VERSION 5.8 ;
BUSBITCHARS "[]" ;
DIVIDERCHAR "/" ;
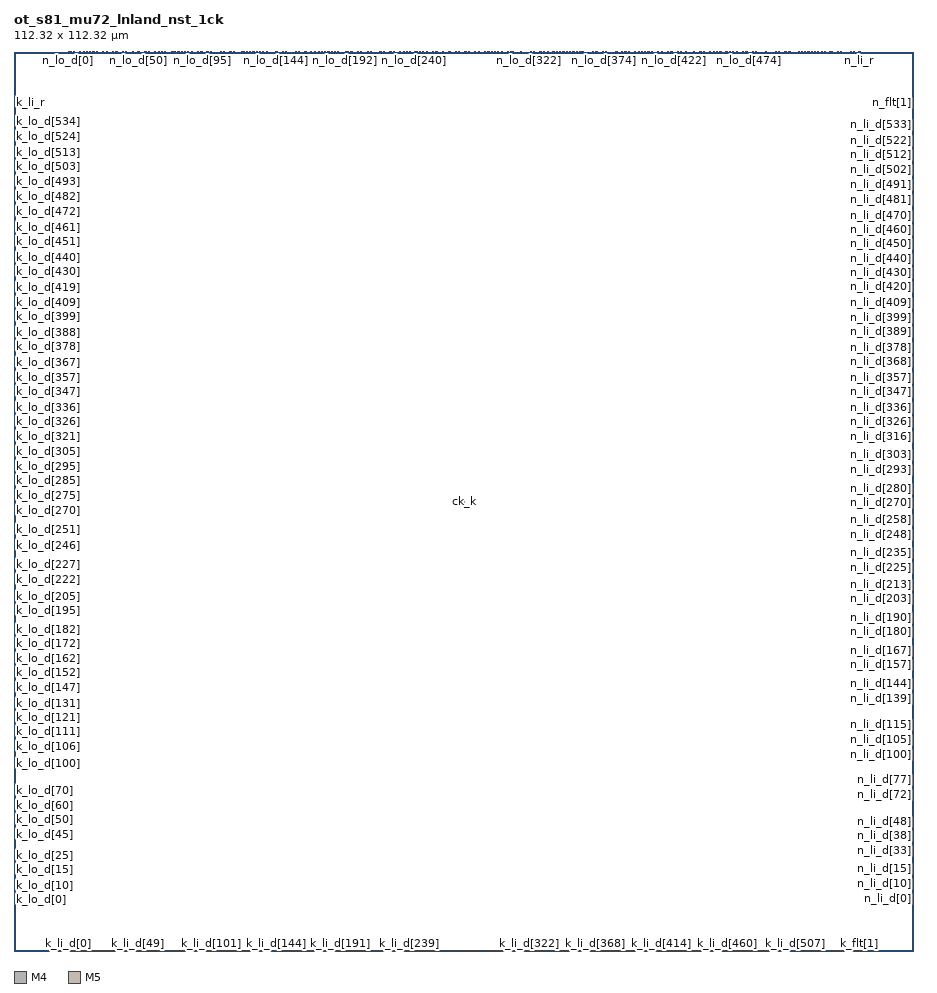
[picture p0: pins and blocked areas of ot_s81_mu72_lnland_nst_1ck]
MACRO ot_s81_mu72_lnland_nst_1ck
 CLASS BLOCK ;
 ORIGIN 0 0 ;
 SIZE 112.32 BY 112.32 ;
 SYMMETRY X Y ;
 PIN k_lo_v
  DIRECTION INPUT ;
  USE SIGNAL ;
  PORT
   LAYER M4 ;
   RECT 0.000000 6.236000 0.084000 6.268000 ;
  END
 END k_lo_v
 PIN k_lo_d[0]
  DIRECTION INPUT ;
  USE SIGNAL ;
  PORT
   LAYER M4 ;
   RECT 0.000000 6.380000 0.084000 6.412000 ;
  END
 END k_lo_d[0]
 PIN k_lo_d[1]
  DIRECTION INPUT ;
  USE SIGNAL ;
  PORT
   LAYER M4 ;
   RECT 0.000000 6.572000 0.084000 6.604000 ;
  END
 END k_lo_d[1]
 PIN k_lo_d[2]
  DIRECTION INPUT ;
  USE SIGNAL ;
  PORT
   LAYER M4 ;
   RECT 0.000000 6.764000 0.084000 6.796000 ;
  END
 END k_lo_d[2]
 PIN k_lo_d[3]
  DIRECTION INPUT ;
  USE SIGNAL ;
  PORT
   LAYER M4 ;
   RECT 0.000000 6.956000 0.084000 6.988000 ;
  END
 END k_lo_d[3]
 PIN k_lo_d[4]
  DIRECTION INPUT ;
  USE SIGNAL ;
  PORT
   LAYER M4 ;
   RECT 0.000000 7.100000 0.084000 7.132000 ;
  END
 END k_lo_d[4]
 PIN k_lo_d[5]
  DIRECTION INPUT ;
  USE SIGNAL ;
  PORT
   LAYER M4 ;
   RECT 0.000000 7.292000 0.084000 7.324000 ;
  END
 END k_lo_d[5]
 PIN k_lo_d[6]
  DIRECTION INPUT ;
  USE SIGNAL ;
  PORT
   LAYER M4 ;
   RECT 0.000000 7.484000 0.084000 7.516000 ;
  END
 END k_lo_d[6]
 PIN k_lo_d[7]
  DIRECTION INPUT ;
  USE SIGNAL ;
  PORT
   LAYER M4 ;
   RECT 0.000000 7.676000 0.084000 7.708000 ;
  END
 END k_lo_d[7]
 PIN k_lo_d[8]
  DIRECTION INPUT ;
  USE SIGNAL ;
  PORT
   LAYER M4 ;
   RECT 0.000000 7.820000 0.084000 7.852000 ;
  END
 END k_lo_d[8]
 PIN k_lo_d[9]
  DIRECTION INPUT ;
  USE SIGNAL ;
  PORT
   LAYER M4 ;
   RECT 0.000000 8.012000 0.084000 8.044000 ;
  END
 END k_lo_d[9]
 PIN k_lo_d[10]
  DIRECTION INPUT ;
  USE SIGNAL ;
  PORT
   LAYER M4 ;
   RECT 0.000000 8.204000 0.084000 8.236000 ;
  END
 END k_lo_d[10]
 PIN k_lo_d[11]
  DIRECTION INPUT ;
  USE SIGNAL ;
  PORT
   LAYER M4 ;
   RECT 0.000000 8.396000 0.084000 8.428000 ;
  END
 END k_lo_d[11]
 PIN k_lo_d[12]
  DIRECTION INPUT ;
  USE SIGNAL ;
  PORT
   LAYER M4 ;
   RECT 0.000000 8.540000 0.084000 8.572000 ;
  END
 END k_lo_d[12]
 PIN k_lo_d[13]
  DIRECTION INPUT ;
  USE SIGNAL ;
  PORT
   LAYER M4 ;
   RECT 0.000000 8.732000 0.084000 8.764000 ;
  END
 END k_lo_d[13]
 PIN k_lo_d[14]
  DIRECTION INPUT ;
  USE SIGNAL ;
  PORT
   LAYER M4 ;
   RECT 0.000000 8.924000 0.084000 8.956000 ;
  END
 END k_lo_d[14]
 PIN k_lo_d[15]
  DIRECTION INPUT ;
  USE SIGNAL ;
  PORT
   LAYER M4 ;
   RECT 0.000000 9.116000 0.084000 9.148000 ;
  END
 END k_lo_d[15]
 PIN k_lo_d[16]
  DIRECTION INPUT ;
  USE SIGNAL ;
  PORT
   LAYER M4 ;
   RECT 0.000000 9.260000 0.084000 9.292000 ;
  END
 END k_lo_d[16]
 PIN k_lo_d[17]
  DIRECTION INPUT ;
  USE SIGNAL ;
  PORT
   LAYER M4 ;
   RECT 0.000000 9.452000 0.084000 9.484000 ;
  END
 END k_lo_d[17]
 PIN k_lo_d[18]
  DIRECTION INPUT ;
  USE SIGNAL ;
  PORT
   LAYER M4 ;
   RECT 0.000000 9.644000 0.084000 9.676000 ;
  END
 END k_lo_d[18]
 PIN k_lo_d[19]
  DIRECTION INPUT ;
  USE SIGNAL ;
  PORT
   LAYER M4 ;
   RECT 0.000000 9.836000 0.084000 9.868000 ;
  END
 END k_lo_d[19]
 PIN k_lo_d[20]
  DIRECTION INPUT ;
  USE SIGNAL ;
  PORT
   LAYER M4 ;
   RECT 0.000000 9.980000 0.084000 10.012000 ;
  END
 END k_lo_d[20]
 PIN k_lo_d[21]
  DIRECTION INPUT ;
  USE SIGNAL ;
  PORT
   LAYER M4 ;
   RECT 0.000000 10.172000 0.084000 10.204000 ;
  END
 END k_lo_d[21]
 PIN k_lo_d[22]
  DIRECTION INPUT ;
  USE SIGNAL ;
  PORT
   LAYER M4 ;
   RECT 0.000000 10.364000 0.084000 10.396000 ;
  END
 END k_lo_d[22]
 PIN k_lo_d[23]
  DIRECTION INPUT ;
  USE SIGNAL ;
  PORT
   LAYER M4 ;
   RECT 0.000000 10.556000 0.084000 10.588000 ;
  END
 END k_lo_d[23]
 PIN k_lo_d[24]
  DIRECTION INPUT ;
  USE SIGNAL ;
  PORT
   LAYER M4 ;
   RECT 0.000000 10.700000 0.084000 10.732000 ;
  END
 END k_lo_d[24]
 PIN k_lo_d[25]
  DIRECTION INPUT ;
  USE SIGNAL ;
  PORT
   LAYER M4 ;
   RECT 0.000000 10.892000 0.084000 10.924000 ;
  END
 END k_lo_d[25]
 PIN k_lo_d[26]
  DIRECTION INPUT ;
  USE SIGNAL ;
  PORT
   LAYER M4 ;
   RECT 0.000000 11.084000 0.084000 11.116000 ;
  END
 END k_lo_d[26]
 PIN k_lo_d[27]
  DIRECTION INPUT ;
  USE SIGNAL ;
  PORT
   LAYER M4 ;
   RECT 0.000000 11.276000 0.084000 11.308000 ;
  END
 END k_lo_d[27]
 PIN k_lo_d[28]
  DIRECTION INPUT ;
  USE SIGNAL ;
  PORT
   LAYER M4 ;
   RECT 0.000000 11.420000 0.084000 11.452000 ;
  END
 END k_lo_d[28]
 PIN k_lo_d[29]
  DIRECTION INPUT ;
  USE SIGNAL ;
  PORT
   LAYER M4 ;
   RECT 0.000000 11.612000 0.084000 11.644000 ;
  END
 END k_lo_d[29]
 PIN k_lo_d[30]
  DIRECTION INPUT ;
  USE SIGNAL ;
  PORT
   LAYER M4 ;
   RECT 0.000000 11.804000 0.084000 11.836000 ;
  END
 END k_lo_d[30]
 PIN k_lo_d[31]
  DIRECTION INPUT ;
  USE SIGNAL ;
  PORT
   LAYER M4 ;
   RECT 0.000000 11.996000 0.084000 12.028000 ;
  END
 END k_lo_d[31]
 PIN k_lo_d[32]
  DIRECTION INPUT ;
  USE SIGNAL ;
  PORT
   LAYER M4 ;
   RECT 0.000000 12.140000 0.084000 12.172000 ;
  END
 END k_lo_d[32]
 PIN k_lo_d[33]
  DIRECTION INPUT ;
  USE SIGNAL ;
  PORT
   LAYER M4 ;
   RECT 0.000000 12.332000 0.084000 12.364000 ;
  END
 END k_lo_d[33]
 PIN k_lo_d[34]
  DIRECTION INPUT ;
  USE SIGNAL ;
  PORT
   LAYER M4 ;
   RECT 0.000000 12.524000 0.084000 12.556000 ;
  END
 END k_lo_d[34]
 PIN k_lo_d[35]
  DIRECTION INPUT ;
  USE SIGNAL ;
  PORT
   LAYER M4 ;
   RECT 0.000000 12.716000 0.084000 12.748000 ;
  END
 END k_lo_d[35]
 PIN k_lo_d[36]
  DIRECTION INPUT ;
  USE SIGNAL ;
  PORT
   LAYER M4 ;
   RECT 0.000000 12.860000 0.084000 12.892000 ;
  END
 END k_lo_d[36]
 PIN k_lo_d[37]
  DIRECTION INPUT ;
  USE SIGNAL ;
  PORT
   LAYER M4 ;
   RECT 0.000000 13.052000 0.084000 13.084000 ;
  END
 END k_lo_d[37]
 PIN k_lo_d[38]
  DIRECTION INPUT ;
  USE SIGNAL ;
  PORT
   LAYER M4 ;
   RECT 0.000000 13.244000 0.084000 13.276000 ;
  END
 END k_lo_d[38]
 PIN k_lo_d[39]
  DIRECTION INPUT ;
  USE SIGNAL ;
  PORT
   LAYER M4 ;
   RECT 0.000000 13.436000 0.084000 13.468000 ;
  END
 END k_lo_d[39]
 PIN k_lo_d[40]
  DIRECTION INPUT ;
  USE SIGNAL ;
  PORT
   LAYER M4 ;
   RECT 0.000000 13.580000 0.084000 13.612000 ;
  END
 END k_lo_d[40]
 PIN k_lo_d[41]
  DIRECTION INPUT ;
  USE SIGNAL ;
  PORT
   LAYER M4 ;
   RECT 0.000000 13.772000 0.084000 13.804000 ;
  END
 END k_lo_d[41]
 PIN k_lo_d[42]
  DIRECTION INPUT ;
  USE SIGNAL ;
  PORT
   LAYER M4 ;
   RECT 0.000000 13.964000 0.084000 13.996000 ;
  END
 END k_lo_d[42]
 PIN k_lo_d[43]
  DIRECTION INPUT ;
  USE SIGNAL ;
  PORT
   LAYER M4 ;
   RECT 0.000000 14.156000 0.084000 14.188000 ;
  END
 END k_lo_d[43]
 PIN k_lo_d[44]
  DIRECTION INPUT ;
  USE SIGNAL ;
  PORT
   LAYER M4 ;
   RECT 0.000000 14.300000 0.084000 14.332000 ;
  END
 END k_lo_d[44]
 PIN k_lo_d[45]
  DIRECTION INPUT ;
  USE SIGNAL ;
  PORT
   LAYER M4 ;
   RECT 0.000000 14.492000 0.084000 14.524000 ;
  END
 END k_lo_d[45]
 PIN k_lo_d[46]
  DIRECTION INPUT ;
  USE SIGNAL ;
  PORT
   LAYER M4 ;
   RECT 0.000000 14.684000 0.084000 14.716000 ;
  END
 END k_lo_d[46]
 PIN k_lo_d[47]
  DIRECTION INPUT ;
  USE SIGNAL ;
  PORT
   LAYER M4 ;
   RECT 0.000000 14.876000 0.084000 14.908000 ;
  END
 END k_lo_d[47]
 PIN k_lo_d[48]
  DIRECTION INPUT ;
  USE SIGNAL ;
  PORT
   LAYER M4 ;
   RECT 0.000000 15.020000 0.084000 15.052000 ;
  END
 END k_lo_d[48]
 PIN k_lo_d[49]
  DIRECTION INPUT ;
  USE SIGNAL ;
  PORT
   LAYER M4 ;
   RECT 0.000000 15.212000 0.084000 15.244000 ;
  END
 END k_lo_d[49]
 PIN k_lo_d[50]
  DIRECTION INPUT ;
  USE SIGNAL ;
  PORT
   LAYER M4 ;
   RECT 0.000000 15.404000 0.084000 15.436000 ;
  END
 END k_lo_d[50]
 PIN k_lo_d[51]
  DIRECTION INPUT ;
  USE SIGNAL ;
  PORT
   LAYER M4 ;
   RECT 0.000000 15.596000 0.084000 15.628000 ;
  END
 END k_lo_d[51]
 PIN k_lo_d[52]
  DIRECTION INPUT ;
  USE SIGNAL ;
  PORT
   LAYER M4 ;
   RECT 0.000000 15.740000 0.084000 15.772000 ;
  END
 END k_lo_d[52]
 PIN k_lo_d[53]
  DIRECTION INPUT ;
  USE SIGNAL ;
  PORT
   LAYER M4 ;
   RECT 0.000000 15.932000 0.084000 15.964000 ;
  END
 END k_lo_d[53]
 PIN k_lo_d[54]
  DIRECTION INPUT ;
  USE SIGNAL ;
  PORT
   LAYER M4 ;
   RECT 0.000000 16.124000 0.084000 16.156000 ;
  END
 END k_lo_d[54]
 PIN k_lo_d[55]
  DIRECTION INPUT ;
  USE SIGNAL ;
  PORT
   LAYER M4 ;
   RECT 0.000000 16.316000 0.084000 16.348000 ;
  END
 END k_lo_d[55]
 PIN k_lo_d[56]
  DIRECTION INPUT ;
  USE SIGNAL ;
  PORT
   LAYER M4 ;
   RECT 0.000000 16.460000 0.084000 16.492000 ;
  END
 END k_lo_d[56]
 PIN k_lo_d[57]
  DIRECTION INPUT ;
  USE SIGNAL ;
  PORT
   LAYER M4 ;
   RECT 0.000000 16.652000 0.084000 16.684000 ;
  END
 END k_lo_d[57]
 PIN k_lo_d[58]
  DIRECTION INPUT ;
  USE SIGNAL ;
  PORT
   LAYER M4 ;
   RECT 0.000000 16.844000 0.084000 16.876000 ;
  END
 END k_lo_d[58]
 PIN k_lo_d[59]
  DIRECTION INPUT ;
  USE SIGNAL ;
  PORT
   LAYER M4 ;
   RECT 0.000000 17.036000 0.084000 17.068000 ;
  END
 END k_lo_d[59]
 PIN k_lo_d[60]
  DIRECTION INPUT ;
  USE SIGNAL ;
  PORT
   LAYER M4 ;
   RECT 0.000000 17.180000 0.084000 17.212000 ;
  END
 END k_lo_d[60]
 PIN k_lo_d[61]
  DIRECTION INPUT ;
  USE SIGNAL ;
  PORT
   LAYER M4 ;
   RECT 0.000000 17.372000 0.084000 17.404000 ;
  END
 END k_lo_d[61]
 PIN k_lo_d[62]
  DIRECTION INPUT ;
  USE SIGNAL ;
  PORT
   LAYER M4 ;
   RECT 0.000000 17.564000 0.084000 17.596000 ;
  END
 END k_lo_d[62]
 PIN k_lo_d[63]
  DIRECTION INPUT ;
  USE SIGNAL ;
  PORT
   LAYER M4 ;
   RECT 0.000000 17.756000 0.084000 17.788000 ;
  END
 END k_lo_d[63]
 PIN k_lo_d[64]
  DIRECTION INPUT ;
  USE SIGNAL ;
  PORT
   LAYER M4 ;
   RECT 0.000000 17.900000 0.084000 17.932000 ;
  END
 END k_lo_d[64]
 PIN k_lo_d[65]
  DIRECTION INPUT ;
  USE SIGNAL ;
  PORT
   LAYER M4 ;
   RECT 0.000000 18.092000 0.084000 18.124000 ;
  END
 END k_lo_d[65]
 PIN k_lo_d[66]
  DIRECTION INPUT ;
  USE SIGNAL ;
  PORT
   LAYER M4 ;
   RECT 0.000000 18.284000 0.084000 18.316000 ;
  END
 END k_lo_d[66]
 PIN k_lo_d[67]
  DIRECTION INPUT ;
  USE SIGNAL ;
  PORT
   LAYER M4 ;
   RECT 0.000000 18.476000 0.084000 18.508000 ;
  END
 END k_lo_d[67]
 PIN k_lo_d[68]
  DIRECTION INPUT ;
  USE SIGNAL ;
  PORT
   LAYER M4 ;
   RECT 0.000000 18.620000 0.084000 18.652000 ;
  END
 END k_lo_d[68]
 PIN k_lo_d[69]
  DIRECTION INPUT ;
  USE SIGNAL ;
  PORT
   LAYER M4 ;
   RECT 0.000000 18.812000 0.084000 18.844000 ;
  END
 END k_lo_d[69]
 PIN k_lo_d[70]
  DIRECTION INPUT ;
  USE SIGNAL ;
  PORT
   LAYER M4 ;
   RECT 0.000000 19.004000 0.084000 19.036000 ;
  END
 END k_lo_d[70]
 PIN k_lo_d[71]
  DIRECTION INPUT ;
  USE SIGNAL ;
  PORT
   LAYER M4 ;
   RECT 0.000000 19.148000 0.084000 19.180000 ;
  END
 END k_lo_d[71]
 PIN k_lo_d[72]
  DIRECTION INPUT ;
  USE SIGNAL ;
  PORT
   LAYER M4 ;
   RECT 0.000000 19.340000 0.084000 19.372000 ;
  END
 END k_lo_d[72]
 PIN k_lo_d[73]
  DIRECTION INPUT ;
  USE SIGNAL ;
  PORT
   LAYER M4 ;
   RECT 0.000000 19.532000 0.084000 19.564000 ;
  END
 END k_lo_d[73]
 PIN k_lo_d[74]
  DIRECTION INPUT ;
  USE SIGNAL ;
  PORT
   LAYER M4 ;
   RECT 0.000000 19.724000 0.084000 19.756000 ;
  END
 END k_lo_d[74]
 PIN k_lo_d[75]
  DIRECTION INPUT ;
  USE SIGNAL ;
  PORT
   LAYER M4 ;
   RECT 0.000000 19.868000 0.084000 19.900000 ;
  END
 END k_lo_d[75]
 PIN k_lo_d[76]
  DIRECTION INPUT ;
  USE SIGNAL ;
  PORT
   LAYER M4 ;
   RECT 0.000000 20.060000 0.084000 20.092000 ;
  END
 END k_lo_d[76]
 PIN k_lo_d[77]
  DIRECTION INPUT ;
  USE SIGNAL ;
  PORT
   LAYER M4 ;
   RECT 0.000000 20.252000 0.084000 20.284000 ;
  END
 END k_lo_d[77]
 PIN k_lo_d[78]
  DIRECTION INPUT ;
  USE SIGNAL ;
  PORT
   LAYER M4 ;
   RECT 0.000000 20.444000 0.084000 20.476000 ;
  END
 END k_lo_d[78]
 PIN k_lo_d[79]
  DIRECTION INPUT ;
  USE SIGNAL ;
  PORT
   LAYER M4 ;
   RECT 0.000000 20.588000 0.084000 20.620000 ;
  END
 END k_lo_d[79]
 PIN k_lo_d[80]
  DIRECTION INPUT ;
  USE SIGNAL ;
  PORT
   LAYER M4 ;
   RECT 0.000000 20.780000 0.084000 20.812000 ;
  END
 END k_lo_d[80]
 PIN k_lo_d[81]
  DIRECTION INPUT ;
  USE SIGNAL ;
  PORT
   LAYER M4 ;
   RECT 0.000000 20.972000 0.084000 21.004000 ;
  END
 END k_lo_d[81]
 PIN k_lo_d[82]
  DIRECTION INPUT ;
  USE SIGNAL ;
  PORT
   LAYER M4 ;
   RECT 0.000000 21.164000 0.084000 21.196000 ;
  END
 END k_lo_d[82]
 PIN k_lo_d[83]
  DIRECTION INPUT ;
  USE SIGNAL ;
  PORT
   LAYER M4 ;
   RECT 0.000000 21.308000 0.084000 21.340000 ;
  END
 END k_lo_d[83]
 PIN k_lo_d[84]
  DIRECTION INPUT ;
  USE SIGNAL ;
  PORT
   LAYER M4 ;
   RECT 0.000000 21.500000 0.084000 21.532000 ;
  END
 END k_lo_d[84]
 PIN k_lo_d[85]
  DIRECTION INPUT ;
  USE SIGNAL ;
  PORT
   LAYER M4 ;
   RECT 0.000000 21.692000 0.084000 21.724000 ;
  END
 END k_lo_d[85]
 PIN k_lo_d[86]
  DIRECTION INPUT ;
  USE SIGNAL ;
  PORT
   LAYER M4 ;
   RECT 0.000000 21.884000 0.084000 21.916000 ;
  END
 END k_lo_d[86]
 PIN k_lo_d[87]
  DIRECTION INPUT ;
  USE SIGNAL ;
  PORT
   LAYER M4 ;
   RECT 0.000000 22.028000 0.084000 22.060000 ;
  END
 END k_lo_d[87]
 PIN k_lo_d[88]
  DIRECTION INPUT ;
  USE SIGNAL ;
  PORT
   LAYER M4 ;
   RECT 0.000000 22.220000 0.084000 22.252000 ;
  END
 END k_lo_d[88]
 PIN k_lo_d[89]
  DIRECTION INPUT ;
  USE SIGNAL ;
  PORT
   LAYER M4 ;
   RECT 0.000000 22.412000 0.084000 22.444000 ;
  END
 END k_lo_d[89]
 PIN k_lo_d[90]
  DIRECTION INPUT ;
  USE SIGNAL ;
  PORT
   LAYER M4 ;
   RECT 0.000000 22.604000 0.084000 22.636000 ;
  END
 END k_lo_d[90]
 PIN k_lo_d[91]
  DIRECTION INPUT ;
  USE SIGNAL ;
  PORT
   LAYER M4 ;
   RECT 0.000000 22.748000 0.084000 22.780000 ;
  END
 END k_lo_d[91]
 PIN k_lo_d[92]
  DIRECTION INPUT ;
  USE SIGNAL ;
  PORT
   LAYER M4 ;
   RECT 0.000000 22.940000 0.084000 22.972000 ;
  END
 END k_lo_d[92]
 PIN k_lo_d[93]
  DIRECTION INPUT ;
  USE SIGNAL ;
  PORT
   LAYER M4 ;
   RECT 0.000000 23.132000 0.084000 23.164000 ;
  END
 END k_lo_d[93]
 PIN k_lo_d[94]
  DIRECTION INPUT ;
  USE SIGNAL ;
  PORT
   LAYER M4 ;
   RECT 0.000000 23.324000 0.084000 23.356000 ;
  END
 END k_lo_d[94]
 PIN k_lo_d[95]
  DIRECTION INPUT ;
  USE SIGNAL ;
  PORT
   LAYER M4 ;
   RECT 0.000000 23.468000 0.084000 23.500000 ;
  END
 END k_lo_d[95]
 PIN k_lo_d[96]
  DIRECTION INPUT ;
  USE SIGNAL ;
  PORT
   LAYER M4 ;
   RECT 0.000000 23.660000 0.084000 23.692000 ;
  END
 END k_lo_d[96]
 PIN k_lo_d[97]
  DIRECTION INPUT ;
  USE SIGNAL ;
  PORT
   LAYER M4 ;
   RECT 0.000000 23.852000 0.084000 23.884000 ;
  END
 END k_lo_d[97]
 PIN k_lo_d[98]
  DIRECTION INPUT ;
  USE SIGNAL ;
  PORT
   LAYER M4 ;
   RECT 0.000000 24.044000 0.084000 24.076000 ;
  END
 END k_lo_d[98]
 PIN k_lo_d[99]
  DIRECTION INPUT ;
  USE SIGNAL ;
  PORT
   LAYER M4 ;
   RECT 0.000000 24.188000 0.084000 24.220000 ;
  END
 END k_lo_d[99]
 PIN k_lo_d[100]
  DIRECTION INPUT ;
  USE SIGNAL ;
  PORT
   LAYER M4 ;
   RECT 0.000000 24.380000 0.084000 24.412000 ;
  END
 END k_lo_d[100]
 PIN k_lo_d[101]
  DIRECTION INPUT ;
  USE SIGNAL ;
  PORT
   LAYER M4 ;
   RECT 0.000000 24.572000 0.084000 24.604000 ;
  END
 END k_lo_d[101]
 PIN k_lo_d[102]
  DIRECTION INPUT ;
  USE SIGNAL ;
  PORT
   LAYER M4 ;
   RECT 0.000000 24.764000 0.084000 24.796000 ;
  END
 END k_lo_d[102]
 PIN k_lo_d[103]
  DIRECTION INPUT ;
  USE SIGNAL ;
  PORT
   LAYER M4 ;
   RECT 0.000000 24.908000 0.084000 24.940000 ;
  END
 END k_lo_d[103]
 PIN k_lo_d[104]
  DIRECTION INPUT ;
  USE SIGNAL ;
  PORT
   LAYER M4 ;
   RECT 0.000000 25.100000 0.084000 25.132000 ;
  END
 END k_lo_d[104]
 PIN k_lo_d[105]
  DIRECTION INPUT ;
  USE SIGNAL ;
  PORT
   LAYER M4 ;
   RECT 0.000000 25.292000 0.084000 25.324000 ;
  END
 END k_lo_d[105]
 PIN k_lo_d[106]
  DIRECTION INPUT ;
  USE SIGNAL ;
  PORT
   LAYER M4 ;
   RECT 0.000000 25.484000 0.084000 25.516000 ;
  END
 END k_lo_d[106]
 PIN k_lo_d[107]
  DIRECTION INPUT ;
  USE SIGNAL ;
  PORT
   LAYER M4 ;
   RECT 0.000000 25.628000 0.084000 25.660000 ;
  END
 END k_lo_d[107]
 PIN k_lo_d[108]
  DIRECTION INPUT ;
  USE SIGNAL ;
  PORT
   LAYER M4 ;
   RECT 0.000000 25.820000 0.084000 25.852000 ;
  END
 END k_lo_d[108]
 PIN k_lo_d[109]
  DIRECTION INPUT ;
  USE SIGNAL ;
  PORT
   LAYER M4 ;
   RECT 0.000000 26.012000 0.084000 26.044000 ;
  END
 END k_lo_d[109]
 PIN k_lo_d[110]
  DIRECTION INPUT ;
  USE SIGNAL ;
  PORT
   LAYER M4 ;
   RECT 0.000000 26.204000 0.084000 26.236000 ;
  END
 END k_lo_d[110]
 PIN k_lo_d[111]
  DIRECTION INPUT ;
  USE SIGNAL ;
  PORT
   LAYER M4 ;
   RECT 0.000000 26.348000 0.084000 26.380000 ;
  END
 END k_lo_d[111]
 PIN k_lo_d[112]
  DIRECTION INPUT ;
  USE SIGNAL ;
  PORT
   LAYER M4 ;
   RECT 0.000000 26.540000 0.084000 26.572000 ;
  END
 END k_lo_d[112]
 PIN k_lo_d[113]
  DIRECTION INPUT ;
  USE SIGNAL ;
  PORT
   LAYER M4 ;
   RECT 0.000000 26.732000 0.084000 26.764000 ;
  END
 END k_lo_d[113]
 PIN k_lo_d[114]
  DIRECTION INPUT ;
  USE SIGNAL ;
  PORT
   LAYER M4 ;
   RECT 0.000000 26.924000 0.084000 26.956000 ;
  END
 END k_lo_d[114]
 PIN k_lo_d[115]
  DIRECTION INPUT ;
  USE SIGNAL ;
  PORT
   LAYER M4 ;
   RECT 0.000000 27.068000 0.084000 27.100000 ;
  END
 END k_lo_d[115]
 PIN k_lo_d[116]
  DIRECTION INPUT ;
  USE SIGNAL ;
  PORT
   LAYER M4 ;
   RECT 0.000000 27.260000 0.084000 27.292000 ;
  END
 END k_lo_d[116]
 PIN k_lo_d[117]
  DIRECTION INPUT ;
  USE SIGNAL ;
  PORT
   LAYER M4 ;
   RECT 0.000000 27.452000 0.084000 27.484000 ;
  END
 END k_lo_d[117]
 PIN k_lo_d[118]
  DIRECTION INPUT ;
  USE SIGNAL ;
  PORT
   LAYER M4 ;
   RECT 0.000000 27.644000 0.084000 27.676000 ;
  END
 END k_lo_d[118]
 PIN k_lo_d[119]
  DIRECTION INPUT ;
  USE SIGNAL ;
  PORT
   LAYER M4 ;
   RECT 0.000000 27.788000 0.084000 27.820000 ;
  END
 END k_lo_d[119]
 PIN k_lo_d[120]
  DIRECTION INPUT ;
  USE SIGNAL ;
  PORT
   LAYER M4 ;
   RECT 0.000000 27.980000 0.084000 28.012000 ;
  END
 END k_lo_d[120]
 PIN k_lo_d[121]
  DIRECTION INPUT ;
  USE SIGNAL ;
  PORT
   LAYER M4 ;
   RECT 0.000000 28.172000 0.084000 28.204000 ;
  END
 END k_lo_d[121]
 PIN k_lo_d[122]
  DIRECTION INPUT ;
  USE SIGNAL ;
  PORT
   LAYER M4 ;
   RECT 0.000000 28.364000 0.084000 28.396000 ;
  END
 END k_lo_d[122]
 PIN k_lo_d[123]
  DIRECTION INPUT ;
  USE SIGNAL ;
  PORT
   LAYER M4 ;
   RECT 0.000000 28.508000 0.084000 28.540000 ;
  END
 END k_lo_d[123]
 PIN k_lo_d[124]
  DIRECTION INPUT ;
  USE SIGNAL ;
  PORT
   LAYER M4 ;
   RECT 0.000000 28.700000 0.084000 28.732000 ;
  END
 END k_lo_d[124]
 PIN k_lo_d[125]
  DIRECTION INPUT ;
  USE SIGNAL ;
  PORT
   LAYER M4 ;
   RECT 0.000000 28.892000 0.084000 28.924000 ;
  END
 END k_lo_d[125]
 PIN k_lo_d[126]
  DIRECTION INPUT ;
  USE SIGNAL ;
  PORT
   LAYER M4 ;
   RECT 0.000000 29.084000 0.084000 29.116000 ;
  END
 END k_lo_d[126]
 PIN k_lo_d[127]
  DIRECTION INPUT ;
  USE SIGNAL ;
  PORT
   LAYER M4 ;
   RECT 0.000000 29.228000 0.084000 29.260000 ;
  END
 END k_lo_d[127]
 PIN k_lo_d[128]
  DIRECTION INPUT ;
  USE SIGNAL ;
  PORT
   LAYER M4 ;
   RECT 0.000000 29.420000 0.084000 29.452000 ;
  END
 END k_lo_d[128]
 PIN k_lo_d[129]
  DIRECTION INPUT ;
  USE SIGNAL ;
  PORT
   LAYER M4 ;
   RECT 0.000000 29.612000 0.084000 29.644000 ;
  END
 END k_lo_d[129]
 PIN k_lo_d[130]
  DIRECTION INPUT ;
  USE SIGNAL ;
  PORT
   LAYER M4 ;
   RECT 0.000000 29.804000 0.084000 29.836000 ;
  END
 END k_lo_d[130]
 PIN k_lo_d[131]
  DIRECTION INPUT ;
  USE SIGNAL ;
  PORT
   LAYER M4 ;
   RECT 0.000000 29.948000 0.084000 29.980000 ;
  END
 END k_lo_d[131]
 PIN k_lo_d[132]
  DIRECTION INPUT ;
  USE SIGNAL ;
  PORT
   LAYER M4 ;
   RECT 0.000000 30.140000 0.084000 30.172000 ;
  END
 END k_lo_d[132]
 PIN k_lo_d[133]
  DIRECTION INPUT ;
  USE SIGNAL ;
  PORT
   LAYER M4 ;
   RECT 0.000000 30.332000 0.084000 30.364000 ;
  END
 END k_lo_d[133]
 PIN k_lo_d[134]
  DIRECTION INPUT ;
  USE SIGNAL ;
  PORT
   LAYER M4 ;
   RECT 0.000000 30.524000 0.084000 30.556000 ;
  END
 END k_lo_d[134]
 PIN k_lo_d[135]
  DIRECTION INPUT ;
  USE SIGNAL ;
  PORT
   LAYER M4 ;
   RECT 0.000000 30.668000 0.084000 30.700000 ;
  END
 END k_lo_d[135]
 PIN k_lo_d[136]
  DIRECTION INPUT ;
  USE SIGNAL ;
  PORT
   LAYER M4 ;
   RECT 0.000000 30.860000 0.084000 30.892000 ;
  END
 END k_lo_d[136]
 PIN k_lo_d[137]
  DIRECTION INPUT ;
  USE SIGNAL ;
  PORT
   LAYER M4 ;
   RECT 0.000000 31.052000 0.084000 31.084000 ;
  END
 END k_lo_d[137]
 PIN k_lo_d[138]
  DIRECTION INPUT ;
  USE SIGNAL ;
  PORT
   LAYER M4 ;
   RECT 0.000000 31.244000 0.084000 31.276000 ;
  END
 END k_lo_d[138]
 PIN k_lo_d[139]
  DIRECTION INPUT ;
  USE SIGNAL ;
  PORT
   LAYER M4 ;
   RECT 0.000000 31.388000 0.084000 31.420000 ;
  END
 END k_lo_d[139]
 PIN k_lo_d[140]
  DIRECTION INPUT ;
  USE SIGNAL ;
  PORT
   LAYER M4 ;
   RECT 0.000000 31.580000 0.084000 31.612000 ;
  END
 END k_lo_d[140]
 PIN k_lo_d[141]
  DIRECTION INPUT ;
  USE SIGNAL ;
  PORT
   LAYER M4 ;
   RECT 0.000000 31.772000 0.084000 31.804000 ;
  END
 END k_lo_d[141]
 PIN k_lo_d[142]
  DIRECTION INPUT ;
  USE SIGNAL ;
  PORT
   LAYER M4 ;
   RECT 0.000000 31.964000 0.084000 31.996000 ;
  END
 END k_lo_d[142]
 PIN k_lo_d[143]
  DIRECTION INPUT ;
  USE SIGNAL ;
  PORT
   LAYER M4 ;
   RECT 0.000000 32.108000 0.084000 32.140000 ;
  END
 END k_lo_d[143]
 PIN k_lo_d[144]
  DIRECTION INPUT ;
  USE SIGNAL ;
  PORT
   LAYER M4 ;
   RECT 0.000000 32.300000 0.084000 32.332000 ;
  END
 END k_lo_d[144]
 PIN k_lo_d[145]
  DIRECTION INPUT ;
  USE SIGNAL ;
  PORT
   LAYER M4 ;
   RECT 0.000000 32.492000 0.084000 32.524000 ;
  END
 END k_lo_d[145]
 PIN k_lo_d[146]
  DIRECTION INPUT ;
  USE SIGNAL ;
  PORT
   LAYER M4 ;
   RECT 0.000000 32.684000 0.084000 32.716000 ;
  END
 END k_lo_d[146]
 PIN k_lo_d[147]
  DIRECTION INPUT ;
  USE SIGNAL ;
  PORT
   LAYER M4 ;
   RECT 0.000000 32.828000 0.084000 32.860000 ;
  END
 END k_lo_d[147]
 PIN k_lo_d[148]
  DIRECTION INPUT ;
  USE SIGNAL ;
  PORT
   LAYER M4 ;
   RECT 0.000000 33.020000 0.084000 33.052000 ;
  END
 END k_lo_d[148]
 PIN k_lo_d[149]
  DIRECTION INPUT ;
  USE SIGNAL ;
  PORT
   LAYER M4 ;
   RECT 0.000000 33.212000 0.084000 33.244000 ;
  END
 END k_lo_d[149]
 PIN k_lo_d[150]
  DIRECTION INPUT ;
  USE SIGNAL ;
  PORT
   LAYER M4 ;
   RECT 0.000000 33.404000 0.084000 33.436000 ;
  END
 END k_lo_d[150]
 PIN k_lo_d[151]
  DIRECTION INPUT ;
  USE SIGNAL ;
  PORT
   LAYER M4 ;
   RECT 0.000000 33.548000 0.084000 33.580000 ;
  END
 END k_lo_d[151]
 PIN k_lo_d[152]
  DIRECTION INPUT ;
  USE SIGNAL ;
  PORT
   LAYER M4 ;
   RECT 0.000000 33.740000 0.084000 33.772000 ;
  END
 END k_lo_d[152]
 PIN k_lo_d[153]
  DIRECTION INPUT ;
  USE SIGNAL ;
  PORT
   LAYER M4 ;
   RECT 0.000000 33.932000 0.084000 33.964000 ;
  END
 END k_lo_d[153]
 PIN k_lo_d[154]
  DIRECTION INPUT ;
  USE SIGNAL ;
  PORT
   LAYER M4 ;
   RECT 0.000000 34.124000 0.084000 34.156000 ;
  END
 END k_lo_d[154]
 PIN k_lo_d[155]
  DIRECTION INPUT ;
  USE SIGNAL ;
  PORT
   LAYER M4 ;
   RECT 0.000000 34.268000 0.084000 34.300000 ;
  END
 END k_lo_d[155]
 PIN k_lo_d[156]
  DIRECTION INPUT ;
  USE SIGNAL ;
  PORT
   LAYER M4 ;
   RECT 0.000000 34.460000 0.084000 34.492000 ;
  END
 END k_lo_d[156]
 PIN k_lo_d[157]
  DIRECTION INPUT ;
  USE SIGNAL ;
  PORT
   LAYER M4 ;
   RECT 0.000000 34.652000 0.084000 34.684000 ;
  END
 END k_lo_d[157]
 PIN k_lo_d[158]
  DIRECTION INPUT ;
  USE SIGNAL ;
  PORT
   LAYER M4 ;
   RECT 0.000000 34.844000 0.084000 34.876000 ;
  END
 END k_lo_d[158]
 PIN k_lo_d[159]
  DIRECTION INPUT ;
  USE SIGNAL ;
  PORT
   LAYER M4 ;
   RECT 0.000000 34.988000 0.084000 35.020000 ;
  END
 END k_lo_d[159]
 PIN k_lo_d[160]
  DIRECTION INPUT ;
  USE SIGNAL ;
  PORT
   LAYER M4 ;
   RECT 0.000000 35.180000 0.084000 35.212000 ;
  END
 END k_lo_d[160]
 PIN k_lo_d[161]
  DIRECTION INPUT ;
  USE SIGNAL ;
  PORT
   LAYER M4 ;
   RECT 0.000000 35.372000 0.084000 35.404000 ;
  END
 END k_lo_d[161]
 PIN k_lo_d[162]
  DIRECTION INPUT ;
  USE SIGNAL ;
  PORT
   LAYER M4 ;
   RECT 0.000000 35.564000 0.084000 35.596000 ;
  END
 END k_lo_d[162]
 PIN k_lo_d[163]
  DIRECTION INPUT ;
  USE SIGNAL ;
  PORT
   LAYER M4 ;
   RECT 0.000000 35.708000 0.084000 35.740000 ;
  END
 END k_lo_d[163]
 PIN k_lo_d[164]
  DIRECTION INPUT ;
  USE SIGNAL ;
  PORT
   LAYER M4 ;
   RECT 0.000000 35.900000 0.084000 35.932000 ;
  END
 END k_lo_d[164]
 PIN k_lo_d[165]
  DIRECTION INPUT ;
  USE SIGNAL ;
  PORT
   LAYER M4 ;
   RECT 0.000000 36.092000 0.084000 36.124000 ;
  END
 END k_lo_d[165]
 PIN k_lo_d[166]
  DIRECTION INPUT ;
  USE SIGNAL ;
  PORT
   LAYER M4 ;
   RECT 0.000000 36.284000 0.084000 36.316000 ;
  END
 END k_lo_d[166]
 PIN k_lo_d[167]
  DIRECTION INPUT ;
  USE SIGNAL ;
  PORT
   LAYER M4 ;
   RECT 0.000000 36.428000 0.084000 36.460000 ;
  END
 END k_lo_d[167]
 PIN k_lo_d[168]
  DIRECTION INPUT ;
  USE SIGNAL ;
  PORT
   LAYER M4 ;
   RECT 0.000000 36.620000 0.084000 36.652000 ;
  END
 END k_lo_d[168]
 PIN k_lo_d[169]
  DIRECTION INPUT ;
  USE SIGNAL ;
  PORT
   LAYER M4 ;
   RECT 0.000000 36.812000 0.084000 36.844000 ;
  END
 END k_lo_d[169]
 PIN k_lo_d[170]
  DIRECTION INPUT ;
  USE SIGNAL ;
  PORT
   LAYER M4 ;
   RECT 0.000000 37.004000 0.084000 37.036000 ;
  END
 END k_lo_d[170]
 PIN k_lo_d[171]
  DIRECTION INPUT ;
  USE SIGNAL ;
  PORT
   LAYER M4 ;
   RECT 0.000000 37.148000 0.084000 37.180000 ;
  END
 END k_lo_d[171]
 PIN k_lo_d[172]
  DIRECTION INPUT ;
  USE SIGNAL ;
  PORT
   LAYER M4 ;
   RECT 0.000000 37.340000 0.084000 37.372000 ;
  END
 END k_lo_d[172]
 PIN k_lo_d[173]
  DIRECTION INPUT ;
  USE SIGNAL ;
  PORT
   LAYER M4 ;
   RECT 0.000000 37.532000 0.084000 37.564000 ;
  END
 END k_lo_d[173]
 PIN k_lo_d[174]
  DIRECTION INPUT ;
  USE SIGNAL ;
  PORT
   LAYER M4 ;
   RECT 0.000000 37.724000 0.084000 37.756000 ;
  END
 END k_lo_d[174]
 PIN k_lo_d[175]
  DIRECTION INPUT ;
  USE SIGNAL ;
  PORT
   LAYER M4 ;
   RECT 0.000000 37.868000 0.084000 37.900000 ;
  END
 END k_lo_d[175]
 PIN k_lo_d[176]
  DIRECTION INPUT ;
  USE SIGNAL ;
  PORT
   LAYER M4 ;
   RECT 0.000000 38.060000 0.084000 38.092000 ;
  END
 END k_lo_d[176]
 PIN k_lo_d[177]
  DIRECTION INPUT ;
  USE SIGNAL ;
  PORT
   LAYER M4 ;
   RECT 0.000000 38.252000 0.084000 38.284000 ;
  END
 END k_lo_d[177]
 PIN k_lo_d[178]
  DIRECTION INPUT ;
  USE SIGNAL ;
  PORT
   LAYER M4 ;
   RECT 0.000000 38.444000 0.084000 38.476000 ;
  END
 END k_lo_d[178]
 PIN k_lo_d[179]
  DIRECTION INPUT ;
  USE SIGNAL ;
  PORT
   LAYER M4 ;
   RECT 0.000000 38.588000 0.084000 38.620000 ;
  END
 END k_lo_d[179]
 PIN k_lo_d[180]
  DIRECTION INPUT ;
  USE SIGNAL ;
  PORT
   LAYER M4 ;
   RECT 0.000000 38.780000 0.084000 38.812000 ;
  END
 END k_lo_d[180]
 PIN k_lo_d[181]
  DIRECTION INPUT ;
  USE SIGNAL ;
  PORT
   LAYER M4 ;
   RECT 0.000000 38.972000 0.084000 39.004000 ;
  END
 END k_lo_d[181]
 PIN k_lo_d[182]
  DIRECTION INPUT ;
  USE SIGNAL ;
  PORT
   LAYER M4 ;
   RECT 0.000000 39.164000 0.084000 39.196000 ;
  END
 END k_lo_d[182]
 PIN k_lo_d[183]
  DIRECTION INPUT ;
  USE SIGNAL ;
  PORT
   LAYER M4 ;
   RECT 0.000000 39.308000 0.084000 39.340000 ;
  END
 END k_lo_d[183]
 PIN k_lo_d[184]
  DIRECTION INPUT ;
  USE SIGNAL ;
  PORT
   LAYER M4 ;
   RECT 0.000000 39.500000 0.084000 39.532000 ;
  END
 END k_lo_d[184]
 PIN k_lo_d[185]
  DIRECTION INPUT ;
  USE SIGNAL ;
  PORT
   LAYER M4 ;
   RECT 0.000000 39.692000 0.084000 39.724000 ;
  END
 END k_lo_d[185]
 PIN k_lo_d[186]
  DIRECTION INPUT ;
  USE SIGNAL ;
  PORT
   LAYER M4 ;
   RECT 0.000000 39.884000 0.084000 39.916000 ;
  END
 END k_lo_d[186]
 PIN k_lo_d[187]
  DIRECTION INPUT ;
  USE SIGNAL ;
  PORT
   LAYER M4 ;
   RECT 0.000000 40.028000 0.084000 40.060000 ;
  END
 END k_lo_d[187]
 PIN k_lo_d[188]
  DIRECTION INPUT ;
  USE SIGNAL ;
  PORT
   LAYER M4 ;
   RECT 0.000000 40.220000 0.084000 40.252000 ;
  END
 END k_lo_d[188]
 PIN k_lo_d[189]
  DIRECTION INPUT ;
  USE SIGNAL ;
  PORT
   LAYER M4 ;
   RECT 0.000000 40.412000 0.084000 40.444000 ;
  END
 END k_lo_d[189]
 PIN k_lo_d[190]
  DIRECTION INPUT ;
  USE SIGNAL ;
  PORT
   LAYER M4 ;
   RECT 0.000000 40.604000 0.084000 40.636000 ;
  END
 END k_lo_d[190]
 PIN k_lo_d[191]
  DIRECTION INPUT ;
  USE SIGNAL ;
  PORT
   LAYER M4 ;
   RECT 0.000000 40.748000 0.084000 40.780000 ;
  END
 END k_lo_d[191]
 PIN k_lo_d[192]
  DIRECTION INPUT ;
  USE SIGNAL ;
  PORT
   LAYER M4 ;
   RECT 0.000000 40.940000 0.084000 40.972000 ;
  END
 END k_lo_d[192]
 PIN k_lo_d[193]
  DIRECTION INPUT ;
  USE SIGNAL ;
  PORT
   LAYER M4 ;
   RECT 0.000000 41.132000 0.084000 41.164000 ;
  END
 END k_lo_d[193]
 PIN k_lo_d[194]
  DIRECTION INPUT ;
  USE SIGNAL ;
  PORT
   LAYER M4 ;
   RECT 0.000000 41.324000 0.084000 41.356000 ;
  END
 END k_lo_d[194]
 PIN k_lo_d[195]
  DIRECTION INPUT ;
  USE SIGNAL ;
  PORT
   LAYER M4 ;
   RECT 0.000000 41.468000 0.084000 41.500000 ;
  END
 END k_lo_d[195]
 PIN k_lo_d[196]
  DIRECTION INPUT ;
  USE SIGNAL ;
  PORT
   LAYER M4 ;
   RECT 0.000000 41.660000 0.084000 41.692000 ;
  END
 END k_lo_d[196]
 PIN k_lo_d[197]
  DIRECTION INPUT ;
  USE SIGNAL ;
  PORT
   LAYER M4 ;
   RECT 0.000000 41.852000 0.084000 41.884000 ;
  END
 END k_lo_d[197]
 PIN k_lo_d[198]
  DIRECTION INPUT ;
  USE SIGNAL ;
  PORT
   LAYER M4 ;
   RECT 0.000000 42.044000 0.084000 42.076000 ;
  END
 END k_lo_d[198]
 PIN k_lo_d[199]
  DIRECTION INPUT ;
  USE SIGNAL ;
  PORT
   LAYER M4 ;
   RECT 0.000000 42.188000 0.084000 42.220000 ;
  END
 END k_lo_d[199]
 PIN k_lo_d[200]
  DIRECTION INPUT ;
  USE SIGNAL ;
  PORT
   LAYER M4 ;
   RECT 0.000000 42.380000 0.084000 42.412000 ;
  END
 END k_lo_d[200]
 PIN k_lo_d[201]
  DIRECTION INPUT ;
  USE SIGNAL ;
  PORT
   LAYER M4 ;
   RECT 0.000000 42.572000 0.084000 42.604000 ;
  END
 END k_lo_d[201]
 PIN k_lo_d[202]
  DIRECTION INPUT ;
  USE SIGNAL ;
  PORT
   LAYER M4 ;
   RECT 0.000000 42.764000 0.084000 42.796000 ;
  END
 END k_lo_d[202]
 PIN k_lo_d[203]
  DIRECTION INPUT ;
  USE SIGNAL ;
  PORT
   LAYER M4 ;
   RECT 0.000000 42.908000 0.084000 42.940000 ;
  END
 END k_lo_d[203]
 PIN k_lo_d[204]
  DIRECTION INPUT ;
  USE SIGNAL ;
  PORT
   LAYER M4 ;
   RECT 0.000000 43.100000 0.084000 43.132000 ;
  END
 END k_lo_d[204]
 PIN k_lo_d[205]
  DIRECTION INPUT ;
  USE SIGNAL ;
  PORT
   LAYER M4 ;
   RECT 0.000000 43.292000 0.084000 43.324000 ;
  END
 END k_lo_d[205]
 PIN k_lo_d[206]
  DIRECTION INPUT ;
  USE SIGNAL ;
  PORT
   LAYER M4 ;
   RECT 0.000000 43.484000 0.084000 43.516000 ;
  END
 END k_lo_d[206]
 PIN k_lo_d[207]
  DIRECTION INPUT ;
  USE SIGNAL ;
  PORT
   LAYER M4 ;
   RECT 0.000000 43.628000 0.084000 43.660000 ;
  END
 END k_lo_d[207]
 PIN k_lo_d[208]
  DIRECTION INPUT ;
  USE SIGNAL ;
  PORT
   LAYER M4 ;
   RECT 0.000000 43.820000 0.084000 43.852000 ;
  END
 END k_lo_d[208]
 PIN k_lo_d[209]
  DIRECTION INPUT ;
  USE SIGNAL ;
  PORT
   LAYER M4 ;
   RECT 0.000000 44.012000 0.084000 44.044000 ;
  END
 END k_lo_d[209]
 PIN k_lo_d[210]
  DIRECTION INPUT ;
  USE SIGNAL ;
  PORT
   LAYER M4 ;
   RECT 0.000000 44.156000 0.084000 44.188000 ;
  END
 END k_lo_d[210]
 PIN k_lo_d[211]
  DIRECTION INPUT ;
  USE SIGNAL ;
  PORT
   LAYER M4 ;
   RECT 0.000000 44.348000 0.084000 44.380000 ;
  END
 END k_lo_d[211]
 PIN k_lo_d[212]
  DIRECTION INPUT ;
  USE SIGNAL ;
  PORT
   LAYER M4 ;
   RECT 0.000000 44.540000 0.084000 44.572000 ;
  END
 END k_lo_d[212]
 PIN k_lo_d[213]
  DIRECTION INPUT ;
  USE SIGNAL ;
  PORT
   LAYER M4 ;
   RECT 0.000000 44.732000 0.084000 44.764000 ;
  END
 END k_lo_d[213]
 PIN k_lo_d[214]
  DIRECTION INPUT ;
  USE SIGNAL ;
  PORT
   LAYER M4 ;
   RECT 0.000000 44.876000 0.084000 44.908000 ;
  END
 END k_lo_d[214]
 PIN k_lo_d[215]
  DIRECTION INPUT ;
  USE SIGNAL ;
  PORT
   LAYER M4 ;
   RECT 0.000000 45.068000 0.084000 45.100000 ;
  END
 END k_lo_d[215]
 PIN k_lo_d[216]
  DIRECTION INPUT ;
  USE SIGNAL ;
  PORT
   LAYER M4 ;
   RECT 0.000000 45.260000 0.084000 45.292000 ;
  END
 END k_lo_d[216]
 PIN k_lo_d[217]
  DIRECTION INPUT ;
  USE SIGNAL ;
  PORT
   LAYER M4 ;
   RECT 0.000000 45.452000 0.084000 45.484000 ;
  END
 END k_lo_d[217]
 PIN k_lo_d[218]
  DIRECTION INPUT ;
  USE SIGNAL ;
  PORT
   LAYER M4 ;
   RECT 0.000000 45.596000 0.084000 45.628000 ;
  END
 END k_lo_d[218]
 PIN k_lo_d[219]
  DIRECTION INPUT ;
  USE SIGNAL ;
  PORT
   LAYER M4 ;
   RECT 0.000000 45.788000 0.084000 45.820000 ;
  END
 END k_lo_d[219]
 PIN k_lo_d[220]
  DIRECTION INPUT ;
  USE SIGNAL ;
  PORT
   LAYER M4 ;
   RECT 0.000000 45.980000 0.084000 46.012000 ;
  END
 END k_lo_d[220]
 PIN k_lo_d[221]
  DIRECTION INPUT ;
  USE SIGNAL ;
  PORT
   LAYER M4 ;
   RECT 0.000000 46.172000 0.084000 46.204000 ;
  END
 END k_lo_d[221]
 PIN k_lo_d[222]
  DIRECTION INPUT ;
  USE SIGNAL ;
  PORT
   LAYER M4 ;
   RECT 0.000000 46.316000 0.084000 46.348000 ;
  END
 END k_lo_d[222]
 PIN k_lo_d[223]
  DIRECTION INPUT ;
  USE SIGNAL ;
  PORT
   LAYER M4 ;
   RECT 0.000000 46.508000 0.084000 46.540000 ;
  END
 END k_lo_d[223]
 PIN k_lo_d[224]
  DIRECTION INPUT ;
  USE SIGNAL ;
  PORT
   LAYER M4 ;
   RECT 0.000000 46.700000 0.084000 46.732000 ;
  END
 END k_lo_d[224]
 PIN k_lo_d[225]
  DIRECTION INPUT ;
  USE SIGNAL ;
  PORT
   LAYER M4 ;
   RECT 0.000000 46.892000 0.084000 46.924000 ;
  END
 END k_lo_d[225]
 PIN k_lo_d[226]
  DIRECTION INPUT ;
  USE SIGNAL ;
  PORT
   LAYER M4 ;
   RECT 0.000000 47.036000 0.084000 47.068000 ;
  END
 END k_lo_d[226]
 PIN k_lo_d[227]
  DIRECTION INPUT ;
  USE SIGNAL ;
  PORT
   LAYER M4 ;
   RECT 0.000000 47.228000 0.084000 47.260000 ;
  END
 END k_lo_d[227]
 PIN k_lo_d[228]
  DIRECTION INPUT ;
  USE SIGNAL ;
  PORT
   LAYER M4 ;
   RECT 0.000000 47.420000 0.084000 47.452000 ;
  END
 END k_lo_d[228]
 PIN k_lo_d[229]
  DIRECTION INPUT ;
  USE SIGNAL ;
  PORT
   LAYER M4 ;
   RECT 0.000000 47.612000 0.084000 47.644000 ;
  END
 END k_lo_d[229]
 PIN k_lo_d[230]
  DIRECTION INPUT ;
  USE SIGNAL ;
  PORT
   LAYER M4 ;
   RECT 0.000000 47.756000 0.084000 47.788000 ;
  END
 END k_lo_d[230]
 PIN k_lo_d[231]
  DIRECTION INPUT ;
  USE SIGNAL ;
  PORT
   LAYER M4 ;
   RECT 0.000000 47.948000 0.084000 47.980000 ;
  END
 END k_lo_d[231]
 PIN k_lo_d[232]
  DIRECTION INPUT ;
  USE SIGNAL ;
  PORT
   LAYER M4 ;
   RECT 0.000000 48.140000 0.084000 48.172000 ;
  END
 END k_lo_d[232]
 PIN k_lo_d[233]
  DIRECTION INPUT ;
  USE SIGNAL ;
  PORT
   LAYER M4 ;
   RECT 0.000000 48.332000 0.084000 48.364000 ;
  END
 END k_lo_d[233]
 PIN k_lo_d[234]
  DIRECTION INPUT ;
  USE SIGNAL ;
  PORT
   LAYER M4 ;
   RECT 0.000000 48.476000 0.084000 48.508000 ;
  END
 END k_lo_d[234]
 PIN k_lo_d[235]
  DIRECTION INPUT ;
  USE SIGNAL ;
  PORT
   LAYER M4 ;
   RECT 0.000000 48.668000 0.084000 48.700000 ;
  END
 END k_lo_d[235]
 PIN k_lo_d[236]
  DIRECTION INPUT ;
  USE SIGNAL ;
  PORT
   LAYER M4 ;
   RECT 0.000000 48.860000 0.084000 48.892000 ;
  END
 END k_lo_d[236]
 PIN k_lo_d[237]
  DIRECTION INPUT ;
  USE SIGNAL ;
  PORT
   LAYER M4 ;
   RECT 0.000000 49.052000 0.084000 49.084000 ;
  END
 END k_lo_d[237]
 PIN k_lo_d[238]
  DIRECTION INPUT ;
  USE SIGNAL ;
  PORT
   LAYER M4 ;
   RECT 0.000000 49.196000 0.084000 49.228000 ;
  END
 END k_lo_d[238]
 PIN k_lo_d[239]
  DIRECTION INPUT ;
  USE SIGNAL ;
  PORT
   LAYER M4 ;
   RECT 0.000000 49.388000 0.084000 49.420000 ;
  END
 END k_lo_d[239]
 PIN k_lo_d[240]
  DIRECTION INPUT ;
  USE SIGNAL ;
  PORT
   LAYER M4 ;
   RECT 0.000000 49.580000 0.084000 49.612000 ;
  END
 END k_lo_d[240]
 PIN k_lo_d[241]
  DIRECTION INPUT ;
  USE SIGNAL ;
  PORT
   LAYER M4 ;
   RECT 0.000000 49.772000 0.084000 49.804000 ;
  END
 END k_lo_d[241]
 PIN k_lo_d[242]
  DIRECTION INPUT ;
  USE SIGNAL ;
  PORT
   LAYER M4 ;
   RECT 0.000000 49.916000 0.084000 49.948000 ;
  END
 END k_lo_d[242]
 PIN k_lo_d[243]
  DIRECTION INPUT ;
  USE SIGNAL ;
  PORT
   LAYER M4 ;
   RECT 0.000000 50.108000 0.084000 50.140000 ;
  END
 END k_lo_d[243]
 PIN k_lo_d[244]
  DIRECTION INPUT ;
  USE SIGNAL ;
  PORT
   LAYER M4 ;
   RECT 0.000000 50.300000 0.084000 50.332000 ;
  END
 END k_lo_d[244]
 PIN k_lo_d[245]
  DIRECTION INPUT ;
  USE SIGNAL ;
  PORT
   LAYER M4 ;
   RECT 0.000000 50.492000 0.084000 50.524000 ;
  END
 END k_lo_d[245]
 PIN k_lo_d[246]
  DIRECTION INPUT ;
  USE SIGNAL ;
  PORT
   LAYER M4 ;
   RECT 0.000000 50.636000 0.084000 50.668000 ;
  END
 END k_lo_d[246]
 PIN k_lo_d[247]
  DIRECTION INPUT ;
  USE SIGNAL ;
  PORT
   LAYER M4 ;
   RECT 0.000000 50.828000 0.084000 50.860000 ;
  END
 END k_lo_d[247]
 PIN k_lo_d[248]
  DIRECTION INPUT ;
  USE SIGNAL ;
  PORT
   LAYER M4 ;
   RECT 0.000000 51.020000 0.084000 51.052000 ;
  END
 END k_lo_d[248]
 PIN k_lo_d[249]
  DIRECTION INPUT ;
  USE SIGNAL ;
  PORT
   LAYER M4 ;
   RECT 0.000000 51.212000 0.084000 51.244000 ;
  END
 END k_lo_d[249]
 PIN k_lo_d[250]
  DIRECTION INPUT ;
  USE SIGNAL ;
  PORT
   LAYER M4 ;
   RECT 0.000000 51.356000 0.084000 51.388000 ;
  END
 END k_lo_d[250]
 PIN k_lo_d[251]
  DIRECTION INPUT ;
  USE SIGNAL ;
  PORT
   LAYER M4 ;
   RECT 0.000000 51.548000 0.084000 51.580000 ;
  END
 END k_lo_d[251]
 PIN k_lo_d[252]
  DIRECTION INPUT ;
  USE SIGNAL ;
  PORT
   LAYER M4 ;
   RECT 0.000000 51.740000 0.084000 51.772000 ;
  END
 END k_lo_d[252]
 PIN k_lo_d[253]
  DIRECTION INPUT ;
  USE SIGNAL ;
  PORT
   LAYER M4 ;
   RECT 0.000000 51.932000 0.084000 51.964000 ;
  END
 END k_lo_d[253]
 PIN k_lo_d[254]
  DIRECTION INPUT ;
  USE SIGNAL ;
  PORT
   LAYER M4 ;
   RECT 0.000000 52.076000 0.084000 52.108000 ;
  END
 END k_lo_d[254]
 PIN k_lo_d[255]
  DIRECTION INPUT ;
  USE SIGNAL ;
  PORT
   LAYER M4 ;
   RECT 0.000000 52.268000 0.084000 52.300000 ;
  END
 END k_lo_d[255]
 PIN k_lo_d[256]
  DIRECTION INPUT ;
  USE SIGNAL ;
  PORT
   LAYER M4 ;
   RECT 0.000000 52.460000 0.084000 52.492000 ;
  END
 END k_lo_d[256]
 PIN k_lo_d[257]
  DIRECTION INPUT ;
  USE SIGNAL ;
  PORT
   LAYER M4 ;
   RECT 0.000000 52.652000 0.084000 52.684000 ;
  END
 END k_lo_d[257]
 PIN k_lo_d[258]
  DIRECTION INPUT ;
  USE SIGNAL ;
  PORT
   LAYER M4 ;
   RECT 0.000000 52.796000 0.084000 52.828000 ;
  END
 END k_lo_d[258]
 PIN k_lo_d[259]
  DIRECTION INPUT ;
  USE SIGNAL ;
  PORT
   LAYER M4 ;
   RECT 0.000000 52.988000 0.084000 53.020000 ;
  END
 END k_lo_d[259]
 PIN k_lo_d[260]
  DIRECTION INPUT ;
  USE SIGNAL ;
  PORT
   LAYER M4 ;
   RECT 0.000000 53.180000 0.084000 53.212000 ;
  END
 END k_lo_d[260]
 PIN k_lo_d[261]
  DIRECTION INPUT ;
  USE SIGNAL ;
  PORT
   LAYER M4 ;
   RECT 0.000000 53.372000 0.084000 53.404000 ;
  END
 END k_lo_d[261]
 PIN k_lo_d[262]
  DIRECTION INPUT ;
  USE SIGNAL ;
  PORT
   LAYER M4 ;
   RECT 0.000000 53.516000 0.084000 53.548000 ;
  END
 END k_lo_d[262]
 PIN k_lo_d[263]
  DIRECTION INPUT ;
  USE SIGNAL ;
  PORT
   LAYER M4 ;
   RECT 0.000000 53.708000 0.084000 53.740000 ;
  END
 END k_lo_d[263]
 PIN k_lo_d[264]
  DIRECTION INPUT ;
  USE SIGNAL ;
  PORT
   LAYER M4 ;
   RECT 0.000000 53.900000 0.084000 53.932000 ;
  END
 END k_lo_d[264]
 PIN k_lo_d[265]
  DIRECTION INPUT ;
  USE SIGNAL ;
  PORT
   LAYER M4 ;
   RECT 0.000000 54.092000 0.084000 54.124000 ;
  END
 END k_lo_d[265]
 PIN k_lo_d[266]
  DIRECTION INPUT ;
  USE SIGNAL ;
  PORT
   LAYER M4 ;
   RECT 0.000000 54.236000 0.084000 54.268000 ;
  END
 END k_lo_d[266]
 PIN k_lo_d[267]
  DIRECTION INPUT ;
  USE SIGNAL ;
  PORT
   LAYER M4 ;
   RECT 0.000000 54.428000 0.084000 54.460000 ;
  END
 END k_lo_d[267]
 PIN k_lo_d[268]
  DIRECTION INPUT ;
  USE SIGNAL ;
  PORT
   LAYER M4 ;
   RECT 0.000000 54.620000 0.084000 54.652000 ;
  END
 END k_lo_d[268]
 PIN k_lo_d[269]
  DIRECTION INPUT ;
  USE SIGNAL ;
  PORT
   LAYER M4 ;
   RECT 0.000000 54.812000 0.084000 54.844000 ;
  END
 END k_lo_d[269]
 PIN k_lo_d[270]
  DIRECTION INPUT ;
  USE SIGNAL ;
  PORT
   LAYER M4 ;
   RECT 0.000000 54.956000 0.084000 54.988000 ;
  END
 END k_lo_d[270]
 PIN k_lo_d[271]
  DIRECTION INPUT ;
  USE SIGNAL ;
  PORT
   LAYER M4 ;
   RECT 0.000000 55.148000 0.084000 55.180000 ;
  END
 END k_lo_d[271]
 PIN k_lo_d[272]
  DIRECTION INPUT ;
  USE SIGNAL ;
  PORT
   LAYER M4 ;
   RECT 0.000000 55.340000 0.084000 55.372000 ;
  END
 END k_lo_d[272]
 PIN k_lo_d[273]
  DIRECTION INPUT ;
  USE SIGNAL ;
  PORT
   LAYER M4 ;
   RECT 0.000000 55.532000 0.084000 55.564000 ;
  END
 END k_lo_d[273]
 PIN k_lo_d[274]
  DIRECTION INPUT ;
  USE SIGNAL ;
  PORT
   LAYER M4 ;
   RECT 0.000000 55.676000 0.084000 55.708000 ;
  END
 END k_lo_d[274]
 PIN k_lo_d[275]
  DIRECTION INPUT ;
  USE SIGNAL ;
  PORT
   LAYER M4 ;
   RECT 0.000000 55.868000 0.084000 55.900000 ;
  END
 END k_lo_d[275]
 PIN k_lo_d[276]
  DIRECTION INPUT ;
  USE SIGNAL ;
  PORT
   LAYER M4 ;
   RECT 0.000000 56.060000 0.084000 56.092000 ;
  END
 END k_lo_d[276]
 PIN k_lo_d[277]
  DIRECTION INPUT ;
  USE SIGNAL ;
  PORT
   LAYER M4 ;
   RECT 0.000000 56.252000 0.084000 56.284000 ;
  END
 END k_lo_d[277]
 PIN k_lo_d[278]
  DIRECTION INPUT ;
  USE SIGNAL ;
  PORT
   LAYER M4 ;
   RECT 0.000000 56.396000 0.084000 56.428000 ;
  END
 END k_lo_d[278]
 PIN k_lo_d[279]
  DIRECTION INPUT ;
  USE SIGNAL ;
  PORT
   LAYER M4 ;
   RECT 0.000000 56.588000 0.084000 56.620000 ;
  END
 END k_lo_d[279]
 PIN k_lo_d[280]
  DIRECTION INPUT ;
  USE SIGNAL ;
  PORT
   LAYER M4 ;
   RECT 0.000000 56.780000 0.084000 56.812000 ;
  END
 END k_lo_d[280]
 PIN k_lo_d[281]
  DIRECTION INPUT ;
  USE SIGNAL ;
  PORT
   LAYER M4 ;
   RECT 0.000000 56.972000 0.084000 57.004000 ;
  END
 END k_lo_d[281]
 PIN k_lo_d[282]
  DIRECTION INPUT ;
  USE SIGNAL ;
  PORT
   LAYER M4 ;
   RECT 0.000000 57.116000 0.084000 57.148000 ;
  END
 END k_lo_d[282]
 PIN k_lo_d[283]
  DIRECTION INPUT ;
  USE SIGNAL ;
  PORT
   LAYER M4 ;
   RECT 0.000000 57.308000 0.084000 57.340000 ;
  END
 END k_lo_d[283]
 PIN k_lo_d[284]
  DIRECTION INPUT ;
  USE SIGNAL ;
  PORT
   LAYER M4 ;
   RECT 0.000000 57.500000 0.084000 57.532000 ;
  END
 END k_lo_d[284]
 PIN k_lo_d[285]
  DIRECTION INPUT ;
  USE SIGNAL ;
  PORT
   LAYER M4 ;
   RECT 0.000000 57.692000 0.084000 57.724000 ;
  END
 END k_lo_d[285]
 PIN k_lo_d[286]
  DIRECTION INPUT ;
  USE SIGNAL ;
  PORT
   LAYER M4 ;
   RECT 0.000000 57.836000 0.084000 57.868000 ;
  END
 END k_lo_d[286]
 PIN k_lo_d[287]
  DIRECTION INPUT ;
  USE SIGNAL ;
  PORT
   LAYER M4 ;
   RECT 0.000000 58.028000 0.084000 58.060000 ;
  END
 END k_lo_d[287]
 PIN k_lo_d[288]
  DIRECTION INPUT ;
  USE SIGNAL ;
  PORT
   LAYER M4 ;
   RECT 0.000000 58.220000 0.084000 58.252000 ;
  END
 END k_lo_d[288]
 PIN k_lo_d[289]
  DIRECTION INPUT ;
  USE SIGNAL ;
  PORT
   LAYER M4 ;
   RECT 0.000000 58.412000 0.084000 58.444000 ;
  END
 END k_lo_d[289]
 PIN k_lo_d[290]
  DIRECTION INPUT ;
  USE SIGNAL ;
  PORT
   LAYER M4 ;
   RECT 0.000000 58.556000 0.084000 58.588000 ;
  END
 END k_lo_d[290]
 PIN k_lo_d[291]
  DIRECTION INPUT ;
  USE SIGNAL ;
  PORT
   LAYER M4 ;
   RECT 0.000000 58.748000 0.084000 58.780000 ;
  END
 END k_lo_d[291]
 PIN k_lo_d[292]
  DIRECTION INPUT ;
  USE SIGNAL ;
  PORT
   LAYER M4 ;
   RECT 0.000000 58.940000 0.084000 58.972000 ;
  END
 END k_lo_d[292]
 PIN k_lo_d[293]
  DIRECTION INPUT ;
  USE SIGNAL ;
  PORT
   LAYER M4 ;
   RECT 0.000000 59.132000 0.084000 59.164000 ;
  END
 END k_lo_d[293]
 PIN k_lo_d[294]
  DIRECTION INPUT ;
  USE SIGNAL ;
  PORT
   LAYER M4 ;
   RECT 0.000000 59.276000 0.084000 59.308000 ;
  END
 END k_lo_d[294]
 PIN k_lo_d[295]
  DIRECTION INPUT ;
  USE SIGNAL ;
  PORT
   LAYER M4 ;
   RECT 0.000000 59.468000 0.084000 59.500000 ;
  END
 END k_lo_d[295]
 PIN k_lo_d[296]
  DIRECTION INPUT ;
  USE SIGNAL ;
  PORT
   LAYER M4 ;
   RECT 0.000000 59.660000 0.084000 59.692000 ;
  END
 END k_lo_d[296]
 PIN k_lo_d[297]
  DIRECTION INPUT ;
  USE SIGNAL ;
  PORT
   LAYER M4 ;
   RECT 0.000000 59.852000 0.084000 59.884000 ;
  END
 END k_lo_d[297]
 PIN k_lo_d[298]
  DIRECTION INPUT ;
  USE SIGNAL ;
  PORT
   LAYER M4 ;
   RECT 0.000000 59.996000 0.084000 60.028000 ;
  END
 END k_lo_d[298]
 PIN k_lo_d[299]
  DIRECTION INPUT ;
  USE SIGNAL ;
  PORT
   LAYER M4 ;
   RECT 0.000000 60.188000 0.084000 60.220000 ;
  END
 END k_lo_d[299]
 PIN k_lo_d[300]
  DIRECTION INPUT ;
  USE SIGNAL ;
  PORT
   LAYER M4 ;
   RECT 0.000000 60.380000 0.084000 60.412000 ;
  END
 END k_lo_d[300]
 PIN k_lo_d[301]
  DIRECTION INPUT ;
  USE SIGNAL ;
  PORT
   LAYER M4 ;
   RECT 0.000000 60.572000 0.084000 60.604000 ;
  END
 END k_lo_d[301]
 PIN k_lo_d[302]
  DIRECTION INPUT ;
  USE SIGNAL ;
  PORT
   LAYER M4 ;
   RECT 0.000000 60.716000 0.084000 60.748000 ;
  END
 END k_lo_d[302]
 PIN k_lo_d[303]
  DIRECTION INPUT ;
  USE SIGNAL ;
  PORT
   LAYER M4 ;
   RECT 0.000000 60.908000 0.084000 60.940000 ;
  END
 END k_lo_d[303]
 PIN k_lo_d[304]
  DIRECTION INPUT ;
  USE SIGNAL ;
  PORT
   LAYER M4 ;
   RECT 0.000000 61.100000 0.084000 61.132000 ;
  END
 END k_lo_d[304]
 PIN k_lo_d[305]
  DIRECTION INPUT ;
  USE SIGNAL ;
  PORT
   LAYER M4 ;
   RECT 0.000000 61.292000 0.084000 61.324000 ;
  END
 END k_lo_d[305]
 PIN k_lo_d[306]
  DIRECTION INPUT ;
  USE SIGNAL ;
  PORT
   LAYER M4 ;
   RECT 0.000000 61.436000 0.084000 61.468000 ;
  END
 END k_lo_d[306]
 PIN k_lo_d[307]
  DIRECTION INPUT ;
  USE SIGNAL ;
  PORT
   LAYER M4 ;
   RECT 0.000000 61.628000 0.084000 61.660000 ;
  END
 END k_lo_d[307]
 PIN k_lo_d[308]
  DIRECTION INPUT ;
  USE SIGNAL ;
  PORT
   LAYER M4 ;
   RECT 0.000000 61.820000 0.084000 61.852000 ;
  END
 END k_lo_d[308]
 PIN k_lo_d[309]
  DIRECTION INPUT ;
  USE SIGNAL ;
  PORT
   LAYER M4 ;
   RECT 0.000000 62.012000 0.084000 62.044000 ;
  END
 END k_lo_d[309]
 PIN k_lo_d[310]
  DIRECTION INPUT ;
  USE SIGNAL ;
  PORT
   LAYER M4 ;
   RECT 0.000000 62.156000 0.084000 62.188000 ;
  END
 END k_lo_d[310]
 PIN k_lo_d[311]
  DIRECTION INPUT ;
  USE SIGNAL ;
  PORT
   LAYER M4 ;
   RECT 0.000000 62.348000 0.084000 62.380000 ;
  END
 END k_lo_d[311]
 PIN k_lo_d[312]
  DIRECTION INPUT ;
  USE SIGNAL ;
  PORT
   LAYER M4 ;
   RECT 0.000000 62.540000 0.084000 62.572000 ;
  END
 END k_lo_d[312]
 PIN k_lo_d[313]
  DIRECTION INPUT ;
  USE SIGNAL ;
  PORT
   LAYER M4 ;
   RECT 0.000000 62.732000 0.084000 62.764000 ;
  END
 END k_lo_d[313]
 PIN k_lo_d[314]
  DIRECTION INPUT ;
  USE SIGNAL ;
  PORT
   LAYER M4 ;
   RECT 0.000000 62.876000 0.084000 62.908000 ;
  END
 END k_lo_d[314]
 PIN k_lo_d[315]
  DIRECTION INPUT ;
  USE SIGNAL ;
  PORT
   LAYER M4 ;
   RECT 0.000000 63.068000 0.084000 63.100000 ;
  END
 END k_lo_d[315]
 PIN k_lo_d[316]
  DIRECTION INPUT ;
  USE SIGNAL ;
  PORT
   LAYER M4 ;
   RECT 0.000000 63.260000 0.084000 63.292000 ;
  END
 END k_lo_d[316]
 PIN k_lo_d[317]
  DIRECTION INPUT ;
  USE SIGNAL ;
  PORT
   LAYER M4 ;
   RECT 0.000000 63.452000 0.084000 63.484000 ;
  END
 END k_lo_d[317]
 PIN k_lo_d[318]
  DIRECTION INPUT ;
  USE SIGNAL ;
  PORT
   LAYER M4 ;
   RECT 0.000000 63.596000 0.084000 63.628000 ;
  END
 END k_lo_d[318]
 PIN k_lo_d[319]
  DIRECTION INPUT ;
  USE SIGNAL ;
  PORT
   LAYER M4 ;
   RECT 0.000000 63.788000 0.084000 63.820000 ;
  END
 END k_lo_d[319]
 PIN k_lo_d[320]
  DIRECTION INPUT ;
  USE SIGNAL ;
  PORT
   LAYER M4 ;
   RECT 0.000000 63.980000 0.084000 64.012000 ;
  END
 END k_lo_d[320]
 PIN k_lo_d[321]
  DIRECTION INPUT ;
  USE SIGNAL ;
  PORT
   LAYER M4 ;
   RECT 0.000000 64.172000 0.084000 64.204000 ;
  END
 END k_lo_d[321]
 PIN k_lo_d[322]
  DIRECTION INPUT ;
  USE SIGNAL ;
  PORT
   LAYER M4 ;
   RECT 0.000000 64.316000 0.084000 64.348000 ;
  END
 END k_lo_d[322]
 PIN k_lo_d[323]
  DIRECTION INPUT ;
  USE SIGNAL ;
  PORT
   LAYER M4 ;
   RECT 0.000000 64.508000 0.084000 64.540000 ;
  END
 END k_lo_d[323]
 PIN k_lo_d[324]
  DIRECTION INPUT ;
  USE SIGNAL ;
  PORT
   LAYER M4 ;
   RECT 0.000000 64.700000 0.084000 64.732000 ;
  END
 END k_lo_d[324]
 PIN k_lo_d[325]
  DIRECTION INPUT ;
  USE SIGNAL ;
  PORT
   LAYER M4 ;
   RECT 0.000000 64.892000 0.084000 64.924000 ;
  END
 END k_lo_d[325]
 PIN k_lo_d[326]
  DIRECTION INPUT ;
  USE SIGNAL ;
  PORT
   LAYER M4 ;
   RECT 0.000000 65.036000 0.084000 65.068000 ;
  END
 END k_lo_d[326]
 PIN k_lo_d[327]
  DIRECTION INPUT ;
  USE SIGNAL ;
  PORT
   LAYER M4 ;
   RECT 0.000000 65.228000 0.084000 65.260000 ;
  END
 END k_lo_d[327]
 PIN k_lo_d[328]
  DIRECTION INPUT ;
  USE SIGNAL ;
  PORT
   LAYER M4 ;
   RECT 0.000000 65.420000 0.084000 65.452000 ;
  END
 END k_lo_d[328]
 PIN k_lo_d[329]
  DIRECTION INPUT ;
  USE SIGNAL ;
  PORT
   LAYER M4 ;
   RECT 0.000000 65.612000 0.084000 65.644000 ;
  END
 END k_lo_d[329]
 PIN k_lo_d[330]
  DIRECTION INPUT ;
  USE SIGNAL ;
  PORT
   LAYER M4 ;
   RECT 0.000000 65.756000 0.084000 65.788000 ;
  END
 END k_lo_d[330]
 PIN k_lo_d[331]
  DIRECTION INPUT ;
  USE SIGNAL ;
  PORT
   LAYER M4 ;
   RECT 0.000000 65.948000 0.084000 65.980000 ;
  END
 END k_lo_d[331]
 PIN k_lo_d[332]
  DIRECTION INPUT ;
  USE SIGNAL ;
  PORT
   LAYER M4 ;
   RECT 0.000000 66.140000 0.084000 66.172000 ;
  END
 END k_lo_d[332]
 PIN k_lo_d[333]
  DIRECTION INPUT ;
  USE SIGNAL ;
  PORT
   LAYER M4 ;
   RECT 0.000000 66.332000 0.084000 66.364000 ;
  END
 END k_lo_d[333]
 PIN k_lo_d[334]
  DIRECTION INPUT ;
  USE SIGNAL ;
  PORT
   LAYER M4 ;
   RECT 0.000000 66.476000 0.084000 66.508000 ;
  END
 END k_lo_d[334]
 PIN k_lo_d[335]
  DIRECTION INPUT ;
  USE SIGNAL ;
  PORT
   LAYER M4 ;
   RECT 0.000000 66.668000 0.084000 66.700000 ;
  END
 END k_lo_d[335]
 PIN k_lo_d[336]
  DIRECTION INPUT ;
  USE SIGNAL ;
  PORT
   LAYER M4 ;
   RECT 0.000000 66.860000 0.084000 66.892000 ;
  END
 END k_lo_d[336]
 PIN k_lo_d[337]
  DIRECTION INPUT ;
  USE SIGNAL ;
  PORT
   LAYER M4 ;
   RECT 0.000000 67.052000 0.084000 67.084000 ;
  END
 END k_lo_d[337]
 PIN k_lo_d[338]
  DIRECTION INPUT ;
  USE SIGNAL ;
  PORT
   LAYER M4 ;
   RECT 0.000000 67.196000 0.084000 67.228000 ;
  END
 END k_lo_d[338]
 PIN k_lo_d[339]
  DIRECTION INPUT ;
  USE SIGNAL ;
  PORT
   LAYER M4 ;
   RECT 0.000000 67.388000 0.084000 67.420000 ;
  END
 END k_lo_d[339]
 PIN k_lo_d[340]
  DIRECTION INPUT ;
  USE SIGNAL ;
  PORT
   LAYER M4 ;
   RECT 0.000000 67.580000 0.084000 67.612000 ;
  END
 END k_lo_d[340]
 PIN k_lo_d[341]
  DIRECTION INPUT ;
  USE SIGNAL ;
  PORT
   LAYER M4 ;
   RECT 0.000000 67.772000 0.084000 67.804000 ;
  END
 END k_lo_d[341]
 PIN k_lo_d[342]
  DIRECTION INPUT ;
  USE SIGNAL ;
  PORT
   LAYER M4 ;
   RECT 0.000000 67.916000 0.084000 67.948000 ;
  END
 END k_lo_d[342]
 PIN k_lo_d[343]
  DIRECTION INPUT ;
  USE SIGNAL ;
  PORT
   LAYER M4 ;
   RECT 0.000000 68.108000 0.084000 68.140000 ;
  END
 END k_lo_d[343]
 PIN k_lo_d[344]
  DIRECTION INPUT ;
  USE SIGNAL ;
  PORT
   LAYER M4 ;
   RECT 0.000000 68.300000 0.084000 68.332000 ;
  END
 END k_lo_d[344]
 PIN k_lo_d[345]
  DIRECTION INPUT ;
  USE SIGNAL ;
  PORT
   LAYER M4 ;
   RECT 0.000000 68.492000 0.084000 68.524000 ;
  END
 END k_lo_d[345]
 PIN k_lo_d[346]
  DIRECTION INPUT ;
  USE SIGNAL ;
  PORT
   LAYER M4 ;
   RECT 0.000000 68.636000 0.084000 68.668000 ;
  END
 END k_lo_d[346]
 PIN k_lo_d[347]
  DIRECTION INPUT ;
  USE SIGNAL ;
  PORT
   LAYER M4 ;
   RECT 0.000000 68.828000 0.084000 68.860000 ;
  END
 END k_lo_d[347]
 PIN k_lo_d[348]
  DIRECTION INPUT ;
  USE SIGNAL ;
  PORT
   LAYER M4 ;
   RECT 0.000000 69.020000 0.084000 69.052000 ;
  END
 END k_lo_d[348]
 PIN k_lo_d[349]
  DIRECTION INPUT ;
  USE SIGNAL ;
  PORT
   LAYER M4 ;
   RECT 0.000000 69.164000 0.084000 69.196000 ;
  END
 END k_lo_d[349]
 PIN k_lo_d[350]
  DIRECTION INPUT ;
  USE SIGNAL ;
  PORT
   LAYER M4 ;
   RECT 0.000000 69.356000 0.084000 69.388000 ;
  END
 END k_lo_d[350]
 PIN k_lo_d[351]
  DIRECTION INPUT ;
  USE SIGNAL ;
  PORT
   LAYER M4 ;
   RECT 0.000000 69.548000 0.084000 69.580000 ;
  END
 END k_lo_d[351]
 PIN k_lo_d[352]
  DIRECTION INPUT ;
  USE SIGNAL ;
  PORT
   LAYER M4 ;
   RECT 0.000000 69.740000 0.084000 69.772000 ;
  END
 END k_lo_d[352]
 PIN k_lo_d[353]
  DIRECTION INPUT ;
  USE SIGNAL ;
  PORT
   LAYER M4 ;
   RECT 0.000000 69.884000 0.084000 69.916000 ;
  END
 END k_lo_d[353]
 PIN k_lo_d[354]
  DIRECTION INPUT ;
  USE SIGNAL ;
  PORT
   LAYER M4 ;
   RECT 0.000000 70.076000 0.084000 70.108000 ;
  END
 END k_lo_d[354]
 PIN k_lo_d[355]
  DIRECTION INPUT ;
  USE SIGNAL ;
  PORT
   LAYER M4 ;
   RECT 0.000000 70.268000 0.084000 70.300000 ;
  END
 END k_lo_d[355]
 PIN k_lo_d[356]
  DIRECTION INPUT ;
  USE SIGNAL ;
  PORT
   LAYER M4 ;
   RECT 0.000000 70.460000 0.084000 70.492000 ;
  END
 END k_lo_d[356]
 PIN k_lo_d[357]
  DIRECTION INPUT ;
  USE SIGNAL ;
  PORT
   LAYER M4 ;
   RECT 0.000000 70.604000 0.084000 70.636000 ;
  END
 END k_lo_d[357]
 PIN k_lo_d[358]
  DIRECTION INPUT ;
  USE SIGNAL ;
  PORT
   LAYER M4 ;
   RECT 0.000000 70.796000 0.084000 70.828000 ;
  END
 END k_lo_d[358]
 PIN k_lo_d[359]
  DIRECTION INPUT ;
  USE SIGNAL ;
  PORT
   LAYER M4 ;
   RECT 0.000000 70.988000 0.084000 71.020000 ;
  END
 END k_lo_d[359]
 PIN k_lo_d[360]
  DIRECTION INPUT ;
  USE SIGNAL ;
  PORT
   LAYER M4 ;
   RECT 0.000000 71.180000 0.084000 71.212000 ;
  END
 END k_lo_d[360]
 PIN k_lo_d[361]
  DIRECTION INPUT ;
  USE SIGNAL ;
  PORT
   LAYER M4 ;
   RECT 0.000000 71.324000 0.084000 71.356000 ;
  END
 END k_lo_d[361]
 PIN k_lo_d[362]
  DIRECTION INPUT ;
  USE SIGNAL ;
  PORT
   LAYER M4 ;
   RECT 0.000000 71.516000 0.084000 71.548000 ;
  END
 END k_lo_d[362]
 PIN k_lo_d[363]
  DIRECTION INPUT ;
  USE SIGNAL ;
  PORT
   LAYER M4 ;
   RECT 0.000000 71.708000 0.084000 71.740000 ;
  END
 END k_lo_d[363]
 PIN k_lo_d[364]
  DIRECTION INPUT ;
  USE SIGNAL ;
  PORT
   LAYER M4 ;
   RECT 0.000000 71.900000 0.084000 71.932000 ;
  END
 END k_lo_d[364]
 PIN k_lo_d[365]
  DIRECTION INPUT ;
  USE SIGNAL ;
  PORT
   LAYER M4 ;
   RECT 0.000000 72.044000 0.084000 72.076000 ;
  END
 END k_lo_d[365]
 PIN k_lo_d[366]
  DIRECTION INPUT ;
  USE SIGNAL ;
  PORT
   LAYER M4 ;
   RECT 0.000000 72.236000 0.084000 72.268000 ;
  END
 END k_lo_d[366]
 PIN k_lo_d[367]
  DIRECTION INPUT ;
  USE SIGNAL ;
  PORT
   LAYER M4 ;
   RECT 0.000000 72.428000 0.084000 72.460000 ;
  END
 END k_lo_d[367]
 PIN k_lo_d[368]
  DIRECTION INPUT ;
  USE SIGNAL ;
  PORT
   LAYER M4 ;
   RECT 0.000000 72.620000 0.084000 72.652000 ;
  END
 END k_lo_d[368]
 PIN k_lo_d[369]
  DIRECTION INPUT ;
  USE SIGNAL ;
  PORT
   LAYER M4 ;
   RECT 0.000000 72.764000 0.084000 72.796000 ;
  END
 END k_lo_d[369]
 PIN k_lo_d[370]
  DIRECTION INPUT ;
  USE SIGNAL ;
  PORT
   LAYER M4 ;
   RECT 0.000000 72.956000 0.084000 72.988000 ;
  END
 END k_lo_d[370]
 PIN k_lo_d[371]
  DIRECTION INPUT ;
  USE SIGNAL ;
  PORT
   LAYER M4 ;
   RECT 0.000000 73.148000 0.084000 73.180000 ;
  END
 END k_lo_d[371]
 PIN k_lo_d[372]
  DIRECTION INPUT ;
  USE SIGNAL ;
  PORT
   LAYER M4 ;
   RECT 0.000000 73.340000 0.084000 73.372000 ;
  END
 END k_lo_d[372]
 PIN k_lo_d[373]
  DIRECTION INPUT ;
  USE SIGNAL ;
  PORT
   LAYER M4 ;
   RECT 0.000000 73.484000 0.084000 73.516000 ;
  END
 END k_lo_d[373]
 PIN k_lo_d[374]
  DIRECTION INPUT ;
  USE SIGNAL ;
  PORT
   LAYER M4 ;
   RECT 0.000000 73.676000 0.084000 73.708000 ;
  END
 END k_lo_d[374]
 PIN k_lo_d[375]
  DIRECTION INPUT ;
  USE SIGNAL ;
  PORT
   LAYER M4 ;
   RECT 0.000000 73.868000 0.084000 73.900000 ;
  END
 END k_lo_d[375]
 PIN k_lo_d[376]
  DIRECTION INPUT ;
  USE SIGNAL ;
  PORT
   LAYER M4 ;
   RECT 0.000000 74.060000 0.084000 74.092000 ;
  END
 END k_lo_d[376]
 PIN k_lo_d[377]
  DIRECTION INPUT ;
  USE SIGNAL ;
  PORT
   LAYER M4 ;
   RECT 0.000000 74.204000 0.084000 74.236000 ;
  END
 END k_lo_d[377]
 PIN k_lo_d[378]
  DIRECTION INPUT ;
  USE SIGNAL ;
  PORT
   LAYER M4 ;
   RECT 0.000000 74.396000 0.084000 74.428000 ;
  END
 END k_lo_d[378]
 PIN k_lo_d[379]
  DIRECTION INPUT ;
  USE SIGNAL ;
  PORT
   LAYER M4 ;
   RECT 0.000000 74.588000 0.084000 74.620000 ;
  END
 END k_lo_d[379]
 PIN k_lo_d[380]
  DIRECTION INPUT ;
  USE SIGNAL ;
  PORT
   LAYER M4 ;
   RECT 0.000000 74.780000 0.084000 74.812000 ;
  END
 END k_lo_d[380]
 PIN k_lo_d[381]
  DIRECTION INPUT ;
  USE SIGNAL ;
  PORT
   LAYER M4 ;
   RECT 0.000000 74.924000 0.084000 74.956000 ;
  END
 END k_lo_d[381]
 PIN k_lo_d[382]
  DIRECTION INPUT ;
  USE SIGNAL ;
  PORT
   LAYER M4 ;
   RECT 0.000000 75.116000 0.084000 75.148000 ;
  END
 END k_lo_d[382]
 PIN k_lo_d[383]
  DIRECTION INPUT ;
  USE SIGNAL ;
  PORT
   LAYER M4 ;
   RECT 0.000000 75.308000 0.084000 75.340000 ;
  END
 END k_lo_d[383]
 PIN k_lo_d[384]
  DIRECTION INPUT ;
  USE SIGNAL ;
  PORT
   LAYER M4 ;
   RECT 0.000000 75.500000 0.084000 75.532000 ;
  END
 END k_lo_d[384]
 PIN k_lo_d[385]
  DIRECTION INPUT ;
  USE SIGNAL ;
  PORT
   LAYER M4 ;
   RECT 0.000000 75.644000 0.084000 75.676000 ;
  END
 END k_lo_d[385]
 PIN k_lo_d[386]
  DIRECTION INPUT ;
  USE SIGNAL ;
  PORT
   LAYER M4 ;
   RECT 0.000000 75.836000 0.084000 75.868000 ;
  END
 END k_lo_d[386]
 PIN k_lo_d[387]
  DIRECTION INPUT ;
  USE SIGNAL ;
  PORT
   LAYER M4 ;
   RECT 0.000000 76.028000 0.084000 76.060000 ;
  END
 END k_lo_d[387]
 PIN k_lo_d[388]
  DIRECTION INPUT ;
  USE SIGNAL ;
  PORT
   LAYER M4 ;
   RECT 0.000000 76.220000 0.084000 76.252000 ;
  END
 END k_lo_d[388]
 PIN k_lo_d[389]
  DIRECTION INPUT ;
  USE SIGNAL ;
  PORT
   LAYER M4 ;
   RECT 0.000000 76.364000 0.084000 76.396000 ;
  END
 END k_lo_d[389]
 PIN k_lo_d[390]
  DIRECTION INPUT ;
  USE SIGNAL ;
  PORT
   LAYER M4 ;
   RECT 0.000000 76.556000 0.084000 76.588000 ;
  END
 END k_lo_d[390]
 PIN k_lo_d[391]
  DIRECTION INPUT ;
  USE SIGNAL ;
  PORT
   LAYER M4 ;
   RECT 0.000000 76.748000 0.084000 76.780000 ;
  END
 END k_lo_d[391]
 PIN k_lo_d[392]
  DIRECTION INPUT ;
  USE SIGNAL ;
  PORT
   LAYER M4 ;
   RECT 0.000000 76.940000 0.084000 76.972000 ;
  END
 END k_lo_d[392]
 PIN k_lo_d[393]
  DIRECTION INPUT ;
  USE SIGNAL ;
  PORT
   LAYER M4 ;
   RECT 0.000000 77.084000 0.084000 77.116000 ;
  END
 END k_lo_d[393]
 PIN k_lo_d[394]
  DIRECTION INPUT ;
  USE SIGNAL ;
  PORT
   LAYER M4 ;
   RECT 0.000000 77.276000 0.084000 77.308000 ;
  END
 END k_lo_d[394]
 PIN k_lo_d[395]
  DIRECTION INPUT ;
  USE SIGNAL ;
  PORT
   LAYER M4 ;
   RECT 0.000000 77.468000 0.084000 77.500000 ;
  END
 END k_lo_d[395]
 PIN k_lo_d[396]
  DIRECTION INPUT ;
  USE SIGNAL ;
  PORT
   LAYER M4 ;
   RECT 0.000000 77.660000 0.084000 77.692000 ;
  END
 END k_lo_d[396]
 PIN k_lo_d[397]
  DIRECTION INPUT ;
  USE SIGNAL ;
  PORT
   LAYER M4 ;
   RECT 0.000000 77.804000 0.084000 77.836000 ;
  END
 END k_lo_d[397]
 PIN k_lo_d[398]
  DIRECTION INPUT ;
  USE SIGNAL ;
  PORT
   LAYER M4 ;
   RECT 0.000000 77.996000 0.084000 78.028000 ;
  END
 END k_lo_d[398]
 PIN k_lo_d[399]
  DIRECTION INPUT ;
  USE SIGNAL ;
  PORT
   LAYER M4 ;
   RECT 0.000000 78.188000 0.084000 78.220000 ;
  END
 END k_lo_d[399]
 PIN k_lo_d[400]
  DIRECTION INPUT ;
  USE SIGNAL ;
  PORT
   LAYER M4 ;
   RECT 0.000000 78.380000 0.084000 78.412000 ;
  END
 END k_lo_d[400]
 PIN k_lo_d[401]
  DIRECTION INPUT ;
  USE SIGNAL ;
  PORT
   LAYER M4 ;
   RECT 0.000000 78.524000 0.084000 78.556000 ;
  END
 END k_lo_d[401]
 PIN k_lo_d[402]
  DIRECTION INPUT ;
  USE SIGNAL ;
  PORT
   LAYER M4 ;
   RECT 0.000000 78.716000 0.084000 78.748000 ;
  END
 END k_lo_d[402]
 PIN k_lo_d[403]
  DIRECTION INPUT ;
  USE SIGNAL ;
  PORT
   LAYER M4 ;
   RECT 0.000000 78.908000 0.084000 78.940000 ;
  END
 END k_lo_d[403]
 PIN k_lo_d[404]
  DIRECTION INPUT ;
  USE SIGNAL ;
  PORT
   LAYER M4 ;
   RECT 0.000000 79.100000 0.084000 79.132000 ;
  END
 END k_lo_d[404]
 PIN k_lo_d[405]
  DIRECTION INPUT ;
  USE SIGNAL ;
  PORT
   LAYER M4 ;
   RECT 0.000000 79.244000 0.084000 79.276000 ;
  END
 END k_lo_d[405]
 PIN k_lo_d[406]
  DIRECTION INPUT ;
  USE SIGNAL ;
  PORT
   LAYER M4 ;
   RECT 0.000000 79.436000 0.084000 79.468000 ;
  END
 END k_lo_d[406]
 PIN k_lo_d[407]
  DIRECTION INPUT ;
  USE SIGNAL ;
  PORT
   LAYER M4 ;
   RECT 0.000000 79.628000 0.084000 79.660000 ;
  END
 END k_lo_d[407]
 PIN k_lo_d[408]
  DIRECTION INPUT ;
  USE SIGNAL ;
  PORT
   LAYER M4 ;
   RECT 0.000000 79.820000 0.084000 79.852000 ;
  END
 END k_lo_d[408]
 PIN k_lo_d[409]
  DIRECTION INPUT ;
  USE SIGNAL ;
  PORT
   LAYER M4 ;
   RECT 0.000000 79.964000 0.084000 79.996000 ;
  END
 END k_lo_d[409]
 PIN k_lo_d[410]
  DIRECTION INPUT ;
  USE SIGNAL ;
  PORT
   LAYER M4 ;
   RECT 0.000000 80.156000 0.084000 80.188000 ;
  END
 END k_lo_d[410]
 PIN k_lo_d[411]
  DIRECTION INPUT ;
  USE SIGNAL ;
  PORT
   LAYER M4 ;
   RECT 0.000000 80.348000 0.084000 80.380000 ;
  END
 END k_lo_d[411]
 PIN k_lo_d[412]
  DIRECTION INPUT ;
  USE SIGNAL ;
  PORT
   LAYER M4 ;
   RECT 0.000000 80.540000 0.084000 80.572000 ;
  END
 END k_lo_d[412]
 PIN k_lo_d[413]
  DIRECTION INPUT ;
  USE SIGNAL ;
  PORT
   LAYER M4 ;
   RECT 0.000000 80.684000 0.084000 80.716000 ;
  END
 END k_lo_d[413]
 PIN k_lo_d[414]
  DIRECTION INPUT ;
  USE SIGNAL ;
  PORT
   LAYER M4 ;
   RECT 0.000000 80.876000 0.084000 80.908000 ;
  END
 END k_lo_d[414]
 PIN k_lo_d[415]
  DIRECTION INPUT ;
  USE SIGNAL ;
  PORT
   LAYER M4 ;
   RECT 0.000000 81.068000 0.084000 81.100000 ;
  END
 END k_lo_d[415]
 PIN k_lo_d[416]
  DIRECTION INPUT ;
  USE SIGNAL ;
  PORT
   LAYER M4 ;
   RECT 0.000000 81.260000 0.084000 81.292000 ;
  END
 END k_lo_d[416]
 PIN k_lo_d[417]
  DIRECTION INPUT ;
  USE SIGNAL ;
  PORT
   LAYER M4 ;
   RECT 0.000000 81.404000 0.084000 81.436000 ;
  END
 END k_lo_d[417]
 PIN k_lo_d[418]
  DIRECTION INPUT ;
  USE SIGNAL ;
  PORT
   LAYER M4 ;
   RECT 0.000000 81.596000 0.084000 81.628000 ;
  END
 END k_lo_d[418]
 PIN k_lo_d[419]
  DIRECTION INPUT ;
  USE SIGNAL ;
  PORT
   LAYER M4 ;
   RECT 0.000000 81.788000 0.084000 81.820000 ;
  END
 END k_lo_d[419]
 PIN k_lo_d[420]
  DIRECTION INPUT ;
  USE SIGNAL ;
  PORT
   LAYER M4 ;
   RECT 0.000000 81.980000 0.084000 82.012000 ;
  END
 END k_lo_d[420]
 PIN k_lo_d[421]
  DIRECTION INPUT ;
  USE SIGNAL ;
  PORT
   LAYER M4 ;
   RECT 0.000000 82.124000 0.084000 82.156000 ;
  END
 END k_lo_d[421]
 PIN k_lo_d[422]
  DIRECTION INPUT ;
  USE SIGNAL ;
  PORT
   LAYER M4 ;
   RECT 0.000000 82.316000 0.084000 82.348000 ;
  END
 END k_lo_d[422]
 PIN k_lo_d[423]
  DIRECTION INPUT ;
  USE SIGNAL ;
  PORT
   LAYER M4 ;
   RECT 0.000000 82.508000 0.084000 82.540000 ;
  END
 END k_lo_d[423]
 PIN k_lo_d[424]
  DIRECTION INPUT ;
  USE SIGNAL ;
  PORT
   LAYER M4 ;
   RECT 0.000000 82.700000 0.084000 82.732000 ;
  END
 END k_lo_d[424]
 PIN k_lo_d[425]
  DIRECTION INPUT ;
  USE SIGNAL ;
  PORT
   LAYER M4 ;
   RECT 0.000000 82.844000 0.084000 82.876000 ;
  END
 END k_lo_d[425]
 PIN k_lo_d[426]
  DIRECTION INPUT ;
  USE SIGNAL ;
  PORT
   LAYER M4 ;
   RECT 0.000000 83.036000 0.084000 83.068000 ;
  END
 END k_lo_d[426]
 PIN k_lo_d[427]
  DIRECTION INPUT ;
  USE SIGNAL ;
  PORT
   LAYER M4 ;
   RECT 0.000000 83.228000 0.084000 83.260000 ;
  END
 END k_lo_d[427]
 PIN k_lo_d[428]
  DIRECTION INPUT ;
  USE SIGNAL ;
  PORT
   LAYER M4 ;
   RECT 0.000000 83.420000 0.084000 83.452000 ;
  END
 END k_lo_d[428]
 PIN k_lo_d[429]
  DIRECTION INPUT ;
  USE SIGNAL ;
  PORT
   LAYER M4 ;
   RECT 0.000000 83.564000 0.084000 83.596000 ;
  END
 END k_lo_d[429]
 PIN k_lo_d[430]
  DIRECTION INPUT ;
  USE SIGNAL ;
  PORT
   LAYER M4 ;
   RECT 0.000000 83.756000 0.084000 83.788000 ;
  END
 END k_lo_d[430]
 PIN k_lo_d[431]
  DIRECTION INPUT ;
  USE SIGNAL ;
  PORT
   LAYER M4 ;
   RECT 0.000000 83.948000 0.084000 83.980000 ;
  END
 END k_lo_d[431]
 PIN k_lo_d[432]
  DIRECTION INPUT ;
  USE SIGNAL ;
  PORT
   LAYER M4 ;
   RECT 0.000000 84.140000 0.084000 84.172000 ;
  END
 END k_lo_d[432]
 PIN k_lo_d[433]
  DIRECTION INPUT ;
  USE SIGNAL ;
  PORT
   LAYER M4 ;
   RECT 0.000000 84.284000 0.084000 84.316000 ;
  END
 END k_lo_d[433]
 PIN k_lo_d[434]
  DIRECTION INPUT ;
  USE SIGNAL ;
  PORT
   LAYER M4 ;
   RECT 0.000000 84.476000 0.084000 84.508000 ;
  END
 END k_lo_d[434]
 PIN k_lo_d[435]
  DIRECTION INPUT ;
  USE SIGNAL ;
  PORT
   LAYER M4 ;
   RECT 0.000000 84.668000 0.084000 84.700000 ;
  END
 END k_lo_d[435]
 PIN k_lo_d[436]
  DIRECTION INPUT ;
  USE SIGNAL ;
  PORT
   LAYER M4 ;
   RECT 0.000000 84.860000 0.084000 84.892000 ;
  END
 END k_lo_d[436]
 PIN k_lo_d[437]
  DIRECTION INPUT ;
  USE SIGNAL ;
  PORT
   LAYER M4 ;
   RECT 0.000000 85.004000 0.084000 85.036000 ;
  END
 END k_lo_d[437]
 PIN k_lo_d[438]
  DIRECTION INPUT ;
  USE SIGNAL ;
  PORT
   LAYER M4 ;
   RECT 0.000000 85.196000 0.084000 85.228000 ;
  END
 END k_lo_d[438]
 PIN k_lo_d[439]
  DIRECTION INPUT ;
  USE SIGNAL ;
  PORT
   LAYER M4 ;
   RECT 0.000000 85.388000 0.084000 85.420000 ;
  END
 END k_lo_d[439]
 PIN k_lo_d[440]
  DIRECTION INPUT ;
  USE SIGNAL ;
  PORT
   LAYER M4 ;
   RECT 0.000000 85.580000 0.084000 85.612000 ;
  END
 END k_lo_d[440]
 PIN k_lo_d[441]
  DIRECTION INPUT ;
  USE SIGNAL ;
  PORT
   LAYER M4 ;
   RECT 0.000000 85.724000 0.084000 85.756000 ;
  END
 END k_lo_d[441]
 PIN k_lo_d[442]
  DIRECTION INPUT ;
  USE SIGNAL ;
  PORT
   LAYER M4 ;
   RECT 0.000000 85.916000 0.084000 85.948000 ;
  END
 END k_lo_d[442]
 PIN k_lo_d[443]
  DIRECTION INPUT ;
  USE SIGNAL ;
  PORT
   LAYER M4 ;
   RECT 0.000000 86.108000 0.084000 86.140000 ;
  END
 END k_lo_d[443]
 PIN k_lo_d[444]
  DIRECTION INPUT ;
  USE SIGNAL ;
  PORT
   LAYER M4 ;
   RECT 0.000000 86.300000 0.084000 86.332000 ;
  END
 END k_lo_d[444]
 PIN k_lo_d[445]
  DIRECTION INPUT ;
  USE SIGNAL ;
  PORT
   LAYER M4 ;
   RECT 0.000000 86.444000 0.084000 86.476000 ;
  END
 END k_lo_d[445]
 PIN k_lo_d[446]
  DIRECTION INPUT ;
  USE SIGNAL ;
  PORT
   LAYER M4 ;
   RECT 0.000000 86.636000 0.084000 86.668000 ;
  END
 END k_lo_d[446]
 PIN k_lo_d[447]
  DIRECTION INPUT ;
  USE SIGNAL ;
  PORT
   LAYER M4 ;
   RECT 0.000000 86.828000 0.084000 86.860000 ;
  END
 END k_lo_d[447]
 PIN k_lo_d[448]
  DIRECTION INPUT ;
  USE SIGNAL ;
  PORT
   LAYER M4 ;
   RECT 0.000000 87.020000 0.084000 87.052000 ;
  END
 END k_lo_d[448]
 PIN k_lo_d[449]
  DIRECTION INPUT ;
  USE SIGNAL ;
  PORT
   LAYER M4 ;
   RECT 0.000000 87.164000 0.084000 87.196000 ;
  END
 END k_lo_d[449]
 PIN k_lo_d[450]
  DIRECTION INPUT ;
  USE SIGNAL ;
  PORT
   LAYER M4 ;
   RECT 0.000000 87.356000 0.084000 87.388000 ;
  END
 END k_lo_d[450]
 PIN k_lo_d[451]
  DIRECTION INPUT ;
  USE SIGNAL ;
  PORT
   LAYER M4 ;
   RECT 0.000000 87.548000 0.084000 87.580000 ;
  END
 END k_lo_d[451]
 PIN k_lo_d[452]
  DIRECTION INPUT ;
  USE SIGNAL ;
  PORT
   LAYER M4 ;
   RECT 0.000000 87.740000 0.084000 87.772000 ;
  END
 END k_lo_d[452]
 PIN k_lo_d[453]
  DIRECTION INPUT ;
  USE SIGNAL ;
  PORT
   LAYER M4 ;
   RECT 0.000000 87.884000 0.084000 87.916000 ;
  END
 END k_lo_d[453]
 PIN k_lo_d[454]
  DIRECTION INPUT ;
  USE SIGNAL ;
  PORT
   LAYER M4 ;
   RECT 0.000000 88.076000 0.084000 88.108000 ;
  END
 END k_lo_d[454]
 PIN k_lo_d[455]
  DIRECTION INPUT ;
  USE SIGNAL ;
  PORT
   LAYER M4 ;
   RECT 0.000000 88.268000 0.084000 88.300000 ;
  END
 END k_lo_d[455]
 PIN k_lo_d[456]
  DIRECTION INPUT ;
  USE SIGNAL ;
  PORT
   LAYER M4 ;
   RECT 0.000000 88.460000 0.084000 88.492000 ;
  END
 END k_lo_d[456]
 PIN k_lo_d[457]
  DIRECTION INPUT ;
  USE SIGNAL ;
  PORT
   LAYER M4 ;
   RECT 0.000000 88.604000 0.084000 88.636000 ;
  END
 END k_lo_d[457]
 PIN k_lo_d[458]
  DIRECTION INPUT ;
  USE SIGNAL ;
  PORT
   LAYER M4 ;
   RECT 0.000000 88.796000 0.084000 88.828000 ;
  END
 END k_lo_d[458]
 PIN k_lo_d[459]
  DIRECTION INPUT ;
  USE SIGNAL ;
  PORT
   LAYER M4 ;
   RECT 0.000000 88.988000 0.084000 89.020000 ;
  END
 END k_lo_d[459]
 PIN k_lo_d[460]
  DIRECTION INPUT ;
  USE SIGNAL ;
  PORT
   LAYER M4 ;
   RECT 0.000000 89.180000 0.084000 89.212000 ;
  END
 END k_lo_d[460]
 PIN k_lo_d[461]
  DIRECTION INPUT ;
  USE SIGNAL ;
  PORT
   LAYER M4 ;
   RECT 0.000000 89.324000 0.084000 89.356000 ;
  END
 END k_lo_d[461]
 PIN k_lo_d[462]
  DIRECTION INPUT ;
  USE SIGNAL ;
  PORT
   LAYER M4 ;
   RECT 0.000000 89.516000 0.084000 89.548000 ;
  END
 END k_lo_d[462]
 PIN k_lo_d[463]
  DIRECTION INPUT ;
  USE SIGNAL ;
  PORT
   LAYER M4 ;
   RECT 0.000000 89.708000 0.084000 89.740000 ;
  END
 END k_lo_d[463]
 PIN k_lo_d[464]
  DIRECTION INPUT ;
  USE SIGNAL ;
  PORT
   LAYER M4 ;
   RECT 0.000000 89.900000 0.084000 89.932000 ;
  END
 END k_lo_d[464]
 PIN k_lo_d[465]
  DIRECTION INPUT ;
  USE SIGNAL ;
  PORT
   LAYER M4 ;
   RECT 0.000000 90.044000 0.084000 90.076000 ;
  END
 END k_lo_d[465]
 PIN k_lo_d[466]
  DIRECTION INPUT ;
  USE SIGNAL ;
  PORT
   LAYER M4 ;
   RECT 0.000000 90.236000 0.084000 90.268000 ;
  END
 END k_lo_d[466]
 PIN k_lo_d[467]
  DIRECTION INPUT ;
  USE SIGNAL ;
  PORT
   LAYER M4 ;
   RECT 0.000000 90.428000 0.084000 90.460000 ;
  END
 END k_lo_d[467]
 PIN k_lo_d[468]
  DIRECTION INPUT ;
  USE SIGNAL ;
  PORT
   LAYER M4 ;
   RECT 0.000000 90.620000 0.084000 90.652000 ;
  END
 END k_lo_d[468]
 PIN k_lo_d[469]
  DIRECTION INPUT ;
  USE SIGNAL ;
  PORT
   LAYER M4 ;
   RECT 0.000000 90.764000 0.084000 90.796000 ;
  END
 END k_lo_d[469]
 PIN k_lo_d[470]
  DIRECTION INPUT ;
  USE SIGNAL ;
  PORT
   LAYER M4 ;
   RECT 0.000000 90.956000 0.084000 90.988000 ;
  END
 END k_lo_d[470]
 PIN k_lo_d[471]
  DIRECTION INPUT ;
  USE SIGNAL ;
  PORT
   LAYER M4 ;
   RECT 0.000000 91.148000 0.084000 91.180000 ;
  END
 END k_lo_d[471]
 PIN k_lo_d[472]
  DIRECTION INPUT ;
  USE SIGNAL ;
  PORT
   LAYER M4 ;
   RECT 0.000000 91.340000 0.084000 91.372000 ;
  END
 END k_lo_d[472]
 PIN k_lo_d[473]
  DIRECTION INPUT ;
  USE SIGNAL ;
  PORT
   LAYER M4 ;
   RECT 0.000000 91.484000 0.084000 91.516000 ;
  END
 END k_lo_d[473]
 PIN k_lo_d[474]
  DIRECTION INPUT ;
  USE SIGNAL ;
  PORT
   LAYER M4 ;
   RECT 0.000000 91.676000 0.084000 91.708000 ;
  END
 END k_lo_d[474]
 PIN k_lo_d[475]
  DIRECTION INPUT ;
  USE SIGNAL ;
  PORT
   LAYER M4 ;
   RECT 0.000000 91.868000 0.084000 91.900000 ;
  END
 END k_lo_d[475]
 PIN k_lo_d[476]
  DIRECTION INPUT ;
  USE SIGNAL ;
  PORT
   LAYER M4 ;
   RECT 0.000000 92.060000 0.084000 92.092000 ;
  END
 END k_lo_d[476]
 PIN k_lo_d[477]
  DIRECTION INPUT ;
  USE SIGNAL ;
  PORT
   LAYER M4 ;
   RECT 0.000000 92.204000 0.084000 92.236000 ;
  END
 END k_lo_d[477]
 PIN k_lo_d[478]
  DIRECTION INPUT ;
  USE SIGNAL ;
  PORT
   LAYER M4 ;
   RECT 0.000000 92.396000 0.084000 92.428000 ;
  END
 END k_lo_d[478]
 PIN k_lo_d[479]
  DIRECTION INPUT ;
  USE SIGNAL ;
  PORT
   LAYER M4 ;
   RECT 0.000000 92.588000 0.084000 92.620000 ;
  END
 END k_lo_d[479]
 PIN k_lo_d[480]
  DIRECTION INPUT ;
  USE SIGNAL ;
  PORT
   LAYER M4 ;
   RECT 0.000000 92.780000 0.084000 92.812000 ;
  END
 END k_lo_d[480]
 PIN k_lo_d[481]
  DIRECTION INPUT ;
  USE SIGNAL ;
  PORT
   LAYER M4 ;
   RECT 0.000000 92.924000 0.084000 92.956000 ;
  END
 END k_lo_d[481]
 PIN k_lo_d[482]
  DIRECTION INPUT ;
  USE SIGNAL ;
  PORT
   LAYER M4 ;
   RECT 0.000000 93.116000 0.084000 93.148000 ;
  END
 END k_lo_d[482]
 PIN k_lo_d[483]
  DIRECTION INPUT ;
  USE SIGNAL ;
  PORT
   LAYER M4 ;
   RECT 0.000000 93.308000 0.084000 93.340000 ;
  END
 END k_lo_d[483]
 PIN k_lo_d[484]
  DIRECTION INPUT ;
  USE SIGNAL ;
  PORT
   LAYER M4 ;
   RECT 0.000000 93.500000 0.084000 93.532000 ;
  END
 END k_lo_d[484]
 PIN k_lo_d[485]
  DIRECTION INPUT ;
  USE SIGNAL ;
  PORT
   LAYER M4 ;
   RECT 0.000000 93.644000 0.084000 93.676000 ;
  END
 END k_lo_d[485]
 PIN k_lo_d[486]
  DIRECTION INPUT ;
  USE SIGNAL ;
  PORT
   LAYER M4 ;
   RECT 0.000000 93.836000 0.084000 93.868000 ;
  END
 END k_lo_d[486]
 PIN k_lo_d[487]
  DIRECTION INPUT ;
  USE SIGNAL ;
  PORT
   LAYER M4 ;
   RECT 0.000000 94.028000 0.084000 94.060000 ;
  END
 END k_lo_d[487]
 PIN k_lo_d[488]
  DIRECTION INPUT ;
  USE SIGNAL ;
  PORT
   LAYER M4 ;
   RECT 0.000000 94.172000 0.084000 94.204000 ;
  END
 END k_lo_d[488]
 PIN k_lo_d[489]
  DIRECTION INPUT ;
  USE SIGNAL ;
  PORT
   LAYER M4 ;
   RECT 0.000000 94.364000 0.084000 94.396000 ;
  END
 END k_lo_d[489]
 PIN k_lo_d[490]
  DIRECTION INPUT ;
  USE SIGNAL ;
  PORT
   LAYER M4 ;
   RECT 0.000000 94.556000 0.084000 94.588000 ;
  END
 END k_lo_d[490]
 PIN k_lo_d[491]
  DIRECTION INPUT ;
  USE SIGNAL ;
  PORT
   LAYER M4 ;
   RECT 0.000000 94.748000 0.084000 94.780000 ;
  END
 END k_lo_d[491]
 PIN k_lo_d[492]
  DIRECTION INPUT ;
  USE SIGNAL ;
  PORT
   LAYER M4 ;
   RECT 0.000000 94.892000 0.084000 94.924000 ;
  END
 END k_lo_d[492]
 PIN k_lo_d[493]
  DIRECTION INPUT ;
  USE SIGNAL ;
  PORT
   LAYER M4 ;
   RECT 0.000000 95.084000 0.084000 95.116000 ;
  END
 END k_lo_d[493]
 PIN k_lo_d[494]
  DIRECTION INPUT ;
  USE SIGNAL ;
  PORT
   LAYER M4 ;
   RECT 0.000000 95.276000 0.084000 95.308000 ;
  END
 END k_lo_d[494]
 PIN k_lo_d[495]
  DIRECTION INPUT ;
  USE SIGNAL ;
  PORT
   LAYER M4 ;
   RECT 0.000000 95.468000 0.084000 95.500000 ;
  END
 END k_lo_d[495]
 PIN k_lo_d[496]
  DIRECTION INPUT ;
  USE SIGNAL ;
  PORT
   LAYER M4 ;
   RECT 0.000000 95.612000 0.084000 95.644000 ;
  END
 END k_lo_d[496]
 PIN k_lo_d[497]
  DIRECTION INPUT ;
  USE SIGNAL ;
  PORT
   LAYER M4 ;
   RECT 0.000000 95.804000 0.084000 95.836000 ;
  END
 END k_lo_d[497]
 PIN k_lo_d[498]
  DIRECTION INPUT ;
  USE SIGNAL ;
  PORT
   LAYER M4 ;
   RECT 0.000000 95.996000 0.084000 96.028000 ;
  END
 END k_lo_d[498]
 PIN k_lo_d[499]
  DIRECTION INPUT ;
  USE SIGNAL ;
  PORT
   LAYER M4 ;
   RECT 0.000000 96.188000 0.084000 96.220000 ;
  END
 END k_lo_d[499]
 PIN k_lo_d[500]
  DIRECTION INPUT ;
  USE SIGNAL ;
  PORT
   LAYER M4 ;
   RECT 0.000000 96.332000 0.084000 96.364000 ;
  END
 END k_lo_d[500]
 PIN k_lo_d[501]
  DIRECTION INPUT ;
  USE SIGNAL ;
  PORT
   LAYER M4 ;
   RECT 0.000000 96.524000 0.084000 96.556000 ;
  END
 END k_lo_d[501]
 PIN k_lo_d[502]
  DIRECTION INPUT ;
  USE SIGNAL ;
  PORT
   LAYER M4 ;
   RECT 0.000000 96.716000 0.084000 96.748000 ;
  END
 END k_lo_d[502]
 PIN k_lo_d[503]
  DIRECTION INPUT ;
  USE SIGNAL ;
  PORT
   LAYER M4 ;
   RECT 0.000000 96.908000 0.084000 96.940000 ;
  END
 END k_lo_d[503]
 PIN k_lo_d[504]
  DIRECTION INPUT ;
  USE SIGNAL ;
  PORT
   LAYER M4 ;
   RECT 0.000000 97.052000 0.084000 97.084000 ;
  END
 END k_lo_d[504]
 PIN k_lo_d[505]
  DIRECTION INPUT ;
  USE SIGNAL ;
  PORT
   LAYER M4 ;
   RECT 0.000000 97.244000 0.084000 97.276000 ;
  END
 END k_lo_d[505]
 PIN k_lo_d[506]
  DIRECTION INPUT ;
  USE SIGNAL ;
  PORT
   LAYER M4 ;
   RECT 0.000000 97.436000 0.084000 97.468000 ;
  END
 END k_lo_d[506]
 PIN k_lo_d[507]
  DIRECTION INPUT ;
  USE SIGNAL ;
  PORT
   LAYER M4 ;
   RECT 0.000000 97.628000 0.084000 97.660000 ;
  END
 END k_lo_d[507]
 PIN k_lo_d[508]
  DIRECTION INPUT ;
  USE SIGNAL ;
  PORT
   LAYER M4 ;
   RECT 0.000000 97.772000 0.084000 97.804000 ;
  END
 END k_lo_d[508]
 PIN k_lo_d[509]
  DIRECTION INPUT ;
  USE SIGNAL ;
  PORT
   LAYER M4 ;
   RECT 0.000000 97.964000 0.084000 97.996000 ;
  END
 END k_lo_d[509]
 PIN k_lo_d[510]
  DIRECTION INPUT ;
  USE SIGNAL ;
  PORT
   LAYER M4 ;
   RECT 0.000000 98.156000 0.084000 98.188000 ;
  END
 END k_lo_d[510]
 PIN k_lo_d[511]
  DIRECTION INPUT ;
  USE SIGNAL ;
  PORT
   LAYER M4 ;
   RECT 0.000000 98.348000 0.084000 98.380000 ;
  END
 END k_lo_d[511]
 PIN k_lo_d[512]
  DIRECTION INPUT ;
  USE SIGNAL ;
  PORT
   LAYER M4 ;
   RECT 0.000000 98.492000 0.084000 98.524000 ;
  END
 END k_lo_d[512]
 PIN k_lo_d[513]
  DIRECTION INPUT ;
  USE SIGNAL ;
  PORT
   LAYER M4 ;
   RECT 0.000000 98.684000 0.084000 98.716000 ;
  END
 END k_lo_d[513]
 PIN k_lo_d[514]
  DIRECTION INPUT ;
  USE SIGNAL ;
  PORT
   LAYER M4 ;
   RECT 0.000000 98.876000 0.084000 98.908000 ;
  END
 END k_lo_d[514]
 PIN k_lo_d[515]
  DIRECTION INPUT ;
  USE SIGNAL ;
  PORT
   LAYER M4 ;
   RECT 0.000000 99.068000 0.084000 99.100000 ;
  END
 END k_lo_d[515]
 PIN k_lo_d[516]
  DIRECTION INPUT ;
  USE SIGNAL ;
  PORT
   LAYER M4 ;
   RECT 0.000000 99.212000 0.084000 99.244000 ;
  END
 END k_lo_d[516]
 PIN k_lo_d[517]
  DIRECTION INPUT ;
  USE SIGNAL ;
  PORT
   LAYER M4 ;
   RECT 0.000000 99.404000 0.084000 99.436000 ;
  END
 END k_lo_d[517]
 PIN k_lo_d[518]
  DIRECTION INPUT ;
  USE SIGNAL ;
  PORT
   LAYER M4 ;
   RECT 0.000000 99.596000 0.084000 99.628000 ;
  END
 END k_lo_d[518]
 PIN k_lo_d[519]
  DIRECTION INPUT ;
  USE SIGNAL ;
  PORT
   LAYER M4 ;
   RECT 0.000000 99.788000 0.084000 99.820000 ;
  END
 END k_lo_d[519]
 PIN k_lo_d[520]
  DIRECTION INPUT ;
  USE SIGNAL ;
  PORT
   LAYER M4 ;
   RECT 0.000000 99.932000 0.084000 99.964000 ;
  END
 END k_lo_d[520]
 PIN k_lo_d[521]
  DIRECTION INPUT ;
  USE SIGNAL ;
  PORT
   LAYER M4 ;
   RECT 0.000000 100.124000 0.084000 100.156000 ;
  END
 END k_lo_d[521]
 PIN k_lo_d[522]
  DIRECTION INPUT ;
  USE SIGNAL ;
  PORT
   LAYER M4 ;
   RECT 0.000000 100.316000 0.084000 100.348000 ;
  END
 END k_lo_d[522]
 PIN k_lo_d[523]
  DIRECTION INPUT ;
  USE SIGNAL ;
  PORT
   LAYER M4 ;
   RECT 0.000000 100.508000 0.084000 100.540000 ;
  END
 END k_lo_d[523]
 PIN k_lo_d[524]
  DIRECTION INPUT ;
  USE SIGNAL ;
  PORT
   LAYER M4 ;
   RECT 0.000000 100.652000 0.084000 100.684000 ;
  END
 END k_lo_d[524]
 PIN k_lo_d[525]
  DIRECTION INPUT ;
  USE SIGNAL ;
  PORT
   LAYER M4 ;
   RECT 0.000000 100.844000 0.084000 100.876000 ;
  END
 END k_lo_d[525]
 PIN k_lo_d[526]
  DIRECTION INPUT ;
  USE SIGNAL ;
  PORT
   LAYER M4 ;
   RECT 0.000000 101.036000 0.084000 101.068000 ;
  END
 END k_lo_d[526]
 PIN k_lo_d[527]
  DIRECTION INPUT ;
  USE SIGNAL ;
  PORT
   LAYER M4 ;
   RECT 0.000000 101.228000 0.084000 101.260000 ;
  END
 END k_lo_d[527]
 PIN k_lo_d[528]
  DIRECTION INPUT ;
  USE SIGNAL ;
  PORT
   LAYER M4 ;
   RECT 0.000000 101.372000 0.084000 101.404000 ;
  END
 END k_lo_d[528]
 PIN k_lo_d[529]
  DIRECTION INPUT ;
  USE SIGNAL ;
  PORT
   LAYER M4 ;
   RECT 0.000000 101.564000 0.084000 101.596000 ;
  END
 END k_lo_d[529]
 PIN k_lo_d[530]
  DIRECTION INPUT ;
  USE SIGNAL ;
  PORT
   LAYER M4 ;
   RECT 0.000000 101.756000 0.084000 101.788000 ;
  END
 END k_lo_d[530]
 PIN k_lo_d[531]
  DIRECTION INPUT ;
  USE SIGNAL ;
  PORT
   LAYER M4 ;
   RECT 0.000000 101.948000 0.084000 101.980000 ;
  END
 END k_lo_d[531]
 PIN k_lo_d[532]
  DIRECTION INPUT ;
  USE SIGNAL ;
  PORT
   LAYER M4 ;
   RECT 0.000000 102.092000 0.084000 102.124000 ;
  END
 END k_lo_d[532]
 PIN k_lo_d[533]
  DIRECTION INPUT ;
  USE SIGNAL ;
  PORT
   LAYER M4 ;
   RECT 0.000000 102.284000 0.084000 102.316000 ;
  END
 END k_lo_d[533]
 PIN k_lo_d[534]
  DIRECTION INPUT ;
  USE SIGNAL ;
  PORT
   LAYER M4 ;
   RECT 0.000000 102.476000 0.084000 102.508000 ;
  END
 END k_lo_d[534]
 PIN k_lo_d[535]
  DIRECTION INPUT ;
  USE SIGNAL ;
  PORT
   LAYER M4 ;
   RECT 0.000000 102.668000 0.084000 102.700000 ;
  END
 END k_lo_d[535]
 PIN k_lo_d[536]
  DIRECTION INPUT ;
  USE SIGNAL ;
  PORT
   LAYER M4 ;
   RECT 0.000000 102.812000 0.084000 102.844000 ;
  END
 END k_lo_d[536]
 PIN k_lo_d[537]
  DIRECTION INPUT ;
  USE SIGNAL ;
  PORT
   LAYER M4 ;
   RECT 0.000000 103.004000 0.084000 103.036000 ;
  END
 END k_lo_d[537]
 PIN k_lo_d[538]
  DIRECTION INPUT ;
  USE SIGNAL ;
  PORT
   LAYER M4 ;
   RECT 0.000000 103.196000 0.084000 103.228000 ;
  END
 END k_lo_d[538]
 PIN k_lo_d[539]
  DIRECTION INPUT ;
  USE SIGNAL ;
  PORT
   LAYER M4 ;
   RECT 0.000000 103.388000 0.084000 103.420000 ;
  END
 END k_lo_d[539]
 PIN k_lo_d[540]
  DIRECTION INPUT ;
  USE SIGNAL ;
  PORT
   LAYER M4 ;
   RECT 0.000000 103.532000 0.084000 103.564000 ;
  END
 END k_lo_d[540]
 PIN k_lo_d[541]
  DIRECTION INPUT ;
  USE SIGNAL ;
  PORT
   LAYER M4 ;
   RECT 0.000000 103.724000 0.084000 103.756000 ;
  END
 END k_lo_d[541]
 PIN k_lo_d[542]
  DIRECTION INPUT ;
  USE SIGNAL ;
  PORT
   LAYER M4 ;
   RECT 0.000000 103.916000 0.084000 103.948000 ;
  END
 END k_lo_d[542]
 PIN k_lo_d[543]
  DIRECTION INPUT ;
  USE SIGNAL ;
  PORT
   LAYER M4 ;
   RECT 0.000000 104.108000 0.084000 104.140000 ;
  END
 END k_lo_d[543]
 PIN k_lo_d[544]
  DIRECTION INPUT ;
  USE SIGNAL ;
  PORT
   LAYER M4 ;
   RECT 0.000000 104.252000 0.084000 104.284000 ;
  END
 END k_lo_d[544]
 PIN k_lo_d[545]
  DIRECTION INPUT ;
  USE SIGNAL ;
  PORT
   LAYER M4 ;
   RECT 0.000000 104.444000 0.084000 104.476000 ;
  END
 END k_lo_d[545]
 PIN k_lo_d[546]
  DIRECTION INPUT ;
  USE SIGNAL ;
  PORT
   LAYER M4 ;
   RECT 0.000000 104.636000 0.084000 104.668000 ;
  END
 END k_lo_d[546]
 PIN k_lo_d[547]
  DIRECTION INPUT ;
  USE SIGNAL ;
  PORT
   LAYER M4 ;
   RECT 0.000000 104.828000 0.084000 104.860000 ;
  END
 END k_lo_d[547]
 PIN k_lo_d[548]
  DIRECTION INPUT ;
  USE SIGNAL ;
  PORT
   LAYER M4 ;
   RECT 0.000000 104.972000 0.084000 105.004000 ;
  END
 END k_lo_d[548]
 PIN k_lo_d[549]
  DIRECTION INPUT ;
  USE SIGNAL ;
  PORT
   LAYER M4 ;
   RECT 0.000000 105.164000 0.084000 105.196000 ;
  END
 END k_lo_d[549]
 PIN k_lo_d[550]
  DIRECTION INPUT ;
  USE SIGNAL ;
  PORT
   LAYER M4 ;
   RECT 0.000000 105.356000 0.084000 105.388000 ;
  END
 END k_lo_d[550]
 PIN k_lo_d[551]
  DIRECTION INPUT ;
  USE SIGNAL ;
  PORT
   LAYER M4 ;
   RECT 0.000000 105.548000 0.084000 105.580000 ;
  END
 END k_lo_d[551]
 PIN k_lo_d[552]
  DIRECTION INPUT ;
  USE SIGNAL ;
  PORT
   LAYER M4 ;
   RECT 0.000000 105.692000 0.084000 105.724000 ;
  END
 END k_lo_d[552]
 PIN k_li_r
  DIRECTION INPUT ;
  USE SIGNAL ;
  PORT
   LAYER M4 ;
   RECT 0.000000 105.884000 0.084000 105.916000 ;
  END
 END k_li_r
 PIN k_rxv
  DIRECTION INPUT ;
  USE SIGNAL ;
  PORT
   LAYER M4 ;
   RECT 0.000000 106.076000 0.084000 106.108000 ;
  END
 END k_rxv
 PIN k_lo_r
  DIRECTION OUTPUT ;
  USE SIGNAL ;
  PORT
   LAYER M5 ;
   RECT 6.180000 0.000000 6.228000 0.084000 ;
  END
 END k_lo_r
 PIN k_li_v
  DIRECTION OUTPUT ;
  USE SIGNAL ;
  PORT
   LAYER M5 ;
   RECT 6.756000 0.000000 6.804000 0.084000 ;
  END
 END k_li_v
 PIN k_li_d[0]
  DIRECTION OUTPUT ;
  USE SIGNAL ;
  PORT
   LAYER M5 ;
   RECT 6.804000 0.000000 6.852000 0.084000 ;
  END
 END k_li_d[0]
 PIN k_li_d[1]
  DIRECTION OUTPUT ;
  USE SIGNAL ;
  PORT
   LAYER M5 ;
   RECT 6.852000 0.000000 6.900000 0.084000 ;
  END
 END k_li_d[1]
 PIN k_li_d[2]
  DIRECTION OUTPUT ;
  USE SIGNAL ;
  PORT
   LAYER M5 ;
   RECT 6.948000 0.000000 6.996000 0.084000 ;
  END
 END k_li_d[2]
 PIN k_li_d[3]
  DIRECTION OUTPUT ;
  USE SIGNAL ;
  PORT
   LAYER M5 ;
   RECT 7.092000 0.000000 7.140000 0.084000 ;
  END
 END k_li_d[3]
 PIN k_li_d[4]
  DIRECTION OUTPUT ;
  USE SIGNAL ;
  PORT
   LAYER M5 ;
   RECT 7.284000 0.000000 7.332000 0.084000 ;
  END
 END k_li_d[4]
 PIN k_li_d[5]
  DIRECTION OUTPUT ;
  USE SIGNAL ;
  PORT
   LAYER M5 ;
   RECT 7.476000 0.000000 7.524000 0.084000 ;
  END
 END k_li_d[5]
 PIN k_li_d[6]
  DIRECTION OUTPUT ;
  USE SIGNAL ;
  PORT
   LAYER M5 ;
   RECT 7.620000 0.000000 7.668000 0.084000 ;
  END
 END k_li_d[6]
 PIN k_li_d[7]
  DIRECTION OUTPUT ;
  USE SIGNAL ;
  PORT
   LAYER M5 ;
   RECT 7.812000 0.000000 7.860000 0.084000 ;
  END
 END k_li_d[7]
 PIN k_li_d[8]
  DIRECTION OUTPUT ;
  USE SIGNAL ;
  PORT
   LAYER M5 ;
   RECT 8.004000 0.000000 8.052000 0.084000 ;
  END
 END k_li_d[8]
 PIN k_li_d[9]
  DIRECTION OUTPUT ;
  USE SIGNAL ;
  PORT
   LAYER M5 ;
   RECT 8.196000 0.000000 8.244000 0.084000 ;
  END
 END k_li_d[9]
 PIN k_li_d[10]
  DIRECTION OUTPUT ;
  USE SIGNAL ;
  PORT
   LAYER M5 ;
   RECT 8.340000 0.000000 8.388000 0.084000 ;
  END
 END k_li_d[10]
 PIN k_li_d[11]
  DIRECTION OUTPUT ;
  USE SIGNAL ;
  PORT
   LAYER M5 ;
   RECT 8.532000 0.000000 8.580000 0.084000 ;
  END
 END k_li_d[11]
 PIN k_li_d[12]
  DIRECTION OUTPUT ;
  USE SIGNAL ;
  PORT
   LAYER M5 ;
   RECT 8.724000 0.000000 8.772000 0.084000 ;
  END
 END k_li_d[12]
 PIN k_li_d[13]
  DIRECTION OUTPUT ;
  USE SIGNAL ;
  PORT
   LAYER M5 ;
   RECT 8.916000 0.000000 8.964000 0.084000 ;
  END
 END k_li_d[13]
 PIN k_li_d[14]
  DIRECTION OUTPUT ;
  USE SIGNAL ;
  PORT
   LAYER M5 ;
   RECT 9.060000 0.000000 9.108000 0.084000 ;
  END
 END k_li_d[14]
 PIN k_li_d[15]
  DIRECTION OUTPUT ;
  USE SIGNAL ;
  PORT
   LAYER M5 ;
   RECT 9.252000 0.000000 9.300000 0.084000 ;
  END
 END k_li_d[15]
 PIN k_li_d[16]
  DIRECTION OUTPUT ;
  USE SIGNAL ;
  PORT
   LAYER M5 ;
   RECT 9.444000 0.000000 9.492000 0.084000 ;
  END
 END k_li_d[16]
 PIN k_li_d[17]
  DIRECTION OUTPUT ;
  USE SIGNAL ;
  PORT
   LAYER M5 ;
   RECT 9.636000 0.000000 9.684000 0.084000 ;
  END
 END k_li_d[17]
 PIN k_li_d[18]
  DIRECTION OUTPUT ;
  USE SIGNAL ;
  PORT
   LAYER M5 ;
   RECT 9.780000 0.000000 9.828000 0.084000 ;
  END
 END k_li_d[18]
 PIN k_li_d[19]
  DIRECTION OUTPUT ;
  USE SIGNAL ;
  PORT
   LAYER M5 ;
   RECT 9.972000 0.000000 10.020000 0.084000 ;
  END
 END k_li_d[19]
 PIN k_li_d[20]
  DIRECTION OUTPUT ;
  USE SIGNAL ;
  PORT
   LAYER M5 ;
   RECT 10.164000 0.000000 10.212000 0.084000 ;
  END
 END k_li_d[20]
 PIN k_li_d[21]
  DIRECTION OUTPUT ;
  USE SIGNAL ;
  PORT
   LAYER M5 ;
   RECT 10.356000 0.000000 10.404000 0.084000 ;
  END
 END k_li_d[21]
 PIN k_li_d[22]
  DIRECTION OUTPUT ;
  USE SIGNAL ;
  PORT
   LAYER M5 ;
   RECT 10.500000 0.000000 10.548000 0.084000 ;
  END
 END k_li_d[22]
 PIN k_li_d[23]
  DIRECTION OUTPUT ;
  USE SIGNAL ;
  PORT
   LAYER M5 ;
   RECT 11.076000 0.000000 11.124000 0.084000 ;
  END
 END k_li_d[23]
 PIN k_li_d[24]
  DIRECTION OUTPUT ;
  USE SIGNAL ;
  PORT
   LAYER M5 ;
   RECT 11.124000 0.000000 11.172000 0.084000 ;
  END
 END k_li_d[24]
 PIN k_li_d[25]
  DIRECTION OUTPUT ;
  USE SIGNAL ;
  PORT
   LAYER M5 ;
   RECT 11.172000 0.000000 11.220000 0.084000 ;
  END
 END k_li_d[25]
 PIN k_li_d[26]
  DIRECTION OUTPUT ;
  USE SIGNAL ;
  PORT
   LAYER M5 ;
   RECT 11.220000 0.000000 11.268000 0.084000 ;
  END
 END k_li_d[26]
 PIN k_li_d[27]
  DIRECTION OUTPUT ;
  USE SIGNAL ;
  PORT
   LAYER M5 ;
   RECT 11.412000 0.000000 11.460000 0.084000 ;
  END
 END k_li_d[27]
 PIN k_li_d[28]
  DIRECTION OUTPUT ;
  USE SIGNAL ;
  PORT
   LAYER M5 ;
   RECT 11.604000 0.000000 11.652000 0.084000 ;
  END
 END k_li_d[28]
 PIN k_li_d[29]
  DIRECTION OUTPUT ;
  USE SIGNAL ;
  PORT
   LAYER M5 ;
   RECT 11.748000 0.000000 11.796000 0.084000 ;
  END
 END k_li_d[29]
 PIN k_li_d[30]
  DIRECTION OUTPUT ;
  USE SIGNAL ;
  PORT
   LAYER M5 ;
   RECT 11.940000 0.000000 11.988000 0.084000 ;
  END
 END k_li_d[30]
 PIN k_li_d[31]
  DIRECTION OUTPUT ;
  USE SIGNAL ;
  PORT
   LAYER M5 ;
   RECT 12.132000 0.000000 12.180000 0.084000 ;
  END
 END k_li_d[31]
 PIN k_li_d[32]
  DIRECTION OUTPUT ;
  USE SIGNAL ;
  PORT
   LAYER M5 ;
   RECT 12.324000 0.000000 12.372000 0.084000 ;
  END
 END k_li_d[32]
 PIN k_li_d[33]
  DIRECTION OUTPUT ;
  USE SIGNAL ;
  PORT
   LAYER M5 ;
   RECT 12.468000 0.000000 12.516000 0.084000 ;
  END
 END k_li_d[33]
 PIN k_li_d[34]
  DIRECTION OUTPUT ;
  USE SIGNAL ;
  PORT
   LAYER M5 ;
   RECT 12.660000 0.000000 12.708000 0.084000 ;
  END
 END k_li_d[34]
 PIN k_li_d[35]
  DIRECTION OUTPUT ;
  USE SIGNAL ;
  PORT
   LAYER M5 ;
   RECT 12.852000 0.000000 12.900000 0.084000 ;
  END
 END k_li_d[35]
 PIN k_li_d[36]
  DIRECTION OUTPUT ;
  USE SIGNAL ;
  PORT
   LAYER M5 ;
   RECT 13.044000 0.000000 13.092000 0.084000 ;
  END
 END k_li_d[36]
 PIN k_li_d[37]
  DIRECTION OUTPUT ;
  USE SIGNAL ;
  PORT
   LAYER M5 ;
   RECT 13.188000 0.000000 13.236000 0.084000 ;
  END
 END k_li_d[37]
 PIN k_li_d[38]
  DIRECTION OUTPUT ;
  USE SIGNAL ;
  PORT
   LAYER M5 ;
   RECT 13.380000 0.000000 13.428000 0.084000 ;
  END
 END k_li_d[38]
 PIN k_li_d[39]
  DIRECTION OUTPUT ;
  USE SIGNAL ;
  PORT
   LAYER M5 ;
   RECT 13.572000 0.000000 13.620000 0.084000 ;
  END
 END k_li_d[39]
 PIN k_li_d[40]
  DIRECTION OUTPUT ;
  USE SIGNAL ;
  PORT
   LAYER M5 ;
   RECT 13.716000 0.000000 13.764000 0.084000 ;
  END
 END k_li_d[40]
 PIN k_li_d[41]
  DIRECTION OUTPUT ;
  USE SIGNAL ;
  PORT
   LAYER M5 ;
   RECT 13.908000 0.000000 13.956000 0.084000 ;
  END
 END k_li_d[41]
 PIN k_li_d[42]
  DIRECTION OUTPUT ;
  USE SIGNAL ;
  PORT
   LAYER M5 ;
   RECT 14.100000 0.000000 14.148000 0.084000 ;
  END
 END k_li_d[42]
 PIN k_li_d[43]
  DIRECTION OUTPUT ;
  USE SIGNAL ;
  PORT
   LAYER M5 ;
   RECT 14.292000 0.000000 14.340000 0.084000 ;
  END
 END k_li_d[43]
 PIN k_li_d[44]
  DIRECTION OUTPUT ;
  USE SIGNAL ;
  PORT
   LAYER M5 ;
   RECT 14.436000 0.000000 14.484000 0.084000 ;
  END
 END k_li_d[44]
 PIN k_li_d[45]
  DIRECTION OUTPUT ;
  USE SIGNAL ;
  PORT
   LAYER M5 ;
   RECT 14.628000 0.000000 14.676000 0.084000 ;
  END
 END k_li_d[45]
 PIN k_li_d[46]
  DIRECTION OUTPUT ;
  USE SIGNAL ;
  PORT
   LAYER M5 ;
   RECT 14.820000 0.000000 14.868000 0.084000 ;
  END
 END k_li_d[46]
 PIN k_li_d[47]
  DIRECTION OUTPUT ;
  USE SIGNAL ;
  PORT
   LAYER M5 ;
   RECT 15.396000 0.000000 15.444000 0.084000 ;
  END
 END k_li_d[47]
 PIN k_li_d[48]
  DIRECTION OUTPUT ;
  USE SIGNAL ;
  PORT
   LAYER M5 ;
   RECT 15.444000 0.000000 15.492000 0.084000 ;
  END
 END k_li_d[48]
 PIN k_li_d[49]
  DIRECTION OUTPUT ;
  USE SIGNAL ;
  PORT
   LAYER M5 ;
   RECT 15.492000 0.000000 15.540000 0.084000 ;
  END
 END k_li_d[49]
 PIN k_li_d[50]
  DIRECTION OUTPUT ;
  USE SIGNAL ;
  PORT
   LAYER M5 ;
   RECT 15.540000 0.000000 15.588000 0.084000 ;
  END
 END k_li_d[50]
 PIN k_li_d[51]
  DIRECTION OUTPUT ;
  USE SIGNAL ;
  PORT
   LAYER M5 ;
   RECT 15.732000 0.000000 15.780000 0.084000 ;
  END
 END k_li_d[51]
 PIN k_li_d[52]
  DIRECTION OUTPUT ;
  USE SIGNAL ;
  PORT
   LAYER M5 ;
   RECT 15.876000 0.000000 15.924000 0.084000 ;
  END
 END k_li_d[52]
 PIN k_li_d[53]
  DIRECTION OUTPUT ;
  USE SIGNAL ;
  PORT
   LAYER M5 ;
   RECT 16.068000 0.000000 16.116000 0.084000 ;
  END
 END k_li_d[53]
 PIN k_li_d[54]
  DIRECTION OUTPUT ;
  USE SIGNAL ;
  PORT
   LAYER M5 ;
   RECT 16.260000 0.000000 16.308000 0.084000 ;
  END
 END k_li_d[54]
 PIN k_li_d[55]
  DIRECTION OUTPUT ;
  USE SIGNAL ;
  PORT
   LAYER M5 ;
   RECT 16.404000 0.000000 16.452000 0.084000 ;
  END
 END k_li_d[55]
 PIN k_li_d[56]
  DIRECTION OUTPUT ;
  USE SIGNAL ;
  PORT
   LAYER M5 ;
   RECT 16.596000 0.000000 16.644000 0.084000 ;
  END
 END k_li_d[56]
 PIN k_li_d[57]
  DIRECTION OUTPUT ;
  USE SIGNAL ;
  PORT
   LAYER M5 ;
   RECT 16.788000 0.000000 16.836000 0.084000 ;
  END
 END k_li_d[57]
 PIN k_li_d[58]
  DIRECTION OUTPUT ;
  USE SIGNAL ;
  PORT
   LAYER M5 ;
   RECT 16.980000 0.000000 17.028000 0.084000 ;
  END
 END k_li_d[58]
 PIN k_li_d[59]
  DIRECTION OUTPUT ;
  USE SIGNAL ;
  PORT
   LAYER M5 ;
   RECT 17.124000 0.000000 17.172000 0.084000 ;
  END
 END k_li_d[59]
 PIN k_li_d[60]
  DIRECTION OUTPUT ;
  USE SIGNAL ;
  PORT
   LAYER M5 ;
   RECT 17.316000 0.000000 17.364000 0.084000 ;
  END
 END k_li_d[60]
 PIN k_li_d[61]
  DIRECTION OUTPUT ;
  USE SIGNAL ;
  PORT
   LAYER M5 ;
   RECT 17.508000 0.000000 17.556000 0.084000 ;
  END
 END k_li_d[61]
 PIN k_li_d[62]
  DIRECTION OUTPUT ;
  USE SIGNAL ;
  PORT
   LAYER M5 ;
   RECT 17.700000 0.000000 17.748000 0.084000 ;
  END
 END k_li_d[62]
 PIN k_li_d[63]
  DIRECTION OUTPUT ;
  USE SIGNAL ;
  PORT
   LAYER M5 ;
   RECT 17.844000 0.000000 17.892000 0.084000 ;
  END
 END k_li_d[63]
 PIN k_li_d[64]
  DIRECTION OUTPUT ;
  USE SIGNAL ;
  PORT
   LAYER M5 ;
   RECT 18.036000 0.000000 18.084000 0.084000 ;
  END
 END k_li_d[64]
 PIN k_li_d[65]
  DIRECTION OUTPUT ;
  USE SIGNAL ;
  PORT
   LAYER M5 ;
   RECT 18.228000 0.000000 18.276000 0.084000 ;
  END
 END k_li_d[65]
 PIN k_li_d[66]
  DIRECTION OUTPUT ;
  USE SIGNAL ;
  PORT
   LAYER M5 ;
   RECT 18.420000 0.000000 18.468000 0.084000 ;
  END
 END k_li_d[66]
 PIN k_li_d[67]
  DIRECTION OUTPUT ;
  USE SIGNAL ;
  PORT
   LAYER M5 ;
   RECT 18.564000 0.000000 18.612000 0.084000 ;
  END
 END k_li_d[67]
 PIN k_li_d[68]
  DIRECTION OUTPUT ;
  USE SIGNAL ;
  PORT
   LAYER M5 ;
   RECT 18.756000 0.000000 18.804000 0.084000 ;
  END
 END k_li_d[68]
 PIN k_li_d[69]
  DIRECTION OUTPUT ;
  USE SIGNAL ;
  PORT
   LAYER M5 ;
   RECT 18.948000 0.000000 18.996000 0.084000 ;
  END
 END k_li_d[69]
 PIN k_li_d[70]
  DIRECTION OUTPUT ;
  USE SIGNAL ;
  PORT
   LAYER M5 ;
   RECT 19.140000 0.000000 19.188000 0.084000 ;
  END
 END k_li_d[70]
 PIN k_li_d[71]
  DIRECTION OUTPUT ;
  USE SIGNAL ;
  PORT
   LAYER M5 ;
   RECT 19.716000 0.000000 19.764000 0.084000 ;
  END
 END k_li_d[71]
 PIN k_li_d[72]
  DIRECTION OUTPUT ;
  USE SIGNAL ;
  PORT
   LAYER M5 ;
   RECT 19.764000 0.000000 19.812000 0.084000 ;
  END
 END k_li_d[72]
 PIN k_li_d[73]
  DIRECTION OUTPUT ;
  USE SIGNAL ;
  PORT
   LAYER M5 ;
   RECT 19.812000 0.000000 19.860000 0.084000 ;
  END
 END k_li_d[73]
 PIN k_li_d[74]
  DIRECTION OUTPUT ;
  USE SIGNAL ;
  PORT
   LAYER M5 ;
   RECT 19.860000 0.000000 19.908000 0.084000 ;
  END
 END k_li_d[74]
 PIN k_li_d[75]
  DIRECTION OUTPUT ;
  USE SIGNAL ;
  PORT
   LAYER M5 ;
   RECT 20.004000 0.000000 20.052000 0.084000 ;
  END
 END k_li_d[75]
 PIN k_li_d[76]
  DIRECTION OUTPUT ;
  USE SIGNAL ;
  PORT
   LAYER M5 ;
   RECT 20.196000 0.000000 20.244000 0.084000 ;
  END
 END k_li_d[76]
 PIN k_li_d[77]
  DIRECTION OUTPUT ;
  USE SIGNAL ;
  PORT
   LAYER M5 ;
   RECT 20.388000 0.000000 20.436000 0.084000 ;
  END
 END k_li_d[77]
 PIN k_li_d[78]
  DIRECTION OUTPUT ;
  USE SIGNAL ;
  PORT
   LAYER M5 ;
   RECT 20.532000 0.000000 20.580000 0.084000 ;
  END
 END k_li_d[78]
 PIN k_li_d[79]
  DIRECTION OUTPUT ;
  USE SIGNAL ;
  PORT
   LAYER M5 ;
   RECT 20.724000 0.000000 20.772000 0.084000 ;
  END
 END k_li_d[79]
 PIN k_li_d[80]
  DIRECTION OUTPUT ;
  USE SIGNAL ;
  PORT
   LAYER M5 ;
   RECT 20.916000 0.000000 20.964000 0.084000 ;
  END
 END k_li_d[80]
 PIN k_li_d[81]
  DIRECTION OUTPUT ;
  USE SIGNAL ;
  PORT
   LAYER M5 ;
   RECT 21.108000 0.000000 21.156000 0.084000 ;
  END
 END k_li_d[81]
 PIN k_li_d[82]
  DIRECTION OUTPUT ;
  USE SIGNAL ;
  PORT
   LAYER M5 ;
   RECT 21.252000 0.000000 21.300000 0.084000 ;
  END
 END k_li_d[82]
 PIN k_li_d[83]
  DIRECTION OUTPUT ;
  USE SIGNAL ;
  PORT
   LAYER M5 ;
   RECT 21.444000 0.000000 21.492000 0.084000 ;
  END
 END k_li_d[83]
 PIN k_li_d[84]
  DIRECTION OUTPUT ;
  USE SIGNAL ;
  PORT
   LAYER M5 ;
   RECT 21.636000 0.000000 21.684000 0.084000 ;
  END
 END k_li_d[84]
 PIN k_li_d[85]
  DIRECTION OUTPUT ;
  USE SIGNAL ;
  PORT
   LAYER M5 ;
   RECT 21.828000 0.000000 21.876000 0.084000 ;
  END
 END k_li_d[85]
 PIN k_li_d[86]
  DIRECTION OUTPUT ;
  USE SIGNAL ;
  PORT
   LAYER M5 ;
   RECT 21.972000 0.000000 22.020000 0.084000 ;
  END
 END k_li_d[86]
 PIN k_li_d[87]
  DIRECTION OUTPUT ;
  USE SIGNAL ;
  PORT
   LAYER M5 ;
   RECT 22.164000 0.000000 22.212000 0.084000 ;
  END
 END k_li_d[87]
 PIN k_li_d[88]
  DIRECTION OUTPUT ;
  USE SIGNAL ;
  PORT
   LAYER M5 ;
   RECT 22.356000 0.000000 22.404000 0.084000 ;
  END
 END k_li_d[88]
 PIN k_li_d[89]
  DIRECTION OUTPUT ;
  USE SIGNAL ;
  PORT
   LAYER M5 ;
   RECT 22.500000 0.000000 22.548000 0.084000 ;
  END
 END k_li_d[89]
 PIN k_li_d[90]
  DIRECTION OUTPUT ;
  USE SIGNAL ;
  PORT
   LAYER M5 ;
   RECT 22.692000 0.000000 22.740000 0.084000 ;
  END
 END k_li_d[90]
 PIN k_li_d[91]
  DIRECTION OUTPUT ;
  USE SIGNAL ;
  PORT
   LAYER M5 ;
   RECT 22.884000 0.000000 22.932000 0.084000 ;
  END
 END k_li_d[91]
 PIN k_li_d[92]
  DIRECTION OUTPUT ;
  USE SIGNAL ;
  PORT
   LAYER M5 ;
   RECT 23.076000 0.000000 23.124000 0.084000 ;
  END
 END k_li_d[92]
 PIN k_li_d[93]
  DIRECTION OUTPUT ;
  USE SIGNAL ;
  PORT
   LAYER M5 ;
   RECT 23.220000 0.000000 23.268000 0.084000 ;
  END
 END k_li_d[93]
 PIN k_li_d[94]
  DIRECTION OUTPUT ;
  USE SIGNAL ;
  PORT
   LAYER M5 ;
   RECT 23.412000 0.000000 23.460000 0.084000 ;
  END
 END k_li_d[94]
 PIN k_li_d[95]
  DIRECTION OUTPUT ;
  USE SIGNAL ;
  PORT
   LAYER M5 ;
   RECT 23.460000 0.000000 23.508000 0.084000 ;
  END
 END k_li_d[95]
 PIN k_li_d[96]
  DIRECTION OUTPUT ;
  USE SIGNAL ;
  PORT
   LAYER M5 ;
   RECT 24.036000 0.000000 24.084000 0.084000 ;
  END
 END k_li_d[96]
 PIN k_li_d[97]
  DIRECTION OUTPUT ;
  USE SIGNAL ;
  PORT
   LAYER M5 ;
   RECT 24.084000 0.000000 24.132000 0.084000 ;
  END
 END k_li_d[97]
 PIN k_li_d[98]
  DIRECTION OUTPUT ;
  USE SIGNAL ;
  PORT
   LAYER M5 ;
   RECT 24.132000 0.000000 24.180000 0.084000 ;
  END
 END k_li_d[98]
 PIN k_li_d[99]
  DIRECTION OUTPUT ;
  USE SIGNAL ;
  PORT
   LAYER M5 ;
   RECT 24.324000 0.000000 24.372000 0.084000 ;
  END
 END k_li_d[99]
 PIN k_li_d[100]
  DIRECTION OUTPUT ;
  USE SIGNAL ;
  PORT
   LAYER M5 ;
   RECT 24.516000 0.000000 24.564000 0.084000 ;
  END
 END k_li_d[100]
 PIN k_li_d[101]
  DIRECTION OUTPUT ;
  USE SIGNAL ;
  PORT
   LAYER M5 ;
   RECT 24.660000 0.000000 24.708000 0.084000 ;
  END
 END k_li_d[101]
 PIN k_li_d[102]
  DIRECTION OUTPUT ;
  USE SIGNAL ;
  PORT
   LAYER M5 ;
   RECT 24.852000 0.000000 24.900000 0.084000 ;
  END
 END k_li_d[102]
 PIN k_li_d[103]
  DIRECTION OUTPUT ;
  USE SIGNAL ;
  PORT
   LAYER M5 ;
   RECT 25.044000 0.000000 25.092000 0.084000 ;
  END
 END k_li_d[103]
 PIN k_li_d[104]
  DIRECTION OUTPUT ;
  USE SIGNAL ;
  PORT
   LAYER M5 ;
   RECT 25.236000 0.000000 25.284000 0.084000 ;
  END
 END k_li_d[104]
 PIN k_li_d[105]
  DIRECTION OUTPUT ;
  USE SIGNAL ;
  PORT
   LAYER M5 ;
   RECT 25.380000 0.000000 25.428000 0.084000 ;
  END
 END k_li_d[105]
 PIN k_li_d[106]
  DIRECTION OUTPUT ;
  USE SIGNAL ;
  PORT
   LAYER M5 ;
   RECT 25.572000 0.000000 25.620000 0.084000 ;
  END
 END k_li_d[106]
 PIN k_li_d[107]
  DIRECTION OUTPUT ;
  USE SIGNAL ;
  PORT
   LAYER M5 ;
   RECT 25.764000 0.000000 25.812000 0.084000 ;
  END
 END k_li_d[107]
 PIN k_li_d[108]
  DIRECTION OUTPUT ;
  USE SIGNAL ;
  PORT
   LAYER M5 ;
   RECT 25.908000 0.000000 25.956000 0.084000 ;
  END
 END k_li_d[108]
 PIN k_li_d[109]
  DIRECTION OUTPUT ;
  USE SIGNAL ;
  PORT
   LAYER M5 ;
   RECT 26.100000 0.000000 26.148000 0.084000 ;
  END
 END k_li_d[109]
 PIN k_li_d[110]
  DIRECTION OUTPUT ;
  USE SIGNAL ;
  PORT
   LAYER M5 ;
   RECT 26.292000 0.000000 26.340000 0.084000 ;
  END
 END k_li_d[110]
 PIN k_li_d[111]
  DIRECTION OUTPUT ;
  USE SIGNAL ;
  PORT
   LAYER M5 ;
   RECT 26.484000 0.000000 26.532000 0.084000 ;
  END
 END k_li_d[111]
 PIN k_li_d[112]
  DIRECTION OUTPUT ;
  USE SIGNAL ;
  PORT
   LAYER M5 ;
   RECT 26.628000 0.000000 26.676000 0.084000 ;
  END
 END k_li_d[112]
 PIN k_li_d[113]
  DIRECTION OUTPUT ;
  USE SIGNAL ;
  PORT
   LAYER M5 ;
   RECT 26.820000 0.000000 26.868000 0.084000 ;
  END
 END k_li_d[113]
 PIN k_li_d[114]
  DIRECTION OUTPUT ;
  USE SIGNAL ;
  PORT
   LAYER M5 ;
   RECT 27.012000 0.000000 27.060000 0.084000 ;
  END
 END k_li_d[114]
 PIN k_li_d[115]
  DIRECTION OUTPUT ;
  USE SIGNAL ;
  PORT
   LAYER M5 ;
   RECT 27.204000 0.000000 27.252000 0.084000 ;
  END
 END k_li_d[115]
 PIN k_li_d[116]
  DIRECTION OUTPUT ;
  USE SIGNAL ;
  PORT
   LAYER M5 ;
   RECT 27.348000 0.000000 27.396000 0.084000 ;
  END
 END k_li_d[116]
 PIN k_li_d[117]
  DIRECTION OUTPUT ;
  USE SIGNAL ;
  PORT
   LAYER M5 ;
   RECT 27.540000 0.000000 27.588000 0.084000 ;
  END
 END k_li_d[117]
 PIN k_li_d[118]
  DIRECTION OUTPUT ;
  USE SIGNAL ;
  PORT
   LAYER M5 ;
   RECT 27.732000 0.000000 27.780000 0.084000 ;
  END
 END k_li_d[118]
 PIN k_li_d[119]
  DIRECTION OUTPUT ;
  USE SIGNAL ;
  PORT
   LAYER M5 ;
   RECT 27.780000 0.000000 27.828000 0.084000 ;
  END
 END k_li_d[119]
 PIN k_li_d[120]
  DIRECTION OUTPUT ;
  USE SIGNAL ;
  PORT
   LAYER M5 ;
   RECT 28.356000 0.000000 28.404000 0.084000 ;
  END
 END k_li_d[120]
 PIN k_li_d[121]
  DIRECTION OUTPUT ;
  USE SIGNAL ;
  PORT
   LAYER M5 ;
   RECT 28.404000 0.000000 28.452000 0.084000 ;
  END
 END k_li_d[121]
 PIN k_li_d[122]
  DIRECTION OUTPUT ;
  USE SIGNAL ;
  PORT
   LAYER M5 ;
   RECT 28.452000 0.000000 28.500000 0.084000 ;
  END
 END k_li_d[122]
 PIN k_li_d[123]
  DIRECTION OUTPUT ;
  USE SIGNAL ;
  PORT
   LAYER M5 ;
   RECT 28.596000 0.000000 28.644000 0.084000 ;
  END
 END k_li_d[123]
 PIN k_li_d[124]
  DIRECTION OUTPUT ;
  USE SIGNAL ;
  PORT
   LAYER M5 ;
   RECT 28.788000 0.000000 28.836000 0.084000 ;
  END
 END k_li_d[124]
 PIN k_li_d[125]
  DIRECTION OUTPUT ;
  USE SIGNAL ;
  PORT
   LAYER M5 ;
   RECT 28.980000 0.000000 29.028000 0.084000 ;
  END
 END k_li_d[125]
 PIN k_li_d[126]
  DIRECTION OUTPUT ;
  USE SIGNAL ;
  PORT
   LAYER M5 ;
   RECT 29.172000 0.000000 29.220000 0.084000 ;
  END
 END k_li_d[126]
 PIN k_li_d[127]
  DIRECTION OUTPUT ;
  USE SIGNAL ;
  PORT
   LAYER M5 ;
   RECT 29.316000 0.000000 29.364000 0.084000 ;
  END
 END k_li_d[127]
 PIN k_li_d[128]
  DIRECTION OUTPUT ;
  USE SIGNAL ;
  PORT
   LAYER M5 ;
   RECT 29.508000 0.000000 29.556000 0.084000 ;
  END
 END k_li_d[128]
 PIN k_li_d[129]
  DIRECTION OUTPUT ;
  USE SIGNAL ;
  PORT
   LAYER M5 ;
   RECT 29.700000 0.000000 29.748000 0.084000 ;
  END
 END k_li_d[129]
 PIN k_li_d[130]
  DIRECTION OUTPUT ;
  USE SIGNAL ;
  PORT
   LAYER M5 ;
   RECT 29.892000 0.000000 29.940000 0.084000 ;
  END
 END k_li_d[130]
 PIN k_li_d[131]
  DIRECTION OUTPUT ;
  USE SIGNAL ;
  PORT
   LAYER M5 ;
   RECT 30.036000 0.000000 30.084000 0.084000 ;
  END
 END k_li_d[131]
 PIN k_li_d[132]
  DIRECTION OUTPUT ;
  USE SIGNAL ;
  PORT
   LAYER M5 ;
   RECT 30.228000 0.000000 30.276000 0.084000 ;
  END
 END k_li_d[132]
 PIN k_li_d[133]
  DIRECTION OUTPUT ;
  USE SIGNAL ;
  PORT
   LAYER M5 ;
   RECT 30.420000 0.000000 30.468000 0.084000 ;
  END
 END k_li_d[133]
 PIN k_li_d[134]
  DIRECTION OUTPUT ;
  USE SIGNAL ;
  PORT
   LAYER M5 ;
   RECT 30.612000 0.000000 30.660000 0.084000 ;
  END
 END k_li_d[134]
 PIN k_li_d[135]
  DIRECTION OUTPUT ;
  USE SIGNAL ;
  PORT
   LAYER M5 ;
   RECT 30.756000 0.000000 30.804000 0.084000 ;
  END
 END k_li_d[135]
 PIN k_li_d[136]
  DIRECTION OUTPUT ;
  USE SIGNAL ;
  PORT
   LAYER M5 ;
   RECT 30.948000 0.000000 30.996000 0.084000 ;
  END
 END k_li_d[136]
 PIN k_li_d[137]
  DIRECTION OUTPUT ;
  USE SIGNAL ;
  PORT
   LAYER M5 ;
   RECT 31.140000 0.000000 31.188000 0.084000 ;
  END
 END k_li_d[137]
 PIN k_li_d[138]
  DIRECTION OUTPUT ;
  USE SIGNAL ;
  PORT
   LAYER M5 ;
   RECT 31.284000 0.000000 31.332000 0.084000 ;
  END
 END k_li_d[138]
 PIN k_li_d[139]
  DIRECTION OUTPUT ;
  USE SIGNAL ;
  PORT
   LAYER M5 ;
   RECT 31.476000 0.000000 31.524000 0.084000 ;
  END
 END k_li_d[139]
 PIN k_li_d[140]
  DIRECTION OUTPUT ;
  USE SIGNAL ;
  PORT
   LAYER M5 ;
   RECT 31.668000 0.000000 31.716000 0.084000 ;
  END
 END k_li_d[140]
 PIN k_li_d[141]
  DIRECTION OUTPUT ;
  USE SIGNAL ;
  PORT
   LAYER M5 ;
   RECT 31.860000 0.000000 31.908000 0.084000 ;
  END
 END k_li_d[141]
 PIN k_li_d[142]
  DIRECTION OUTPUT ;
  USE SIGNAL ;
  PORT
   LAYER M5 ;
   RECT 32.004000 0.000000 32.052000 0.084000 ;
  END
 END k_li_d[142]
 PIN k_li_d[143]
  DIRECTION OUTPUT ;
  USE SIGNAL ;
  PORT
   LAYER M5 ;
   RECT 32.100000 0.000000 32.148000 0.084000 ;
  END
 END k_li_d[143]
 PIN k_li_d[144]
  DIRECTION OUTPUT ;
  USE SIGNAL ;
  PORT
   LAYER M5 ;
   RECT 32.676000 0.000000 32.724000 0.084000 ;
  END
 END k_li_d[144]
 PIN k_li_d[145]
  DIRECTION OUTPUT ;
  USE SIGNAL ;
  PORT
   LAYER M5 ;
   RECT 32.724000 0.000000 32.772000 0.084000 ;
  END
 END k_li_d[145]
 PIN k_li_d[146]
  DIRECTION OUTPUT ;
  USE SIGNAL ;
  PORT
   LAYER M5 ;
   RECT 32.772000 0.000000 32.820000 0.084000 ;
  END
 END k_li_d[146]
 PIN k_li_d[147]
  DIRECTION OUTPUT ;
  USE SIGNAL ;
  PORT
   LAYER M5 ;
   RECT 32.916000 0.000000 32.964000 0.084000 ;
  END
 END k_li_d[147]
 PIN k_li_d[148]
  DIRECTION OUTPUT ;
  USE SIGNAL ;
  PORT
   LAYER M5 ;
   RECT 33.108000 0.000000 33.156000 0.084000 ;
  END
 END k_li_d[148]
 PIN k_li_d[149]
  DIRECTION OUTPUT ;
  USE SIGNAL ;
  PORT
   LAYER M5 ;
   RECT 33.300000 0.000000 33.348000 0.084000 ;
  END
 END k_li_d[149]
 PIN k_li_d[150]
  DIRECTION OUTPUT ;
  USE SIGNAL ;
  PORT
   LAYER M5 ;
   RECT 33.444000 0.000000 33.492000 0.084000 ;
  END
 END k_li_d[150]
 PIN k_li_d[151]
  DIRECTION OUTPUT ;
  USE SIGNAL ;
  PORT
   LAYER M5 ;
   RECT 33.636000 0.000000 33.684000 0.084000 ;
  END
 END k_li_d[151]
 PIN k_li_d[152]
  DIRECTION OUTPUT ;
  USE SIGNAL ;
  PORT
   LAYER M5 ;
   RECT 33.828000 0.000000 33.876000 0.084000 ;
  END
 END k_li_d[152]
 PIN k_li_d[153]
  DIRECTION OUTPUT ;
  USE SIGNAL ;
  PORT
   LAYER M5 ;
   RECT 34.020000 0.000000 34.068000 0.084000 ;
  END
 END k_li_d[153]
 PIN k_li_d[154]
  DIRECTION OUTPUT ;
  USE SIGNAL ;
  PORT
   LAYER M5 ;
   RECT 34.164000 0.000000 34.212000 0.084000 ;
  END
 END k_li_d[154]
 PIN k_li_d[155]
  DIRECTION OUTPUT ;
  USE SIGNAL ;
  PORT
   LAYER M5 ;
   RECT 34.356000 0.000000 34.404000 0.084000 ;
  END
 END k_li_d[155]
 PIN k_li_d[156]
  DIRECTION OUTPUT ;
  USE SIGNAL ;
  PORT
   LAYER M5 ;
   RECT 34.548000 0.000000 34.596000 0.084000 ;
  END
 END k_li_d[156]
 PIN k_li_d[157]
  DIRECTION OUTPUT ;
  USE SIGNAL ;
  PORT
   LAYER M5 ;
   RECT 34.692000 0.000000 34.740000 0.084000 ;
  END
 END k_li_d[157]
 PIN k_li_d[158]
  DIRECTION OUTPUT ;
  USE SIGNAL ;
  PORT
   LAYER M5 ;
   RECT 34.884000 0.000000 34.932000 0.084000 ;
  END
 END k_li_d[158]
 PIN k_li_d[159]
  DIRECTION OUTPUT ;
  USE SIGNAL ;
  PORT
   LAYER M5 ;
   RECT 35.076000 0.000000 35.124000 0.084000 ;
  END
 END k_li_d[159]
 PIN k_li_d[160]
  DIRECTION OUTPUT ;
  USE SIGNAL ;
  PORT
   LAYER M5 ;
   RECT 35.268000 0.000000 35.316000 0.084000 ;
  END
 END k_li_d[160]
 PIN k_li_d[161]
  DIRECTION OUTPUT ;
  USE SIGNAL ;
  PORT
   LAYER M5 ;
   RECT 35.412000 0.000000 35.460000 0.084000 ;
  END
 END k_li_d[161]
 PIN k_li_d[162]
  DIRECTION OUTPUT ;
  USE SIGNAL ;
  PORT
   LAYER M5 ;
   RECT 35.604000 0.000000 35.652000 0.084000 ;
  END
 END k_li_d[162]
 PIN k_li_d[163]
  DIRECTION OUTPUT ;
  USE SIGNAL ;
  PORT
   LAYER M5 ;
   RECT 35.796000 0.000000 35.844000 0.084000 ;
  END
 END k_li_d[163]
 PIN k_li_d[164]
  DIRECTION OUTPUT ;
  USE SIGNAL ;
  PORT
   LAYER M5 ;
   RECT 35.988000 0.000000 36.036000 0.084000 ;
  END
 END k_li_d[164]
 PIN k_li_d[165]
  DIRECTION OUTPUT ;
  USE SIGNAL ;
  PORT
   LAYER M5 ;
   RECT 36.132000 0.000000 36.180000 0.084000 ;
  END
 END k_li_d[165]
 PIN k_li_d[166]
  DIRECTION OUTPUT ;
  USE SIGNAL ;
  PORT
   LAYER M5 ;
   RECT 36.324000 0.000000 36.372000 0.084000 ;
  END
 END k_li_d[166]
 PIN k_li_d[167]
  DIRECTION OUTPUT ;
  USE SIGNAL ;
  PORT
   LAYER M5 ;
   RECT 36.420000 0.000000 36.468000 0.084000 ;
  END
 END k_li_d[167]
 PIN k_li_d[168]
  DIRECTION OUTPUT ;
  USE SIGNAL ;
  PORT
   LAYER M5 ;
   RECT 36.996000 0.000000 37.044000 0.084000 ;
  END
 END k_li_d[168]
 PIN k_li_d[169]
  DIRECTION OUTPUT ;
  USE SIGNAL ;
  PORT
   LAYER M5 ;
   RECT 37.044000 0.000000 37.092000 0.084000 ;
  END
 END k_li_d[169]
 PIN k_li_d[170]
  DIRECTION OUTPUT ;
  USE SIGNAL ;
  PORT
   LAYER M5 ;
   RECT 37.092000 0.000000 37.140000 0.084000 ;
  END
 END k_li_d[170]
 PIN k_li_d[171]
  DIRECTION OUTPUT ;
  USE SIGNAL ;
  PORT
   LAYER M5 ;
   RECT 37.236000 0.000000 37.284000 0.084000 ;
  END
 END k_li_d[171]
 PIN k_li_d[172]
  DIRECTION OUTPUT ;
  USE SIGNAL ;
  PORT
   LAYER M5 ;
   RECT 37.380000 0.000000 37.428000 0.084000 ;
  END
 END k_li_d[172]
 PIN k_li_d[173]
  DIRECTION OUTPUT ;
  USE SIGNAL ;
  PORT
   LAYER M5 ;
   RECT 37.572000 0.000000 37.620000 0.084000 ;
  END
 END k_li_d[173]
 PIN k_li_d[174]
  DIRECTION OUTPUT ;
  USE SIGNAL ;
  PORT
   LAYER M5 ;
   RECT 37.764000 0.000000 37.812000 0.084000 ;
  END
 END k_li_d[174]
 PIN k_li_d[175]
  DIRECTION OUTPUT ;
  USE SIGNAL ;
  PORT
   LAYER M5 ;
   RECT 37.956000 0.000000 38.004000 0.084000 ;
  END
 END k_li_d[175]
 PIN k_li_d[176]
  DIRECTION OUTPUT ;
  USE SIGNAL ;
  PORT
   LAYER M5 ;
   RECT 38.100000 0.000000 38.148000 0.084000 ;
  END
 END k_li_d[176]
 PIN k_li_d[177]
  DIRECTION OUTPUT ;
  USE SIGNAL ;
  PORT
   LAYER M5 ;
   RECT 38.292000 0.000000 38.340000 0.084000 ;
  END
 END k_li_d[177]
 PIN k_li_d[178]
  DIRECTION OUTPUT ;
  USE SIGNAL ;
  PORT
   LAYER M5 ;
   RECT 38.484000 0.000000 38.532000 0.084000 ;
  END
 END k_li_d[178]
 PIN k_li_d[179]
  DIRECTION OUTPUT ;
  USE SIGNAL ;
  PORT
   LAYER M5 ;
   RECT 38.676000 0.000000 38.724000 0.084000 ;
  END
 END k_li_d[179]
 PIN k_li_d[180]
  DIRECTION OUTPUT ;
  USE SIGNAL ;
  PORT
   LAYER M5 ;
   RECT 38.820000 0.000000 38.868000 0.084000 ;
  END
 END k_li_d[180]
 PIN k_li_d[181]
  DIRECTION OUTPUT ;
  USE SIGNAL ;
  PORT
   LAYER M5 ;
   RECT 39.012000 0.000000 39.060000 0.084000 ;
  END
 END k_li_d[181]
 PIN k_li_d[182]
  DIRECTION OUTPUT ;
  USE SIGNAL ;
  PORT
   LAYER M5 ;
   RECT 39.204000 0.000000 39.252000 0.084000 ;
  END
 END k_li_d[182]
 PIN k_li_d[183]
  DIRECTION OUTPUT ;
  USE SIGNAL ;
  PORT
   LAYER M5 ;
   RECT 39.396000 0.000000 39.444000 0.084000 ;
  END
 END k_li_d[183]
 PIN k_li_d[184]
  DIRECTION OUTPUT ;
  USE SIGNAL ;
  PORT
   LAYER M5 ;
   RECT 39.540000 0.000000 39.588000 0.084000 ;
  END
 END k_li_d[184]
 PIN k_li_d[185]
  DIRECTION OUTPUT ;
  USE SIGNAL ;
  PORT
   LAYER M5 ;
   RECT 39.732000 0.000000 39.780000 0.084000 ;
  END
 END k_li_d[185]
 PIN k_li_d[186]
  DIRECTION OUTPUT ;
  USE SIGNAL ;
  PORT
   LAYER M5 ;
   RECT 39.924000 0.000000 39.972000 0.084000 ;
  END
 END k_li_d[186]
 PIN k_li_d[187]
  DIRECTION OUTPUT ;
  USE SIGNAL ;
  PORT
   LAYER M5 ;
   RECT 40.068000 0.000000 40.116000 0.084000 ;
  END
 END k_li_d[187]
 PIN k_li_d[188]
  DIRECTION OUTPUT ;
  USE SIGNAL ;
  PORT
   LAYER M5 ;
   RECT 40.260000 0.000000 40.308000 0.084000 ;
  END
 END k_li_d[188]
 PIN k_li_d[189]
  DIRECTION OUTPUT ;
  USE SIGNAL ;
  PORT
   LAYER M5 ;
   RECT 40.452000 0.000000 40.500000 0.084000 ;
  END
 END k_li_d[189]
 PIN k_li_d[190]
  DIRECTION OUTPUT ;
  USE SIGNAL ;
  PORT
   LAYER M5 ;
   RECT 40.644000 0.000000 40.692000 0.084000 ;
  END
 END k_li_d[190]
 PIN k_li_d[191]
  DIRECTION OUTPUT ;
  USE SIGNAL ;
  PORT
   LAYER M5 ;
   RECT 40.740000 0.000000 40.788000 0.084000 ;
  END
 END k_li_d[191]
 PIN k_li_d[192]
  DIRECTION OUTPUT ;
  USE SIGNAL ;
  PORT
   LAYER M5 ;
   RECT 41.316000 0.000000 41.364000 0.084000 ;
  END
 END k_li_d[192]
 PIN k_li_d[193]
  DIRECTION OUTPUT ;
  USE SIGNAL ;
  PORT
   LAYER M5 ;
   RECT 41.364000 0.000000 41.412000 0.084000 ;
  END
 END k_li_d[193]
 PIN k_li_d[194]
  DIRECTION OUTPUT ;
  USE SIGNAL ;
  PORT
   LAYER M5 ;
   RECT 41.412000 0.000000 41.460000 0.084000 ;
  END
 END k_li_d[194]
 PIN k_li_d[195]
  DIRECTION OUTPUT ;
  USE SIGNAL ;
  PORT
   LAYER M5 ;
   RECT 41.508000 0.000000 41.556000 0.084000 ;
  END
 END k_li_d[195]
 PIN k_li_d[196]
  DIRECTION OUTPUT ;
  USE SIGNAL ;
  PORT
   LAYER M5 ;
   RECT 41.700000 0.000000 41.748000 0.084000 ;
  END
 END k_li_d[196]
 PIN k_li_d[197]
  DIRECTION OUTPUT ;
  USE SIGNAL ;
  PORT
   LAYER M5 ;
   RECT 41.892000 0.000000 41.940000 0.084000 ;
  END
 END k_li_d[197]
 PIN k_li_d[198]
  DIRECTION OUTPUT ;
  USE SIGNAL ;
  PORT
   LAYER M5 ;
   RECT 42.084000 0.000000 42.132000 0.084000 ;
  END
 END k_li_d[198]
 PIN k_li_d[199]
  DIRECTION OUTPUT ;
  USE SIGNAL ;
  PORT
   LAYER M5 ;
   RECT 42.228000 0.000000 42.276000 0.084000 ;
  END
 END k_li_d[199]
 PIN k_li_d[200]
  DIRECTION OUTPUT ;
  USE SIGNAL ;
  PORT
   LAYER M5 ;
   RECT 42.420000 0.000000 42.468000 0.084000 ;
  END
 END k_li_d[200]
 PIN k_li_d[201]
  DIRECTION OUTPUT ;
  USE SIGNAL ;
  PORT
   LAYER M5 ;
   RECT 42.612000 0.000000 42.660000 0.084000 ;
  END
 END k_li_d[201]
 PIN k_li_d[202]
  DIRECTION OUTPUT ;
  USE SIGNAL ;
  PORT
   LAYER M5 ;
   RECT 42.804000 0.000000 42.852000 0.084000 ;
  END
 END k_li_d[202]
 PIN k_li_d[203]
  DIRECTION OUTPUT ;
  USE SIGNAL ;
  PORT
   LAYER M5 ;
   RECT 42.948000 0.000000 42.996000 0.084000 ;
  END
 END k_li_d[203]
 PIN k_li_d[204]
  DIRECTION OUTPUT ;
  USE SIGNAL ;
  PORT
   LAYER M5 ;
   RECT 43.140000 0.000000 43.188000 0.084000 ;
  END
 END k_li_d[204]
 PIN k_li_d[205]
  DIRECTION OUTPUT ;
  USE SIGNAL ;
  PORT
   LAYER M5 ;
   RECT 43.332000 0.000000 43.380000 0.084000 ;
  END
 END k_li_d[205]
 PIN k_li_d[206]
  DIRECTION OUTPUT ;
  USE SIGNAL ;
  PORT
   LAYER M5 ;
   RECT 43.476000 0.000000 43.524000 0.084000 ;
  END
 END k_li_d[206]
 PIN k_li_d[207]
  DIRECTION OUTPUT ;
  USE SIGNAL ;
  PORT
   LAYER M5 ;
   RECT 43.668000 0.000000 43.716000 0.084000 ;
  END
 END k_li_d[207]
 PIN k_li_d[208]
  DIRECTION OUTPUT ;
  USE SIGNAL ;
  PORT
   LAYER M5 ;
   RECT 43.860000 0.000000 43.908000 0.084000 ;
  END
 END k_li_d[208]
 PIN k_li_d[209]
  DIRECTION OUTPUT ;
  USE SIGNAL ;
  PORT
   LAYER M5 ;
   RECT 44.052000 0.000000 44.100000 0.084000 ;
  END
 END k_li_d[209]
 PIN k_li_d[210]
  DIRECTION OUTPUT ;
  USE SIGNAL ;
  PORT
   LAYER M5 ;
   RECT 44.196000 0.000000 44.244000 0.084000 ;
  END
 END k_li_d[210]
 PIN k_li_d[211]
  DIRECTION OUTPUT ;
  USE SIGNAL ;
  PORT
   LAYER M5 ;
   RECT 44.388000 0.000000 44.436000 0.084000 ;
  END
 END k_li_d[211]
 PIN k_li_d[212]
  DIRECTION OUTPUT ;
  USE SIGNAL ;
  PORT
   LAYER M5 ;
   RECT 44.580000 0.000000 44.628000 0.084000 ;
  END
 END k_li_d[212]
 PIN k_li_d[213]
  DIRECTION OUTPUT ;
  USE SIGNAL ;
  PORT
   LAYER M5 ;
   RECT 44.772000 0.000000 44.820000 0.084000 ;
  END
 END k_li_d[213]
 PIN k_li_d[214]
  DIRECTION OUTPUT ;
  USE SIGNAL ;
  PORT
   LAYER M5 ;
   RECT 44.916000 0.000000 44.964000 0.084000 ;
  END
 END k_li_d[214]
 PIN k_li_d[215]
  DIRECTION OUTPUT ;
  USE SIGNAL ;
  PORT
   LAYER M5 ;
   RECT 45.060000 0.000000 45.108000 0.084000 ;
  END
 END k_li_d[215]
 PIN k_li_d[216]
  DIRECTION OUTPUT ;
  USE SIGNAL ;
  PORT
   LAYER M5 ;
   RECT 45.636000 0.000000 45.684000 0.084000 ;
  END
 END k_li_d[216]
 PIN k_li_d[217]
  DIRECTION OUTPUT ;
  USE SIGNAL ;
  PORT
   LAYER M5 ;
   RECT 45.684000 0.000000 45.732000 0.084000 ;
  END
 END k_li_d[217]
 PIN k_li_d[218]
  DIRECTION OUTPUT ;
  USE SIGNAL ;
  PORT
   LAYER M5 ;
   RECT 45.732000 0.000000 45.780000 0.084000 ;
  END
 END k_li_d[218]
 PIN k_li_d[219]
  DIRECTION OUTPUT ;
  USE SIGNAL ;
  PORT
   LAYER M5 ;
   RECT 45.828000 0.000000 45.876000 0.084000 ;
  END
 END k_li_d[219]
 PIN k_li_d[220]
  DIRECTION OUTPUT ;
  USE SIGNAL ;
  PORT
   LAYER M5 ;
   RECT 46.020000 0.000000 46.068000 0.084000 ;
  END
 END k_li_d[220]
 PIN k_li_d[221]
  DIRECTION OUTPUT ;
  USE SIGNAL ;
  PORT
   LAYER M5 ;
   RECT 46.164000 0.000000 46.212000 0.084000 ;
  END
 END k_li_d[221]
 PIN k_li_d[222]
  DIRECTION OUTPUT ;
  USE SIGNAL ;
  PORT
   LAYER M5 ;
   RECT 46.356000 0.000000 46.404000 0.084000 ;
  END
 END k_li_d[222]
 PIN k_li_d[223]
  DIRECTION OUTPUT ;
  USE SIGNAL ;
  PORT
   LAYER M5 ;
   RECT 46.548000 0.000000 46.596000 0.084000 ;
  END
 END k_li_d[223]
 PIN k_li_d[224]
  DIRECTION OUTPUT ;
  USE SIGNAL ;
  PORT
   LAYER M5 ;
   RECT 46.740000 0.000000 46.788000 0.084000 ;
  END
 END k_li_d[224]
 PIN k_li_d[225]
  DIRECTION OUTPUT ;
  USE SIGNAL ;
  PORT
   LAYER M5 ;
   RECT 46.884000 0.000000 46.932000 0.084000 ;
  END
 END k_li_d[225]
 PIN k_li_d[226]
  DIRECTION OUTPUT ;
  USE SIGNAL ;
  PORT
   LAYER M5 ;
   RECT 47.076000 0.000000 47.124000 0.084000 ;
  END
 END k_li_d[226]
 PIN k_li_d[227]
  DIRECTION OUTPUT ;
  USE SIGNAL ;
  PORT
   LAYER M5 ;
   RECT 47.268000 0.000000 47.316000 0.084000 ;
  END
 END k_li_d[227]
 PIN k_li_d[228]
  DIRECTION OUTPUT ;
  USE SIGNAL ;
  PORT
   LAYER M5 ;
   RECT 47.460000 0.000000 47.508000 0.084000 ;
  END
 END k_li_d[228]
 PIN k_li_d[229]
  DIRECTION OUTPUT ;
  USE SIGNAL ;
  PORT
   LAYER M5 ;
   RECT 47.604000 0.000000 47.652000 0.084000 ;
  END
 END k_li_d[229]
 PIN k_li_d[230]
  DIRECTION OUTPUT ;
  USE SIGNAL ;
  PORT
   LAYER M5 ;
   RECT 47.796000 0.000000 47.844000 0.084000 ;
  END
 END k_li_d[230]
 PIN k_li_d[231]
  DIRECTION OUTPUT ;
  USE SIGNAL ;
  PORT
   LAYER M5 ;
   RECT 47.988000 0.000000 48.036000 0.084000 ;
  END
 END k_li_d[231]
 PIN k_li_d[232]
  DIRECTION OUTPUT ;
  USE SIGNAL ;
  PORT
   LAYER M5 ;
   RECT 48.180000 0.000000 48.228000 0.084000 ;
  END
 END k_li_d[232]
 PIN k_li_d[233]
  DIRECTION OUTPUT ;
  USE SIGNAL ;
  PORT
   LAYER M5 ;
   RECT 48.324000 0.000000 48.372000 0.084000 ;
  END
 END k_li_d[233]
 PIN k_li_d[234]
  DIRECTION OUTPUT ;
  USE SIGNAL ;
  PORT
   LAYER M5 ;
   RECT 48.516000 0.000000 48.564000 0.084000 ;
  END
 END k_li_d[234]
 PIN k_li_d[235]
  DIRECTION OUTPUT ;
  USE SIGNAL ;
  PORT
   LAYER M5 ;
   RECT 48.708000 0.000000 48.756000 0.084000 ;
  END
 END k_li_d[235]
 PIN k_li_d[236]
  DIRECTION OUTPUT ;
  USE SIGNAL ;
  PORT
   LAYER M5 ;
   RECT 48.852000 0.000000 48.900000 0.084000 ;
  END
 END k_li_d[236]
 PIN k_li_d[237]
  DIRECTION OUTPUT ;
  USE SIGNAL ;
  PORT
   LAYER M5 ;
   RECT 49.044000 0.000000 49.092000 0.084000 ;
  END
 END k_li_d[237]
 PIN k_li_d[238]
  DIRECTION OUTPUT ;
  USE SIGNAL ;
  PORT
   LAYER M5 ;
   RECT 49.236000 0.000000 49.284000 0.084000 ;
  END
 END k_li_d[238]
 PIN k_li_d[239]
  DIRECTION OUTPUT ;
  USE SIGNAL ;
  PORT
   LAYER M5 ;
   RECT 49.380000 0.000000 49.428000 0.084000 ;
  END
 END k_li_d[239]
 PIN k_li_d[240]
  DIRECTION OUTPUT ;
  USE SIGNAL ;
  PORT
   LAYER M5 ;
   RECT 49.956000 0.000000 50.004000 0.084000 ;
  END
 END k_li_d[240]
 PIN k_li_d[241]
  DIRECTION OUTPUT ;
  USE SIGNAL ;
  PORT
   LAYER M5 ;
   RECT 50.004000 0.000000 50.052000 0.084000 ;
  END
 END k_li_d[241]
 PIN k_li_d[242]
  DIRECTION OUTPUT ;
  USE SIGNAL ;
  PORT
   LAYER M5 ;
   RECT 50.052000 0.000000 50.100000 0.084000 ;
  END
 END k_li_d[242]
 PIN k_li_d[243]
  DIRECTION OUTPUT ;
  USE SIGNAL ;
  PORT
   LAYER M5 ;
   RECT 50.148000 0.000000 50.196000 0.084000 ;
  END
 END k_li_d[243]
 PIN k_li_d[244]
  DIRECTION OUTPUT ;
  USE SIGNAL ;
  PORT
   LAYER M5 ;
   RECT 50.292000 0.000000 50.340000 0.084000 ;
  END
 END k_li_d[244]
 PIN k_li_d[245]
  DIRECTION OUTPUT ;
  USE SIGNAL ;
  PORT
   LAYER M5 ;
   RECT 50.484000 0.000000 50.532000 0.084000 ;
  END
 END k_li_d[245]
 PIN k_li_d[246]
  DIRECTION OUTPUT ;
  USE SIGNAL ;
  PORT
   LAYER M5 ;
   RECT 50.676000 0.000000 50.724000 0.084000 ;
  END
 END k_li_d[246]
 PIN k_li_d[247]
  DIRECTION OUTPUT ;
  USE SIGNAL ;
  PORT
   LAYER M5 ;
   RECT 50.868000 0.000000 50.916000 0.084000 ;
  END
 END k_li_d[247]
 PIN k_li_d[248]
  DIRECTION OUTPUT ;
  USE SIGNAL ;
  PORT
   LAYER M5 ;
   RECT 51.012000 0.000000 51.060000 0.084000 ;
  END
 END k_li_d[248]
 PIN k_li_d[249]
  DIRECTION OUTPUT ;
  USE SIGNAL ;
  PORT
   LAYER M5 ;
   RECT 51.204000 0.000000 51.252000 0.084000 ;
  END
 END k_li_d[249]
 PIN k_li_d[250]
  DIRECTION OUTPUT ;
  USE SIGNAL ;
  PORT
   LAYER M5 ;
   RECT 51.396000 0.000000 51.444000 0.084000 ;
  END
 END k_li_d[250]
 PIN k_li_d[251]
  DIRECTION OUTPUT ;
  USE SIGNAL ;
  PORT
   LAYER M5 ;
   RECT 51.588000 0.000000 51.636000 0.084000 ;
  END
 END k_li_d[251]
 PIN k_li_d[252]
  DIRECTION OUTPUT ;
  USE SIGNAL ;
  PORT
   LAYER M5 ;
   RECT 51.732000 0.000000 51.780000 0.084000 ;
  END
 END k_li_d[252]
 PIN k_li_d[253]
  DIRECTION OUTPUT ;
  USE SIGNAL ;
  PORT
   LAYER M5 ;
   RECT 51.924000 0.000000 51.972000 0.084000 ;
  END
 END k_li_d[253]
 PIN k_li_d[254]
  DIRECTION OUTPUT ;
  USE SIGNAL ;
  PORT
   LAYER M5 ;
   RECT 52.116000 0.000000 52.164000 0.084000 ;
  END
 END k_li_d[254]
 PIN k_li_d[255]
  DIRECTION OUTPUT ;
  USE SIGNAL ;
  PORT
   LAYER M5 ;
   RECT 52.260000 0.000000 52.308000 0.084000 ;
  END
 END k_li_d[255]
 PIN k_li_d[256]
  DIRECTION OUTPUT ;
  USE SIGNAL ;
  PORT
   LAYER M5 ;
   RECT 52.452000 0.000000 52.500000 0.084000 ;
  END
 END k_li_d[256]
 PIN k_li_d[257]
  DIRECTION OUTPUT ;
  USE SIGNAL ;
  PORT
   LAYER M5 ;
   RECT 52.644000 0.000000 52.692000 0.084000 ;
  END
 END k_li_d[257]
 PIN k_li_d[258]
  DIRECTION OUTPUT ;
  USE SIGNAL ;
  PORT
   LAYER M5 ;
   RECT 52.836000 0.000000 52.884000 0.084000 ;
  END
 END k_li_d[258]
 PIN k_li_d[259]
  DIRECTION OUTPUT ;
  USE SIGNAL ;
  PORT
   LAYER M5 ;
   RECT 52.980000 0.000000 53.028000 0.084000 ;
  END
 END k_li_d[259]
 PIN k_li_d[260]
  DIRECTION OUTPUT ;
  USE SIGNAL ;
  PORT
   LAYER M5 ;
   RECT 53.172000 0.000000 53.220000 0.084000 ;
  END
 END k_li_d[260]
 PIN k_li_d[261]
  DIRECTION OUTPUT ;
  USE SIGNAL ;
  PORT
   LAYER M5 ;
   RECT 53.364000 0.000000 53.412000 0.084000 ;
  END
 END k_li_d[261]
 PIN k_li_d[262]
  DIRECTION OUTPUT ;
  USE SIGNAL ;
  PORT
   LAYER M5 ;
   RECT 53.556000 0.000000 53.604000 0.084000 ;
  END
 END k_li_d[262]
 PIN k_li_d[263]
  DIRECTION OUTPUT ;
  USE SIGNAL ;
  PORT
   LAYER M5 ;
   RECT 53.700000 0.000000 53.748000 0.084000 ;
  END
 END k_li_d[263]
 PIN k_li_d[264]
  DIRECTION OUTPUT ;
  USE SIGNAL ;
  PORT
   LAYER M5 ;
   RECT 54.276000 0.000000 54.324000 0.084000 ;
  END
 END k_li_d[264]
 PIN k_li_d[265]
  DIRECTION OUTPUT ;
  USE SIGNAL ;
  PORT
   LAYER M5 ;
   RECT 54.324000 0.000000 54.372000 0.084000 ;
  END
 END k_li_d[265]
 PIN k_li_d[266]
  DIRECTION OUTPUT ;
  USE SIGNAL ;
  PORT
   LAYER M5 ;
   RECT 54.372000 0.000000 54.420000 0.084000 ;
  END
 END k_li_d[266]
 PIN k_li_d[267]
  DIRECTION OUTPUT ;
  USE SIGNAL ;
  PORT
   LAYER M5 ;
   RECT 54.420000 0.000000 54.468000 0.084000 ;
  END
 END k_li_d[267]
 PIN k_li_d[268]
  DIRECTION OUTPUT ;
  USE SIGNAL ;
  PORT
   LAYER M5 ;
   RECT 54.612000 0.000000 54.660000 0.084000 ;
  END
 END k_li_d[268]
 PIN k_li_d[269]
  DIRECTION OUTPUT ;
  USE SIGNAL ;
  PORT
   LAYER M5 ;
   RECT 54.804000 0.000000 54.852000 0.084000 ;
  END
 END k_li_d[269]
 PIN k_li_d[270]
  DIRECTION OUTPUT ;
  USE SIGNAL ;
  PORT
   LAYER M5 ;
   RECT 54.948000 0.000000 54.996000 0.084000 ;
  END
 END k_li_d[270]
 PIN k_li_d[271]
  DIRECTION OUTPUT ;
  USE SIGNAL ;
  PORT
   LAYER M5 ;
   RECT 55.140000 0.000000 55.188000 0.084000 ;
  END
 END k_li_d[271]
 PIN k_li_d[272]
  DIRECTION OUTPUT ;
  USE SIGNAL ;
  PORT
   LAYER M5 ;
   RECT 55.332000 0.000000 55.380000 0.084000 ;
  END
 END k_li_d[272]
 PIN k_li_d[273]
  DIRECTION OUTPUT ;
  USE SIGNAL ;
  PORT
   LAYER M5 ;
   RECT 55.524000 0.000000 55.572000 0.084000 ;
  END
 END k_li_d[273]
 PIN k_li_d[274]
  DIRECTION OUTPUT ;
  USE SIGNAL ;
  PORT
   LAYER M5 ;
   RECT 55.668000 0.000000 55.716000 0.084000 ;
  END
 END k_li_d[274]
 PIN k_li_d[275]
  DIRECTION OUTPUT ;
  USE SIGNAL ;
  PORT
   LAYER M5 ;
   RECT 55.860000 0.000000 55.908000 0.084000 ;
  END
 END k_li_d[275]
 PIN k_li_d[276]
  DIRECTION OUTPUT ;
  USE SIGNAL ;
  PORT
   LAYER M5 ;
   RECT 56.052000 0.000000 56.100000 0.084000 ;
  END
 END k_li_d[276]
 PIN k_li_d[277]
  DIRECTION OUTPUT ;
  USE SIGNAL ;
  PORT
   LAYER M5 ;
   RECT 56.244000 0.000000 56.292000 0.084000 ;
  END
 END k_li_d[277]
 PIN k_li_d[278]
  DIRECTION OUTPUT ;
  USE SIGNAL ;
  PORT
   LAYER M5 ;
   RECT 56.388000 0.000000 56.436000 0.084000 ;
  END
 END k_li_d[278]
 PIN k_li_d[279]
  DIRECTION OUTPUT ;
  USE SIGNAL ;
  PORT
   LAYER M5 ;
   RECT 56.580000 0.000000 56.628000 0.084000 ;
  END
 END k_li_d[279]
 PIN k_li_d[280]
  DIRECTION OUTPUT ;
  USE SIGNAL ;
  PORT
   LAYER M5 ;
   RECT 56.772000 0.000000 56.820000 0.084000 ;
  END
 END k_li_d[280]
 PIN k_li_d[281]
  DIRECTION OUTPUT ;
  USE SIGNAL ;
  PORT
   LAYER M5 ;
   RECT 56.964000 0.000000 57.012000 0.084000 ;
  END
 END k_li_d[281]
 PIN k_li_d[282]
  DIRECTION OUTPUT ;
  USE SIGNAL ;
  PORT
   LAYER M5 ;
   RECT 57.108000 0.000000 57.156000 0.084000 ;
  END
 END k_li_d[282]
 PIN k_li_d[283]
  DIRECTION OUTPUT ;
  USE SIGNAL ;
  PORT
   LAYER M5 ;
   RECT 57.300000 0.000000 57.348000 0.084000 ;
  END
 END k_li_d[283]
 PIN k_li_d[284]
  DIRECTION OUTPUT ;
  USE SIGNAL ;
  PORT
   LAYER M5 ;
   RECT 57.492000 0.000000 57.540000 0.084000 ;
  END
 END k_li_d[284]
 PIN k_li_d[285]
  DIRECTION OUTPUT ;
  USE SIGNAL ;
  PORT
   LAYER M5 ;
   RECT 57.636000 0.000000 57.684000 0.084000 ;
  END
 END k_li_d[285]
 PIN k_li_d[286]
  DIRECTION OUTPUT ;
  USE SIGNAL ;
  PORT
   LAYER M5 ;
   RECT 57.828000 0.000000 57.876000 0.084000 ;
  END
 END k_li_d[286]
 PIN k_li_d[287]
  DIRECTION OUTPUT ;
  USE SIGNAL ;
  PORT
   LAYER M5 ;
   RECT 57.924000 0.000000 57.972000 0.084000 ;
  END
 END k_li_d[287]
 PIN k_li_d[288]
  DIRECTION OUTPUT ;
  USE SIGNAL ;
  PORT
   LAYER M5 ;
   RECT 57.972000 0.000000 58.020000 0.084000 ;
  END
 END k_li_d[288]
 PIN k_li_d[289]
  DIRECTION OUTPUT ;
  USE SIGNAL ;
  PORT
   LAYER M5 ;
   RECT 58.020000 0.000000 58.068000 0.084000 ;
  END
 END k_li_d[289]
 PIN k_li_d[290]
  DIRECTION OUTPUT ;
  USE SIGNAL ;
  PORT
   LAYER M5 ;
   RECT 58.596000 0.000000 58.644000 0.084000 ;
  END
 END k_li_d[290]
 PIN k_li_d[291]
  DIRECTION OUTPUT ;
  USE SIGNAL ;
  PORT
   LAYER M5 ;
   RECT 58.740000 0.000000 58.788000 0.084000 ;
  END
 END k_li_d[291]
 PIN k_li_d[292]
  DIRECTION OUTPUT ;
  USE SIGNAL ;
  PORT
   LAYER M5 ;
   RECT 58.932000 0.000000 58.980000 0.084000 ;
  END
 END k_li_d[292]
 PIN k_li_d[293]
  DIRECTION OUTPUT ;
  USE SIGNAL ;
  PORT
   LAYER M5 ;
   RECT 59.076000 0.000000 59.124000 0.084000 ;
  END
 END k_li_d[293]
 PIN k_li_d[294]
  DIRECTION OUTPUT ;
  USE SIGNAL ;
  PORT
   LAYER M5 ;
   RECT 59.268000 0.000000 59.316000 0.084000 ;
  END
 END k_li_d[294]
 PIN k_li_d[295]
  DIRECTION OUTPUT ;
  USE SIGNAL ;
  PORT
   LAYER M5 ;
   RECT 59.460000 0.000000 59.508000 0.084000 ;
  END
 END k_li_d[295]
 PIN k_li_d[296]
  DIRECTION OUTPUT ;
  USE SIGNAL ;
  PORT
   LAYER M5 ;
   RECT 59.652000 0.000000 59.700000 0.084000 ;
  END
 END k_li_d[296]
 PIN k_li_d[297]
  DIRECTION OUTPUT ;
  USE SIGNAL ;
  PORT
   LAYER M5 ;
   RECT 59.796000 0.000000 59.844000 0.084000 ;
  END
 END k_li_d[297]
 PIN k_li_d[298]
  DIRECTION OUTPUT ;
  USE SIGNAL ;
  PORT
   LAYER M5 ;
   RECT 59.988000 0.000000 60.036000 0.084000 ;
  END
 END k_li_d[298]
 PIN k_li_d[299]
  DIRECTION OUTPUT ;
  USE SIGNAL ;
  PORT
   LAYER M5 ;
   RECT 60.180000 0.000000 60.228000 0.084000 ;
  END
 END k_li_d[299]
 PIN k_li_d[300]
  DIRECTION OUTPUT ;
  USE SIGNAL ;
  PORT
   LAYER M5 ;
   RECT 60.372000 0.000000 60.420000 0.084000 ;
  END
 END k_li_d[300]
 PIN k_li_d[301]
  DIRECTION OUTPUT ;
  USE SIGNAL ;
  PORT
   LAYER M5 ;
   RECT 60.516000 0.000000 60.564000 0.084000 ;
  END
 END k_li_d[301]
 PIN k_li_d[302]
  DIRECTION OUTPUT ;
  USE SIGNAL ;
  PORT
   LAYER M5 ;
   RECT 60.708000 0.000000 60.756000 0.084000 ;
  END
 END k_li_d[302]
 PIN k_li_d[303]
  DIRECTION OUTPUT ;
  USE SIGNAL ;
  PORT
   LAYER M5 ;
   RECT 60.900000 0.000000 60.948000 0.084000 ;
  END
 END k_li_d[303]
 PIN k_li_d[304]
  DIRECTION OUTPUT ;
  USE SIGNAL ;
  PORT
   LAYER M5 ;
   RECT 61.044000 0.000000 61.092000 0.084000 ;
  END
 END k_li_d[304]
 PIN k_li_d[305]
  DIRECTION OUTPUT ;
  USE SIGNAL ;
  PORT
   LAYER M5 ;
   RECT 61.236000 0.000000 61.284000 0.084000 ;
  END
 END k_li_d[305]
 PIN k_li_d[306]
  DIRECTION OUTPUT ;
  USE SIGNAL ;
  PORT
   LAYER M5 ;
   RECT 61.428000 0.000000 61.476000 0.084000 ;
  END
 END k_li_d[306]
 PIN k_li_d[307]
  DIRECTION OUTPUT ;
  USE SIGNAL ;
  PORT
   LAYER M5 ;
   RECT 61.620000 0.000000 61.668000 0.084000 ;
  END
 END k_li_d[307]
 PIN k_li_d[308]
  DIRECTION OUTPUT ;
  USE SIGNAL ;
  PORT
   LAYER M5 ;
   RECT 61.764000 0.000000 61.812000 0.084000 ;
  END
 END k_li_d[308]
 PIN k_li_d[309]
  DIRECTION OUTPUT ;
  USE SIGNAL ;
  PORT
   LAYER M5 ;
   RECT 61.956000 0.000000 62.004000 0.084000 ;
  END
 END k_li_d[309]
 PIN k_li_d[310]
  DIRECTION OUTPUT ;
  USE SIGNAL ;
  PORT
   LAYER M5 ;
   RECT 62.148000 0.000000 62.196000 0.084000 ;
  END
 END k_li_d[310]
 PIN k_li_d[311]
  DIRECTION OUTPUT ;
  USE SIGNAL ;
  PORT
   LAYER M5 ;
   RECT 62.244000 0.000000 62.292000 0.084000 ;
  END
 END k_li_d[311]
 PIN k_li_d[312]
  DIRECTION OUTPUT ;
  USE SIGNAL ;
  PORT
   LAYER M5 ;
   RECT 62.292000 0.000000 62.340000 0.084000 ;
  END
 END k_li_d[312]
 PIN k_li_d[313]
  DIRECTION OUTPUT ;
  USE SIGNAL ;
  PORT
   LAYER M5 ;
   RECT 62.340000 0.000000 62.388000 0.084000 ;
  END
 END k_li_d[313]
 PIN k_li_d[314]
  DIRECTION OUTPUT ;
  USE SIGNAL ;
  PORT
   LAYER M5 ;
   RECT 62.916000 0.000000 62.964000 0.084000 ;
  END
 END k_li_d[314]
 PIN k_li_d[315]
  DIRECTION OUTPUT ;
  USE SIGNAL ;
  PORT
   LAYER M5 ;
   RECT 63.060000 0.000000 63.108000 0.084000 ;
  END
 END k_li_d[315]
 PIN k_li_d[316]
  DIRECTION OUTPUT ;
  USE SIGNAL ;
  PORT
   LAYER M5 ;
   RECT 63.204000 0.000000 63.252000 0.084000 ;
  END
 END k_li_d[316]
 PIN k_li_d[317]
  DIRECTION OUTPUT ;
  USE SIGNAL ;
  PORT
   LAYER M5 ;
   RECT 63.396000 0.000000 63.444000 0.084000 ;
  END
 END k_li_d[317]
 PIN k_li_d[318]
  DIRECTION OUTPUT ;
  USE SIGNAL ;
  PORT
   LAYER M5 ;
   RECT 63.588000 0.000000 63.636000 0.084000 ;
  END
 END k_li_d[318]
 PIN k_li_d[319]
  DIRECTION OUTPUT ;
  USE SIGNAL ;
  PORT
   LAYER M5 ;
   RECT 63.732000 0.000000 63.780000 0.084000 ;
  END
 END k_li_d[319]
 PIN k_li_d[320]
  DIRECTION OUTPUT ;
  USE SIGNAL ;
  PORT
   LAYER M5 ;
   RECT 63.924000 0.000000 63.972000 0.084000 ;
  END
 END k_li_d[320]
 PIN k_li_d[321]
  DIRECTION OUTPUT ;
  USE SIGNAL ;
  PORT
   LAYER M5 ;
   RECT 64.116000 0.000000 64.164000 0.084000 ;
  END
 END k_li_d[321]
 PIN k_li_d[322]
  DIRECTION OUTPUT ;
  USE SIGNAL ;
  PORT
   LAYER M5 ;
   RECT 64.308000 0.000000 64.356000 0.084000 ;
  END
 END k_li_d[322]
 PIN k_li_d[323]
  DIRECTION OUTPUT ;
  USE SIGNAL ;
  PORT
   LAYER M5 ;
   RECT 64.452000 0.000000 64.500000 0.084000 ;
  END
 END k_li_d[323]
 PIN k_li_d[324]
  DIRECTION OUTPUT ;
  USE SIGNAL ;
  PORT
   LAYER M5 ;
   RECT 64.644000 0.000000 64.692000 0.084000 ;
  END
 END k_li_d[324]
 PIN k_li_d[325]
  DIRECTION OUTPUT ;
  USE SIGNAL ;
  PORT
   LAYER M5 ;
   RECT 64.836000 0.000000 64.884000 0.084000 ;
  END
 END k_li_d[325]
 PIN k_li_d[326]
  DIRECTION OUTPUT ;
  USE SIGNAL ;
  PORT
   LAYER M5 ;
   RECT 65.028000 0.000000 65.076000 0.084000 ;
  END
 END k_li_d[326]
 PIN k_li_d[327]
  DIRECTION OUTPUT ;
  USE SIGNAL ;
  PORT
   LAYER M5 ;
   RECT 65.172000 0.000000 65.220000 0.084000 ;
  END
 END k_li_d[327]
 PIN k_li_d[328]
  DIRECTION OUTPUT ;
  USE SIGNAL ;
  PORT
   LAYER M5 ;
   RECT 65.364000 0.000000 65.412000 0.084000 ;
  END
 END k_li_d[328]
 PIN k_li_d[329]
  DIRECTION OUTPUT ;
  USE SIGNAL ;
  PORT
   LAYER M5 ;
   RECT 65.556000 0.000000 65.604000 0.084000 ;
  END
 END k_li_d[329]
 PIN k_li_d[330]
  DIRECTION OUTPUT ;
  USE SIGNAL ;
  PORT
   LAYER M5 ;
   RECT 65.748000 0.000000 65.796000 0.084000 ;
  END
 END k_li_d[330]
 PIN k_li_d[331]
  DIRECTION OUTPUT ;
  USE SIGNAL ;
  PORT
   LAYER M5 ;
   RECT 65.892000 0.000000 65.940000 0.084000 ;
  END
 END k_li_d[331]
 PIN k_li_d[332]
  DIRECTION OUTPUT ;
  USE SIGNAL ;
  PORT
   LAYER M5 ;
   RECT 66.084000 0.000000 66.132000 0.084000 ;
  END
 END k_li_d[332]
 PIN k_li_d[333]
  DIRECTION OUTPUT ;
  USE SIGNAL ;
  PORT
   LAYER M5 ;
   RECT 66.276000 0.000000 66.324000 0.084000 ;
  END
 END k_li_d[333]
 PIN k_li_d[334]
  DIRECTION OUTPUT ;
  USE SIGNAL ;
  PORT
   LAYER M5 ;
   RECT 66.420000 0.000000 66.468000 0.084000 ;
  END
 END k_li_d[334]
 PIN k_li_d[335]
  DIRECTION OUTPUT ;
  USE SIGNAL ;
  PORT
   LAYER M5 ;
   RECT 66.564000 0.000000 66.612000 0.084000 ;
  END
 END k_li_d[335]
 PIN k_li_d[336]
  DIRECTION OUTPUT ;
  USE SIGNAL ;
  PORT
   LAYER M5 ;
   RECT 66.612000 0.000000 66.660000 0.084000 ;
  END
 END k_li_d[336]
 PIN k_li_d[337]
  DIRECTION OUTPUT ;
  USE SIGNAL ;
  PORT
   LAYER M5 ;
   RECT 66.660000 0.000000 66.708000 0.084000 ;
  END
 END k_li_d[337]
 PIN k_li_d[338]
  DIRECTION OUTPUT ;
  USE SIGNAL ;
  PORT
   LAYER M5 ;
   RECT 67.236000 0.000000 67.284000 0.084000 ;
  END
 END k_li_d[338]
 PIN k_li_d[339]
  DIRECTION OUTPUT ;
  USE SIGNAL ;
  PORT
   LAYER M5 ;
   RECT 67.332000 0.000000 67.380000 0.084000 ;
  END
 END k_li_d[339]
 PIN k_li_d[340]
  DIRECTION OUTPUT ;
  USE SIGNAL ;
  PORT
   LAYER M5 ;
   RECT 67.524000 0.000000 67.572000 0.084000 ;
  END
 END k_li_d[340]
 PIN k_li_d[341]
  DIRECTION OUTPUT ;
  USE SIGNAL ;
  PORT
   LAYER M5 ;
   RECT 67.716000 0.000000 67.764000 0.084000 ;
  END
 END k_li_d[341]
 PIN k_li_d[342]
  DIRECTION OUTPUT ;
  USE SIGNAL ;
  PORT
   LAYER M5 ;
   RECT 67.860000 0.000000 67.908000 0.084000 ;
  END
 END k_li_d[342]
 PIN k_li_d[343]
  DIRECTION OUTPUT ;
  USE SIGNAL ;
  PORT
   LAYER M5 ;
   RECT 68.052000 0.000000 68.100000 0.084000 ;
  END
 END k_li_d[343]
 PIN k_li_d[344]
  DIRECTION OUTPUT ;
  USE SIGNAL ;
  PORT
   LAYER M5 ;
   RECT 68.244000 0.000000 68.292000 0.084000 ;
  END
 END k_li_d[344]
 PIN k_li_d[345]
  DIRECTION OUTPUT ;
  USE SIGNAL ;
  PORT
   LAYER M5 ;
   RECT 68.436000 0.000000 68.484000 0.084000 ;
  END
 END k_li_d[345]
 PIN k_li_d[346]
  DIRECTION OUTPUT ;
  USE SIGNAL ;
  PORT
   LAYER M5 ;
   RECT 68.580000 0.000000 68.628000 0.084000 ;
  END
 END k_li_d[346]
 PIN k_li_d[347]
  DIRECTION OUTPUT ;
  USE SIGNAL ;
  PORT
   LAYER M5 ;
   RECT 68.772000 0.000000 68.820000 0.084000 ;
  END
 END k_li_d[347]
 PIN k_li_d[348]
  DIRECTION OUTPUT ;
  USE SIGNAL ;
  PORT
   LAYER M5 ;
   RECT 68.964000 0.000000 69.012000 0.084000 ;
  END
 END k_li_d[348]
 PIN k_li_d[349]
  DIRECTION OUTPUT ;
  USE SIGNAL ;
  PORT
   LAYER M5 ;
   RECT 69.156000 0.000000 69.204000 0.084000 ;
  END
 END k_li_d[349]
 PIN k_li_d[350]
  DIRECTION OUTPUT ;
  USE SIGNAL ;
  PORT
   LAYER M5 ;
   RECT 69.300000 0.000000 69.348000 0.084000 ;
  END
 END k_li_d[350]
 PIN k_li_d[351]
  DIRECTION OUTPUT ;
  USE SIGNAL ;
  PORT
   LAYER M5 ;
   RECT 69.492000 0.000000 69.540000 0.084000 ;
  END
 END k_li_d[351]
 PIN k_li_d[352]
  DIRECTION OUTPUT ;
  USE SIGNAL ;
  PORT
   LAYER M5 ;
   RECT 69.684000 0.000000 69.732000 0.084000 ;
  END
 END k_li_d[352]
 PIN k_li_d[353]
  DIRECTION OUTPUT ;
  USE SIGNAL ;
  PORT
   LAYER M5 ;
   RECT 69.828000 0.000000 69.876000 0.084000 ;
  END
 END k_li_d[353]
 PIN k_li_d[354]
  DIRECTION OUTPUT ;
  USE SIGNAL ;
  PORT
   LAYER M5 ;
   RECT 70.020000 0.000000 70.068000 0.084000 ;
  END
 END k_li_d[354]
 PIN k_li_d[355]
  DIRECTION OUTPUT ;
  USE SIGNAL ;
  PORT
   LAYER M5 ;
   RECT 70.212000 0.000000 70.260000 0.084000 ;
  END
 END k_li_d[355]
 PIN k_li_d[356]
  DIRECTION OUTPUT ;
  USE SIGNAL ;
  PORT
   LAYER M5 ;
   RECT 70.404000 0.000000 70.452000 0.084000 ;
  END
 END k_li_d[356]
 PIN k_li_d[357]
  DIRECTION OUTPUT ;
  USE SIGNAL ;
  PORT
   LAYER M5 ;
   RECT 70.548000 0.000000 70.596000 0.084000 ;
  END
 END k_li_d[357]
 PIN k_li_d[358]
  DIRECTION OUTPUT ;
  USE SIGNAL ;
  PORT
   LAYER M5 ;
   RECT 70.740000 0.000000 70.788000 0.084000 ;
  END
 END k_li_d[358]
 PIN k_li_d[359]
  DIRECTION OUTPUT ;
  USE SIGNAL ;
  PORT
   LAYER M5 ;
   RECT 70.884000 0.000000 70.932000 0.084000 ;
  END
 END k_li_d[359]
 PIN k_li_d[360]
  DIRECTION OUTPUT ;
  USE SIGNAL ;
  PORT
   LAYER M5 ;
   RECT 70.932000 0.000000 70.980000 0.084000 ;
  END
 END k_li_d[360]
 PIN k_li_d[361]
  DIRECTION OUTPUT ;
  USE SIGNAL ;
  PORT
   LAYER M5 ;
   RECT 70.980000 0.000000 71.028000 0.084000 ;
  END
 END k_li_d[361]
 PIN k_li_d[362]
  DIRECTION OUTPUT ;
  USE SIGNAL ;
  PORT
   LAYER M5 ;
   RECT 71.556000 0.000000 71.604000 0.084000 ;
  END
 END k_li_d[362]
 PIN k_li_d[363]
  DIRECTION OUTPUT ;
  USE SIGNAL ;
  PORT
   LAYER M5 ;
   RECT 71.652000 0.000000 71.700000 0.084000 ;
  END
 END k_li_d[363]
 PIN k_li_d[364]
  DIRECTION OUTPUT ;
  USE SIGNAL ;
  PORT
   LAYER M5 ;
   RECT 71.844000 0.000000 71.892000 0.084000 ;
  END
 END k_li_d[364]
 PIN k_li_d[365]
  DIRECTION OUTPUT ;
  USE SIGNAL ;
  PORT
   LAYER M5 ;
   RECT 71.988000 0.000000 72.036000 0.084000 ;
  END
 END k_li_d[365]
 PIN k_li_d[366]
  DIRECTION OUTPUT ;
  USE SIGNAL ;
  PORT
   LAYER M5 ;
   RECT 72.180000 0.000000 72.228000 0.084000 ;
  END
 END k_li_d[366]
 PIN k_li_d[367]
  DIRECTION OUTPUT ;
  USE SIGNAL ;
  PORT
   LAYER M5 ;
   RECT 72.372000 0.000000 72.420000 0.084000 ;
  END
 END k_li_d[367]
 PIN k_li_d[368]
  DIRECTION OUTPUT ;
  USE SIGNAL ;
  PORT
   LAYER M5 ;
   RECT 72.516000 0.000000 72.564000 0.084000 ;
  END
 END k_li_d[368]
 PIN k_li_d[369]
  DIRECTION OUTPUT ;
  USE SIGNAL ;
  PORT
   LAYER M5 ;
   RECT 72.708000 0.000000 72.756000 0.084000 ;
  END
 END k_li_d[369]
 PIN k_li_d[370]
  DIRECTION OUTPUT ;
  USE SIGNAL ;
  PORT
   LAYER M5 ;
   RECT 72.900000 0.000000 72.948000 0.084000 ;
  END
 END k_li_d[370]
 PIN k_li_d[371]
  DIRECTION OUTPUT ;
  USE SIGNAL ;
  PORT
   LAYER M5 ;
   RECT 73.092000 0.000000 73.140000 0.084000 ;
  END
 END k_li_d[371]
 PIN k_li_d[372]
  DIRECTION OUTPUT ;
  USE SIGNAL ;
  PORT
   LAYER M5 ;
   RECT 73.236000 0.000000 73.284000 0.084000 ;
  END
 END k_li_d[372]
 PIN k_li_d[373]
  DIRECTION OUTPUT ;
  USE SIGNAL ;
  PORT
   LAYER M5 ;
   RECT 73.428000 0.000000 73.476000 0.084000 ;
  END
 END k_li_d[373]
 PIN k_li_d[374]
  DIRECTION OUTPUT ;
  USE SIGNAL ;
  PORT
   LAYER M5 ;
   RECT 73.620000 0.000000 73.668000 0.084000 ;
  END
 END k_li_d[374]
 PIN k_li_d[375]
  DIRECTION OUTPUT ;
  USE SIGNAL ;
  PORT
   LAYER M5 ;
   RECT 73.812000 0.000000 73.860000 0.084000 ;
  END
 END k_li_d[375]
 PIN k_li_d[376]
  DIRECTION OUTPUT ;
  USE SIGNAL ;
  PORT
   LAYER M5 ;
   RECT 73.956000 0.000000 74.004000 0.084000 ;
  END
 END k_li_d[376]
 PIN k_li_d[377]
  DIRECTION OUTPUT ;
  USE SIGNAL ;
  PORT
   LAYER M5 ;
   RECT 74.148000 0.000000 74.196000 0.084000 ;
  END
 END k_li_d[377]
 PIN k_li_d[378]
  DIRECTION OUTPUT ;
  USE SIGNAL ;
  PORT
   LAYER M5 ;
   RECT 74.340000 0.000000 74.388000 0.084000 ;
  END
 END k_li_d[378]
 PIN k_li_d[379]
  DIRECTION OUTPUT ;
  USE SIGNAL ;
  PORT
   LAYER M5 ;
   RECT 74.532000 0.000000 74.580000 0.084000 ;
  END
 END k_li_d[379]
 PIN k_li_d[380]
  DIRECTION OUTPUT ;
  USE SIGNAL ;
  PORT
   LAYER M5 ;
   RECT 74.676000 0.000000 74.724000 0.084000 ;
  END
 END k_li_d[380]
 PIN k_li_d[381]
  DIRECTION OUTPUT ;
  USE SIGNAL ;
  PORT
   LAYER M5 ;
   RECT 74.868000 0.000000 74.916000 0.084000 ;
  END
 END k_li_d[381]
 PIN k_li_d[382]
  DIRECTION OUTPUT ;
  USE SIGNAL ;
  PORT
   LAYER M5 ;
   RECT 75.060000 0.000000 75.108000 0.084000 ;
  END
 END k_li_d[382]
 PIN k_li_d[383]
  DIRECTION OUTPUT ;
  USE SIGNAL ;
  PORT
   LAYER M5 ;
   RECT 75.204000 0.000000 75.252000 0.084000 ;
  END
 END k_li_d[383]
 PIN k_li_d[384]
  DIRECTION OUTPUT ;
  USE SIGNAL ;
  PORT
   LAYER M5 ;
   RECT 75.252000 0.000000 75.300000 0.084000 ;
  END
 END k_li_d[384]
 PIN k_li_d[385]
  DIRECTION OUTPUT ;
  USE SIGNAL ;
  PORT
   LAYER M5 ;
   RECT 75.300000 0.000000 75.348000 0.084000 ;
  END
 END k_li_d[385]
 PIN k_li_d[386]
  DIRECTION OUTPUT ;
  USE SIGNAL ;
  PORT
   LAYER M5 ;
   RECT 75.876000 0.000000 75.924000 0.084000 ;
  END
 END k_li_d[386]
 PIN k_li_d[387]
  DIRECTION OUTPUT ;
  USE SIGNAL ;
  PORT
   LAYER M5 ;
   RECT 75.924000 0.000000 75.972000 0.084000 ;
  END
 END k_li_d[387]
 PIN k_li_d[388]
  DIRECTION OUTPUT ;
  USE SIGNAL ;
  PORT
   LAYER M5 ;
   RECT 76.116000 0.000000 76.164000 0.084000 ;
  END
 END k_li_d[388]
 PIN k_li_d[389]
  DIRECTION OUTPUT ;
  USE SIGNAL ;
  PORT
   LAYER M5 ;
   RECT 76.308000 0.000000 76.356000 0.084000 ;
  END
 END k_li_d[389]
 PIN k_li_d[390]
  DIRECTION OUTPUT ;
  USE SIGNAL ;
  PORT
   LAYER M5 ;
   RECT 76.500000 0.000000 76.548000 0.084000 ;
  END
 END k_li_d[390]
 PIN k_li_d[391]
  DIRECTION OUTPUT ;
  USE SIGNAL ;
  PORT
   LAYER M5 ;
   RECT 76.644000 0.000000 76.692000 0.084000 ;
  END
 END k_li_d[391]
 PIN k_li_d[392]
  DIRECTION OUTPUT ;
  USE SIGNAL ;
  PORT
   LAYER M5 ;
   RECT 76.836000 0.000000 76.884000 0.084000 ;
  END
 END k_li_d[392]
 PIN k_li_d[393]
  DIRECTION OUTPUT ;
  USE SIGNAL ;
  PORT
   LAYER M5 ;
   RECT 77.028000 0.000000 77.076000 0.084000 ;
  END
 END k_li_d[393]
 PIN k_li_d[394]
  DIRECTION OUTPUT ;
  USE SIGNAL ;
  PORT
   LAYER M5 ;
   RECT 77.220000 0.000000 77.268000 0.084000 ;
  END
 END k_li_d[394]
 PIN k_li_d[395]
  DIRECTION OUTPUT ;
  USE SIGNAL ;
  PORT
   LAYER M5 ;
   RECT 77.364000 0.000000 77.412000 0.084000 ;
  END
 END k_li_d[395]
 PIN k_li_d[396]
  DIRECTION OUTPUT ;
  USE SIGNAL ;
  PORT
   LAYER M5 ;
   RECT 77.556000 0.000000 77.604000 0.084000 ;
  END
 END k_li_d[396]
 PIN k_li_d[397]
  DIRECTION OUTPUT ;
  USE SIGNAL ;
  PORT
   LAYER M5 ;
   RECT 77.748000 0.000000 77.796000 0.084000 ;
  END
 END k_li_d[397]
 PIN k_li_d[398]
  DIRECTION OUTPUT ;
  USE SIGNAL ;
  PORT
   LAYER M5 ;
   RECT 77.940000 0.000000 77.988000 0.084000 ;
  END
 END k_li_d[398]
 PIN k_li_d[399]
  DIRECTION OUTPUT ;
  USE SIGNAL ;
  PORT
   LAYER M5 ;
   RECT 78.084000 0.000000 78.132000 0.084000 ;
  END
 END k_li_d[399]
 PIN k_li_d[400]
  DIRECTION OUTPUT ;
  USE SIGNAL ;
  PORT
   LAYER M5 ;
   RECT 78.276000 0.000000 78.324000 0.084000 ;
  END
 END k_li_d[400]
 PIN k_li_d[401]
  DIRECTION OUTPUT ;
  USE SIGNAL ;
  PORT
   LAYER M5 ;
   RECT 78.468000 0.000000 78.516000 0.084000 ;
  END
 END k_li_d[401]
 PIN k_li_d[402]
  DIRECTION OUTPUT ;
  USE SIGNAL ;
  PORT
   LAYER M5 ;
   RECT 78.612000 0.000000 78.660000 0.084000 ;
  END
 END k_li_d[402]
 PIN k_li_d[403]
  DIRECTION OUTPUT ;
  USE SIGNAL ;
  PORT
   LAYER M5 ;
   RECT 78.804000 0.000000 78.852000 0.084000 ;
  END
 END k_li_d[403]
 PIN k_li_d[404]
  DIRECTION OUTPUT ;
  USE SIGNAL ;
  PORT
   LAYER M5 ;
   RECT 78.996000 0.000000 79.044000 0.084000 ;
  END
 END k_li_d[404]
 PIN k_li_d[405]
  DIRECTION OUTPUT ;
  USE SIGNAL ;
  PORT
   LAYER M5 ;
   RECT 79.188000 0.000000 79.236000 0.084000 ;
  END
 END k_li_d[405]
 PIN k_li_d[406]
  DIRECTION OUTPUT ;
  USE SIGNAL ;
  PORT
   LAYER M5 ;
   RECT 79.332000 0.000000 79.380000 0.084000 ;
  END
 END k_li_d[406]
 PIN k_li_d[407]
  DIRECTION OUTPUT ;
  USE SIGNAL ;
  PORT
   LAYER M5 ;
   RECT 79.524000 0.000000 79.572000 0.084000 ;
  END
 END k_li_d[407]
 PIN k_li_d[408]
  DIRECTION OUTPUT ;
  USE SIGNAL ;
  PORT
   LAYER M5 ;
   RECT 79.572000 0.000000 79.620000 0.084000 ;
  END
 END k_li_d[408]
 PIN k_li_d[409]
  DIRECTION OUTPUT ;
  USE SIGNAL ;
  PORT
   LAYER M5 ;
   RECT 79.620000 0.000000 79.668000 0.084000 ;
  END
 END k_li_d[409]
 PIN k_li_d[410]
  DIRECTION OUTPUT ;
  USE SIGNAL ;
  PORT
   LAYER M5 ;
   RECT 80.196000 0.000000 80.244000 0.084000 ;
  END
 END k_li_d[410]
 PIN k_li_d[411]
  DIRECTION OUTPUT ;
  USE SIGNAL ;
  PORT
   LAYER M5 ;
   RECT 80.244000 0.000000 80.292000 0.084000 ;
  END
 END k_li_d[411]
 PIN k_li_d[412]
  DIRECTION OUTPUT ;
  USE SIGNAL ;
  PORT
   LAYER M5 ;
   RECT 80.436000 0.000000 80.484000 0.084000 ;
  END
 END k_li_d[412]
 PIN k_li_d[413]
  DIRECTION OUTPUT ;
  USE SIGNAL ;
  PORT
   LAYER M5 ;
   RECT 80.628000 0.000000 80.676000 0.084000 ;
  END
 END k_li_d[413]
 PIN k_li_d[414]
  DIRECTION OUTPUT ;
  USE SIGNAL ;
  PORT
   LAYER M5 ;
   RECT 80.772000 0.000000 80.820000 0.084000 ;
  END
 END k_li_d[414]
 PIN k_li_d[415]
  DIRECTION OUTPUT ;
  USE SIGNAL ;
  PORT
   LAYER M5 ;
   RECT 80.964000 0.000000 81.012000 0.084000 ;
  END
 END k_li_d[415]
 PIN k_li_d[416]
  DIRECTION OUTPUT ;
  USE SIGNAL ;
  PORT
   LAYER M5 ;
   RECT 81.156000 0.000000 81.204000 0.084000 ;
  END
 END k_li_d[416]
 PIN k_li_d[417]
  DIRECTION OUTPUT ;
  USE SIGNAL ;
  PORT
   LAYER M5 ;
   RECT 81.300000 0.000000 81.348000 0.084000 ;
  END
 END k_li_d[417]
 PIN k_li_d[418]
  DIRECTION OUTPUT ;
  USE SIGNAL ;
  PORT
   LAYER M5 ;
   RECT 81.492000 0.000000 81.540000 0.084000 ;
  END
 END k_li_d[418]
 PIN k_li_d[419]
  DIRECTION OUTPUT ;
  USE SIGNAL ;
  PORT
   LAYER M5 ;
   RECT 81.684000 0.000000 81.732000 0.084000 ;
  END
 END k_li_d[419]
 PIN k_li_d[420]
  DIRECTION OUTPUT ;
  USE SIGNAL ;
  PORT
   LAYER M5 ;
   RECT 81.876000 0.000000 81.924000 0.084000 ;
  END
 END k_li_d[420]
 PIN k_li_d[421]
  DIRECTION OUTPUT ;
  USE SIGNAL ;
  PORT
   LAYER M5 ;
   RECT 82.020000 0.000000 82.068000 0.084000 ;
  END
 END k_li_d[421]
 PIN k_li_d[422]
  DIRECTION OUTPUT ;
  USE SIGNAL ;
  PORT
   LAYER M5 ;
   RECT 82.212000 0.000000 82.260000 0.084000 ;
  END
 END k_li_d[422]
 PIN k_li_d[423]
  DIRECTION OUTPUT ;
  USE SIGNAL ;
  PORT
   LAYER M5 ;
   RECT 82.404000 0.000000 82.452000 0.084000 ;
  END
 END k_li_d[423]
 PIN k_li_d[424]
  DIRECTION OUTPUT ;
  USE SIGNAL ;
  PORT
   LAYER M5 ;
   RECT 82.596000 0.000000 82.644000 0.084000 ;
  END
 END k_li_d[424]
 PIN k_li_d[425]
  DIRECTION OUTPUT ;
  USE SIGNAL ;
  PORT
   LAYER M5 ;
   RECT 82.740000 0.000000 82.788000 0.084000 ;
  END
 END k_li_d[425]
 PIN k_li_d[426]
  DIRECTION OUTPUT ;
  USE SIGNAL ;
  PORT
   LAYER M5 ;
   RECT 82.932000 0.000000 82.980000 0.084000 ;
  END
 END k_li_d[426]
 PIN k_li_d[427]
  DIRECTION OUTPUT ;
  USE SIGNAL ;
  PORT
   LAYER M5 ;
   RECT 83.124000 0.000000 83.172000 0.084000 ;
  END
 END k_li_d[427]
 PIN k_li_d[428]
  DIRECTION OUTPUT ;
  USE SIGNAL ;
  PORT
   LAYER M5 ;
   RECT 83.316000 0.000000 83.364000 0.084000 ;
  END
 END k_li_d[428]
 PIN k_li_d[429]
  DIRECTION OUTPUT ;
  USE SIGNAL ;
  PORT
   LAYER M5 ;
   RECT 83.460000 0.000000 83.508000 0.084000 ;
  END
 END k_li_d[429]
 PIN k_li_d[430]
  DIRECTION OUTPUT ;
  USE SIGNAL ;
  PORT
   LAYER M5 ;
   RECT 83.652000 0.000000 83.700000 0.084000 ;
  END
 END k_li_d[430]
 PIN k_li_d[431]
  DIRECTION OUTPUT ;
  USE SIGNAL ;
  PORT
   LAYER M5 ;
   RECT 83.844000 0.000000 83.892000 0.084000 ;
  END
 END k_li_d[431]
 PIN k_li_d[432]
  DIRECTION OUTPUT ;
  USE SIGNAL ;
  PORT
   LAYER M5 ;
   RECT 83.892000 0.000000 83.940000 0.084000 ;
  END
 END k_li_d[432]
 PIN k_li_d[433]
  DIRECTION OUTPUT ;
  USE SIGNAL ;
  PORT
   LAYER M5 ;
   RECT 83.940000 0.000000 83.988000 0.084000 ;
  END
 END k_li_d[433]
 PIN k_li_d[434]
  DIRECTION OUTPUT ;
  USE SIGNAL ;
  PORT
   LAYER M5 ;
   RECT 84.516000 0.000000 84.564000 0.084000 ;
  END
 END k_li_d[434]
 PIN k_li_d[435]
  DIRECTION OUTPUT ;
  USE SIGNAL ;
  PORT
   LAYER M5 ;
   RECT 84.564000 0.000000 84.612000 0.084000 ;
  END
 END k_li_d[435]
 PIN k_li_d[436]
  DIRECTION OUTPUT ;
  USE SIGNAL ;
  PORT
   LAYER M5 ;
   RECT 84.708000 0.000000 84.756000 0.084000 ;
  END
 END k_li_d[436]
 PIN k_li_d[437]
  DIRECTION OUTPUT ;
  USE SIGNAL ;
  PORT
   LAYER M5 ;
   RECT 84.900000 0.000000 84.948000 0.084000 ;
  END
 END k_li_d[437]
 PIN k_li_d[438]
  DIRECTION OUTPUT ;
  USE SIGNAL ;
  PORT
   LAYER M5 ;
   RECT 85.092000 0.000000 85.140000 0.084000 ;
  END
 END k_li_d[438]
 PIN k_li_d[439]
  DIRECTION OUTPUT ;
  USE SIGNAL ;
  PORT
   LAYER M5 ;
   RECT 85.284000 0.000000 85.332000 0.084000 ;
  END
 END k_li_d[439]
 PIN k_li_d[440]
  DIRECTION OUTPUT ;
  USE SIGNAL ;
  PORT
   LAYER M5 ;
   RECT 85.428000 0.000000 85.476000 0.084000 ;
  END
 END k_li_d[440]
 PIN k_li_d[441]
  DIRECTION OUTPUT ;
  USE SIGNAL ;
  PORT
   LAYER M5 ;
   RECT 85.620000 0.000000 85.668000 0.084000 ;
  END
 END k_li_d[441]
 PIN k_li_d[442]
  DIRECTION OUTPUT ;
  USE SIGNAL ;
  PORT
   LAYER M5 ;
   RECT 85.812000 0.000000 85.860000 0.084000 ;
  END
 END k_li_d[442]
 PIN k_li_d[443]
  DIRECTION OUTPUT ;
  USE SIGNAL ;
  PORT
   LAYER M5 ;
   RECT 86.004000 0.000000 86.052000 0.084000 ;
  END
 END k_li_d[443]
 PIN k_li_d[444]
  DIRECTION OUTPUT ;
  USE SIGNAL ;
  PORT
   LAYER M5 ;
   RECT 86.148000 0.000000 86.196000 0.084000 ;
  END
 END k_li_d[444]
 PIN k_li_d[445]
  DIRECTION OUTPUT ;
  USE SIGNAL ;
  PORT
   LAYER M5 ;
   RECT 86.340000 0.000000 86.388000 0.084000 ;
  END
 END k_li_d[445]
 PIN k_li_d[446]
  DIRECTION OUTPUT ;
  USE SIGNAL ;
  PORT
   LAYER M5 ;
   RECT 86.532000 0.000000 86.580000 0.084000 ;
  END
 END k_li_d[446]
 PIN k_li_d[447]
  DIRECTION OUTPUT ;
  USE SIGNAL ;
  PORT
   LAYER M5 ;
   RECT 86.724000 0.000000 86.772000 0.084000 ;
  END
 END k_li_d[447]
 PIN k_li_d[448]
  DIRECTION OUTPUT ;
  USE SIGNAL ;
  PORT
   LAYER M5 ;
   RECT 86.868000 0.000000 86.916000 0.084000 ;
  END
 END k_li_d[448]
 PIN k_li_d[449]
  DIRECTION OUTPUT ;
  USE SIGNAL ;
  PORT
   LAYER M5 ;
   RECT 87.060000 0.000000 87.108000 0.084000 ;
  END
 END k_li_d[449]
 PIN k_li_d[450]
  DIRECTION OUTPUT ;
  USE SIGNAL ;
  PORT
   LAYER M5 ;
   RECT 87.252000 0.000000 87.300000 0.084000 ;
  END
 END k_li_d[450]
 PIN k_li_d[451]
  DIRECTION OUTPUT ;
  USE SIGNAL ;
  PORT
   LAYER M5 ;
   RECT 87.396000 0.000000 87.444000 0.084000 ;
  END
 END k_li_d[451]
 PIN k_li_d[452]
  DIRECTION OUTPUT ;
  USE SIGNAL ;
  PORT
   LAYER M5 ;
   RECT 87.588000 0.000000 87.636000 0.084000 ;
  END
 END k_li_d[452]
 PIN k_li_d[453]
  DIRECTION OUTPUT ;
  USE SIGNAL ;
  PORT
   LAYER M5 ;
   RECT 87.780000 0.000000 87.828000 0.084000 ;
  END
 END k_li_d[453]
 PIN k_li_d[454]
  DIRECTION OUTPUT ;
  USE SIGNAL ;
  PORT
   LAYER M5 ;
   RECT 87.972000 0.000000 88.020000 0.084000 ;
  END
 END k_li_d[454]
 PIN k_li_d[455]
  DIRECTION OUTPUT ;
  USE SIGNAL ;
  PORT
   LAYER M5 ;
   RECT 88.116000 0.000000 88.164000 0.084000 ;
  END
 END k_li_d[455]
 PIN k_li_d[456]
  DIRECTION OUTPUT ;
  USE SIGNAL ;
  PORT
   LAYER M5 ;
   RECT 88.164000 0.000000 88.212000 0.084000 ;
  END
 END k_li_d[456]
 PIN k_li_d[457]
  DIRECTION OUTPUT ;
  USE SIGNAL ;
  PORT
   LAYER M5 ;
   RECT 88.212000 0.000000 88.260000 0.084000 ;
  END
 END k_li_d[457]
 PIN k_li_d[458]
  DIRECTION OUTPUT ;
  USE SIGNAL ;
  PORT
   LAYER M5 ;
   RECT 88.260000 0.000000 88.308000 0.084000 ;
  END
 END k_li_d[458]
 PIN k_li_d[459]
  DIRECTION OUTPUT ;
  USE SIGNAL ;
  PORT
   LAYER M5 ;
   RECT 88.836000 0.000000 88.884000 0.084000 ;
  END
 END k_li_d[459]
 PIN k_li_d[460]
  DIRECTION OUTPUT ;
  USE SIGNAL ;
  PORT
   LAYER M5 ;
   RECT 89.028000 0.000000 89.076000 0.084000 ;
  END
 END k_li_d[460]
 PIN k_li_d[461]
  DIRECTION OUTPUT ;
  USE SIGNAL ;
  PORT
   LAYER M5 ;
   RECT 89.220000 0.000000 89.268000 0.084000 ;
  END
 END k_li_d[461]
 PIN k_li_d[462]
  DIRECTION OUTPUT ;
  USE SIGNAL ;
  PORT
   LAYER M5 ;
   RECT 89.412000 0.000000 89.460000 0.084000 ;
  END
 END k_li_d[462]
 PIN k_li_d[463]
  DIRECTION OUTPUT ;
  USE SIGNAL ;
  PORT
   LAYER M5 ;
   RECT 89.556000 0.000000 89.604000 0.084000 ;
  END
 END k_li_d[463]
 PIN k_li_d[464]
  DIRECTION OUTPUT ;
  USE SIGNAL ;
  PORT
   LAYER M5 ;
   RECT 89.748000 0.000000 89.796000 0.084000 ;
  END
 END k_li_d[464]
 PIN k_li_d[465]
  DIRECTION OUTPUT ;
  USE SIGNAL ;
  PORT
   LAYER M5 ;
   RECT 89.940000 0.000000 89.988000 0.084000 ;
  END
 END k_li_d[465]
 PIN k_li_d[466]
  DIRECTION OUTPUT ;
  USE SIGNAL ;
  PORT
   LAYER M5 ;
   RECT 90.084000 0.000000 90.132000 0.084000 ;
  END
 END k_li_d[466]
 PIN k_li_d[467]
  DIRECTION OUTPUT ;
  USE SIGNAL ;
  PORT
   LAYER M5 ;
   RECT 90.276000 0.000000 90.324000 0.084000 ;
  END
 END k_li_d[467]
 PIN k_li_d[468]
  DIRECTION OUTPUT ;
  USE SIGNAL ;
  PORT
   LAYER M5 ;
   RECT 90.468000 0.000000 90.516000 0.084000 ;
  END
 END k_li_d[468]
 PIN k_li_d[469]
  DIRECTION OUTPUT ;
  USE SIGNAL ;
  PORT
   LAYER M5 ;
   RECT 90.660000 0.000000 90.708000 0.084000 ;
  END
 END k_li_d[469]
 PIN k_li_d[470]
  DIRECTION OUTPUT ;
  USE SIGNAL ;
  PORT
   LAYER M5 ;
   RECT 90.804000 0.000000 90.852000 0.084000 ;
  END
 END k_li_d[470]
 PIN k_li_d[471]
  DIRECTION OUTPUT ;
  USE SIGNAL ;
  PORT
   LAYER M5 ;
   RECT 90.996000 0.000000 91.044000 0.084000 ;
  END
 END k_li_d[471]
 PIN k_li_d[472]
  DIRECTION OUTPUT ;
  USE SIGNAL ;
  PORT
   LAYER M5 ;
   RECT 91.188000 0.000000 91.236000 0.084000 ;
  END
 END k_li_d[472]
 PIN k_li_d[473]
  DIRECTION OUTPUT ;
  USE SIGNAL ;
  PORT
   LAYER M5 ;
   RECT 91.380000 0.000000 91.428000 0.084000 ;
  END
 END k_li_d[473]
 PIN k_li_d[474]
  DIRECTION OUTPUT ;
  USE SIGNAL ;
  PORT
   LAYER M5 ;
   RECT 91.524000 0.000000 91.572000 0.084000 ;
  END
 END k_li_d[474]
 PIN k_li_d[475]
  DIRECTION OUTPUT ;
  USE SIGNAL ;
  PORT
   LAYER M5 ;
   RECT 91.716000 0.000000 91.764000 0.084000 ;
  END
 END k_li_d[475]
 PIN k_li_d[476]
  DIRECTION OUTPUT ;
  USE SIGNAL ;
  PORT
   LAYER M5 ;
   RECT 91.908000 0.000000 91.956000 0.084000 ;
  END
 END k_li_d[476]
 PIN k_li_d[477]
  DIRECTION OUTPUT ;
  USE SIGNAL ;
  PORT
   LAYER M5 ;
   RECT 92.100000 0.000000 92.148000 0.084000 ;
  END
 END k_li_d[477]
 PIN k_li_d[478]
  DIRECTION OUTPUT ;
  USE SIGNAL ;
  PORT
   LAYER M5 ;
   RECT 92.244000 0.000000 92.292000 0.084000 ;
  END
 END k_li_d[478]
 PIN k_li_d[479]
  DIRECTION OUTPUT ;
  USE SIGNAL ;
  PORT
   LAYER M5 ;
   RECT 92.436000 0.000000 92.484000 0.084000 ;
  END
 END k_li_d[479]
 PIN k_li_d[480]
  DIRECTION OUTPUT ;
  USE SIGNAL ;
  PORT
   LAYER M5 ;
   RECT 92.484000 0.000000 92.532000 0.084000 ;
  END
 END k_li_d[480]
 PIN k_li_d[481]
  DIRECTION OUTPUT ;
  USE SIGNAL ;
  PORT
   LAYER M5 ;
   RECT 92.532000 0.000000 92.580000 0.084000 ;
  END
 END k_li_d[481]
 PIN k_li_d[482]
  DIRECTION OUTPUT ;
  USE SIGNAL ;
  PORT
   LAYER M5 ;
   RECT 92.580000 0.000000 92.628000 0.084000 ;
  END
 END k_li_d[482]
 PIN k_li_d[483]
  DIRECTION OUTPUT ;
  USE SIGNAL ;
  PORT
   LAYER M5 ;
   RECT 93.156000 0.000000 93.204000 0.084000 ;
  END
 END k_li_d[483]
 PIN k_li_d[484]
  DIRECTION OUTPUT ;
  USE SIGNAL ;
  PORT
   LAYER M5 ;
   RECT 93.348000 0.000000 93.396000 0.084000 ;
  END
 END k_li_d[484]
 PIN k_li_d[485]
  DIRECTION OUTPUT ;
  USE SIGNAL ;
  PORT
   LAYER M5 ;
   RECT 93.492000 0.000000 93.540000 0.084000 ;
  END
 END k_li_d[485]
 PIN k_li_d[486]
  DIRECTION OUTPUT ;
  USE SIGNAL ;
  PORT
   LAYER M5 ;
   RECT 93.684000 0.000000 93.732000 0.084000 ;
  END
 END k_li_d[486]
 PIN k_li_d[487]
  DIRECTION OUTPUT ;
  USE SIGNAL ;
  PORT
   LAYER M5 ;
   RECT 93.876000 0.000000 93.924000 0.084000 ;
  END
 END k_li_d[487]
 PIN k_li_d[488]
  DIRECTION OUTPUT ;
  USE SIGNAL ;
  PORT
   LAYER M5 ;
   RECT 94.068000 0.000000 94.116000 0.084000 ;
  END
 END k_li_d[488]
 PIN k_li_d[489]
  DIRECTION OUTPUT ;
  USE SIGNAL ;
  PORT
   LAYER M5 ;
   RECT 94.212000 0.000000 94.260000 0.084000 ;
  END
 END k_li_d[489]
 PIN k_li_d[490]
  DIRECTION OUTPUT ;
  USE SIGNAL ;
  PORT
   LAYER M5 ;
   RECT 94.404000 0.000000 94.452000 0.084000 ;
  END
 END k_li_d[490]
 PIN k_li_d[491]
  DIRECTION OUTPUT ;
  USE SIGNAL ;
  PORT
   LAYER M5 ;
   RECT 94.596000 0.000000 94.644000 0.084000 ;
  END
 END k_li_d[491]
 PIN k_li_d[492]
  DIRECTION OUTPUT ;
  USE SIGNAL ;
  PORT
   LAYER M5 ;
   RECT 94.788000 0.000000 94.836000 0.084000 ;
  END
 END k_li_d[492]
 PIN k_li_d[493]
  DIRECTION OUTPUT ;
  USE SIGNAL ;
  PORT
   LAYER M5 ;
   RECT 94.932000 0.000000 94.980000 0.084000 ;
  END
 END k_li_d[493]
 PIN k_li_d[494]
  DIRECTION OUTPUT ;
  USE SIGNAL ;
  PORT
   LAYER M5 ;
   RECT 95.124000 0.000000 95.172000 0.084000 ;
  END
 END k_li_d[494]
 PIN k_li_d[495]
  DIRECTION OUTPUT ;
  USE SIGNAL ;
  PORT
   LAYER M5 ;
   RECT 95.316000 0.000000 95.364000 0.084000 ;
  END
 END k_li_d[495]
 PIN k_li_d[496]
  DIRECTION OUTPUT ;
  USE SIGNAL ;
  PORT
   LAYER M5 ;
   RECT 95.508000 0.000000 95.556000 0.084000 ;
  END
 END k_li_d[496]
 PIN k_li_d[497]
  DIRECTION OUTPUT ;
  USE SIGNAL ;
  PORT
   LAYER M5 ;
   RECT 95.652000 0.000000 95.700000 0.084000 ;
  END
 END k_li_d[497]
 PIN k_li_d[498]
  DIRECTION OUTPUT ;
  USE SIGNAL ;
  PORT
   LAYER M5 ;
   RECT 95.844000 0.000000 95.892000 0.084000 ;
  END
 END k_li_d[498]
 PIN k_li_d[499]
  DIRECTION OUTPUT ;
  USE SIGNAL ;
  PORT
   LAYER M5 ;
   RECT 96.036000 0.000000 96.084000 0.084000 ;
  END
 END k_li_d[499]
 PIN k_li_d[500]
  DIRECTION OUTPUT ;
  USE SIGNAL ;
  PORT
   LAYER M5 ;
   RECT 96.180000 0.000000 96.228000 0.084000 ;
  END
 END k_li_d[500]
 PIN k_li_d[501]
  DIRECTION OUTPUT ;
  USE SIGNAL ;
  PORT
   LAYER M5 ;
   RECT 96.372000 0.000000 96.420000 0.084000 ;
  END
 END k_li_d[501]
 PIN k_li_d[502]
  DIRECTION OUTPUT ;
  USE SIGNAL ;
  PORT
   LAYER M5 ;
   RECT 96.564000 0.000000 96.612000 0.084000 ;
  END
 END k_li_d[502]
 PIN k_li_d[503]
  DIRECTION OUTPUT ;
  USE SIGNAL ;
  PORT
   LAYER M5 ;
   RECT 96.756000 0.000000 96.804000 0.084000 ;
  END
 END k_li_d[503]
 PIN k_li_d[504]
  DIRECTION OUTPUT ;
  USE SIGNAL ;
  PORT
   LAYER M5 ;
   RECT 96.804000 0.000000 96.852000 0.084000 ;
  END
 END k_li_d[504]
 PIN k_li_d[505]
  DIRECTION OUTPUT ;
  USE SIGNAL ;
  PORT
   LAYER M5 ;
   RECT 96.852000 0.000000 96.900000 0.084000 ;
  END
 END k_li_d[505]
 PIN k_li_d[506]
  DIRECTION OUTPUT ;
  USE SIGNAL ;
  PORT
   LAYER M5 ;
   RECT 96.900000 0.000000 96.948000 0.084000 ;
  END
 END k_li_d[506]
 PIN k_li_d[507]
  DIRECTION OUTPUT ;
  USE SIGNAL ;
  PORT
   LAYER M5 ;
   RECT 97.476000 0.000000 97.524000 0.084000 ;
  END
 END k_li_d[507]
 PIN k_li_d[508]
  DIRECTION OUTPUT ;
  USE SIGNAL ;
  PORT
   LAYER M5 ;
   RECT 97.620000 0.000000 97.668000 0.084000 ;
  END
 END k_li_d[508]
 PIN k_li_d[509]
  DIRECTION OUTPUT ;
  USE SIGNAL ;
  PORT
   LAYER M5 ;
   RECT 97.812000 0.000000 97.860000 0.084000 ;
  END
 END k_li_d[509]
 PIN k_li_d[510]
  DIRECTION OUTPUT ;
  USE SIGNAL ;
  PORT
   LAYER M5 ;
   RECT 98.004000 0.000000 98.052000 0.084000 ;
  END
 END k_li_d[510]
 PIN k_li_d[511]
  DIRECTION OUTPUT ;
  USE SIGNAL ;
  PORT
   LAYER M5 ;
   RECT 98.196000 0.000000 98.244000 0.084000 ;
  END
 END k_li_d[511]
 PIN k_li_d[512]
  DIRECTION OUTPUT ;
  USE SIGNAL ;
  PORT
   LAYER M5 ;
   RECT 98.340000 0.000000 98.388000 0.084000 ;
  END
 END k_li_d[512]
 PIN k_li_d[513]
  DIRECTION OUTPUT ;
  USE SIGNAL ;
  PORT
   LAYER M5 ;
   RECT 98.532000 0.000000 98.580000 0.084000 ;
  END
 END k_li_d[513]
 PIN k_li_d[514]
  DIRECTION OUTPUT ;
  USE SIGNAL ;
  PORT
   LAYER M5 ;
   RECT 98.724000 0.000000 98.772000 0.084000 ;
  END
 END k_li_d[514]
 PIN k_li_d[515]
  DIRECTION OUTPUT ;
  USE SIGNAL ;
  PORT
   LAYER M5 ;
   RECT 98.868000 0.000000 98.916000 0.084000 ;
  END
 END k_li_d[515]
 PIN k_li_d[516]
  DIRECTION OUTPUT ;
  USE SIGNAL ;
  PORT
   LAYER M5 ;
   RECT 99.060000 0.000000 99.108000 0.084000 ;
  END
 END k_li_d[516]
 PIN k_li_d[517]
  DIRECTION OUTPUT ;
  USE SIGNAL ;
  PORT
   LAYER M5 ;
   RECT 99.252000 0.000000 99.300000 0.084000 ;
  END
 END k_li_d[517]
 PIN k_li_d[518]
  DIRECTION OUTPUT ;
  USE SIGNAL ;
  PORT
   LAYER M5 ;
   RECT 99.444000 0.000000 99.492000 0.084000 ;
  END
 END k_li_d[518]
 PIN k_li_d[519]
  DIRECTION OUTPUT ;
  USE SIGNAL ;
  PORT
   LAYER M5 ;
   RECT 99.588000 0.000000 99.636000 0.084000 ;
  END
 END k_li_d[519]
 PIN k_li_d[520]
  DIRECTION OUTPUT ;
  USE SIGNAL ;
  PORT
   LAYER M5 ;
   RECT 99.780000 0.000000 99.828000 0.084000 ;
  END
 END k_li_d[520]
 PIN k_li_d[521]
  DIRECTION OUTPUT ;
  USE SIGNAL ;
  PORT
   LAYER M5 ;
   RECT 99.972000 0.000000 100.020000 0.084000 ;
  END
 END k_li_d[521]
 PIN k_li_d[522]
  DIRECTION OUTPUT ;
  USE SIGNAL ;
  PORT
   LAYER M5 ;
   RECT 100.164000 0.000000 100.212000 0.084000 ;
  END
 END k_li_d[522]
 PIN k_li_d[523]
  DIRECTION OUTPUT ;
  USE SIGNAL ;
  PORT
   LAYER M5 ;
   RECT 100.308000 0.000000 100.356000 0.084000 ;
  END
 END k_li_d[523]
 PIN k_li_d[524]
  DIRECTION OUTPUT ;
  USE SIGNAL ;
  PORT
   LAYER M5 ;
   RECT 100.500000 0.000000 100.548000 0.084000 ;
  END
 END k_li_d[524]
 PIN k_li_d[525]
  DIRECTION OUTPUT ;
  USE SIGNAL ;
  PORT
   LAYER M5 ;
   RECT 100.692000 0.000000 100.740000 0.084000 ;
  END
 END k_li_d[525]
 PIN k_li_d[526]
  DIRECTION OUTPUT ;
  USE SIGNAL ;
  PORT
   LAYER M5 ;
   RECT 100.884000 0.000000 100.932000 0.084000 ;
  END
 END k_li_d[526]
 PIN k_li_d[527]
  DIRECTION OUTPUT ;
  USE SIGNAL ;
  PORT
   LAYER M5 ;
   RECT 101.028000 0.000000 101.076000 0.084000 ;
  END
 END k_li_d[527]
 PIN k_li_d[528]
  DIRECTION OUTPUT ;
  USE SIGNAL ;
  PORT
   LAYER M5 ;
   RECT 101.124000 0.000000 101.172000 0.084000 ;
  END
 END k_li_d[528]
 PIN k_li_d[529]
  DIRECTION OUTPUT ;
  USE SIGNAL ;
  PORT
   LAYER M5 ;
   RECT 101.172000 0.000000 101.220000 0.084000 ;
  END
 END k_li_d[529]
 PIN k_li_d[530]
  DIRECTION OUTPUT ;
  USE SIGNAL ;
  PORT
   LAYER M5 ;
   RECT 101.220000 0.000000 101.268000 0.084000 ;
  END
 END k_li_d[530]
 PIN k_li_d[531]
  DIRECTION OUTPUT ;
  USE SIGNAL ;
  PORT
   LAYER M5 ;
   RECT 101.796000 0.000000 101.844000 0.084000 ;
  END
 END k_li_d[531]
 PIN k_li_d[532]
  DIRECTION OUTPUT ;
  USE SIGNAL ;
  PORT
   LAYER M5 ;
   RECT 101.940000 0.000000 101.988000 0.084000 ;
  END
 END k_li_d[532]
 PIN k_li_d[533]
  DIRECTION OUTPUT ;
  USE SIGNAL ;
  PORT
   LAYER M5 ;
   RECT 102.132000 0.000000 102.180000 0.084000 ;
  END
 END k_li_d[533]
 PIN k_li_d[534]
  DIRECTION OUTPUT ;
  USE SIGNAL ;
  PORT
   LAYER M5 ;
   RECT 102.276000 0.000000 102.324000 0.084000 ;
  END
 END k_li_d[534]
 PIN k_li_d[535]
  DIRECTION OUTPUT ;
  USE SIGNAL ;
  PORT
   LAYER M5 ;
   RECT 102.468000 0.000000 102.516000 0.084000 ;
  END
 END k_li_d[535]
 PIN k_li_d[536]
  DIRECTION OUTPUT ;
  USE SIGNAL ;
  PORT
   LAYER M5 ;
   RECT 102.660000 0.000000 102.708000 0.084000 ;
  END
 END k_li_d[536]
 PIN k_li_d[537]
  DIRECTION OUTPUT ;
  USE SIGNAL ;
  PORT
   LAYER M5 ;
   RECT 102.852000 0.000000 102.900000 0.084000 ;
  END
 END k_li_d[537]
 PIN k_li_d[538]
  DIRECTION OUTPUT ;
  USE SIGNAL ;
  PORT
   LAYER M5 ;
   RECT 102.996000 0.000000 103.044000 0.084000 ;
  END
 END k_li_d[538]
 PIN k_li_d[539]
  DIRECTION OUTPUT ;
  USE SIGNAL ;
  PORT
   LAYER M5 ;
   RECT 103.188000 0.000000 103.236000 0.084000 ;
  END
 END k_li_d[539]
 PIN k_li_d[540]
  DIRECTION OUTPUT ;
  USE SIGNAL ;
  PORT
   LAYER M5 ;
   RECT 103.380000 0.000000 103.428000 0.084000 ;
  END
 END k_li_d[540]
 PIN k_li_d[541]
  DIRECTION OUTPUT ;
  USE SIGNAL ;
  PORT
   LAYER M5 ;
   RECT 103.572000 0.000000 103.620000 0.084000 ;
  END
 END k_li_d[541]
 PIN k_li_d[542]
  DIRECTION OUTPUT ;
  USE SIGNAL ;
  PORT
   LAYER M5 ;
   RECT 103.716000 0.000000 103.764000 0.084000 ;
  END
 END k_li_d[542]
 PIN k_li_d[543]
  DIRECTION OUTPUT ;
  USE SIGNAL ;
  PORT
   LAYER M5 ;
   RECT 103.908000 0.000000 103.956000 0.084000 ;
  END
 END k_li_d[543]
 PIN k_li_d[544]
  DIRECTION OUTPUT ;
  USE SIGNAL ;
  PORT
   LAYER M5 ;
   RECT 104.100000 0.000000 104.148000 0.084000 ;
  END
 END k_li_d[544]
 PIN k_li_d[545]
  DIRECTION OUTPUT ;
  USE SIGNAL ;
  PORT
   LAYER M5 ;
   RECT 104.292000 0.000000 104.340000 0.084000 ;
  END
 END k_li_d[545]
 PIN k_li_d[546]
  DIRECTION OUTPUT ;
  USE SIGNAL ;
  PORT
   LAYER M5 ;
   RECT 104.436000 0.000000 104.484000 0.084000 ;
  END
 END k_li_d[546]
 PIN k_li_d[547]
  DIRECTION OUTPUT ;
  USE SIGNAL ;
  PORT
   LAYER M5 ;
   RECT 104.628000 0.000000 104.676000 0.084000 ;
  END
 END k_li_d[547]
 PIN k_li_d[548]
  DIRECTION OUTPUT ;
  USE SIGNAL ;
  PORT
   LAYER M5 ;
   RECT 104.820000 0.000000 104.868000 0.084000 ;
  END
 END k_li_d[548]
 PIN k_li_d[549]
  DIRECTION OUTPUT ;
  USE SIGNAL ;
  PORT
   LAYER M5 ;
   RECT 104.964000 0.000000 105.012000 0.084000 ;
  END
 END k_li_d[549]
 PIN k_li_d[550]
  DIRECTION OUTPUT ;
  USE SIGNAL ;
  PORT
   LAYER M5 ;
   RECT 105.156000 0.000000 105.204000 0.084000 ;
  END
 END k_li_d[550]
 PIN k_li_d[551]
  DIRECTION OUTPUT ;
  USE SIGNAL ;
  PORT
   LAYER M5 ;
   RECT 105.348000 0.000000 105.396000 0.084000 ;
  END
 END k_li_d[551]
 PIN k_li_d[552]
  DIRECTION OUTPUT ;
  USE SIGNAL ;
  PORT
   LAYER M5 ;
   RECT 105.444000 0.000000 105.492000 0.084000 ;
  END
 END k_li_d[552]
 PIN k_flt[0]
  DIRECTION OUTPUT ;
  USE SIGNAL ;
  PORT
   LAYER M5 ;
   RECT 105.492000 0.000000 105.540000 0.084000 ;
  END
 END k_flt[0]
 PIN k_flt[1]
  DIRECTION OUTPUT ;
  USE SIGNAL ;
  PORT
   LAYER M5 ;
   RECT 105.540000 0.000000 105.588000 0.084000 ;
  END
 END k_flt[1]
 PIN k_flt[2]
  DIRECTION OUTPUT ;
  USE SIGNAL ;
  PORT
   LAYER M5 ;
   RECT 106.116000 0.000000 106.164000 0.084000 ;
  END
 END k_flt[2]
 PIN n_lo_r
  DIRECTION INPUT ;
  USE SIGNAL ;
  PORT
   LAYER M4 ;
   RECT 112.236000 6.236000 112.320000 6.268000 ;
  END
 END n_lo_r
 PIN n_li_v
  DIRECTION INPUT ;
  USE SIGNAL ;
  PORT
   LAYER M4 ;
   RECT 112.236000 6.380000 112.320000 6.412000 ;
  END
 END n_li_v
 PIN n_li_d[0]
  DIRECTION INPUT ;
  USE SIGNAL ;
  PORT
   LAYER M4 ;
   RECT 112.236000 6.572000 112.320000 6.604000 ;
  END
 END n_li_d[0]
 PIN n_li_d[1]
  DIRECTION INPUT ;
  USE SIGNAL ;
  PORT
   LAYER M4 ;
   RECT 112.236000 6.764000 112.320000 6.796000 ;
  END
 END n_li_d[1]
 PIN n_li_d[2]
  DIRECTION INPUT ;
  USE SIGNAL ;
  PORT
   LAYER M4 ;
   RECT 112.236000 6.956000 112.320000 6.988000 ;
  END
 END n_li_d[2]
 PIN n_li_d[3]
  DIRECTION INPUT ;
  USE SIGNAL ;
  PORT
   LAYER M4 ;
   RECT 112.236000 7.100000 112.320000 7.132000 ;
  END
 END n_li_d[3]
 PIN n_li_d[4]
  DIRECTION INPUT ;
  USE SIGNAL ;
  PORT
   LAYER M4 ;
   RECT 112.236000 7.292000 112.320000 7.324000 ;
  END
 END n_li_d[4]
 PIN n_li_d[5]
  DIRECTION INPUT ;
  USE SIGNAL ;
  PORT
   LAYER M4 ;
   RECT 112.236000 7.484000 112.320000 7.516000 ;
  END
 END n_li_d[5]
 PIN n_li_d[6]
  DIRECTION INPUT ;
  USE SIGNAL ;
  PORT
   LAYER M4 ;
   RECT 112.236000 7.628000 112.320000 7.660000 ;
  END
 END n_li_d[6]
 PIN n_li_d[7]
  DIRECTION INPUT ;
  USE SIGNAL ;
  PORT
   LAYER M4 ;
   RECT 112.236000 7.820000 112.320000 7.852000 ;
  END
 END n_li_d[7]
 PIN n_li_d[8]
  DIRECTION INPUT ;
  USE SIGNAL ;
  PORT
   LAYER M4 ;
   RECT 112.236000 8.012000 112.320000 8.044000 ;
  END
 END n_li_d[8]
 PIN n_li_d[9]
  DIRECTION INPUT ;
  USE SIGNAL ;
  PORT
   LAYER M4 ;
   RECT 112.236000 8.204000 112.320000 8.236000 ;
  END
 END n_li_d[9]
 PIN n_li_d[10]
  DIRECTION INPUT ;
  USE SIGNAL ;
  PORT
   LAYER M4 ;
   RECT 112.236000 8.348000 112.320000 8.380000 ;
  END
 END n_li_d[10]
 PIN n_li_d[11]
  DIRECTION INPUT ;
  USE SIGNAL ;
  PORT
   LAYER M4 ;
   RECT 112.236000 8.540000 112.320000 8.572000 ;
  END
 END n_li_d[11]
 PIN n_li_d[12]
  DIRECTION INPUT ;
  USE SIGNAL ;
  PORT
   LAYER M4 ;
   RECT 112.236000 8.732000 112.320000 8.764000 ;
  END
 END n_li_d[12]
 PIN n_li_d[13]
  DIRECTION INPUT ;
  USE SIGNAL ;
  PORT
   LAYER M4 ;
   RECT 112.236000 8.924000 112.320000 8.956000 ;
  END
 END n_li_d[13]
 PIN n_li_d[14]
  DIRECTION INPUT ;
  USE SIGNAL ;
  PORT
   LAYER M4 ;
   RECT 112.236000 9.068000 112.320000 9.100000 ;
  END
 END n_li_d[14]
 PIN n_li_d[15]
  DIRECTION INPUT ;
  USE SIGNAL ;
  PORT
   LAYER M4 ;
   RECT 112.236000 9.260000 112.320000 9.292000 ;
  END
 END n_li_d[15]
 PIN n_li_d[16]
  DIRECTION INPUT ;
  USE SIGNAL ;
  PORT
   LAYER M4 ;
   RECT 112.236000 9.452000 112.320000 9.484000 ;
  END
 END n_li_d[16]
 PIN n_li_d[17]
  DIRECTION INPUT ;
  USE SIGNAL ;
  PORT
   LAYER M4 ;
   RECT 112.236000 9.644000 112.320000 9.676000 ;
  END
 END n_li_d[17]
 PIN n_li_d[18]
  DIRECTION INPUT ;
  USE SIGNAL ;
  PORT
   LAYER M4 ;
   RECT 112.236000 9.788000 112.320000 9.820000 ;
  END
 END n_li_d[18]
 PIN n_li_d[19]
  DIRECTION INPUT ;
  USE SIGNAL ;
  PORT
   LAYER M4 ;
   RECT 112.236000 9.980000 112.320000 10.012000 ;
  END
 END n_li_d[19]
 PIN n_li_d[20]
  DIRECTION INPUT ;
  USE SIGNAL ;
  PORT
   LAYER M4 ;
   RECT 112.236000 10.172000 112.320000 10.204000 ;
  END
 END n_li_d[20]
 PIN n_li_d[21]
  DIRECTION INPUT ;
  USE SIGNAL ;
  PORT
   LAYER M4 ;
   RECT 112.236000 10.364000 112.320000 10.396000 ;
  END
 END n_li_d[21]
 PIN n_li_d[22]
  DIRECTION INPUT ;
  USE SIGNAL ;
  PORT
   LAYER M4 ;
   RECT 112.236000 10.508000 112.320000 10.540000 ;
  END
 END n_li_d[22]
 PIN n_li_d[23]
  DIRECTION INPUT ;
  USE SIGNAL ;
  PORT
   LAYER M4 ;
   RECT 112.236000 10.700000 112.320000 10.732000 ;
  END
 END n_li_d[23]
 PIN n_li_d[24]
  DIRECTION INPUT ;
  USE SIGNAL ;
  PORT
   LAYER M4 ;
   RECT 112.236000 10.892000 112.320000 10.924000 ;
  END
 END n_li_d[24]
 PIN n_li_d[25]
  DIRECTION INPUT ;
  USE SIGNAL ;
  PORT
   LAYER M4 ;
   RECT 112.236000 11.036000 112.320000 11.068000 ;
  END
 END n_li_d[25]
 PIN n_li_d[26]
  DIRECTION INPUT ;
  USE SIGNAL ;
  PORT
   LAYER M4 ;
   RECT 112.236000 11.228000 112.320000 11.260000 ;
  END
 END n_li_d[26]
 PIN n_li_d[27]
  DIRECTION INPUT ;
  USE SIGNAL ;
  PORT
   LAYER M4 ;
   RECT 112.236000 11.420000 112.320000 11.452000 ;
  END
 END n_li_d[27]
 PIN n_li_d[28]
  DIRECTION INPUT ;
  USE SIGNAL ;
  PORT
   LAYER M4 ;
   RECT 112.236000 11.612000 112.320000 11.644000 ;
  END
 END n_li_d[28]
 PIN n_li_d[29]
  DIRECTION INPUT ;
  USE SIGNAL ;
  PORT
   LAYER M4 ;
   RECT 112.236000 11.756000 112.320000 11.788000 ;
  END
 END n_li_d[29]
 PIN n_li_d[30]
  DIRECTION INPUT ;
  USE SIGNAL ;
  PORT
   LAYER M4 ;
   RECT 112.236000 11.948000 112.320000 11.980000 ;
  END
 END n_li_d[30]
 PIN n_li_d[31]
  DIRECTION INPUT ;
  USE SIGNAL ;
  PORT
   LAYER M4 ;
   RECT 112.236000 12.140000 112.320000 12.172000 ;
  END
 END n_li_d[31]
 PIN n_li_d[32]
  DIRECTION INPUT ;
  USE SIGNAL ;
  PORT
   LAYER M4 ;
   RECT 112.236000 12.332000 112.320000 12.364000 ;
  END
 END n_li_d[32]
 PIN n_li_d[33]
  DIRECTION INPUT ;
  USE SIGNAL ;
  PORT
   LAYER M4 ;
   RECT 112.236000 12.476000 112.320000 12.508000 ;
  END
 END n_li_d[33]
 PIN n_li_d[34]
  DIRECTION INPUT ;
  USE SIGNAL ;
  PORT
   LAYER M4 ;
   RECT 112.236000 12.668000 112.320000 12.700000 ;
  END
 END n_li_d[34]
 PIN n_li_d[35]
  DIRECTION INPUT ;
  USE SIGNAL ;
  PORT
   LAYER M4 ;
   RECT 112.236000 12.860000 112.320000 12.892000 ;
  END
 END n_li_d[35]
 PIN n_li_d[36]
  DIRECTION INPUT ;
  USE SIGNAL ;
  PORT
   LAYER M4 ;
   RECT 112.236000 13.052000 112.320000 13.084000 ;
  END
 END n_li_d[36]
 PIN n_li_d[37]
  DIRECTION INPUT ;
  USE SIGNAL ;
  PORT
   LAYER M4 ;
   RECT 112.236000 13.196000 112.320000 13.228000 ;
  END
 END n_li_d[37]
 PIN n_li_d[38]
  DIRECTION INPUT ;
  USE SIGNAL ;
  PORT
   LAYER M4 ;
   RECT 112.236000 13.388000 112.320000 13.420000 ;
  END
 END n_li_d[38]
 PIN n_li_d[39]
  DIRECTION INPUT ;
  USE SIGNAL ;
  PORT
   LAYER M4 ;
   RECT 112.236000 13.580000 112.320000 13.612000 ;
  END
 END n_li_d[39]
 PIN n_li_d[40]
  DIRECTION INPUT ;
  USE SIGNAL ;
  PORT
   LAYER M4 ;
   RECT 112.236000 13.724000 112.320000 13.756000 ;
  END
 END n_li_d[40]
 PIN n_li_d[41]
  DIRECTION INPUT ;
  USE SIGNAL ;
  PORT
   LAYER M4 ;
   RECT 112.236000 13.916000 112.320000 13.948000 ;
  END
 END n_li_d[41]
 PIN n_li_d[42]
  DIRECTION INPUT ;
  USE SIGNAL ;
  PORT
   LAYER M4 ;
   RECT 112.236000 14.108000 112.320000 14.140000 ;
  END
 END n_li_d[42]
 PIN n_li_d[43]
  DIRECTION INPUT ;
  USE SIGNAL ;
  PORT
   LAYER M4 ;
   RECT 112.236000 14.300000 112.320000 14.332000 ;
  END
 END n_li_d[43]
 PIN n_li_d[44]
  DIRECTION INPUT ;
  USE SIGNAL ;
  PORT
   LAYER M4 ;
   RECT 112.236000 14.444000 112.320000 14.476000 ;
  END
 END n_li_d[44]
 PIN n_li_d[45]
  DIRECTION INPUT ;
  USE SIGNAL ;
  PORT
   LAYER M4 ;
   RECT 112.236000 14.636000 112.320000 14.668000 ;
  END
 END n_li_d[45]
 PIN n_li_d[46]
  DIRECTION INPUT ;
  USE SIGNAL ;
  PORT
   LAYER M4 ;
   RECT 112.236000 14.828000 112.320000 14.860000 ;
  END
 END n_li_d[46]
 PIN n_li_d[47]
  DIRECTION INPUT ;
  USE SIGNAL ;
  PORT
   LAYER M4 ;
   RECT 112.236000 15.020000 112.320000 15.052000 ;
  END
 END n_li_d[47]
 PIN n_li_d[48]
  DIRECTION INPUT ;
  USE SIGNAL ;
  PORT
   LAYER M4 ;
   RECT 112.236000 15.164000 112.320000 15.196000 ;
  END
 END n_li_d[48]
 PIN n_li_d[49]
  DIRECTION INPUT ;
  USE SIGNAL ;
  PORT
   LAYER M4 ;
   RECT 112.236000 15.356000 112.320000 15.388000 ;
  END
 END n_li_d[49]
 PIN n_li_d[50]
  DIRECTION INPUT ;
  USE SIGNAL ;
  PORT
   LAYER M4 ;
   RECT 112.236000 15.548000 112.320000 15.580000 ;
  END
 END n_li_d[50]
 PIN n_li_d[51]
  DIRECTION INPUT ;
  USE SIGNAL ;
  PORT
   LAYER M4 ;
   RECT 112.236000 15.740000 112.320000 15.772000 ;
  END
 END n_li_d[51]
 PIN n_li_d[52]
  DIRECTION INPUT ;
  USE SIGNAL ;
  PORT
   LAYER M4 ;
   RECT 112.236000 15.884000 112.320000 15.916000 ;
  END
 END n_li_d[52]
 PIN n_li_d[53]
  DIRECTION INPUT ;
  USE SIGNAL ;
  PORT
   LAYER M4 ;
   RECT 112.236000 16.076000 112.320000 16.108000 ;
  END
 END n_li_d[53]
 PIN n_li_d[54]
  DIRECTION INPUT ;
  USE SIGNAL ;
  PORT
   LAYER M4 ;
   RECT 112.236000 16.268000 112.320000 16.300000 ;
  END
 END n_li_d[54]
 PIN n_li_d[55]
  DIRECTION INPUT ;
  USE SIGNAL ;
  PORT
   LAYER M4 ;
   RECT 112.236000 16.412000 112.320000 16.444000 ;
  END
 END n_li_d[55]
 PIN n_li_d[56]
  DIRECTION INPUT ;
  USE SIGNAL ;
  PORT
   LAYER M4 ;
   RECT 112.236000 16.604000 112.320000 16.636000 ;
  END
 END n_li_d[56]
 PIN n_li_d[57]
  DIRECTION INPUT ;
  USE SIGNAL ;
  PORT
   LAYER M4 ;
   RECT 112.236000 16.796000 112.320000 16.828000 ;
  END
 END n_li_d[57]
 PIN n_li_d[58]
  DIRECTION INPUT ;
  USE SIGNAL ;
  PORT
   LAYER M4 ;
   RECT 112.236000 16.988000 112.320000 17.020000 ;
  END
 END n_li_d[58]
 PIN n_li_d[59]
  DIRECTION INPUT ;
  USE SIGNAL ;
  PORT
   LAYER M4 ;
   RECT 112.236000 17.132000 112.320000 17.164000 ;
  END
 END n_li_d[59]
 PIN n_li_d[60]
  DIRECTION INPUT ;
  USE SIGNAL ;
  PORT
   LAYER M4 ;
   RECT 112.236000 17.324000 112.320000 17.356000 ;
  END
 END n_li_d[60]
 PIN n_li_d[61]
  DIRECTION INPUT ;
  USE SIGNAL ;
  PORT
   LAYER M4 ;
   RECT 112.236000 17.516000 112.320000 17.548000 ;
  END
 END n_li_d[61]
 PIN n_li_d[62]
  DIRECTION INPUT ;
  USE SIGNAL ;
  PORT
   LAYER M4 ;
   RECT 112.236000 17.708000 112.320000 17.740000 ;
  END
 END n_li_d[62]
 PIN n_li_d[63]
  DIRECTION INPUT ;
  USE SIGNAL ;
  PORT
   LAYER M4 ;
   RECT 112.236000 17.852000 112.320000 17.884000 ;
  END
 END n_li_d[63]
 PIN n_li_d[64]
  DIRECTION INPUT ;
  USE SIGNAL ;
  PORT
   LAYER M4 ;
   RECT 112.236000 18.044000 112.320000 18.076000 ;
  END
 END n_li_d[64]
 PIN n_li_d[65]
  DIRECTION INPUT ;
  USE SIGNAL ;
  PORT
   LAYER M4 ;
   RECT 112.236000 18.236000 112.320000 18.268000 ;
  END
 END n_li_d[65]
 PIN n_li_d[66]
  DIRECTION INPUT ;
  USE SIGNAL ;
  PORT
   LAYER M4 ;
   RECT 112.236000 18.428000 112.320000 18.460000 ;
  END
 END n_li_d[66]
 PIN n_li_d[67]
  DIRECTION INPUT ;
  USE SIGNAL ;
  PORT
   LAYER M4 ;
   RECT 112.236000 18.572000 112.320000 18.604000 ;
  END
 END n_li_d[67]
 PIN n_li_d[68]
  DIRECTION INPUT ;
  USE SIGNAL ;
  PORT
   LAYER M4 ;
   RECT 112.236000 18.764000 112.320000 18.796000 ;
  END
 END n_li_d[68]
 PIN n_li_d[69]
  DIRECTION INPUT ;
  USE SIGNAL ;
  PORT
   LAYER M4 ;
   RECT 112.236000 18.956000 112.320000 18.988000 ;
  END
 END n_li_d[69]
 PIN n_li_d[70]
  DIRECTION INPUT ;
  USE SIGNAL ;
  PORT
   LAYER M4 ;
   RECT 112.236000 19.148000 112.320000 19.180000 ;
  END
 END n_li_d[70]
 PIN n_li_d[71]
  DIRECTION INPUT ;
  USE SIGNAL ;
  PORT
   LAYER M4 ;
   RECT 112.236000 19.292000 112.320000 19.324000 ;
  END
 END n_li_d[71]
 PIN n_li_d[72]
  DIRECTION INPUT ;
  USE SIGNAL ;
  PORT
   LAYER M4 ;
   RECT 112.236000 19.484000 112.320000 19.516000 ;
  END
 END n_li_d[72]
 PIN n_li_d[73]
  DIRECTION INPUT ;
  USE SIGNAL ;
  PORT
   LAYER M4 ;
   RECT 112.236000 19.676000 112.320000 19.708000 ;
  END
 END n_li_d[73]
 PIN n_li_d[74]
  DIRECTION INPUT ;
  USE SIGNAL ;
  PORT
   LAYER M4 ;
   RECT 112.236000 19.820000 112.320000 19.852000 ;
  END
 END n_li_d[74]
 PIN n_li_d[75]
  DIRECTION INPUT ;
  USE SIGNAL ;
  PORT
   LAYER M4 ;
   RECT 112.236000 20.012000 112.320000 20.044000 ;
  END
 END n_li_d[75]
 PIN n_li_d[76]
  DIRECTION INPUT ;
  USE SIGNAL ;
  PORT
   LAYER M4 ;
   RECT 112.236000 20.204000 112.320000 20.236000 ;
  END
 END n_li_d[76]
 PIN n_li_d[77]
  DIRECTION INPUT ;
  USE SIGNAL ;
  PORT
   LAYER M4 ;
   RECT 112.236000 20.396000 112.320000 20.428000 ;
  END
 END n_li_d[77]
 PIN n_li_d[78]
  DIRECTION INPUT ;
  USE SIGNAL ;
  PORT
   LAYER M4 ;
   RECT 112.236000 20.540000 112.320000 20.572000 ;
  END
 END n_li_d[78]
 PIN n_li_d[79]
  DIRECTION INPUT ;
  USE SIGNAL ;
  PORT
   LAYER M4 ;
   RECT 112.236000 20.732000 112.320000 20.764000 ;
  END
 END n_li_d[79]
 PIN n_li_d[80]
  DIRECTION INPUT ;
  USE SIGNAL ;
  PORT
   LAYER M4 ;
   RECT 112.236000 20.924000 112.320000 20.956000 ;
  END
 END n_li_d[80]
 PIN n_li_d[81]
  DIRECTION INPUT ;
  USE SIGNAL ;
  PORT
   LAYER M4 ;
   RECT 112.236000 21.116000 112.320000 21.148000 ;
  END
 END n_li_d[81]
 PIN n_li_d[82]
  DIRECTION INPUT ;
  USE SIGNAL ;
  PORT
   LAYER M4 ;
   RECT 112.236000 21.260000 112.320000 21.292000 ;
  END
 END n_li_d[82]
 PIN n_li_d[83]
  DIRECTION INPUT ;
  USE SIGNAL ;
  PORT
   LAYER M4 ;
   RECT 112.236000 21.452000 112.320000 21.484000 ;
  END
 END n_li_d[83]
 PIN n_li_d[84]
  DIRECTION INPUT ;
  USE SIGNAL ;
  PORT
   LAYER M4 ;
   RECT 112.236000 21.644000 112.320000 21.676000 ;
  END
 END n_li_d[84]
 PIN n_li_d[85]
  DIRECTION INPUT ;
  USE SIGNAL ;
  PORT
   LAYER M4 ;
   RECT 112.236000 21.836000 112.320000 21.868000 ;
  END
 END n_li_d[85]
 PIN n_li_d[86]
  DIRECTION INPUT ;
  USE SIGNAL ;
  PORT
   LAYER M4 ;
   RECT 112.236000 21.980000 112.320000 22.012000 ;
  END
 END n_li_d[86]
 PIN n_li_d[87]
  DIRECTION INPUT ;
  USE SIGNAL ;
  PORT
   LAYER M4 ;
   RECT 112.236000 22.172000 112.320000 22.204000 ;
  END
 END n_li_d[87]
 PIN n_li_d[88]
  DIRECTION INPUT ;
  USE SIGNAL ;
  PORT
   LAYER M4 ;
   RECT 112.236000 22.364000 112.320000 22.396000 ;
  END
 END n_li_d[88]
 PIN n_li_d[89]
  DIRECTION INPUT ;
  USE SIGNAL ;
  PORT
   LAYER M4 ;
   RECT 112.236000 22.508000 112.320000 22.540000 ;
  END
 END n_li_d[89]
 PIN n_li_d[90]
  DIRECTION INPUT ;
  USE SIGNAL ;
  PORT
   LAYER M4 ;
   RECT 112.236000 22.700000 112.320000 22.732000 ;
  END
 END n_li_d[90]
 PIN n_li_d[91]
  DIRECTION INPUT ;
  USE SIGNAL ;
  PORT
   LAYER M4 ;
   RECT 112.236000 22.892000 112.320000 22.924000 ;
  END
 END n_li_d[91]
 PIN n_li_d[92]
  DIRECTION INPUT ;
  USE SIGNAL ;
  PORT
   LAYER M4 ;
   RECT 112.236000 23.084000 112.320000 23.116000 ;
  END
 END n_li_d[92]
 PIN n_li_d[93]
  DIRECTION INPUT ;
  USE SIGNAL ;
  PORT
   LAYER M4 ;
   RECT 112.236000 23.228000 112.320000 23.260000 ;
  END
 END n_li_d[93]
 PIN n_li_d[94]
  DIRECTION INPUT ;
  USE SIGNAL ;
  PORT
   LAYER M4 ;
   RECT 112.236000 23.420000 112.320000 23.452000 ;
  END
 END n_li_d[94]
 PIN n_li_d[95]
  DIRECTION INPUT ;
  USE SIGNAL ;
  PORT
   LAYER M4 ;
   RECT 112.236000 23.612000 112.320000 23.644000 ;
  END
 END n_li_d[95]
 PIN n_li_d[96]
  DIRECTION INPUT ;
  USE SIGNAL ;
  PORT
   LAYER M4 ;
   RECT 112.236000 23.804000 112.320000 23.836000 ;
  END
 END n_li_d[96]
 PIN n_li_d[97]
  DIRECTION INPUT ;
  USE SIGNAL ;
  PORT
   LAYER M4 ;
   RECT 112.236000 23.948000 112.320000 23.980000 ;
  END
 END n_li_d[97]
 PIN n_li_d[98]
  DIRECTION INPUT ;
  USE SIGNAL ;
  PORT
   LAYER M4 ;
   RECT 112.236000 24.140000 112.320000 24.172000 ;
  END
 END n_li_d[98]
 PIN n_li_d[99]
  DIRECTION INPUT ;
  USE SIGNAL ;
  PORT
   LAYER M4 ;
   RECT 112.236000 24.332000 112.320000 24.364000 ;
  END
 END n_li_d[99]
 PIN n_li_d[100]
  DIRECTION INPUT ;
  USE SIGNAL ;
  PORT
   LAYER M4 ;
   RECT 112.236000 24.524000 112.320000 24.556000 ;
  END
 END n_li_d[100]
 PIN n_li_d[101]
  DIRECTION INPUT ;
  USE SIGNAL ;
  PORT
   LAYER M4 ;
   RECT 112.236000 24.668000 112.320000 24.700000 ;
  END
 END n_li_d[101]
 PIN n_li_d[102]
  DIRECTION INPUT ;
  USE SIGNAL ;
  PORT
   LAYER M4 ;
   RECT 112.236000 24.860000 112.320000 24.892000 ;
  END
 END n_li_d[102]
 PIN n_li_d[103]
  DIRECTION INPUT ;
  USE SIGNAL ;
  PORT
   LAYER M4 ;
   RECT 112.236000 25.052000 112.320000 25.084000 ;
  END
 END n_li_d[103]
 PIN n_li_d[104]
  DIRECTION INPUT ;
  USE SIGNAL ;
  PORT
   LAYER M4 ;
   RECT 112.236000 25.244000 112.320000 25.276000 ;
  END
 END n_li_d[104]
 PIN n_li_d[105]
  DIRECTION INPUT ;
  USE SIGNAL ;
  PORT
   LAYER M4 ;
   RECT 112.236000 25.388000 112.320000 25.420000 ;
  END
 END n_li_d[105]
 PIN n_li_d[106]
  DIRECTION INPUT ;
  USE SIGNAL ;
  PORT
   LAYER M4 ;
   RECT 112.236000 25.580000 112.320000 25.612000 ;
  END
 END n_li_d[106]
 PIN n_li_d[107]
  DIRECTION INPUT ;
  USE SIGNAL ;
  PORT
   LAYER M4 ;
   RECT 112.236000 25.772000 112.320000 25.804000 ;
  END
 END n_li_d[107]
 PIN n_li_d[108]
  DIRECTION INPUT ;
  USE SIGNAL ;
  PORT
   LAYER M4 ;
   RECT 112.236000 25.916000 112.320000 25.948000 ;
  END
 END n_li_d[108]
 PIN n_li_d[109]
  DIRECTION INPUT ;
  USE SIGNAL ;
  PORT
   LAYER M4 ;
   RECT 112.236000 26.108000 112.320000 26.140000 ;
  END
 END n_li_d[109]
 PIN n_li_d[110]
  DIRECTION INPUT ;
  USE SIGNAL ;
  PORT
   LAYER M4 ;
   RECT 112.236000 26.300000 112.320000 26.332000 ;
  END
 END n_li_d[110]
 PIN n_li_d[111]
  DIRECTION INPUT ;
  USE SIGNAL ;
  PORT
   LAYER M4 ;
   RECT 112.236000 26.492000 112.320000 26.524000 ;
  END
 END n_li_d[111]
 PIN n_li_d[112]
  DIRECTION INPUT ;
  USE SIGNAL ;
  PORT
   LAYER M4 ;
   RECT 112.236000 26.636000 112.320000 26.668000 ;
  END
 END n_li_d[112]
 PIN n_li_d[113]
  DIRECTION INPUT ;
  USE SIGNAL ;
  PORT
   LAYER M4 ;
   RECT 112.236000 26.828000 112.320000 26.860000 ;
  END
 END n_li_d[113]
 PIN n_li_d[114]
  DIRECTION INPUT ;
  USE SIGNAL ;
  PORT
   LAYER M4 ;
   RECT 112.236000 27.020000 112.320000 27.052000 ;
  END
 END n_li_d[114]
 PIN n_li_d[115]
  DIRECTION INPUT ;
  USE SIGNAL ;
  PORT
   LAYER M4 ;
   RECT 112.236000 27.212000 112.320000 27.244000 ;
  END
 END n_li_d[115]
 PIN n_li_d[116]
  DIRECTION INPUT ;
  USE SIGNAL ;
  PORT
   LAYER M4 ;
   RECT 112.236000 27.356000 112.320000 27.388000 ;
  END
 END n_li_d[116]
 PIN n_li_d[117]
  DIRECTION INPUT ;
  USE SIGNAL ;
  PORT
   LAYER M4 ;
   RECT 112.236000 27.548000 112.320000 27.580000 ;
  END
 END n_li_d[117]
 PIN n_li_d[118]
  DIRECTION INPUT ;
  USE SIGNAL ;
  PORT
   LAYER M4 ;
   RECT 112.236000 27.740000 112.320000 27.772000 ;
  END
 END n_li_d[118]
 PIN n_li_d[119]
  DIRECTION INPUT ;
  USE SIGNAL ;
  PORT
   LAYER M4 ;
   RECT 112.236000 27.932000 112.320000 27.964000 ;
  END
 END n_li_d[119]
 PIN n_li_d[120]
  DIRECTION INPUT ;
  USE SIGNAL ;
  PORT
   LAYER M4 ;
   RECT 112.236000 28.076000 112.320000 28.108000 ;
  END
 END n_li_d[120]
 PIN n_li_d[121]
  DIRECTION INPUT ;
  USE SIGNAL ;
  PORT
   LAYER M4 ;
   RECT 112.236000 28.268000 112.320000 28.300000 ;
  END
 END n_li_d[121]
 PIN n_li_d[122]
  DIRECTION INPUT ;
  USE SIGNAL ;
  PORT
   LAYER M4 ;
   RECT 112.236000 28.460000 112.320000 28.492000 ;
  END
 END n_li_d[122]
 PIN n_li_d[123]
  DIRECTION INPUT ;
  USE SIGNAL ;
  PORT
   LAYER M4 ;
   RECT 112.236000 28.604000 112.320000 28.636000 ;
  END
 END n_li_d[123]
 PIN n_li_d[124]
  DIRECTION INPUT ;
  USE SIGNAL ;
  PORT
   LAYER M4 ;
   RECT 112.236000 28.796000 112.320000 28.828000 ;
  END
 END n_li_d[124]
 PIN n_li_d[125]
  DIRECTION INPUT ;
  USE SIGNAL ;
  PORT
   LAYER M4 ;
   RECT 112.236000 28.988000 112.320000 29.020000 ;
  END
 END n_li_d[125]
 PIN n_li_d[126]
  DIRECTION INPUT ;
  USE SIGNAL ;
  PORT
   LAYER M4 ;
   RECT 112.236000 29.180000 112.320000 29.212000 ;
  END
 END n_li_d[126]
 PIN n_li_d[127]
  DIRECTION INPUT ;
  USE SIGNAL ;
  PORT
   LAYER M4 ;
   RECT 112.236000 29.324000 112.320000 29.356000 ;
  END
 END n_li_d[127]
 PIN n_li_d[128]
  DIRECTION INPUT ;
  USE SIGNAL ;
  PORT
   LAYER M4 ;
   RECT 112.236000 29.516000 112.320000 29.548000 ;
  END
 END n_li_d[128]
 PIN n_li_d[129]
  DIRECTION INPUT ;
  USE SIGNAL ;
  PORT
   LAYER M4 ;
   RECT 112.236000 29.708000 112.320000 29.740000 ;
  END
 END n_li_d[129]
 PIN n_li_d[130]
  DIRECTION INPUT ;
  USE SIGNAL ;
  PORT
   LAYER M4 ;
   RECT 112.236000 29.900000 112.320000 29.932000 ;
  END
 END n_li_d[130]
 PIN n_li_d[131]
  DIRECTION INPUT ;
  USE SIGNAL ;
  PORT
   LAYER M4 ;
   RECT 112.236000 30.044000 112.320000 30.076000 ;
  END
 END n_li_d[131]
 PIN n_li_d[132]
  DIRECTION INPUT ;
  USE SIGNAL ;
  PORT
   LAYER M4 ;
   RECT 112.236000 30.236000 112.320000 30.268000 ;
  END
 END n_li_d[132]
 PIN n_li_d[133]
  DIRECTION INPUT ;
  USE SIGNAL ;
  PORT
   LAYER M4 ;
   RECT 112.236000 30.428000 112.320000 30.460000 ;
  END
 END n_li_d[133]
 PIN n_li_d[134]
  DIRECTION INPUT ;
  USE SIGNAL ;
  PORT
   LAYER M4 ;
   RECT 112.236000 30.620000 112.320000 30.652000 ;
  END
 END n_li_d[134]
 PIN n_li_d[135]
  DIRECTION INPUT ;
  USE SIGNAL ;
  PORT
   LAYER M4 ;
   RECT 112.236000 30.764000 112.320000 30.796000 ;
  END
 END n_li_d[135]
 PIN n_li_d[136]
  DIRECTION INPUT ;
  USE SIGNAL ;
  PORT
   LAYER M4 ;
   RECT 112.236000 30.956000 112.320000 30.988000 ;
  END
 END n_li_d[136]
 PIN n_li_d[137]
  DIRECTION INPUT ;
  USE SIGNAL ;
  PORT
   LAYER M4 ;
   RECT 112.236000 31.148000 112.320000 31.180000 ;
  END
 END n_li_d[137]
 PIN n_li_d[138]
  DIRECTION INPUT ;
  USE SIGNAL ;
  PORT
   LAYER M4 ;
   RECT 112.236000 31.292000 112.320000 31.324000 ;
  END
 END n_li_d[138]
 PIN n_li_d[139]
  DIRECTION INPUT ;
  USE SIGNAL ;
  PORT
   LAYER M4 ;
   RECT 112.236000 31.484000 112.320000 31.516000 ;
  END
 END n_li_d[139]
 PIN n_li_d[140]
  DIRECTION INPUT ;
  USE SIGNAL ;
  PORT
   LAYER M4 ;
   RECT 112.236000 31.676000 112.320000 31.708000 ;
  END
 END n_li_d[140]
 PIN n_li_d[141]
  DIRECTION INPUT ;
  USE SIGNAL ;
  PORT
   LAYER M4 ;
   RECT 112.236000 31.868000 112.320000 31.900000 ;
  END
 END n_li_d[141]
 PIN n_li_d[142]
  DIRECTION INPUT ;
  USE SIGNAL ;
  PORT
   LAYER M4 ;
   RECT 112.236000 32.012000 112.320000 32.044000 ;
  END
 END n_li_d[142]
 PIN n_li_d[143]
  DIRECTION INPUT ;
  USE SIGNAL ;
  PORT
   LAYER M4 ;
   RECT 112.236000 32.204000 112.320000 32.236000 ;
  END
 END n_li_d[143]
 PIN n_li_d[144]
  DIRECTION INPUT ;
  USE SIGNAL ;
  PORT
   LAYER M4 ;
   RECT 112.236000 32.396000 112.320000 32.428000 ;
  END
 END n_li_d[144]
 PIN n_li_d[145]
  DIRECTION INPUT ;
  USE SIGNAL ;
  PORT
   LAYER M4 ;
   RECT 112.236000 32.588000 112.320000 32.620000 ;
  END
 END n_li_d[145]
 PIN n_li_d[146]
  DIRECTION INPUT ;
  USE SIGNAL ;
  PORT
   LAYER M4 ;
   RECT 112.236000 32.732000 112.320000 32.764000 ;
  END
 END n_li_d[146]
 PIN n_li_d[147]
  DIRECTION INPUT ;
  USE SIGNAL ;
  PORT
   LAYER M4 ;
   RECT 112.236000 32.924000 112.320000 32.956000 ;
  END
 END n_li_d[147]
 PIN n_li_d[148]
  DIRECTION INPUT ;
  USE SIGNAL ;
  PORT
   LAYER M4 ;
   RECT 112.236000 33.116000 112.320000 33.148000 ;
  END
 END n_li_d[148]
 PIN n_li_d[149]
  DIRECTION INPUT ;
  USE SIGNAL ;
  PORT
   LAYER M4 ;
   RECT 112.236000 33.308000 112.320000 33.340000 ;
  END
 END n_li_d[149]
 PIN n_li_d[150]
  DIRECTION INPUT ;
  USE SIGNAL ;
  PORT
   LAYER M4 ;
   RECT 112.236000 33.452000 112.320000 33.484000 ;
  END
 END n_li_d[150]
 PIN n_li_d[151]
  DIRECTION INPUT ;
  USE SIGNAL ;
  PORT
   LAYER M4 ;
   RECT 112.236000 33.644000 112.320000 33.676000 ;
  END
 END n_li_d[151]
 PIN n_li_d[152]
  DIRECTION INPUT ;
  USE SIGNAL ;
  PORT
   LAYER M4 ;
   RECT 112.236000 33.836000 112.320000 33.868000 ;
  END
 END n_li_d[152]
 PIN n_li_d[153]
  DIRECTION INPUT ;
  USE SIGNAL ;
  PORT
   LAYER M4 ;
   RECT 112.236000 34.028000 112.320000 34.060000 ;
  END
 END n_li_d[153]
 PIN n_li_d[154]
  DIRECTION INPUT ;
  USE SIGNAL ;
  PORT
   LAYER M4 ;
   RECT 112.236000 34.172000 112.320000 34.204000 ;
  END
 END n_li_d[154]
 PIN n_li_d[155]
  DIRECTION INPUT ;
  USE SIGNAL ;
  PORT
   LAYER M4 ;
   RECT 112.236000 34.364000 112.320000 34.396000 ;
  END
 END n_li_d[155]
 PIN n_li_d[156]
  DIRECTION INPUT ;
  USE SIGNAL ;
  PORT
   LAYER M4 ;
   RECT 112.236000 34.556000 112.320000 34.588000 ;
  END
 END n_li_d[156]
 PIN n_li_d[157]
  DIRECTION INPUT ;
  USE SIGNAL ;
  PORT
   LAYER M4 ;
   RECT 112.236000 34.700000 112.320000 34.732000 ;
  END
 END n_li_d[157]
 PIN n_li_d[158]
  DIRECTION INPUT ;
  USE SIGNAL ;
  PORT
   LAYER M4 ;
   RECT 112.236000 34.892000 112.320000 34.924000 ;
  END
 END n_li_d[158]
 PIN n_li_d[159]
  DIRECTION INPUT ;
  USE SIGNAL ;
  PORT
   LAYER M4 ;
   RECT 112.236000 35.084000 112.320000 35.116000 ;
  END
 END n_li_d[159]
 PIN n_li_d[160]
  DIRECTION INPUT ;
  USE SIGNAL ;
  PORT
   LAYER M4 ;
   RECT 112.236000 35.276000 112.320000 35.308000 ;
  END
 END n_li_d[160]
 PIN n_li_d[161]
  DIRECTION INPUT ;
  USE SIGNAL ;
  PORT
   LAYER M4 ;
   RECT 112.236000 35.420000 112.320000 35.452000 ;
  END
 END n_li_d[161]
 PIN n_li_d[162]
  DIRECTION INPUT ;
  USE SIGNAL ;
  PORT
   LAYER M4 ;
   RECT 112.236000 35.612000 112.320000 35.644000 ;
  END
 END n_li_d[162]
 PIN n_li_d[163]
  DIRECTION INPUT ;
  USE SIGNAL ;
  PORT
   LAYER M4 ;
   RECT 112.236000 35.804000 112.320000 35.836000 ;
  END
 END n_li_d[163]
 PIN n_li_d[164]
  DIRECTION INPUT ;
  USE SIGNAL ;
  PORT
   LAYER M4 ;
   RECT 112.236000 35.996000 112.320000 36.028000 ;
  END
 END n_li_d[164]
 PIN n_li_d[165]
  DIRECTION INPUT ;
  USE SIGNAL ;
  PORT
   LAYER M4 ;
   RECT 112.236000 36.140000 112.320000 36.172000 ;
  END
 END n_li_d[165]
 PIN n_li_d[166]
  DIRECTION INPUT ;
  USE SIGNAL ;
  PORT
   LAYER M4 ;
   RECT 112.236000 36.332000 112.320000 36.364000 ;
  END
 END n_li_d[166]
 PIN n_li_d[167]
  DIRECTION INPUT ;
  USE SIGNAL ;
  PORT
   LAYER M4 ;
   RECT 112.236000 36.524000 112.320000 36.556000 ;
  END
 END n_li_d[167]
 PIN n_li_d[168]
  DIRECTION INPUT ;
  USE SIGNAL ;
  PORT
   LAYER M4 ;
   RECT 112.236000 36.716000 112.320000 36.748000 ;
  END
 END n_li_d[168]
 PIN n_li_d[169]
  DIRECTION INPUT ;
  USE SIGNAL ;
  PORT
   LAYER M4 ;
   RECT 112.236000 36.860000 112.320000 36.892000 ;
  END
 END n_li_d[169]
 PIN n_li_d[170]
  DIRECTION INPUT ;
  USE SIGNAL ;
  PORT
   LAYER M4 ;
   RECT 112.236000 37.052000 112.320000 37.084000 ;
  END
 END n_li_d[170]
 PIN n_li_d[171]
  DIRECTION INPUT ;
  USE SIGNAL ;
  PORT
   LAYER M4 ;
   RECT 112.236000 37.244000 112.320000 37.276000 ;
  END
 END n_li_d[171]
 PIN n_li_d[172]
  DIRECTION INPUT ;
  USE SIGNAL ;
  PORT
   LAYER M4 ;
   RECT 112.236000 37.388000 112.320000 37.420000 ;
  END
 END n_li_d[172]
 PIN n_li_d[173]
  DIRECTION INPUT ;
  USE SIGNAL ;
  PORT
   LAYER M4 ;
   RECT 112.236000 37.580000 112.320000 37.612000 ;
  END
 END n_li_d[173]
 PIN n_li_d[174]
  DIRECTION INPUT ;
  USE SIGNAL ;
  PORT
   LAYER M4 ;
   RECT 112.236000 37.772000 112.320000 37.804000 ;
  END
 END n_li_d[174]
 PIN n_li_d[175]
  DIRECTION INPUT ;
  USE SIGNAL ;
  PORT
   LAYER M4 ;
   RECT 112.236000 37.964000 112.320000 37.996000 ;
  END
 END n_li_d[175]
 PIN n_li_d[176]
  DIRECTION INPUT ;
  USE SIGNAL ;
  PORT
   LAYER M4 ;
   RECT 112.236000 38.108000 112.320000 38.140000 ;
  END
 END n_li_d[176]
 PIN n_li_d[177]
  DIRECTION INPUT ;
  USE SIGNAL ;
  PORT
   LAYER M4 ;
   RECT 112.236000 38.300000 112.320000 38.332000 ;
  END
 END n_li_d[177]
 PIN n_li_d[178]
  DIRECTION INPUT ;
  USE SIGNAL ;
  PORT
   LAYER M4 ;
   RECT 112.236000 38.492000 112.320000 38.524000 ;
  END
 END n_li_d[178]
 PIN n_li_d[179]
  DIRECTION INPUT ;
  USE SIGNAL ;
  PORT
   LAYER M4 ;
   RECT 112.236000 38.684000 112.320000 38.716000 ;
  END
 END n_li_d[179]
 PIN n_li_d[180]
  DIRECTION INPUT ;
  USE SIGNAL ;
  PORT
   LAYER M4 ;
   RECT 112.236000 38.828000 112.320000 38.860000 ;
  END
 END n_li_d[180]
 PIN n_li_d[181]
  DIRECTION INPUT ;
  USE SIGNAL ;
  PORT
   LAYER M4 ;
   RECT 112.236000 39.020000 112.320000 39.052000 ;
  END
 END n_li_d[181]
 PIN n_li_d[182]
  DIRECTION INPUT ;
  USE SIGNAL ;
  PORT
   LAYER M4 ;
   RECT 112.236000 39.212000 112.320000 39.244000 ;
  END
 END n_li_d[182]
 PIN n_li_d[183]
  DIRECTION INPUT ;
  USE SIGNAL ;
  PORT
   LAYER M4 ;
   RECT 112.236000 39.404000 112.320000 39.436000 ;
  END
 END n_li_d[183]
 PIN n_li_d[184]
  DIRECTION INPUT ;
  USE SIGNAL ;
  PORT
   LAYER M4 ;
   RECT 112.236000 39.548000 112.320000 39.580000 ;
  END
 END n_li_d[184]
 PIN n_li_d[185]
  DIRECTION INPUT ;
  USE SIGNAL ;
  PORT
   LAYER M4 ;
   RECT 112.236000 39.740000 112.320000 39.772000 ;
  END
 END n_li_d[185]
 PIN n_li_d[186]
  DIRECTION INPUT ;
  USE SIGNAL ;
  PORT
   LAYER M4 ;
   RECT 112.236000 39.932000 112.320000 39.964000 ;
  END
 END n_li_d[186]
 PIN n_li_d[187]
  DIRECTION INPUT ;
  USE SIGNAL ;
  PORT
   LAYER M4 ;
   RECT 112.236000 40.076000 112.320000 40.108000 ;
  END
 END n_li_d[187]
 PIN n_li_d[188]
  DIRECTION INPUT ;
  USE SIGNAL ;
  PORT
   LAYER M4 ;
   RECT 112.236000 40.268000 112.320000 40.300000 ;
  END
 END n_li_d[188]
 PIN n_li_d[189]
  DIRECTION INPUT ;
  USE SIGNAL ;
  PORT
   LAYER M4 ;
   RECT 112.236000 40.460000 112.320000 40.492000 ;
  END
 END n_li_d[189]
 PIN n_li_d[190]
  DIRECTION INPUT ;
  USE SIGNAL ;
  PORT
   LAYER M4 ;
   RECT 112.236000 40.652000 112.320000 40.684000 ;
  END
 END n_li_d[190]
 PIN n_li_d[191]
  DIRECTION INPUT ;
  USE SIGNAL ;
  PORT
   LAYER M4 ;
   RECT 112.236000 40.796000 112.320000 40.828000 ;
  END
 END n_li_d[191]
 PIN n_li_d[192]
  DIRECTION INPUT ;
  USE SIGNAL ;
  PORT
   LAYER M4 ;
   RECT 112.236000 40.988000 112.320000 41.020000 ;
  END
 END n_li_d[192]
 PIN n_li_d[193]
  DIRECTION INPUT ;
  USE SIGNAL ;
  PORT
   LAYER M4 ;
   RECT 112.236000 41.180000 112.320000 41.212000 ;
  END
 END n_li_d[193]
 PIN n_li_d[194]
  DIRECTION INPUT ;
  USE SIGNAL ;
  PORT
   LAYER M4 ;
   RECT 112.236000 41.372000 112.320000 41.404000 ;
  END
 END n_li_d[194]
 PIN n_li_d[195]
  DIRECTION INPUT ;
  USE SIGNAL ;
  PORT
   LAYER M4 ;
   RECT 112.236000 41.516000 112.320000 41.548000 ;
  END
 END n_li_d[195]
 PIN n_li_d[196]
  DIRECTION INPUT ;
  USE SIGNAL ;
  PORT
   LAYER M4 ;
   RECT 112.236000 41.708000 112.320000 41.740000 ;
  END
 END n_li_d[196]
 PIN n_li_d[197]
  DIRECTION INPUT ;
  USE SIGNAL ;
  PORT
   LAYER M4 ;
   RECT 112.236000 41.900000 112.320000 41.932000 ;
  END
 END n_li_d[197]
 PIN n_li_d[198]
  DIRECTION INPUT ;
  USE SIGNAL ;
  PORT
   LAYER M4 ;
   RECT 112.236000 42.092000 112.320000 42.124000 ;
  END
 END n_li_d[198]
 PIN n_li_d[199]
  DIRECTION INPUT ;
  USE SIGNAL ;
  PORT
   LAYER M4 ;
   RECT 112.236000 42.236000 112.320000 42.268000 ;
  END
 END n_li_d[199]
 PIN n_li_d[200]
  DIRECTION INPUT ;
  USE SIGNAL ;
  PORT
   LAYER M4 ;
   RECT 112.236000 42.428000 112.320000 42.460000 ;
  END
 END n_li_d[200]
 PIN n_li_d[201]
  DIRECTION INPUT ;
  USE SIGNAL ;
  PORT
   LAYER M4 ;
   RECT 112.236000 42.620000 112.320000 42.652000 ;
  END
 END n_li_d[201]
 PIN n_li_d[202]
  DIRECTION INPUT ;
  USE SIGNAL ;
  PORT
   LAYER M4 ;
   RECT 112.236000 42.812000 112.320000 42.844000 ;
  END
 END n_li_d[202]
 PIN n_li_d[203]
  DIRECTION INPUT ;
  USE SIGNAL ;
  PORT
   LAYER M4 ;
   RECT 112.236000 42.956000 112.320000 42.988000 ;
  END
 END n_li_d[203]
 PIN n_li_d[204]
  DIRECTION INPUT ;
  USE SIGNAL ;
  PORT
   LAYER M4 ;
   RECT 112.236000 43.148000 112.320000 43.180000 ;
  END
 END n_li_d[204]
 PIN n_li_d[205]
  DIRECTION INPUT ;
  USE SIGNAL ;
  PORT
   LAYER M4 ;
   RECT 112.236000 43.340000 112.320000 43.372000 ;
  END
 END n_li_d[205]
 PIN n_li_d[206]
  DIRECTION INPUT ;
  USE SIGNAL ;
  PORT
   LAYER M4 ;
   RECT 112.236000 43.484000 112.320000 43.516000 ;
  END
 END n_li_d[206]
 PIN n_li_d[207]
  DIRECTION INPUT ;
  USE SIGNAL ;
  PORT
   LAYER M4 ;
   RECT 112.236000 43.676000 112.320000 43.708000 ;
  END
 END n_li_d[207]
 PIN n_li_d[208]
  DIRECTION INPUT ;
  USE SIGNAL ;
  PORT
   LAYER M4 ;
   RECT 112.236000 43.868000 112.320000 43.900000 ;
  END
 END n_li_d[208]
 PIN n_li_d[209]
  DIRECTION INPUT ;
  USE SIGNAL ;
  PORT
   LAYER M4 ;
   RECT 112.236000 44.060000 112.320000 44.092000 ;
  END
 END n_li_d[209]
 PIN n_li_d[210]
  DIRECTION INPUT ;
  USE SIGNAL ;
  PORT
   LAYER M4 ;
   RECT 112.236000 44.204000 112.320000 44.236000 ;
  END
 END n_li_d[210]
 PIN n_li_d[211]
  DIRECTION INPUT ;
  USE SIGNAL ;
  PORT
   LAYER M4 ;
   RECT 112.236000 44.396000 112.320000 44.428000 ;
  END
 END n_li_d[211]
 PIN n_li_d[212]
  DIRECTION INPUT ;
  USE SIGNAL ;
  PORT
   LAYER M4 ;
   RECT 112.236000 44.588000 112.320000 44.620000 ;
  END
 END n_li_d[212]
 PIN n_li_d[213]
  DIRECTION INPUT ;
  USE SIGNAL ;
  PORT
   LAYER M4 ;
   RECT 112.236000 44.780000 112.320000 44.812000 ;
  END
 END n_li_d[213]
 PIN n_li_d[214]
  DIRECTION INPUT ;
  USE SIGNAL ;
  PORT
   LAYER M4 ;
   RECT 112.236000 44.924000 112.320000 44.956000 ;
  END
 END n_li_d[214]
 PIN n_li_d[215]
  DIRECTION INPUT ;
  USE SIGNAL ;
  PORT
   LAYER M4 ;
   RECT 112.236000 45.116000 112.320000 45.148000 ;
  END
 END n_li_d[215]
 PIN n_li_d[216]
  DIRECTION INPUT ;
  USE SIGNAL ;
  PORT
   LAYER M4 ;
   RECT 112.236000 45.308000 112.320000 45.340000 ;
  END
 END n_li_d[216]
 PIN n_li_d[217]
  DIRECTION INPUT ;
  USE SIGNAL ;
  PORT
   LAYER M4 ;
   RECT 112.236000 45.500000 112.320000 45.532000 ;
  END
 END n_li_d[217]
 PIN n_li_d[218]
  DIRECTION INPUT ;
  USE SIGNAL ;
  PORT
   LAYER M4 ;
   RECT 112.236000 45.644000 112.320000 45.676000 ;
  END
 END n_li_d[218]
 PIN n_li_d[219]
  DIRECTION INPUT ;
  USE SIGNAL ;
  PORT
   LAYER M4 ;
   RECT 112.236000 45.836000 112.320000 45.868000 ;
  END
 END n_li_d[219]
 PIN n_li_d[220]
  DIRECTION INPUT ;
  USE SIGNAL ;
  PORT
   LAYER M4 ;
   RECT 112.236000 46.028000 112.320000 46.060000 ;
  END
 END n_li_d[220]
 PIN n_li_d[221]
  DIRECTION INPUT ;
  USE SIGNAL ;
  PORT
   LAYER M4 ;
   RECT 112.236000 46.172000 112.320000 46.204000 ;
  END
 END n_li_d[221]
 PIN n_li_d[222]
  DIRECTION INPUT ;
  USE SIGNAL ;
  PORT
   LAYER M4 ;
   RECT 112.236000 46.364000 112.320000 46.396000 ;
  END
 END n_li_d[222]
 PIN n_li_d[223]
  DIRECTION INPUT ;
  USE SIGNAL ;
  PORT
   LAYER M4 ;
   RECT 112.236000 46.556000 112.320000 46.588000 ;
  END
 END n_li_d[223]
 PIN n_li_d[224]
  DIRECTION INPUT ;
  USE SIGNAL ;
  PORT
   LAYER M4 ;
   RECT 112.236000 46.748000 112.320000 46.780000 ;
  END
 END n_li_d[224]
 PIN n_li_d[225]
  DIRECTION INPUT ;
  USE SIGNAL ;
  PORT
   LAYER M4 ;
   RECT 112.236000 46.892000 112.320000 46.924000 ;
  END
 END n_li_d[225]
 PIN n_li_d[226]
  DIRECTION INPUT ;
  USE SIGNAL ;
  PORT
   LAYER M4 ;
   RECT 112.236000 47.084000 112.320000 47.116000 ;
  END
 END n_li_d[226]
 PIN n_li_d[227]
  DIRECTION INPUT ;
  USE SIGNAL ;
  PORT
   LAYER M4 ;
   RECT 112.236000 47.276000 112.320000 47.308000 ;
  END
 END n_li_d[227]
 PIN n_li_d[228]
  DIRECTION INPUT ;
  USE SIGNAL ;
  PORT
   LAYER M4 ;
   RECT 112.236000 47.468000 112.320000 47.500000 ;
  END
 END n_li_d[228]
 PIN n_li_d[229]
  DIRECTION INPUT ;
  USE SIGNAL ;
  PORT
   LAYER M4 ;
   RECT 112.236000 47.612000 112.320000 47.644000 ;
  END
 END n_li_d[229]
 PIN n_li_d[230]
  DIRECTION INPUT ;
  USE SIGNAL ;
  PORT
   LAYER M4 ;
   RECT 112.236000 47.804000 112.320000 47.836000 ;
  END
 END n_li_d[230]
 PIN n_li_d[231]
  DIRECTION INPUT ;
  USE SIGNAL ;
  PORT
   LAYER M4 ;
   RECT 112.236000 47.996000 112.320000 48.028000 ;
  END
 END n_li_d[231]
 PIN n_li_d[232]
  DIRECTION INPUT ;
  USE SIGNAL ;
  PORT
   LAYER M4 ;
   RECT 112.236000 48.188000 112.320000 48.220000 ;
  END
 END n_li_d[232]
 PIN n_li_d[233]
  DIRECTION INPUT ;
  USE SIGNAL ;
  PORT
   LAYER M4 ;
   RECT 112.236000 48.332000 112.320000 48.364000 ;
  END
 END n_li_d[233]
 PIN n_li_d[234]
  DIRECTION INPUT ;
  USE SIGNAL ;
  PORT
   LAYER M4 ;
   RECT 112.236000 48.524000 112.320000 48.556000 ;
  END
 END n_li_d[234]
 PIN n_li_d[235]
  DIRECTION INPUT ;
  USE SIGNAL ;
  PORT
   LAYER M4 ;
   RECT 112.236000 48.716000 112.320000 48.748000 ;
  END
 END n_li_d[235]
 PIN n_li_d[236]
  DIRECTION INPUT ;
  USE SIGNAL ;
  PORT
   LAYER M4 ;
   RECT 112.236000 48.860000 112.320000 48.892000 ;
  END
 END n_li_d[236]
 PIN n_li_d[237]
  DIRECTION INPUT ;
  USE SIGNAL ;
  PORT
   LAYER M4 ;
   RECT 112.236000 49.052000 112.320000 49.084000 ;
  END
 END n_li_d[237]
 PIN n_li_d[238]
  DIRECTION INPUT ;
  USE SIGNAL ;
  PORT
   LAYER M4 ;
   RECT 112.236000 49.244000 112.320000 49.276000 ;
  END
 END n_li_d[238]
 PIN n_li_d[239]
  DIRECTION INPUT ;
  USE SIGNAL ;
  PORT
   LAYER M4 ;
   RECT 112.236000 49.436000 112.320000 49.468000 ;
  END
 END n_li_d[239]
 PIN n_li_d[240]
  DIRECTION INPUT ;
  USE SIGNAL ;
  PORT
   LAYER M4 ;
   RECT 112.236000 49.580000 112.320000 49.612000 ;
  END
 END n_li_d[240]
 PIN n_li_d[241]
  DIRECTION INPUT ;
  USE SIGNAL ;
  PORT
   LAYER M4 ;
   RECT 112.236000 49.772000 112.320000 49.804000 ;
  END
 END n_li_d[241]
 PIN n_li_d[242]
  DIRECTION INPUT ;
  USE SIGNAL ;
  PORT
   LAYER M4 ;
   RECT 112.236000 49.964000 112.320000 49.996000 ;
  END
 END n_li_d[242]
 PIN n_li_d[243]
  DIRECTION INPUT ;
  USE SIGNAL ;
  PORT
   LAYER M4 ;
   RECT 112.236000 50.156000 112.320000 50.188000 ;
  END
 END n_li_d[243]
 PIN n_li_d[244]
  DIRECTION INPUT ;
  USE SIGNAL ;
  PORT
   LAYER M4 ;
   RECT 112.236000 50.300000 112.320000 50.332000 ;
  END
 END n_li_d[244]
 PIN n_li_d[245]
  DIRECTION INPUT ;
  USE SIGNAL ;
  PORT
   LAYER M4 ;
   RECT 112.236000 50.492000 112.320000 50.524000 ;
  END
 END n_li_d[245]
 PIN n_li_d[246]
  DIRECTION INPUT ;
  USE SIGNAL ;
  PORT
   LAYER M4 ;
   RECT 112.236000 50.684000 112.320000 50.716000 ;
  END
 END n_li_d[246]
 PIN n_li_d[247]
  DIRECTION INPUT ;
  USE SIGNAL ;
  PORT
   LAYER M4 ;
   RECT 112.236000 50.876000 112.320000 50.908000 ;
  END
 END n_li_d[247]
 PIN n_li_d[248]
  DIRECTION INPUT ;
  USE SIGNAL ;
  PORT
   LAYER M4 ;
   RECT 112.236000 51.020000 112.320000 51.052000 ;
  END
 END n_li_d[248]
 PIN n_li_d[249]
  DIRECTION INPUT ;
  USE SIGNAL ;
  PORT
   LAYER M4 ;
   RECT 112.236000 51.212000 112.320000 51.244000 ;
  END
 END n_li_d[249]
 PIN n_li_d[250]
  DIRECTION INPUT ;
  USE SIGNAL ;
  PORT
   LAYER M4 ;
   RECT 112.236000 51.404000 112.320000 51.436000 ;
  END
 END n_li_d[250]
 PIN n_li_d[251]
  DIRECTION INPUT ;
  USE SIGNAL ;
  PORT
   LAYER M4 ;
   RECT 112.236000 51.596000 112.320000 51.628000 ;
  END
 END n_li_d[251]
 PIN n_li_d[252]
  DIRECTION INPUT ;
  USE SIGNAL ;
  PORT
   LAYER M4 ;
   RECT 112.236000 51.740000 112.320000 51.772000 ;
  END
 END n_li_d[252]
 PIN n_li_d[253]
  DIRECTION INPUT ;
  USE SIGNAL ;
  PORT
   LAYER M4 ;
   RECT 112.236000 51.932000 112.320000 51.964000 ;
  END
 END n_li_d[253]
 PIN n_li_d[254]
  DIRECTION INPUT ;
  USE SIGNAL ;
  PORT
   LAYER M4 ;
   RECT 112.236000 52.124000 112.320000 52.156000 ;
  END
 END n_li_d[254]
 PIN n_li_d[255]
  DIRECTION INPUT ;
  USE SIGNAL ;
  PORT
   LAYER M4 ;
   RECT 112.236000 52.268000 112.320000 52.300000 ;
  END
 END n_li_d[255]
 PIN n_li_d[256]
  DIRECTION INPUT ;
  USE SIGNAL ;
  PORT
   LAYER M4 ;
   RECT 112.236000 52.460000 112.320000 52.492000 ;
  END
 END n_li_d[256]
 PIN n_li_d[257]
  DIRECTION INPUT ;
  USE SIGNAL ;
  PORT
   LAYER M4 ;
   RECT 112.236000 52.652000 112.320000 52.684000 ;
  END
 END n_li_d[257]
 PIN n_li_d[258]
  DIRECTION INPUT ;
  USE SIGNAL ;
  PORT
   LAYER M4 ;
   RECT 112.236000 52.844000 112.320000 52.876000 ;
  END
 END n_li_d[258]
 PIN n_li_d[259]
  DIRECTION INPUT ;
  USE SIGNAL ;
  PORT
   LAYER M4 ;
   RECT 112.236000 52.988000 112.320000 53.020000 ;
  END
 END n_li_d[259]
 PIN n_li_d[260]
  DIRECTION INPUT ;
  USE SIGNAL ;
  PORT
   LAYER M4 ;
   RECT 112.236000 53.180000 112.320000 53.212000 ;
  END
 END n_li_d[260]
 PIN n_li_d[261]
  DIRECTION INPUT ;
  USE SIGNAL ;
  PORT
   LAYER M4 ;
   RECT 112.236000 53.372000 112.320000 53.404000 ;
  END
 END n_li_d[261]
 PIN n_li_d[262]
  DIRECTION INPUT ;
  USE SIGNAL ;
  PORT
   LAYER M4 ;
   RECT 112.236000 53.564000 112.320000 53.596000 ;
  END
 END n_li_d[262]
 PIN n_li_d[263]
  DIRECTION INPUT ;
  USE SIGNAL ;
  PORT
   LAYER M4 ;
   RECT 112.236000 53.708000 112.320000 53.740000 ;
  END
 END n_li_d[263]
 PIN n_li_d[264]
  DIRECTION INPUT ;
  USE SIGNAL ;
  PORT
   LAYER M4 ;
   RECT 112.236000 53.900000 112.320000 53.932000 ;
  END
 END n_li_d[264]
 PIN n_li_d[265]
  DIRECTION INPUT ;
  USE SIGNAL ;
  PORT
   LAYER M4 ;
   RECT 112.236000 54.092000 112.320000 54.124000 ;
  END
 END n_li_d[265]
 PIN n_li_d[266]
  DIRECTION INPUT ;
  USE SIGNAL ;
  PORT
   LAYER M4 ;
   RECT 112.236000 54.284000 112.320000 54.316000 ;
  END
 END n_li_d[266]
 PIN n_li_d[267]
  DIRECTION INPUT ;
  USE SIGNAL ;
  PORT
   LAYER M4 ;
   RECT 112.236000 54.428000 112.320000 54.460000 ;
  END
 END n_li_d[267]
 PIN n_li_d[268]
  DIRECTION INPUT ;
  USE SIGNAL ;
  PORT
   LAYER M4 ;
   RECT 112.236000 54.620000 112.320000 54.652000 ;
  END
 END n_li_d[268]
 PIN n_li_d[269]
  DIRECTION INPUT ;
  USE SIGNAL ;
  PORT
   LAYER M4 ;
   RECT 112.236000 54.812000 112.320000 54.844000 ;
  END
 END n_li_d[269]
 PIN n_li_d[270]
  DIRECTION INPUT ;
  USE SIGNAL ;
  PORT
   LAYER M4 ;
   RECT 112.236000 54.956000 112.320000 54.988000 ;
  END
 END n_li_d[270]
 PIN n_li_d[271]
  DIRECTION INPUT ;
  USE SIGNAL ;
  PORT
   LAYER M4 ;
   RECT 112.236000 55.148000 112.320000 55.180000 ;
  END
 END n_li_d[271]
 PIN n_li_d[272]
  DIRECTION INPUT ;
  USE SIGNAL ;
  PORT
   LAYER M4 ;
   RECT 112.236000 55.340000 112.320000 55.372000 ;
  END
 END n_li_d[272]
 PIN n_li_d[273]
  DIRECTION INPUT ;
  USE SIGNAL ;
  PORT
   LAYER M4 ;
   RECT 112.236000 55.532000 112.320000 55.564000 ;
  END
 END n_li_d[273]
 PIN n_li_d[274]
  DIRECTION INPUT ;
  USE SIGNAL ;
  PORT
   LAYER M4 ;
   RECT 112.236000 55.676000 112.320000 55.708000 ;
  END
 END n_li_d[274]
 PIN n_li_d[275]
  DIRECTION INPUT ;
  USE SIGNAL ;
  PORT
   LAYER M4 ;
   RECT 112.236000 55.868000 112.320000 55.900000 ;
  END
 END n_li_d[275]
 PIN n_li_d[276]
  DIRECTION INPUT ;
  USE SIGNAL ;
  PORT
   LAYER M4 ;
   RECT 112.236000 56.060000 112.320000 56.092000 ;
  END
 END n_li_d[276]
 PIN n_li_d[277]
  DIRECTION INPUT ;
  USE SIGNAL ;
  PORT
   LAYER M4 ;
   RECT 112.236000 56.252000 112.320000 56.284000 ;
  END
 END n_li_d[277]
 PIN n_li_d[278]
  DIRECTION INPUT ;
  USE SIGNAL ;
  PORT
   LAYER M4 ;
   RECT 112.236000 56.396000 112.320000 56.428000 ;
  END
 END n_li_d[278]
 PIN n_li_d[279]
  DIRECTION INPUT ;
  USE SIGNAL ;
  PORT
   LAYER M4 ;
   RECT 112.236000 56.588000 112.320000 56.620000 ;
  END
 END n_li_d[279]
 PIN n_li_d[280]
  DIRECTION INPUT ;
  USE SIGNAL ;
  PORT
   LAYER M4 ;
   RECT 112.236000 56.780000 112.320000 56.812000 ;
  END
 END n_li_d[280]
 PIN n_li_d[281]
  DIRECTION INPUT ;
  USE SIGNAL ;
  PORT
   LAYER M4 ;
   RECT 112.236000 56.972000 112.320000 57.004000 ;
  END
 END n_li_d[281]
 PIN n_li_d[282]
  DIRECTION INPUT ;
  USE SIGNAL ;
  PORT
   LAYER M4 ;
   RECT 112.236000 57.116000 112.320000 57.148000 ;
  END
 END n_li_d[282]
 PIN n_li_d[283]
  DIRECTION INPUT ;
  USE SIGNAL ;
  PORT
   LAYER M4 ;
   RECT 112.236000 57.308000 112.320000 57.340000 ;
  END
 END n_li_d[283]
 PIN n_li_d[284]
  DIRECTION INPUT ;
  USE SIGNAL ;
  PORT
   LAYER M4 ;
   RECT 112.236000 57.500000 112.320000 57.532000 ;
  END
 END n_li_d[284]
 PIN n_li_d[285]
  DIRECTION INPUT ;
  USE SIGNAL ;
  PORT
   LAYER M4 ;
   RECT 112.236000 57.644000 112.320000 57.676000 ;
  END
 END n_li_d[285]
 PIN n_li_d[286]
  DIRECTION INPUT ;
  USE SIGNAL ;
  PORT
   LAYER M4 ;
   RECT 112.236000 57.836000 112.320000 57.868000 ;
  END
 END n_li_d[286]
 PIN n_li_d[287]
  DIRECTION INPUT ;
  USE SIGNAL ;
  PORT
   LAYER M4 ;
   RECT 112.236000 58.028000 112.320000 58.060000 ;
  END
 END n_li_d[287]
 PIN n_li_d[288]
  DIRECTION INPUT ;
  USE SIGNAL ;
  PORT
   LAYER M4 ;
   RECT 112.236000 58.220000 112.320000 58.252000 ;
  END
 END n_li_d[288]
 PIN n_li_d[289]
  DIRECTION INPUT ;
  USE SIGNAL ;
  PORT
   LAYER M4 ;
   RECT 112.236000 58.364000 112.320000 58.396000 ;
  END
 END n_li_d[289]
 PIN n_li_d[290]
  DIRECTION INPUT ;
  USE SIGNAL ;
  PORT
   LAYER M4 ;
   RECT 112.236000 58.556000 112.320000 58.588000 ;
  END
 END n_li_d[290]
 PIN n_li_d[291]
  DIRECTION INPUT ;
  USE SIGNAL ;
  PORT
   LAYER M4 ;
   RECT 112.236000 58.748000 112.320000 58.780000 ;
  END
 END n_li_d[291]
 PIN n_li_d[292]
  DIRECTION INPUT ;
  USE SIGNAL ;
  PORT
   LAYER M4 ;
   RECT 112.236000 58.940000 112.320000 58.972000 ;
  END
 END n_li_d[292]
 PIN n_li_d[293]
  DIRECTION INPUT ;
  USE SIGNAL ;
  PORT
   LAYER M4 ;
   RECT 112.236000 59.084000 112.320000 59.116000 ;
  END
 END n_li_d[293]
 PIN n_li_d[294]
  DIRECTION INPUT ;
  USE SIGNAL ;
  PORT
   LAYER M4 ;
   RECT 112.236000 59.276000 112.320000 59.308000 ;
  END
 END n_li_d[294]
 PIN n_li_d[295]
  DIRECTION INPUT ;
  USE SIGNAL ;
  PORT
   LAYER M4 ;
   RECT 112.236000 59.468000 112.320000 59.500000 ;
  END
 END n_li_d[295]
 PIN n_li_d[296]
  DIRECTION INPUT ;
  USE SIGNAL ;
  PORT
   LAYER M4 ;
   RECT 112.236000 59.660000 112.320000 59.692000 ;
  END
 END n_li_d[296]
 PIN n_li_d[297]
  DIRECTION INPUT ;
  USE SIGNAL ;
  PORT
   LAYER M4 ;
   RECT 112.236000 59.804000 112.320000 59.836000 ;
  END
 END n_li_d[297]
 PIN n_li_d[298]
  DIRECTION INPUT ;
  USE SIGNAL ;
  PORT
   LAYER M4 ;
   RECT 112.236000 59.996000 112.320000 60.028000 ;
  END
 END n_li_d[298]
 PIN n_li_d[299]
  DIRECTION INPUT ;
  USE SIGNAL ;
  PORT
   LAYER M4 ;
   RECT 112.236000 60.188000 112.320000 60.220000 ;
  END
 END n_li_d[299]
 PIN n_li_d[300]
  DIRECTION INPUT ;
  USE SIGNAL ;
  PORT
   LAYER M4 ;
   RECT 112.236000 60.380000 112.320000 60.412000 ;
  END
 END n_li_d[300]
 PIN n_li_d[301]
  DIRECTION INPUT ;
  USE SIGNAL ;
  PORT
   LAYER M4 ;
   RECT 112.236000 60.524000 112.320000 60.556000 ;
  END
 END n_li_d[301]
 PIN n_li_d[302]
  DIRECTION INPUT ;
  USE SIGNAL ;
  PORT
   LAYER M4 ;
   RECT 112.236000 60.716000 112.320000 60.748000 ;
  END
 END n_li_d[302]
 PIN n_li_d[303]
  DIRECTION INPUT ;
  USE SIGNAL ;
  PORT
   LAYER M4 ;
   RECT 112.236000 60.908000 112.320000 60.940000 ;
  END
 END n_li_d[303]
 PIN n_li_d[304]
  DIRECTION INPUT ;
  USE SIGNAL ;
  PORT
   LAYER M4 ;
   RECT 112.236000 61.052000 112.320000 61.084000 ;
  END
 END n_li_d[304]
 PIN n_li_d[305]
  DIRECTION INPUT ;
  USE SIGNAL ;
  PORT
   LAYER M4 ;
   RECT 112.236000 61.244000 112.320000 61.276000 ;
  END
 END n_li_d[305]
 PIN n_li_d[306]
  DIRECTION INPUT ;
  USE SIGNAL ;
  PORT
   LAYER M4 ;
   RECT 112.236000 61.436000 112.320000 61.468000 ;
  END
 END n_li_d[306]
 PIN n_li_d[307]
  DIRECTION INPUT ;
  USE SIGNAL ;
  PORT
   LAYER M4 ;
   RECT 112.236000 61.628000 112.320000 61.660000 ;
  END
 END n_li_d[307]
 PIN n_li_d[308]
  DIRECTION INPUT ;
  USE SIGNAL ;
  PORT
   LAYER M4 ;
   RECT 112.236000 61.772000 112.320000 61.804000 ;
  END
 END n_li_d[308]
 PIN n_li_d[309]
  DIRECTION INPUT ;
  USE SIGNAL ;
  PORT
   LAYER M4 ;
   RECT 112.236000 61.964000 112.320000 61.996000 ;
  END
 END n_li_d[309]
 PIN n_li_d[310]
  DIRECTION INPUT ;
  USE SIGNAL ;
  PORT
   LAYER M4 ;
   RECT 112.236000 62.156000 112.320000 62.188000 ;
  END
 END n_li_d[310]
 PIN n_li_d[311]
  DIRECTION INPUT ;
  USE SIGNAL ;
  PORT
   LAYER M4 ;
   RECT 112.236000 62.348000 112.320000 62.380000 ;
  END
 END n_li_d[311]
 PIN n_li_d[312]
  DIRECTION INPUT ;
  USE SIGNAL ;
  PORT
   LAYER M4 ;
   RECT 112.236000 62.492000 112.320000 62.524000 ;
  END
 END n_li_d[312]
 PIN n_li_d[313]
  DIRECTION INPUT ;
  USE SIGNAL ;
  PORT
   LAYER M4 ;
   RECT 112.236000 62.684000 112.320000 62.716000 ;
  END
 END n_li_d[313]
 PIN n_li_d[314]
  DIRECTION INPUT ;
  USE SIGNAL ;
  PORT
   LAYER M4 ;
   RECT 112.236000 62.876000 112.320000 62.908000 ;
  END
 END n_li_d[314]
 PIN n_li_d[315]
  DIRECTION INPUT ;
  USE SIGNAL ;
  PORT
   LAYER M4 ;
   RECT 112.236000 63.068000 112.320000 63.100000 ;
  END
 END n_li_d[315]
 PIN n_li_d[316]
  DIRECTION INPUT ;
  USE SIGNAL ;
  PORT
   LAYER M4 ;
   RECT 112.236000 63.212000 112.320000 63.244000 ;
  END
 END n_li_d[316]
 PIN n_li_d[317]
  DIRECTION INPUT ;
  USE SIGNAL ;
  PORT
   LAYER M4 ;
   RECT 112.236000 63.404000 112.320000 63.436000 ;
  END
 END n_li_d[317]
 PIN n_li_d[318]
  DIRECTION INPUT ;
  USE SIGNAL ;
  PORT
   LAYER M4 ;
   RECT 112.236000 63.596000 112.320000 63.628000 ;
  END
 END n_li_d[318]
 PIN n_li_d[319]
  DIRECTION INPUT ;
  USE SIGNAL ;
  PORT
   LAYER M4 ;
   RECT 112.236000 63.740000 112.320000 63.772000 ;
  END
 END n_li_d[319]
 PIN n_li_d[320]
  DIRECTION INPUT ;
  USE SIGNAL ;
  PORT
   LAYER M4 ;
   RECT 112.236000 63.932000 112.320000 63.964000 ;
  END
 END n_li_d[320]
 PIN n_li_d[321]
  DIRECTION INPUT ;
  USE SIGNAL ;
  PORT
   LAYER M4 ;
   RECT 112.236000 64.124000 112.320000 64.156000 ;
  END
 END n_li_d[321]
 PIN n_li_d[322]
  DIRECTION INPUT ;
  USE SIGNAL ;
  PORT
   LAYER M4 ;
   RECT 112.236000 64.316000 112.320000 64.348000 ;
  END
 END n_li_d[322]
 PIN n_li_d[323]
  DIRECTION INPUT ;
  USE SIGNAL ;
  PORT
   LAYER M4 ;
   RECT 112.236000 64.460000 112.320000 64.492000 ;
  END
 END n_li_d[323]
 PIN n_li_d[324]
  DIRECTION INPUT ;
  USE SIGNAL ;
  PORT
   LAYER M4 ;
   RECT 112.236000 64.652000 112.320000 64.684000 ;
  END
 END n_li_d[324]
 PIN n_li_d[325]
  DIRECTION INPUT ;
  USE SIGNAL ;
  PORT
   LAYER M4 ;
   RECT 112.236000 64.844000 112.320000 64.876000 ;
  END
 END n_li_d[325]
 PIN n_li_d[326]
  DIRECTION INPUT ;
  USE SIGNAL ;
  PORT
   LAYER M4 ;
   RECT 112.236000 65.036000 112.320000 65.068000 ;
  END
 END n_li_d[326]
 PIN n_li_d[327]
  DIRECTION INPUT ;
  USE SIGNAL ;
  PORT
   LAYER M4 ;
   RECT 112.236000 65.180000 112.320000 65.212000 ;
  END
 END n_li_d[327]
 PIN n_li_d[328]
  DIRECTION INPUT ;
  USE SIGNAL ;
  PORT
   LAYER M4 ;
   RECT 112.236000 65.372000 112.320000 65.404000 ;
  END
 END n_li_d[328]
 PIN n_li_d[329]
  DIRECTION INPUT ;
  USE SIGNAL ;
  PORT
   LAYER M4 ;
   RECT 112.236000 65.564000 112.320000 65.596000 ;
  END
 END n_li_d[329]
 PIN n_li_d[330]
  DIRECTION INPUT ;
  USE SIGNAL ;
  PORT
   LAYER M4 ;
   RECT 112.236000 65.756000 112.320000 65.788000 ;
  END
 END n_li_d[330]
 PIN n_li_d[331]
  DIRECTION INPUT ;
  USE SIGNAL ;
  PORT
   LAYER M4 ;
   RECT 112.236000 65.900000 112.320000 65.932000 ;
  END
 END n_li_d[331]
 PIN n_li_d[332]
  DIRECTION INPUT ;
  USE SIGNAL ;
  PORT
   LAYER M4 ;
   RECT 112.236000 66.092000 112.320000 66.124000 ;
  END
 END n_li_d[332]
 PIN n_li_d[333]
  DIRECTION INPUT ;
  USE SIGNAL ;
  PORT
   LAYER M4 ;
   RECT 112.236000 66.284000 112.320000 66.316000 ;
  END
 END n_li_d[333]
 PIN n_li_d[334]
  DIRECTION INPUT ;
  USE SIGNAL ;
  PORT
   LAYER M4 ;
   RECT 112.236000 66.428000 112.320000 66.460000 ;
  END
 END n_li_d[334]
 PIN n_li_d[335]
  DIRECTION INPUT ;
  USE SIGNAL ;
  PORT
   LAYER M4 ;
   RECT 112.236000 66.620000 112.320000 66.652000 ;
  END
 END n_li_d[335]
 PIN n_li_d[336]
  DIRECTION INPUT ;
  USE SIGNAL ;
  PORT
   LAYER M4 ;
   RECT 112.236000 66.812000 112.320000 66.844000 ;
  END
 END n_li_d[336]
 PIN n_li_d[337]
  DIRECTION INPUT ;
  USE SIGNAL ;
  PORT
   LAYER M4 ;
   RECT 112.236000 67.004000 112.320000 67.036000 ;
  END
 END n_li_d[337]
 PIN n_li_d[338]
  DIRECTION INPUT ;
  USE SIGNAL ;
  PORT
   LAYER M4 ;
   RECT 112.236000 67.148000 112.320000 67.180000 ;
  END
 END n_li_d[338]
 PIN n_li_d[339]
  DIRECTION INPUT ;
  USE SIGNAL ;
  PORT
   LAYER M4 ;
   RECT 112.236000 67.340000 112.320000 67.372000 ;
  END
 END n_li_d[339]
 PIN n_li_d[340]
  DIRECTION INPUT ;
  USE SIGNAL ;
  PORT
   LAYER M4 ;
   RECT 112.236000 67.532000 112.320000 67.564000 ;
  END
 END n_li_d[340]
 PIN n_li_d[341]
  DIRECTION INPUT ;
  USE SIGNAL ;
  PORT
   LAYER M4 ;
   RECT 112.236000 67.724000 112.320000 67.756000 ;
  END
 END n_li_d[341]
 PIN n_li_d[342]
  DIRECTION INPUT ;
  USE SIGNAL ;
  PORT
   LAYER M4 ;
   RECT 112.236000 67.868000 112.320000 67.900000 ;
  END
 END n_li_d[342]
 PIN n_li_d[343]
  DIRECTION INPUT ;
  USE SIGNAL ;
  PORT
   LAYER M4 ;
   RECT 112.236000 68.060000 112.320000 68.092000 ;
  END
 END n_li_d[343]
 PIN n_li_d[344]
  DIRECTION INPUT ;
  USE SIGNAL ;
  PORT
   LAYER M4 ;
   RECT 112.236000 68.252000 112.320000 68.284000 ;
  END
 END n_li_d[344]
 PIN n_li_d[345]
  DIRECTION INPUT ;
  USE SIGNAL ;
  PORT
   LAYER M4 ;
   RECT 112.236000 68.444000 112.320000 68.476000 ;
  END
 END n_li_d[345]
 PIN n_li_d[346]
  DIRECTION INPUT ;
  USE SIGNAL ;
  PORT
   LAYER M4 ;
   RECT 112.236000 68.588000 112.320000 68.620000 ;
  END
 END n_li_d[346]
 PIN n_li_d[347]
  DIRECTION INPUT ;
  USE SIGNAL ;
  PORT
   LAYER M4 ;
   RECT 112.236000 68.780000 112.320000 68.812000 ;
  END
 END n_li_d[347]
 PIN n_li_d[348]
  DIRECTION INPUT ;
  USE SIGNAL ;
  PORT
   LAYER M4 ;
   RECT 112.236000 68.972000 112.320000 69.004000 ;
  END
 END n_li_d[348]
 PIN n_li_d[349]
  DIRECTION INPUT ;
  USE SIGNAL ;
  PORT
   LAYER M4 ;
   RECT 112.236000 69.164000 112.320000 69.196000 ;
  END
 END n_li_d[349]
 PIN n_li_d[350]
  DIRECTION INPUT ;
  USE SIGNAL ;
  PORT
   LAYER M4 ;
   RECT 112.236000 69.308000 112.320000 69.340000 ;
  END
 END n_li_d[350]
 PIN n_li_d[351]
  DIRECTION INPUT ;
  USE SIGNAL ;
  PORT
   LAYER M4 ;
   RECT 112.236000 69.500000 112.320000 69.532000 ;
  END
 END n_li_d[351]
 PIN n_li_d[352]
  DIRECTION INPUT ;
  USE SIGNAL ;
  PORT
   LAYER M4 ;
   RECT 112.236000 69.692000 112.320000 69.724000 ;
  END
 END n_li_d[352]
 PIN n_li_d[353]
  DIRECTION INPUT ;
  USE SIGNAL ;
  PORT
   LAYER M4 ;
   RECT 112.236000 69.836000 112.320000 69.868000 ;
  END
 END n_li_d[353]
 PIN n_li_d[354]
  DIRECTION INPUT ;
  USE SIGNAL ;
  PORT
   LAYER M4 ;
   RECT 112.236000 70.028000 112.320000 70.060000 ;
  END
 END n_li_d[354]
 PIN n_li_d[355]
  DIRECTION INPUT ;
  USE SIGNAL ;
  PORT
   LAYER M4 ;
   RECT 112.236000 70.220000 112.320000 70.252000 ;
  END
 END n_li_d[355]
 PIN n_li_d[356]
  DIRECTION INPUT ;
  USE SIGNAL ;
  PORT
   LAYER M4 ;
   RECT 112.236000 70.412000 112.320000 70.444000 ;
  END
 END n_li_d[356]
 PIN n_li_d[357]
  DIRECTION INPUT ;
  USE SIGNAL ;
  PORT
   LAYER M4 ;
   RECT 112.236000 70.556000 112.320000 70.588000 ;
  END
 END n_li_d[357]
 PIN n_li_d[358]
  DIRECTION INPUT ;
  USE SIGNAL ;
  PORT
   LAYER M4 ;
   RECT 112.236000 70.748000 112.320000 70.780000 ;
  END
 END n_li_d[358]
 PIN n_li_d[359]
  DIRECTION INPUT ;
  USE SIGNAL ;
  PORT
   LAYER M4 ;
   RECT 112.236000 70.940000 112.320000 70.972000 ;
  END
 END n_li_d[359]
 PIN n_li_d[360]
  DIRECTION INPUT ;
  USE SIGNAL ;
  PORT
   LAYER M4 ;
   RECT 112.236000 71.132000 112.320000 71.164000 ;
  END
 END n_li_d[360]
 PIN n_li_d[361]
  DIRECTION INPUT ;
  USE SIGNAL ;
  PORT
   LAYER M4 ;
   RECT 112.236000 71.276000 112.320000 71.308000 ;
  END
 END n_li_d[361]
 PIN n_li_d[362]
  DIRECTION INPUT ;
  USE SIGNAL ;
  PORT
   LAYER M4 ;
   RECT 112.236000 71.468000 112.320000 71.500000 ;
  END
 END n_li_d[362]
 PIN n_li_d[363]
  DIRECTION INPUT ;
  USE SIGNAL ;
  PORT
   LAYER M4 ;
   RECT 112.236000 71.660000 112.320000 71.692000 ;
  END
 END n_li_d[363]
 PIN n_li_d[364]
  DIRECTION INPUT ;
  USE SIGNAL ;
  PORT
   LAYER M4 ;
   RECT 112.236000 71.852000 112.320000 71.884000 ;
  END
 END n_li_d[364]
 PIN n_li_d[365]
  DIRECTION INPUT ;
  USE SIGNAL ;
  PORT
   LAYER M4 ;
   RECT 112.236000 71.996000 112.320000 72.028000 ;
  END
 END n_li_d[365]
 PIN n_li_d[366]
  DIRECTION INPUT ;
  USE SIGNAL ;
  PORT
   LAYER M4 ;
   RECT 112.236000 72.188000 112.320000 72.220000 ;
  END
 END n_li_d[366]
 PIN n_li_d[367]
  DIRECTION INPUT ;
  USE SIGNAL ;
  PORT
   LAYER M4 ;
   RECT 112.236000 72.380000 112.320000 72.412000 ;
  END
 END n_li_d[367]
 PIN n_li_d[368]
  DIRECTION INPUT ;
  USE SIGNAL ;
  PORT
   LAYER M4 ;
   RECT 112.236000 72.524000 112.320000 72.556000 ;
  END
 END n_li_d[368]
 PIN n_li_d[369]
  DIRECTION INPUT ;
  USE SIGNAL ;
  PORT
   LAYER M4 ;
   RECT 112.236000 72.716000 112.320000 72.748000 ;
  END
 END n_li_d[369]
 PIN n_li_d[370]
  DIRECTION INPUT ;
  USE SIGNAL ;
  PORT
   LAYER M4 ;
   RECT 112.236000 72.908000 112.320000 72.940000 ;
  END
 END n_li_d[370]
 PIN n_li_d[371]
  DIRECTION INPUT ;
  USE SIGNAL ;
  PORT
   LAYER M4 ;
   RECT 112.236000 73.100000 112.320000 73.132000 ;
  END
 END n_li_d[371]
 PIN n_li_d[372]
  DIRECTION INPUT ;
  USE SIGNAL ;
  PORT
   LAYER M4 ;
   RECT 112.236000 73.244000 112.320000 73.276000 ;
  END
 END n_li_d[372]
 PIN n_li_d[373]
  DIRECTION INPUT ;
  USE SIGNAL ;
  PORT
   LAYER M4 ;
   RECT 112.236000 73.436000 112.320000 73.468000 ;
  END
 END n_li_d[373]
 PIN n_li_d[374]
  DIRECTION INPUT ;
  USE SIGNAL ;
  PORT
   LAYER M4 ;
   RECT 112.236000 73.628000 112.320000 73.660000 ;
  END
 END n_li_d[374]
 PIN n_li_d[375]
  DIRECTION INPUT ;
  USE SIGNAL ;
  PORT
   LAYER M4 ;
   RECT 112.236000 73.820000 112.320000 73.852000 ;
  END
 END n_li_d[375]
 PIN n_li_d[376]
  DIRECTION INPUT ;
  USE SIGNAL ;
  PORT
   LAYER M4 ;
   RECT 112.236000 73.964000 112.320000 73.996000 ;
  END
 END n_li_d[376]
 PIN n_li_d[377]
  DIRECTION INPUT ;
  USE SIGNAL ;
  PORT
   LAYER M4 ;
   RECT 112.236000 74.156000 112.320000 74.188000 ;
  END
 END n_li_d[377]
 PIN n_li_d[378]
  DIRECTION INPUT ;
  USE SIGNAL ;
  PORT
   LAYER M4 ;
   RECT 112.236000 74.348000 112.320000 74.380000 ;
  END
 END n_li_d[378]
 PIN n_li_d[379]
  DIRECTION INPUT ;
  USE SIGNAL ;
  PORT
   LAYER M4 ;
   RECT 112.236000 74.540000 112.320000 74.572000 ;
  END
 END n_li_d[379]
 PIN n_li_d[380]
  DIRECTION INPUT ;
  USE SIGNAL ;
  PORT
   LAYER M4 ;
   RECT 112.236000 74.684000 112.320000 74.716000 ;
  END
 END n_li_d[380]
 PIN n_li_d[381]
  DIRECTION INPUT ;
  USE SIGNAL ;
  PORT
   LAYER M4 ;
   RECT 112.236000 74.876000 112.320000 74.908000 ;
  END
 END n_li_d[381]
 PIN n_li_d[382]
  DIRECTION INPUT ;
  USE SIGNAL ;
  PORT
   LAYER M4 ;
   RECT 112.236000 75.068000 112.320000 75.100000 ;
  END
 END n_li_d[382]
 PIN n_li_d[383]
  DIRECTION INPUT ;
  USE SIGNAL ;
  PORT
   LAYER M4 ;
   RECT 112.236000 75.260000 112.320000 75.292000 ;
  END
 END n_li_d[383]
 PIN n_li_d[384]
  DIRECTION INPUT ;
  USE SIGNAL ;
  PORT
   LAYER M4 ;
   RECT 112.236000 75.404000 112.320000 75.436000 ;
  END
 END n_li_d[384]
 PIN n_li_d[385]
  DIRECTION INPUT ;
  USE SIGNAL ;
  PORT
   LAYER M4 ;
   RECT 112.236000 75.596000 112.320000 75.628000 ;
  END
 END n_li_d[385]
 PIN n_li_d[386]
  DIRECTION INPUT ;
  USE SIGNAL ;
  PORT
   LAYER M4 ;
   RECT 112.236000 75.788000 112.320000 75.820000 ;
  END
 END n_li_d[386]
 PIN n_li_d[387]
  DIRECTION INPUT ;
  USE SIGNAL ;
  PORT
   LAYER M4 ;
   RECT 112.236000 75.932000 112.320000 75.964000 ;
  END
 END n_li_d[387]
 PIN n_li_d[388]
  DIRECTION INPUT ;
  USE SIGNAL ;
  PORT
   LAYER M4 ;
   RECT 112.236000 76.124000 112.320000 76.156000 ;
  END
 END n_li_d[388]
 PIN n_li_d[389]
  DIRECTION INPUT ;
  USE SIGNAL ;
  PORT
   LAYER M4 ;
   RECT 112.236000 76.316000 112.320000 76.348000 ;
  END
 END n_li_d[389]
 PIN n_li_d[390]
  DIRECTION INPUT ;
  USE SIGNAL ;
  PORT
   LAYER M4 ;
   RECT 112.236000 76.508000 112.320000 76.540000 ;
  END
 END n_li_d[390]
 PIN n_li_d[391]
  DIRECTION INPUT ;
  USE SIGNAL ;
  PORT
   LAYER M4 ;
   RECT 112.236000 76.652000 112.320000 76.684000 ;
  END
 END n_li_d[391]
 PIN n_li_d[392]
  DIRECTION INPUT ;
  USE SIGNAL ;
  PORT
   LAYER M4 ;
   RECT 112.236000 76.844000 112.320000 76.876000 ;
  END
 END n_li_d[392]
 PIN n_li_d[393]
  DIRECTION INPUT ;
  USE SIGNAL ;
  PORT
   LAYER M4 ;
   RECT 112.236000 77.036000 112.320000 77.068000 ;
  END
 END n_li_d[393]
 PIN n_li_d[394]
  DIRECTION INPUT ;
  USE SIGNAL ;
  PORT
   LAYER M4 ;
   RECT 112.236000 77.228000 112.320000 77.260000 ;
  END
 END n_li_d[394]
 PIN n_li_d[395]
  DIRECTION INPUT ;
  USE SIGNAL ;
  PORT
   LAYER M4 ;
   RECT 112.236000 77.372000 112.320000 77.404000 ;
  END
 END n_li_d[395]
 PIN n_li_d[396]
  DIRECTION INPUT ;
  USE SIGNAL ;
  PORT
   LAYER M4 ;
   RECT 112.236000 77.564000 112.320000 77.596000 ;
  END
 END n_li_d[396]
 PIN n_li_d[397]
  DIRECTION INPUT ;
  USE SIGNAL ;
  PORT
   LAYER M4 ;
   RECT 112.236000 77.756000 112.320000 77.788000 ;
  END
 END n_li_d[397]
 PIN n_li_d[398]
  DIRECTION INPUT ;
  USE SIGNAL ;
  PORT
   LAYER M4 ;
   RECT 112.236000 77.948000 112.320000 77.980000 ;
  END
 END n_li_d[398]
 PIN n_li_d[399]
  DIRECTION INPUT ;
  USE SIGNAL ;
  PORT
   LAYER M4 ;
   RECT 112.236000 78.092000 112.320000 78.124000 ;
  END
 END n_li_d[399]
 PIN n_li_d[400]
  DIRECTION INPUT ;
  USE SIGNAL ;
  PORT
   LAYER M4 ;
   RECT 112.236000 78.284000 112.320000 78.316000 ;
  END
 END n_li_d[400]
 PIN n_li_d[401]
  DIRECTION INPUT ;
  USE SIGNAL ;
  PORT
   LAYER M4 ;
   RECT 112.236000 78.476000 112.320000 78.508000 ;
  END
 END n_li_d[401]
 PIN n_li_d[402]
  DIRECTION INPUT ;
  USE SIGNAL ;
  PORT
   LAYER M4 ;
   RECT 112.236000 78.620000 112.320000 78.652000 ;
  END
 END n_li_d[402]
 PIN n_li_d[403]
  DIRECTION INPUT ;
  USE SIGNAL ;
  PORT
   LAYER M4 ;
   RECT 112.236000 78.812000 112.320000 78.844000 ;
  END
 END n_li_d[403]
 PIN n_li_d[404]
  DIRECTION INPUT ;
  USE SIGNAL ;
  PORT
   LAYER M4 ;
   RECT 112.236000 79.004000 112.320000 79.036000 ;
  END
 END n_li_d[404]
 PIN n_li_d[405]
  DIRECTION INPUT ;
  USE SIGNAL ;
  PORT
   LAYER M4 ;
   RECT 112.236000 79.196000 112.320000 79.228000 ;
  END
 END n_li_d[405]
 PIN n_li_d[406]
  DIRECTION INPUT ;
  USE SIGNAL ;
  PORT
   LAYER M4 ;
   RECT 112.236000 79.340000 112.320000 79.372000 ;
  END
 END n_li_d[406]
 PIN n_li_d[407]
  DIRECTION INPUT ;
  USE SIGNAL ;
  PORT
   LAYER M4 ;
   RECT 112.236000 79.532000 112.320000 79.564000 ;
  END
 END n_li_d[407]
 PIN n_li_d[408]
  DIRECTION INPUT ;
  USE SIGNAL ;
  PORT
   LAYER M4 ;
   RECT 112.236000 79.724000 112.320000 79.756000 ;
  END
 END n_li_d[408]
 PIN n_li_d[409]
  DIRECTION INPUT ;
  USE SIGNAL ;
  PORT
   LAYER M4 ;
   RECT 112.236000 79.916000 112.320000 79.948000 ;
  END
 END n_li_d[409]
 PIN n_li_d[410]
  DIRECTION INPUT ;
  USE SIGNAL ;
  PORT
   LAYER M4 ;
   RECT 112.236000 80.060000 112.320000 80.092000 ;
  END
 END n_li_d[410]
 PIN n_li_d[411]
  DIRECTION INPUT ;
  USE SIGNAL ;
  PORT
   LAYER M4 ;
   RECT 112.236000 80.252000 112.320000 80.284000 ;
  END
 END n_li_d[411]
 PIN n_li_d[412]
  DIRECTION INPUT ;
  USE SIGNAL ;
  PORT
   LAYER M4 ;
   RECT 112.236000 80.444000 112.320000 80.476000 ;
  END
 END n_li_d[412]
 PIN n_li_d[413]
  DIRECTION INPUT ;
  USE SIGNAL ;
  PORT
   LAYER M4 ;
   RECT 112.236000 80.636000 112.320000 80.668000 ;
  END
 END n_li_d[413]
 PIN n_li_d[414]
  DIRECTION INPUT ;
  USE SIGNAL ;
  PORT
   LAYER M4 ;
   RECT 112.236000 80.780000 112.320000 80.812000 ;
  END
 END n_li_d[414]
 PIN n_li_d[415]
  DIRECTION INPUT ;
  USE SIGNAL ;
  PORT
   LAYER M4 ;
   RECT 112.236000 80.972000 112.320000 81.004000 ;
  END
 END n_li_d[415]
 PIN n_li_d[416]
  DIRECTION INPUT ;
  USE SIGNAL ;
  PORT
   LAYER M4 ;
   RECT 112.236000 81.164000 112.320000 81.196000 ;
  END
 END n_li_d[416]
 PIN n_li_d[417]
  DIRECTION INPUT ;
  USE SIGNAL ;
  PORT
   LAYER M4 ;
   RECT 112.236000 81.308000 112.320000 81.340000 ;
  END
 END n_li_d[417]
 PIN n_li_d[418]
  DIRECTION INPUT ;
  USE SIGNAL ;
  PORT
   LAYER M4 ;
   RECT 112.236000 81.500000 112.320000 81.532000 ;
  END
 END n_li_d[418]
 PIN n_li_d[419]
  DIRECTION INPUT ;
  USE SIGNAL ;
  PORT
   LAYER M4 ;
   RECT 112.236000 81.692000 112.320000 81.724000 ;
  END
 END n_li_d[419]
 PIN n_li_d[420]
  DIRECTION INPUT ;
  USE SIGNAL ;
  PORT
   LAYER M4 ;
   RECT 112.236000 81.884000 112.320000 81.916000 ;
  END
 END n_li_d[420]
 PIN n_li_d[421]
  DIRECTION INPUT ;
  USE SIGNAL ;
  PORT
   LAYER M4 ;
   RECT 112.236000 82.028000 112.320000 82.060000 ;
  END
 END n_li_d[421]
 PIN n_li_d[422]
  DIRECTION INPUT ;
  USE SIGNAL ;
  PORT
   LAYER M4 ;
   RECT 112.236000 82.220000 112.320000 82.252000 ;
  END
 END n_li_d[422]
 PIN n_li_d[423]
  DIRECTION INPUT ;
  USE SIGNAL ;
  PORT
   LAYER M4 ;
   RECT 112.236000 82.412000 112.320000 82.444000 ;
  END
 END n_li_d[423]
 PIN n_li_d[424]
  DIRECTION INPUT ;
  USE SIGNAL ;
  PORT
   LAYER M4 ;
   RECT 112.236000 82.604000 112.320000 82.636000 ;
  END
 END n_li_d[424]
 PIN n_li_d[425]
  DIRECTION INPUT ;
  USE SIGNAL ;
  PORT
   LAYER M4 ;
   RECT 112.236000 82.748000 112.320000 82.780000 ;
  END
 END n_li_d[425]
 PIN n_li_d[426]
  DIRECTION INPUT ;
  USE SIGNAL ;
  PORT
   LAYER M4 ;
   RECT 112.236000 82.940000 112.320000 82.972000 ;
  END
 END n_li_d[426]
 PIN n_li_d[427]
  DIRECTION INPUT ;
  USE SIGNAL ;
  PORT
   LAYER M4 ;
   RECT 112.236000 83.132000 112.320000 83.164000 ;
  END
 END n_li_d[427]
 PIN n_li_d[428]
  DIRECTION INPUT ;
  USE SIGNAL ;
  PORT
   LAYER M4 ;
   RECT 112.236000 83.324000 112.320000 83.356000 ;
  END
 END n_li_d[428]
 PIN n_li_d[429]
  DIRECTION INPUT ;
  USE SIGNAL ;
  PORT
   LAYER M4 ;
   RECT 112.236000 83.468000 112.320000 83.500000 ;
  END
 END n_li_d[429]
 PIN n_li_d[430]
  DIRECTION INPUT ;
  USE SIGNAL ;
  PORT
   LAYER M4 ;
   RECT 112.236000 83.660000 112.320000 83.692000 ;
  END
 END n_li_d[430]
 PIN n_li_d[431]
  DIRECTION INPUT ;
  USE SIGNAL ;
  PORT
   LAYER M4 ;
   RECT 112.236000 83.852000 112.320000 83.884000 ;
  END
 END n_li_d[431]
 PIN n_li_d[432]
  DIRECTION INPUT ;
  USE SIGNAL ;
  PORT
   LAYER M4 ;
   RECT 112.236000 84.044000 112.320000 84.076000 ;
  END
 END n_li_d[432]
 PIN n_li_d[433]
  DIRECTION INPUT ;
  USE SIGNAL ;
  PORT
   LAYER M4 ;
   RECT 112.236000 84.188000 112.320000 84.220000 ;
  END
 END n_li_d[433]
 PIN n_li_d[434]
  DIRECTION INPUT ;
  USE SIGNAL ;
  PORT
   LAYER M4 ;
   RECT 112.236000 84.380000 112.320000 84.412000 ;
  END
 END n_li_d[434]
 PIN n_li_d[435]
  DIRECTION INPUT ;
  USE SIGNAL ;
  PORT
   LAYER M4 ;
   RECT 112.236000 84.572000 112.320000 84.604000 ;
  END
 END n_li_d[435]
 PIN n_li_d[436]
  DIRECTION INPUT ;
  USE SIGNAL ;
  PORT
   LAYER M4 ;
   RECT 112.236000 84.716000 112.320000 84.748000 ;
  END
 END n_li_d[436]
 PIN n_li_d[437]
  DIRECTION INPUT ;
  USE SIGNAL ;
  PORT
   LAYER M4 ;
   RECT 112.236000 84.908000 112.320000 84.940000 ;
  END
 END n_li_d[437]
 PIN n_li_d[438]
  DIRECTION INPUT ;
  USE SIGNAL ;
  PORT
   LAYER M4 ;
   RECT 112.236000 85.100000 112.320000 85.132000 ;
  END
 END n_li_d[438]
 PIN n_li_d[439]
  DIRECTION INPUT ;
  USE SIGNAL ;
  PORT
   LAYER M4 ;
   RECT 112.236000 85.292000 112.320000 85.324000 ;
  END
 END n_li_d[439]
 PIN n_li_d[440]
  DIRECTION INPUT ;
  USE SIGNAL ;
  PORT
   LAYER M4 ;
   RECT 112.236000 85.436000 112.320000 85.468000 ;
  END
 END n_li_d[440]
 PIN n_li_d[441]
  DIRECTION INPUT ;
  USE SIGNAL ;
  PORT
   LAYER M4 ;
   RECT 112.236000 85.628000 112.320000 85.660000 ;
  END
 END n_li_d[441]
 PIN n_li_d[442]
  DIRECTION INPUT ;
  USE SIGNAL ;
  PORT
   LAYER M4 ;
   RECT 112.236000 85.820000 112.320000 85.852000 ;
  END
 END n_li_d[442]
 PIN n_li_d[443]
  DIRECTION INPUT ;
  USE SIGNAL ;
  PORT
   LAYER M4 ;
   RECT 112.236000 86.012000 112.320000 86.044000 ;
  END
 END n_li_d[443]
 PIN n_li_d[444]
  DIRECTION INPUT ;
  USE SIGNAL ;
  PORT
   LAYER M4 ;
   RECT 112.236000 86.156000 112.320000 86.188000 ;
  END
 END n_li_d[444]
 PIN n_li_d[445]
  DIRECTION INPUT ;
  USE SIGNAL ;
  PORT
   LAYER M4 ;
   RECT 112.236000 86.348000 112.320000 86.380000 ;
  END
 END n_li_d[445]
 PIN n_li_d[446]
  DIRECTION INPUT ;
  USE SIGNAL ;
  PORT
   LAYER M4 ;
   RECT 112.236000 86.540000 112.320000 86.572000 ;
  END
 END n_li_d[446]
 PIN n_li_d[447]
  DIRECTION INPUT ;
  USE SIGNAL ;
  PORT
   LAYER M4 ;
   RECT 112.236000 86.732000 112.320000 86.764000 ;
  END
 END n_li_d[447]
 PIN n_li_d[448]
  DIRECTION INPUT ;
  USE SIGNAL ;
  PORT
   LAYER M4 ;
   RECT 112.236000 86.876000 112.320000 86.908000 ;
  END
 END n_li_d[448]
 PIN n_li_d[449]
  DIRECTION INPUT ;
  USE SIGNAL ;
  PORT
   LAYER M4 ;
   RECT 112.236000 87.068000 112.320000 87.100000 ;
  END
 END n_li_d[449]
 PIN n_li_d[450]
  DIRECTION INPUT ;
  USE SIGNAL ;
  PORT
   LAYER M4 ;
   RECT 112.236000 87.260000 112.320000 87.292000 ;
  END
 END n_li_d[450]
 PIN n_li_d[451]
  DIRECTION INPUT ;
  USE SIGNAL ;
  PORT
   LAYER M4 ;
   RECT 112.236000 87.404000 112.320000 87.436000 ;
  END
 END n_li_d[451]
 PIN n_li_d[452]
  DIRECTION INPUT ;
  USE SIGNAL ;
  PORT
   LAYER M4 ;
   RECT 112.236000 87.596000 112.320000 87.628000 ;
  END
 END n_li_d[452]
 PIN n_li_d[453]
  DIRECTION INPUT ;
  USE SIGNAL ;
  PORT
   LAYER M4 ;
   RECT 112.236000 87.788000 112.320000 87.820000 ;
  END
 END n_li_d[453]
 PIN n_li_d[454]
  DIRECTION INPUT ;
  USE SIGNAL ;
  PORT
   LAYER M4 ;
   RECT 112.236000 87.980000 112.320000 88.012000 ;
  END
 END n_li_d[454]
 PIN n_li_d[455]
  DIRECTION INPUT ;
  USE SIGNAL ;
  PORT
   LAYER M4 ;
   RECT 112.236000 88.124000 112.320000 88.156000 ;
  END
 END n_li_d[455]
 PIN n_li_d[456]
  DIRECTION INPUT ;
  USE SIGNAL ;
  PORT
   LAYER M4 ;
   RECT 112.236000 88.316000 112.320000 88.348000 ;
  END
 END n_li_d[456]
 PIN n_li_d[457]
  DIRECTION INPUT ;
  USE SIGNAL ;
  PORT
   LAYER M4 ;
   RECT 112.236000 88.508000 112.320000 88.540000 ;
  END
 END n_li_d[457]
 PIN n_li_d[458]
  DIRECTION INPUT ;
  USE SIGNAL ;
  PORT
   LAYER M4 ;
   RECT 112.236000 88.700000 112.320000 88.732000 ;
  END
 END n_li_d[458]
 PIN n_li_d[459]
  DIRECTION INPUT ;
  USE SIGNAL ;
  PORT
   LAYER M4 ;
   RECT 112.236000 88.844000 112.320000 88.876000 ;
  END
 END n_li_d[459]
 PIN n_li_d[460]
  DIRECTION INPUT ;
  USE SIGNAL ;
  PORT
   LAYER M4 ;
   RECT 112.236000 89.036000 112.320000 89.068000 ;
  END
 END n_li_d[460]
 PIN n_li_d[461]
  DIRECTION INPUT ;
  USE SIGNAL ;
  PORT
   LAYER M4 ;
   RECT 112.236000 89.228000 112.320000 89.260000 ;
  END
 END n_li_d[461]
 PIN n_li_d[462]
  DIRECTION INPUT ;
  USE SIGNAL ;
  PORT
   LAYER M4 ;
   RECT 112.236000 89.420000 112.320000 89.452000 ;
  END
 END n_li_d[462]
 PIN n_li_d[463]
  DIRECTION INPUT ;
  USE SIGNAL ;
  PORT
   LAYER M4 ;
   RECT 112.236000 89.564000 112.320000 89.596000 ;
  END
 END n_li_d[463]
 PIN n_li_d[464]
  DIRECTION INPUT ;
  USE SIGNAL ;
  PORT
   LAYER M4 ;
   RECT 112.236000 89.756000 112.320000 89.788000 ;
  END
 END n_li_d[464]
 PIN n_li_d[465]
  DIRECTION INPUT ;
  USE SIGNAL ;
  PORT
   LAYER M4 ;
   RECT 112.236000 89.948000 112.320000 89.980000 ;
  END
 END n_li_d[465]
 PIN n_li_d[466]
  DIRECTION INPUT ;
  USE SIGNAL ;
  PORT
   LAYER M4 ;
   RECT 112.236000 90.092000 112.320000 90.124000 ;
  END
 END n_li_d[466]
 PIN n_li_d[467]
  DIRECTION INPUT ;
  USE SIGNAL ;
  PORT
   LAYER M4 ;
   RECT 112.236000 90.284000 112.320000 90.316000 ;
  END
 END n_li_d[467]
 PIN n_li_d[468]
  DIRECTION INPUT ;
  USE SIGNAL ;
  PORT
   LAYER M4 ;
   RECT 112.236000 90.476000 112.320000 90.508000 ;
  END
 END n_li_d[468]
 PIN n_li_d[469]
  DIRECTION INPUT ;
  USE SIGNAL ;
  PORT
   LAYER M4 ;
   RECT 112.236000 90.668000 112.320000 90.700000 ;
  END
 END n_li_d[469]
 PIN n_li_d[470]
  DIRECTION INPUT ;
  USE SIGNAL ;
  PORT
   LAYER M4 ;
   RECT 112.236000 90.812000 112.320000 90.844000 ;
  END
 END n_li_d[470]
 PIN n_li_d[471]
  DIRECTION INPUT ;
  USE SIGNAL ;
  PORT
   LAYER M4 ;
   RECT 112.236000 91.004000 112.320000 91.036000 ;
  END
 END n_li_d[471]
 PIN n_li_d[472]
  DIRECTION INPUT ;
  USE SIGNAL ;
  PORT
   LAYER M4 ;
   RECT 112.236000 91.196000 112.320000 91.228000 ;
  END
 END n_li_d[472]
 PIN n_li_d[473]
  DIRECTION INPUT ;
  USE SIGNAL ;
  PORT
   LAYER M4 ;
   RECT 112.236000 91.388000 112.320000 91.420000 ;
  END
 END n_li_d[473]
 PIN n_li_d[474]
  DIRECTION INPUT ;
  USE SIGNAL ;
  PORT
   LAYER M4 ;
   RECT 112.236000 91.532000 112.320000 91.564000 ;
  END
 END n_li_d[474]
 PIN n_li_d[475]
  DIRECTION INPUT ;
  USE SIGNAL ;
  PORT
   LAYER M4 ;
   RECT 112.236000 91.724000 112.320000 91.756000 ;
  END
 END n_li_d[475]
 PIN n_li_d[476]
  DIRECTION INPUT ;
  USE SIGNAL ;
  PORT
   LAYER M4 ;
   RECT 112.236000 91.916000 112.320000 91.948000 ;
  END
 END n_li_d[476]
 PIN n_li_d[477]
  DIRECTION INPUT ;
  USE SIGNAL ;
  PORT
   LAYER M4 ;
   RECT 112.236000 92.108000 112.320000 92.140000 ;
  END
 END n_li_d[477]
 PIN n_li_d[478]
  DIRECTION INPUT ;
  USE SIGNAL ;
  PORT
   LAYER M4 ;
   RECT 112.236000 92.252000 112.320000 92.284000 ;
  END
 END n_li_d[478]
 PIN n_li_d[479]
  DIRECTION INPUT ;
  USE SIGNAL ;
  PORT
   LAYER M4 ;
   RECT 112.236000 92.444000 112.320000 92.476000 ;
  END
 END n_li_d[479]
 PIN n_li_d[480]
  DIRECTION INPUT ;
  USE SIGNAL ;
  PORT
   LAYER M4 ;
   RECT 112.236000 92.636000 112.320000 92.668000 ;
  END
 END n_li_d[480]
 PIN n_li_d[481]
  DIRECTION INPUT ;
  USE SIGNAL ;
  PORT
   LAYER M4 ;
   RECT 112.236000 92.828000 112.320000 92.860000 ;
  END
 END n_li_d[481]
 PIN n_li_d[482]
  DIRECTION INPUT ;
  USE SIGNAL ;
  PORT
   LAYER M4 ;
   RECT 112.236000 92.972000 112.320000 93.004000 ;
  END
 END n_li_d[482]
 PIN n_li_d[483]
  DIRECTION INPUT ;
  USE SIGNAL ;
  PORT
   LAYER M4 ;
   RECT 112.236000 93.164000 112.320000 93.196000 ;
  END
 END n_li_d[483]
 PIN n_li_d[484]
  DIRECTION INPUT ;
  USE SIGNAL ;
  PORT
   LAYER M4 ;
   RECT 112.236000 93.356000 112.320000 93.388000 ;
  END
 END n_li_d[484]
 PIN n_li_d[485]
  DIRECTION INPUT ;
  USE SIGNAL ;
  PORT
   LAYER M4 ;
   RECT 112.236000 93.500000 112.320000 93.532000 ;
  END
 END n_li_d[485]
 PIN n_li_d[486]
  DIRECTION INPUT ;
  USE SIGNAL ;
  PORT
   LAYER M4 ;
   RECT 112.236000 93.692000 112.320000 93.724000 ;
  END
 END n_li_d[486]
 PIN n_li_d[487]
  DIRECTION INPUT ;
  USE SIGNAL ;
  PORT
   LAYER M4 ;
   RECT 112.236000 93.884000 112.320000 93.916000 ;
  END
 END n_li_d[487]
 PIN n_li_d[488]
  DIRECTION INPUT ;
  USE SIGNAL ;
  PORT
   LAYER M4 ;
   RECT 112.236000 94.076000 112.320000 94.108000 ;
  END
 END n_li_d[488]
 PIN n_li_d[489]
  DIRECTION INPUT ;
  USE SIGNAL ;
  PORT
   LAYER M4 ;
   RECT 112.236000 94.220000 112.320000 94.252000 ;
  END
 END n_li_d[489]
 PIN n_li_d[490]
  DIRECTION INPUT ;
  USE SIGNAL ;
  PORT
   LAYER M4 ;
   RECT 112.236000 94.412000 112.320000 94.444000 ;
  END
 END n_li_d[490]
 PIN n_li_d[491]
  DIRECTION INPUT ;
  USE SIGNAL ;
  PORT
   LAYER M4 ;
   RECT 112.236000 94.604000 112.320000 94.636000 ;
  END
 END n_li_d[491]
 PIN n_li_d[492]
  DIRECTION INPUT ;
  USE SIGNAL ;
  PORT
   LAYER M4 ;
   RECT 112.236000 94.796000 112.320000 94.828000 ;
  END
 END n_li_d[492]
 PIN n_li_d[493]
  DIRECTION INPUT ;
  USE SIGNAL ;
  PORT
   LAYER M4 ;
   RECT 112.236000 94.940000 112.320000 94.972000 ;
  END
 END n_li_d[493]
 PIN n_li_d[494]
  DIRECTION INPUT ;
  USE SIGNAL ;
  PORT
   LAYER M4 ;
   RECT 112.236000 95.132000 112.320000 95.164000 ;
  END
 END n_li_d[494]
 PIN n_li_d[495]
  DIRECTION INPUT ;
  USE SIGNAL ;
  PORT
   LAYER M4 ;
   RECT 112.236000 95.324000 112.320000 95.356000 ;
  END
 END n_li_d[495]
 PIN n_li_d[496]
  DIRECTION INPUT ;
  USE SIGNAL ;
  PORT
   LAYER M4 ;
   RECT 112.236000 95.516000 112.320000 95.548000 ;
  END
 END n_li_d[496]
 PIN n_li_d[497]
  DIRECTION INPUT ;
  USE SIGNAL ;
  PORT
   LAYER M4 ;
   RECT 112.236000 95.660000 112.320000 95.692000 ;
  END
 END n_li_d[497]
 PIN n_li_d[498]
  DIRECTION INPUT ;
  USE SIGNAL ;
  PORT
   LAYER M4 ;
   RECT 112.236000 95.852000 112.320000 95.884000 ;
  END
 END n_li_d[498]
 PIN n_li_d[499]
  DIRECTION INPUT ;
  USE SIGNAL ;
  PORT
   LAYER M4 ;
   RECT 112.236000 96.044000 112.320000 96.076000 ;
  END
 END n_li_d[499]
 PIN n_li_d[500]
  DIRECTION INPUT ;
  USE SIGNAL ;
  PORT
   LAYER M4 ;
   RECT 112.236000 96.188000 112.320000 96.220000 ;
  END
 END n_li_d[500]
 PIN n_li_d[501]
  DIRECTION INPUT ;
  USE SIGNAL ;
  PORT
   LAYER M4 ;
   RECT 112.236000 96.380000 112.320000 96.412000 ;
  END
 END n_li_d[501]
 PIN n_li_d[502]
  DIRECTION INPUT ;
  USE SIGNAL ;
  PORT
   LAYER M4 ;
   RECT 112.236000 96.572000 112.320000 96.604000 ;
  END
 END n_li_d[502]
 PIN n_li_d[503]
  DIRECTION INPUT ;
  USE SIGNAL ;
  PORT
   LAYER M4 ;
   RECT 112.236000 96.764000 112.320000 96.796000 ;
  END
 END n_li_d[503]
 PIN n_li_d[504]
  DIRECTION INPUT ;
  USE SIGNAL ;
  PORT
   LAYER M4 ;
   RECT 112.236000 96.908000 112.320000 96.940000 ;
  END
 END n_li_d[504]
 PIN n_li_d[505]
  DIRECTION INPUT ;
  USE SIGNAL ;
  PORT
   LAYER M4 ;
   RECT 112.236000 97.100000 112.320000 97.132000 ;
  END
 END n_li_d[505]
 PIN n_li_d[506]
  DIRECTION INPUT ;
  USE SIGNAL ;
  PORT
   LAYER M4 ;
   RECT 112.236000 97.292000 112.320000 97.324000 ;
  END
 END n_li_d[506]
 PIN n_li_d[507]
  DIRECTION INPUT ;
  USE SIGNAL ;
  PORT
   LAYER M4 ;
   RECT 112.236000 97.484000 112.320000 97.516000 ;
  END
 END n_li_d[507]
 PIN n_li_d[508]
  DIRECTION INPUT ;
  USE SIGNAL ;
  PORT
   LAYER M4 ;
   RECT 112.236000 97.628000 112.320000 97.660000 ;
  END
 END n_li_d[508]
 PIN n_li_d[509]
  DIRECTION INPUT ;
  USE SIGNAL ;
  PORT
   LAYER M4 ;
   RECT 112.236000 97.820000 112.320000 97.852000 ;
  END
 END n_li_d[509]
 PIN n_li_d[510]
  DIRECTION INPUT ;
  USE SIGNAL ;
  PORT
   LAYER M4 ;
   RECT 112.236000 98.012000 112.320000 98.044000 ;
  END
 END n_li_d[510]
 PIN n_li_d[511]
  DIRECTION INPUT ;
  USE SIGNAL ;
  PORT
   LAYER M4 ;
   RECT 112.236000 98.204000 112.320000 98.236000 ;
  END
 END n_li_d[511]
 PIN n_li_d[512]
  DIRECTION INPUT ;
  USE SIGNAL ;
  PORT
   LAYER M4 ;
   RECT 112.236000 98.348000 112.320000 98.380000 ;
  END
 END n_li_d[512]
 PIN n_li_d[513]
  DIRECTION INPUT ;
  USE SIGNAL ;
  PORT
   LAYER M4 ;
   RECT 112.236000 98.540000 112.320000 98.572000 ;
  END
 END n_li_d[513]
 PIN n_li_d[514]
  DIRECTION INPUT ;
  USE SIGNAL ;
  PORT
   LAYER M4 ;
   RECT 112.236000 98.732000 112.320000 98.764000 ;
  END
 END n_li_d[514]
 PIN n_li_d[515]
  DIRECTION INPUT ;
  USE SIGNAL ;
  PORT
   LAYER M4 ;
   RECT 112.236000 98.876000 112.320000 98.908000 ;
  END
 END n_li_d[515]
 PIN n_li_d[516]
  DIRECTION INPUT ;
  USE SIGNAL ;
  PORT
   LAYER M4 ;
   RECT 112.236000 99.068000 112.320000 99.100000 ;
  END
 END n_li_d[516]
 PIN n_li_d[517]
  DIRECTION INPUT ;
  USE SIGNAL ;
  PORT
   LAYER M4 ;
   RECT 112.236000 99.260000 112.320000 99.292000 ;
  END
 END n_li_d[517]
 PIN n_li_d[518]
  DIRECTION INPUT ;
  USE SIGNAL ;
  PORT
   LAYER M4 ;
   RECT 112.236000 99.452000 112.320000 99.484000 ;
  END
 END n_li_d[518]
 PIN n_li_d[519]
  DIRECTION INPUT ;
  USE SIGNAL ;
  PORT
   LAYER M4 ;
   RECT 112.236000 99.596000 112.320000 99.628000 ;
  END
 END n_li_d[519]
 PIN n_li_d[520]
  DIRECTION INPUT ;
  USE SIGNAL ;
  PORT
   LAYER M4 ;
   RECT 112.236000 99.788000 112.320000 99.820000 ;
  END
 END n_li_d[520]
 PIN n_li_d[521]
  DIRECTION INPUT ;
  USE SIGNAL ;
  PORT
   LAYER M4 ;
   RECT 112.236000 99.980000 112.320000 100.012000 ;
  END
 END n_li_d[521]
 PIN n_li_d[522]
  DIRECTION INPUT ;
  USE SIGNAL ;
  PORT
   LAYER M4 ;
   RECT 112.236000 100.172000 112.320000 100.204000 ;
  END
 END n_li_d[522]
 PIN n_li_d[523]
  DIRECTION INPUT ;
  USE SIGNAL ;
  PORT
   LAYER M4 ;
   RECT 112.236000 100.316000 112.320000 100.348000 ;
  END
 END n_li_d[523]
 PIN n_li_d[524]
  DIRECTION INPUT ;
  USE SIGNAL ;
  PORT
   LAYER M4 ;
   RECT 112.236000 100.508000 112.320000 100.540000 ;
  END
 END n_li_d[524]
 PIN n_li_d[525]
  DIRECTION INPUT ;
  USE SIGNAL ;
  PORT
   LAYER M4 ;
   RECT 112.236000 100.700000 112.320000 100.732000 ;
  END
 END n_li_d[525]
 PIN n_li_d[526]
  DIRECTION INPUT ;
  USE SIGNAL ;
  PORT
   LAYER M4 ;
   RECT 112.236000 100.892000 112.320000 100.924000 ;
  END
 END n_li_d[526]
 PIN n_li_d[527]
  DIRECTION INPUT ;
  USE SIGNAL ;
  PORT
   LAYER M4 ;
   RECT 112.236000 101.036000 112.320000 101.068000 ;
  END
 END n_li_d[527]
 PIN n_li_d[528]
  DIRECTION INPUT ;
  USE SIGNAL ;
  PORT
   LAYER M4 ;
   RECT 112.236000 101.228000 112.320000 101.260000 ;
  END
 END n_li_d[528]
 PIN n_li_d[529]
  DIRECTION INPUT ;
  USE SIGNAL ;
  PORT
   LAYER M4 ;
   RECT 112.236000 101.420000 112.320000 101.452000 ;
  END
 END n_li_d[529]
 PIN n_li_d[530]
  DIRECTION INPUT ;
  USE SIGNAL ;
  PORT
   LAYER M4 ;
   RECT 112.236000 101.612000 112.320000 101.644000 ;
  END
 END n_li_d[530]
 PIN n_li_d[531]
  DIRECTION INPUT ;
  USE SIGNAL ;
  PORT
   LAYER M4 ;
   RECT 112.236000 101.756000 112.320000 101.788000 ;
  END
 END n_li_d[531]
 PIN n_li_d[532]
  DIRECTION INPUT ;
  USE SIGNAL ;
  PORT
   LAYER M4 ;
   RECT 112.236000 101.948000 112.320000 101.980000 ;
  END
 END n_li_d[532]
 PIN n_li_d[533]
  DIRECTION INPUT ;
  USE SIGNAL ;
  PORT
   LAYER M4 ;
   RECT 112.236000 102.140000 112.320000 102.172000 ;
  END
 END n_li_d[533]
 PIN n_li_d[534]
  DIRECTION INPUT ;
  USE SIGNAL ;
  PORT
   LAYER M4 ;
   RECT 112.236000 102.284000 112.320000 102.316000 ;
  END
 END n_li_d[534]
 PIN n_li_d[535]
  DIRECTION INPUT ;
  USE SIGNAL ;
  PORT
   LAYER M4 ;
   RECT 112.236000 102.476000 112.320000 102.508000 ;
  END
 END n_li_d[535]
 PIN n_li_d[536]
  DIRECTION INPUT ;
  USE SIGNAL ;
  PORT
   LAYER M4 ;
   RECT 112.236000 102.668000 112.320000 102.700000 ;
  END
 END n_li_d[536]
 PIN n_li_d[537]
  DIRECTION INPUT ;
  USE SIGNAL ;
  PORT
   LAYER M4 ;
   RECT 112.236000 102.860000 112.320000 102.892000 ;
  END
 END n_li_d[537]
 PIN n_li_d[538]
  DIRECTION INPUT ;
  USE SIGNAL ;
  PORT
   LAYER M4 ;
   RECT 112.236000 103.004000 112.320000 103.036000 ;
  END
 END n_li_d[538]
 PIN n_li_d[539]
  DIRECTION INPUT ;
  USE SIGNAL ;
  PORT
   LAYER M4 ;
   RECT 112.236000 103.196000 112.320000 103.228000 ;
  END
 END n_li_d[539]
 PIN n_li_d[540]
  DIRECTION INPUT ;
  USE SIGNAL ;
  PORT
   LAYER M4 ;
   RECT 112.236000 103.388000 112.320000 103.420000 ;
  END
 END n_li_d[540]
 PIN n_li_d[541]
  DIRECTION INPUT ;
  USE SIGNAL ;
  PORT
   LAYER M4 ;
   RECT 112.236000 103.580000 112.320000 103.612000 ;
  END
 END n_li_d[541]
 PIN n_li_d[542]
  DIRECTION INPUT ;
  USE SIGNAL ;
  PORT
   LAYER M4 ;
   RECT 112.236000 103.724000 112.320000 103.756000 ;
  END
 END n_li_d[542]
 PIN n_li_d[543]
  DIRECTION INPUT ;
  USE SIGNAL ;
  PORT
   LAYER M4 ;
   RECT 112.236000 103.916000 112.320000 103.948000 ;
  END
 END n_li_d[543]
 PIN n_li_d[544]
  DIRECTION INPUT ;
  USE SIGNAL ;
  PORT
   LAYER M4 ;
   RECT 112.236000 104.108000 112.320000 104.140000 ;
  END
 END n_li_d[544]
 PIN n_li_d[545]
  DIRECTION INPUT ;
  USE SIGNAL ;
  PORT
   LAYER M4 ;
   RECT 112.236000 104.300000 112.320000 104.332000 ;
  END
 END n_li_d[545]
 PIN n_li_d[546]
  DIRECTION INPUT ;
  USE SIGNAL ;
  PORT
   LAYER M4 ;
   RECT 112.236000 104.444000 112.320000 104.476000 ;
  END
 END n_li_d[546]
 PIN n_li_d[547]
  DIRECTION INPUT ;
  USE SIGNAL ;
  PORT
   LAYER M4 ;
   RECT 112.236000 104.636000 112.320000 104.668000 ;
  END
 END n_li_d[547]
 PIN n_li_d[548]
  DIRECTION INPUT ;
  USE SIGNAL ;
  PORT
   LAYER M4 ;
   RECT 112.236000 104.828000 112.320000 104.860000 ;
  END
 END n_li_d[548]
 PIN n_li_d[549]
  DIRECTION INPUT ;
  USE SIGNAL ;
  PORT
   LAYER M4 ;
   RECT 112.236000 104.972000 112.320000 105.004000 ;
  END
 END n_li_d[549]
 PIN n_li_d[550]
  DIRECTION INPUT ;
  USE SIGNAL ;
  PORT
   LAYER M4 ;
   RECT 112.236000 105.164000 112.320000 105.196000 ;
  END
 END n_li_d[550]
 PIN n_li_d[551]
  DIRECTION INPUT ;
  USE SIGNAL ;
  PORT
   LAYER M4 ;
   RECT 112.236000 105.356000 112.320000 105.388000 ;
  END
 END n_li_d[551]
 PIN n_li_d[552]
  DIRECTION INPUT ;
  USE SIGNAL ;
  PORT
   LAYER M4 ;
   RECT 112.236000 105.548000 112.320000 105.580000 ;
  END
 END n_li_d[552]
 PIN n_flt[0]
  DIRECTION INPUT ;
  USE SIGNAL ;
  PORT
   LAYER M4 ;
   RECT 112.236000 105.692000 112.320000 105.724000 ;
  END
 END n_flt[0]
 PIN n_flt[1]
  DIRECTION INPUT ;
  USE SIGNAL ;
  PORT
   LAYER M4 ;
   RECT 112.236000 105.884000 112.320000 105.916000 ;
  END
 END n_flt[1]
 PIN n_flt[2]
  DIRECTION INPUT ;
  USE SIGNAL ;
  PORT
   LAYER M4 ;
   RECT 112.236000 106.076000 112.320000 106.108000 ;
  END
 END n_flt[2]
 PIN n_lo_v
  DIRECTION OUTPUT ;
  USE SIGNAL ;
  PORT
   LAYER M5 ;
   RECT 6.180000 112.236000 6.228000 112.320000 ;
  END
 END n_lo_v
 PIN n_lo_d[0]
  DIRECTION OUTPUT ;
  USE SIGNAL ;
  PORT
   LAYER M5 ;
   RECT 6.756000 112.236000 6.804000 112.320000 ;
  END
 END n_lo_d[0]
 PIN n_lo_d[1]
  DIRECTION OUTPUT ;
  USE SIGNAL ;
  PORT
   LAYER M5 ;
   RECT 6.804000 112.236000 6.852000 112.320000 ;
  END
 END n_lo_d[1]
 PIN n_lo_d[2]
  DIRECTION OUTPUT ;
  USE SIGNAL ;
  PORT
   LAYER M5 ;
   RECT 6.852000 112.236000 6.900000 112.320000 ;
  END
 END n_lo_d[2]
 PIN n_lo_d[3]
  DIRECTION OUTPUT ;
  USE SIGNAL ;
  PORT
   LAYER M5 ;
   RECT 6.948000 112.236000 6.996000 112.320000 ;
  END
 END n_lo_d[3]
 PIN n_lo_d[4]
  DIRECTION OUTPUT ;
  USE SIGNAL ;
  PORT
   LAYER M5 ;
   RECT 7.092000 112.236000 7.140000 112.320000 ;
  END
 END n_lo_d[4]
 PIN n_lo_d[5]
  DIRECTION OUTPUT ;
  USE SIGNAL ;
  PORT
   LAYER M5 ;
   RECT 7.284000 112.236000 7.332000 112.320000 ;
  END
 END n_lo_d[5]
 PIN n_lo_d[6]
  DIRECTION OUTPUT ;
  USE SIGNAL ;
  PORT
   LAYER M5 ;
   RECT 7.476000 112.236000 7.524000 112.320000 ;
  END
 END n_lo_d[6]
 PIN n_lo_d[7]
  DIRECTION OUTPUT ;
  USE SIGNAL ;
  PORT
   LAYER M5 ;
   RECT 7.668000 112.236000 7.716000 112.320000 ;
  END
 END n_lo_d[7]
 PIN n_lo_d[8]
  DIRECTION OUTPUT ;
  USE SIGNAL ;
  PORT
   LAYER M5 ;
   RECT 7.812000 112.236000 7.860000 112.320000 ;
  END
 END n_lo_d[8]
 PIN n_lo_d[9]
  DIRECTION OUTPUT ;
  USE SIGNAL ;
  PORT
   LAYER M5 ;
   RECT 8.004000 112.236000 8.052000 112.320000 ;
  END
 END n_lo_d[9]
 PIN n_lo_d[10]
  DIRECTION OUTPUT ;
  USE SIGNAL ;
  PORT
   LAYER M5 ;
   RECT 8.196000 112.236000 8.244000 112.320000 ;
  END
 END n_lo_d[10]
 PIN n_lo_d[11]
  DIRECTION OUTPUT ;
  USE SIGNAL ;
  PORT
   LAYER M5 ;
   RECT 8.388000 112.236000 8.436000 112.320000 ;
  END
 END n_lo_d[11]
 PIN n_lo_d[12]
  DIRECTION OUTPUT ;
  USE SIGNAL ;
  PORT
   LAYER M5 ;
   RECT 8.532000 112.236000 8.580000 112.320000 ;
  END
 END n_lo_d[12]
 PIN n_lo_d[13]
  DIRECTION OUTPUT ;
  USE SIGNAL ;
  PORT
   LAYER M5 ;
   RECT 8.724000 112.236000 8.772000 112.320000 ;
  END
 END n_lo_d[13]
 PIN n_lo_d[14]
  DIRECTION OUTPUT ;
  USE SIGNAL ;
  PORT
   LAYER M5 ;
   RECT 8.916000 112.236000 8.964000 112.320000 ;
  END
 END n_lo_d[14]
 PIN n_lo_d[15]
  DIRECTION OUTPUT ;
  USE SIGNAL ;
  PORT
   LAYER M5 ;
   RECT 9.108000 112.236000 9.156000 112.320000 ;
  END
 END n_lo_d[15]
 PIN n_lo_d[16]
  DIRECTION OUTPUT ;
  USE SIGNAL ;
  PORT
   LAYER M5 ;
   RECT 9.252000 112.236000 9.300000 112.320000 ;
  END
 END n_lo_d[16]
 PIN n_lo_d[17]
  DIRECTION OUTPUT ;
  USE SIGNAL ;
  PORT
   LAYER M5 ;
   RECT 9.444000 112.236000 9.492000 112.320000 ;
  END
 END n_lo_d[17]
 PIN n_lo_d[18]
  DIRECTION OUTPUT ;
  USE SIGNAL ;
  PORT
   LAYER M5 ;
   RECT 9.636000 112.236000 9.684000 112.320000 ;
  END
 END n_lo_d[18]
 PIN n_lo_d[19]
  DIRECTION OUTPUT ;
  USE SIGNAL ;
  PORT
   LAYER M5 ;
   RECT 9.828000 112.236000 9.876000 112.320000 ;
  END
 END n_lo_d[19]
 PIN n_lo_d[20]
  DIRECTION OUTPUT ;
  USE SIGNAL ;
  PORT
   LAYER M5 ;
   RECT 9.972000 112.236000 10.020000 112.320000 ;
  END
 END n_lo_d[20]
 PIN n_lo_d[21]
  DIRECTION OUTPUT ;
  USE SIGNAL ;
  PORT
   LAYER M5 ;
   RECT 10.164000 112.236000 10.212000 112.320000 ;
  END
 END n_lo_d[21]
 PIN n_lo_d[22]
  DIRECTION OUTPUT ;
  USE SIGNAL ;
  PORT
   LAYER M5 ;
   RECT 10.356000 112.236000 10.404000 112.320000 ;
  END
 END n_lo_d[22]
 PIN n_lo_d[23]
  DIRECTION OUTPUT ;
  USE SIGNAL ;
  PORT
   LAYER M5 ;
   RECT 10.500000 112.236000 10.548000 112.320000 ;
  END
 END n_lo_d[23]
 PIN n_lo_d[24]
  DIRECTION OUTPUT ;
  USE SIGNAL ;
  PORT
   LAYER M5 ;
   RECT 11.076000 112.236000 11.124000 112.320000 ;
  END
 END n_lo_d[24]
 PIN n_lo_d[25]
  DIRECTION OUTPUT ;
  USE SIGNAL ;
  PORT
   LAYER M5 ;
   RECT 11.124000 112.236000 11.172000 112.320000 ;
  END
 END n_lo_d[25]
 PIN n_lo_d[26]
  DIRECTION OUTPUT ;
  USE SIGNAL ;
  PORT
   LAYER M5 ;
   RECT 11.172000 112.236000 11.220000 112.320000 ;
  END
 END n_lo_d[26]
 PIN n_lo_d[27]
  DIRECTION OUTPUT ;
  USE SIGNAL ;
  PORT
   LAYER M5 ;
   RECT 11.268000 112.236000 11.316000 112.320000 ;
  END
 END n_lo_d[27]
 PIN n_lo_d[28]
  DIRECTION OUTPUT ;
  USE SIGNAL ;
  PORT
   LAYER M5 ;
   RECT 11.412000 112.236000 11.460000 112.320000 ;
  END
 END n_lo_d[28]
 PIN n_lo_d[29]
  DIRECTION OUTPUT ;
  USE SIGNAL ;
  PORT
   LAYER M5 ;
   RECT 11.604000 112.236000 11.652000 112.320000 ;
  END
 END n_lo_d[29]
 PIN n_lo_d[30]
  DIRECTION OUTPUT ;
  USE SIGNAL ;
  PORT
   LAYER M5 ;
   RECT 11.796000 112.236000 11.844000 112.320000 ;
  END
 END n_lo_d[30]
 PIN n_lo_d[31]
  DIRECTION OUTPUT ;
  USE SIGNAL ;
  PORT
   LAYER M5 ;
   RECT 11.988000 112.236000 12.036000 112.320000 ;
  END
 END n_lo_d[31]
 PIN n_lo_d[32]
  DIRECTION OUTPUT ;
  USE SIGNAL ;
  PORT
   LAYER M5 ;
   RECT 12.132000 112.236000 12.180000 112.320000 ;
  END
 END n_lo_d[32]
 PIN n_lo_d[33]
  DIRECTION OUTPUT ;
  USE SIGNAL ;
  PORT
   LAYER M5 ;
   RECT 12.324000 112.236000 12.372000 112.320000 ;
  END
 END n_lo_d[33]
 PIN n_lo_d[34]
  DIRECTION OUTPUT ;
  USE SIGNAL ;
  PORT
   LAYER M5 ;
   RECT 12.516000 112.236000 12.564000 112.320000 ;
  END
 END n_lo_d[34]
 PIN n_lo_d[35]
  DIRECTION OUTPUT ;
  USE SIGNAL ;
  PORT
   LAYER M5 ;
   RECT 12.708000 112.236000 12.756000 112.320000 ;
  END
 END n_lo_d[35]
 PIN n_lo_d[36]
  DIRECTION OUTPUT ;
  USE SIGNAL ;
  PORT
   LAYER M5 ;
   RECT 12.852000 112.236000 12.900000 112.320000 ;
  END
 END n_lo_d[36]
 PIN n_lo_d[37]
  DIRECTION OUTPUT ;
  USE SIGNAL ;
  PORT
   LAYER M5 ;
   RECT 13.044000 112.236000 13.092000 112.320000 ;
  END
 END n_lo_d[37]
 PIN n_lo_d[38]
  DIRECTION OUTPUT ;
  USE SIGNAL ;
  PORT
   LAYER M5 ;
   RECT 13.236000 112.236000 13.284000 112.320000 ;
  END
 END n_lo_d[38]
 PIN n_lo_d[39]
  DIRECTION OUTPUT ;
  USE SIGNAL ;
  PORT
   LAYER M5 ;
   RECT 13.428000 112.236000 13.476000 112.320000 ;
  END
 END n_lo_d[39]
 PIN n_lo_d[40]
  DIRECTION OUTPUT ;
  USE SIGNAL ;
  PORT
   LAYER M5 ;
   RECT 13.572000 112.236000 13.620000 112.320000 ;
  END
 END n_lo_d[40]
 PIN n_lo_d[41]
  DIRECTION OUTPUT ;
  USE SIGNAL ;
  PORT
   LAYER M5 ;
   RECT 13.764000 112.236000 13.812000 112.320000 ;
  END
 END n_lo_d[41]
 PIN n_lo_d[42]
  DIRECTION OUTPUT ;
  USE SIGNAL ;
  PORT
   LAYER M5 ;
   RECT 13.956000 112.236000 14.004000 112.320000 ;
  END
 END n_lo_d[42]
 PIN n_lo_d[43]
  DIRECTION OUTPUT ;
  USE SIGNAL ;
  PORT
   LAYER M5 ;
   RECT 14.148000 112.236000 14.196000 112.320000 ;
  END
 END n_lo_d[43]
 PIN n_lo_d[44]
  DIRECTION OUTPUT ;
  USE SIGNAL ;
  PORT
   LAYER M5 ;
   RECT 14.292000 112.236000 14.340000 112.320000 ;
  END
 END n_lo_d[44]
 PIN n_lo_d[45]
  DIRECTION OUTPUT ;
  USE SIGNAL ;
  PORT
   LAYER M5 ;
   RECT 14.484000 112.236000 14.532000 112.320000 ;
  END
 END n_lo_d[45]
 PIN n_lo_d[46]
  DIRECTION OUTPUT ;
  USE SIGNAL ;
  PORT
   LAYER M5 ;
   RECT 14.676000 112.236000 14.724000 112.320000 ;
  END
 END n_lo_d[46]
 PIN n_lo_d[47]
  DIRECTION OUTPUT ;
  USE SIGNAL ;
  PORT
   LAYER M5 ;
   RECT 14.820000 112.236000 14.868000 112.320000 ;
  END
 END n_lo_d[47]
 PIN n_lo_d[48]
  DIRECTION OUTPUT ;
  USE SIGNAL ;
  PORT
   LAYER M5 ;
   RECT 15.396000 112.236000 15.444000 112.320000 ;
  END
 END n_lo_d[48]
 PIN n_lo_d[49]
  DIRECTION OUTPUT ;
  USE SIGNAL ;
  PORT
   LAYER M5 ;
   RECT 15.444000 112.236000 15.492000 112.320000 ;
  END
 END n_lo_d[49]
 PIN n_lo_d[50]
  DIRECTION OUTPUT ;
  USE SIGNAL ;
  PORT
   LAYER M5 ;
   RECT 15.492000 112.236000 15.540000 112.320000 ;
  END
 END n_lo_d[50]
 PIN n_lo_d[51]
  DIRECTION OUTPUT ;
  USE SIGNAL ;
  PORT
   LAYER M5 ;
   RECT 15.588000 112.236000 15.636000 112.320000 ;
  END
 END n_lo_d[51]
 PIN n_lo_d[52]
  DIRECTION OUTPUT ;
  USE SIGNAL ;
  PORT
   LAYER M5 ;
   RECT 15.732000 112.236000 15.780000 112.320000 ;
  END
 END n_lo_d[52]
 PIN n_lo_d[53]
  DIRECTION OUTPUT ;
  USE SIGNAL ;
  PORT
   LAYER M5 ;
   RECT 15.924000 112.236000 15.972000 112.320000 ;
  END
 END n_lo_d[53]
 PIN n_lo_d[54]
  DIRECTION OUTPUT ;
  USE SIGNAL ;
  PORT
   LAYER M5 ;
   RECT 16.116000 112.236000 16.164000 112.320000 ;
  END
 END n_lo_d[54]
 PIN n_lo_d[55]
  DIRECTION OUTPUT ;
  USE SIGNAL ;
  PORT
   LAYER M5 ;
   RECT 16.308000 112.236000 16.356000 112.320000 ;
  END
 END n_lo_d[55]
 PIN n_lo_d[56]
  DIRECTION OUTPUT ;
  USE SIGNAL ;
  PORT
   LAYER M5 ;
   RECT 16.452000 112.236000 16.500000 112.320000 ;
  END
 END n_lo_d[56]
 PIN n_lo_d[57]
  DIRECTION OUTPUT ;
  USE SIGNAL ;
  PORT
   LAYER M5 ;
   RECT 16.644000 112.236000 16.692000 112.320000 ;
  END
 END n_lo_d[57]
 PIN n_lo_d[58]
  DIRECTION OUTPUT ;
  USE SIGNAL ;
  PORT
   LAYER M5 ;
   RECT 16.836000 112.236000 16.884000 112.320000 ;
  END
 END n_lo_d[58]
 PIN n_lo_d[59]
  DIRECTION OUTPUT ;
  USE SIGNAL ;
  PORT
   LAYER M5 ;
   RECT 17.028000 112.236000 17.076000 112.320000 ;
  END
 END n_lo_d[59]
 PIN n_lo_d[60]
  DIRECTION OUTPUT ;
  USE SIGNAL ;
  PORT
   LAYER M5 ;
   RECT 17.172000 112.236000 17.220000 112.320000 ;
  END
 END n_lo_d[60]
 PIN n_lo_d[61]
  DIRECTION OUTPUT ;
  USE SIGNAL ;
  PORT
   LAYER M5 ;
   RECT 17.364000 112.236000 17.412000 112.320000 ;
  END
 END n_lo_d[61]
 PIN n_lo_d[62]
  DIRECTION OUTPUT ;
  USE SIGNAL ;
  PORT
   LAYER M5 ;
   RECT 17.556000 112.236000 17.604000 112.320000 ;
  END
 END n_lo_d[62]
 PIN n_lo_d[63]
  DIRECTION OUTPUT ;
  USE SIGNAL ;
  PORT
   LAYER M5 ;
   RECT 17.748000 112.236000 17.796000 112.320000 ;
  END
 END n_lo_d[63]
 PIN n_lo_d[64]
  DIRECTION OUTPUT ;
  USE SIGNAL ;
  PORT
   LAYER M5 ;
   RECT 17.892000 112.236000 17.940000 112.320000 ;
  END
 END n_lo_d[64]
 PIN n_lo_d[65]
  DIRECTION OUTPUT ;
  USE SIGNAL ;
  PORT
   LAYER M5 ;
   RECT 18.084000 112.236000 18.132000 112.320000 ;
  END
 END n_lo_d[65]
 PIN n_lo_d[66]
  DIRECTION OUTPUT ;
  USE SIGNAL ;
  PORT
   LAYER M5 ;
   RECT 18.276000 112.236000 18.324000 112.320000 ;
  END
 END n_lo_d[66]
 PIN n_lo_d[67]
  DIRECTION OUTPUT ;
  USE SIGNAL ;
  PORT
   LAYER M5 ;
   RECT 18.468000 112.236000 18.516000 112.320000 ;
  END
 END n_lo_d[67]
 PIN n_lo_d[68]
  DIRECTION OUTPUT ;
  USE SIGNAL ;
  PORT
   LAYER M5 ;
   RECT 18.612000 112.236000 18.660000 112.320000 ;
  END
 END n_lo_d[68]
 PIN n_lo_d[69]
  DIRECTION OUTPUT ;
  USE SIGNAL ;
  PORT
   LAYER M5 ;
   RECT 18.804000 112.236000 18.852000 112.320000 ;
  END
 END n_lo_d[69]
 PIN n_lo_d[70]
  DIRECTION OUTPUT ;
  USE SIGNAL ;
  PORT
   LAYER M5 ;
   RECT 18.996000 112.236000 19.044000 112.320000 ;
  END
 END n_lo_d[70]
 PIN n_lo_d[71]
  DIRECTION OUTPUT ;
  USE SIGNAL ;
  PORT
   LAYER M5 ;
   RECT 19.140000 112.236000 19.188000 112.320000 ;
  END
 END n_lo_d[71]
 PIN n_lo_d[72]
  DIRECTION OUTPUT ;
  USE SIGNAL ;
  PORT
   LAYER M5 ;
   RECT 19.716000 112.236000 19.764000 112.320000 ;
  END
 END n_lo_d[72]
 PIN n_lo_d[73]
  DIRECTION OUTPUT ;
  USE SIGNAL ;
  PORT
   LAYER M5 ;
   RECT 19.764000 112.236000 19.812000 112.320000 ;
  END
 END n_lo_d[73]
 PIN n_lo_d[74]
  DIRECTION OUTPUT ;
  USE SIGNAL ;
  PORT
   LAYER M5 ;
   RECT 19.812000 112.236000 19.860000 112.320000 ;
  END
 END n_lo_d[74]
 PIN n_lo_d[75]
  DIRECTION OUTPUT ;
  USE SIGNAL ;
  PORT
   LAYER M5 ;
   RECT 19.860000 112.236000 19.908000 112.320000 ;
  END
 END n_lo_d[75]
 PIN n_lo_d[76]
  DIRECTION OUTPUT ;
  USE SIGNAL ;
  PORT
   LAYER M5 ;
   RECT 20.052000 112.236000 20.100000 112.320000 ;
  END
 END n_lo_d[76]
 PIN n_lo_d[77]
  DIRECTION OUTPUT ;
  USE SIGNAL ;
  PORT
   LAYER M5 ;
   RECT 20.244000 112.236000 20.292000 112.320000 ;
  END
 END n_lo_d[77]
 PIN n_lo_d[78]
  DIRECTION OUTPUT ;
  USE SIGNAL ;
  PORT
   LAYER M5 ;
   RECT 20.436000 112.236000 20.484000 112.320000 ;
  END
 END n_lo_d[78]
 PIN n_lo_d[79]
  DIRECTION OUTPUT ;
  USE SIGNAL ;
  PORT
   LAYER M5 ;
   RECT 20.580000 112.236000 20.628000 112.320000 ;
  END
 END n_lo_d[79]
 PIN n_lo_d[80]
  DIRECTION OUTPUT ;
  USE SIGNAL ;
  PORT
   LAYER M5 ;
   RECT 20.772000 112.236000 20.820000 112.320000 ;
  END
 END n_lo_d[80]
 PIN n_lo_d[81]
  DIRECTION OUTPUT ;
  USE SIGNAL ;
  PORT
   LAYER M5 ;
   RECT 20.964000 112.236000 21.012000 112.320000 ;
  END
 END n_lo_d[81]
 PIN n_lo_d[82]
  DIRECTION OUTPUT ;
  USE SIGNAL ;
  PORT
   LAYER M5 ;
   RECT 21.156000 112.236000 21.204000 112.320000 ;
  END
 END n_lo_d[82]
 PIN n_lo_d[83]
  DIRECTION OUTPUT ;
  USE SIGNAL ;
  PORT
   LAYER M5 ;
   RECT 21.300000 112.236000 21.348000 112.320000 ;
  END
 END n_lo_d[83]
 PIN n_lo_d[84]
  DIRECTION OUTPUT ;
  USE SIGNAL ;
  PORT
   LAYER M5 ;
   RECT 21.492000 112.236000 21.540000 112.320000 ;
  END
 END n_lo_d[84]
 PIN n_lo_d[85]
  DIRECTION OUTPUT ;
  USE SIGNAL ;
  PORT
   LAYER M5 ;
   RECT 21.684000 112.236000 21.732000 112.320000 ;
  END
 END n_lo_d[85]
 PIN n_lo_d[86]
  DIRECTION OUTPUT ;
  USE SIGNAL ;
  PORT
   LAYER M5 ;
   RECT 21.876000 112.236000 21.924000 112.320000 ;
  END
 END n_lo_d[86]
 PIN n_lo_d[87]
  DIRECTION OUTPUT ;
  USE SIGNAL ;
  PORT
   LAYER M5 ;
   RECT 22.020000 112.236000 22.068000 112.320000 ;
  END
 END n_lo_d[87]
 PIN n_lo_d[88]
  DIRECTION OUTPUT ;
  USE SIGNAL ;
  PORT
   LAYER M5 ;
   RECT 22.212000 112.236000 22.260000 112.320000 ;
  END
 END n_lo_d[88]
 PIN n_lo_d[89]
  DIRECTION OUTPUT ;
  USE SIGNAL ;
  PORT
   LAYER M5 ;
   RECT 22.404000 112.236000 22.452000 112.320000 ;
  END
 END n_lo_d[89]
 PIN n_lo_d[90]
  DIRECTION OUTPUT ;
  USE SIGNAL ;
  PORT
   LAYER M5 ;
   RECT 22.596000 112.236000 22.644000 112.320000 ;
  END
 END n_lo_d[90]
 PIN n_lo_d[91]
  DIRECTION OUTPUT ;
  USE SIGNAL ;
  PORT
   LAYER M5 ;
   RECT 22.740000 112.236000 22.788000 112.320000 ;
  END
 END n_lo_d[91]
 PIN n_lo_d[92]
  DIRECTION OUTPUT ;
  USE SIGNAL ;
  PORT
   LAYER M5 ;
   RECT 22.932000 112.236000 22.980000 112.320000 ;
  END
 END n_lo_d[92]
 PIN n_lo_d[93]
  DIRECTION OUTPUT ;
  USE SIGNAL ;
  PORT
   LAYER M5 ;
   RECT 23.124000 112.236000 23.172000 112.320000 ;
  END
 END n_lo_d[93]
 PIN n_lo_d[94]
  DIRECTION OUTPUT ;
  USE SIGNAL ;
  PORT
   LAYER M5 ;
   RECT 23.316000 112.236000 23.364000 112.320000 ;
  END
 END n_lo_d[94]
 PIN n_lo_d[95]
  DIRECTION OUTPUT ;
  USE SIGNAL ;
  PORT
   LAYER M5 ;
   RECT 23.460000 112.236000 23.508000 112.320000 ;
  END
 END n_lo_d[95]
 PIN n_lo_d[96]
  DIRECTION OUTPUT ;
  USE SIGNAL ;
  PORT
   LAYER M5 ;
   RECT 24.036000 112.236000 24.084000 112.320000 ;
  END
 END n_lo_d[96]
 PIN n_lo_d[97]
  DIRECTION OUTPUT ;
  USE SIGNAL ;
  PORT
   LAYER M5 ;
   RECT 24.084000 112.236000 24.132000 112.320000 ;
  END
 END n_lo_d[97]
 PIN n_lo_d[98]
  DIRECTION OUTPUT ;
  USE SIGNAL ;
  PORT
   LAYER M5 ;
   RECT 24.132000 112.236000 24.180000 112.320000 ;
  END
 END n_lo_d[98]
 PIN n_lo_d[99]
  DIRECTION OUTPUT ;
  USE SIGNAL ;
  PORT
   LAYER M5 ;
   RECT 24.180000 112.236000 24.228000 112.320000 ;
  END
 END n_lo_d[99]
 PIN n_lo_d[100]
  DIRECTION OUTPUT ;
  USE SIGNAL ;
  PORT
   LAYER M5 ;
   RECT 24.372000 112.236000 24.420000 112.320000 ;
  END
 END n_lo_d[100]
 PIN n_lo_d[101]
  DIRECTION OUTPUT ;
  USE SIGNAL ;
  PORT
   LAYER M5 ;
   RECT 24.564000 112.236000 24.612000 112.320000 ;
  END
 END n_lo_d[101]
 PIN n_lo_d[102]
  DIRECTION OUTPUT ;
  USE SIGNAL ;
  PORT
   LAYER M5 ;
   RECT 24.756000 112.236000 24.804000 112.320000 ;
  END
 END n_lo_d[102]
 PIN n_lo_d[103]
  DIRECTION OUTPUT ;
  USE SIGNAL ;
  PORT
   LAYER M5 ;
   RECT 24.900000 112.236000 24.948000 112.320000 ;
  END
 END n_lo_d[103]
 PIN n_lo_d[104]
  DIRECTION OUTPUT ;
  USE SIGNAL ;
  PORT
   LAYER M5 ;
   RECT 25.092000 112.236000 25.140000 112.320000 ;
  END
 END n_lo_d[104]
 PIN n_lo_d[105]
  DIRECTION OUTPUT ;
  USE SIGNAL ;
  PORT
   LAYER M5 ;
   RECT 25.284000 112.236000 25.332000 112.320000 ;
  END
 END n_lo_d[105]
 PIN n_lo_d[106]
  DIRECTION OUTPUT ;
  USE SIGNAL ;
  PORT
   LAYER M5 ;
   RECT 25.476000 112.236000 25.524000 112.320000 ;
  END
 END n_lo_d[106]
 PIN n_lo_d[107]
  DIRECTION OUTPUT ;
  USE SIGNAL ;
  PORT
   LAYER M5 ;
   RECT 25.620000 112.236000 25.668000 112.320000 ;
  END
 END n_lo_d[107]
 PIN n_lo_d[108]
  DIRECTION OUTPUT ;
  USE SIGNAL ;
  PORT
   LAYER M5 ;
   RECT 25.812000 112.236000 25.860000 112.320000 ;
  END
 END n_lo_d[108]
 PIN n_lo_d[109]
  DIRECTION OUTPUT ;
  USE SIGNAL ;
  PORT
   LAYER M5 ;
   RECT 26.004000 112.236000 26.052000 112.320000 ;
  END
 END n_lo_d[109]
 PIN n_lo_d[110]
  DIRECTION OUTPUT ;
  USE SIGNAL ;
  PORT
   LAYER M5 ;
   RECT 26.196000 112.236000 26.244000 112.320000 ;
  END
 END n_lo_d[110]
 PIN n_lo_d[111]
  DIRECTION OUTPUT ;
  USE SIGNAL ;
  PORT
   LAYER M5 ;
   RECT 26.340000 112.236000 26.388000 112.320000 ;
  END
 END n_lo_d[111]
 PIN n_lo_d[112]
  DIRECTION OUTPUT ;
  USE SIGNAL ;
  PORT
   LAYER M5 ;
   RECT 26.532000 112.236000 26.580000 112.320000 ;
  END
 END n_lo_d[112]
 PIN n_lo_d[113]
  DIRECTION OUTPUT ;
  USE SIGNAL ;
  PORT
   LAYER M5 ;
   RECT 26.724000 112.236000 26.772000 112.320000 ;
  END
 END n_lo_d[113]
 PIN n_lo_d[114]
  DIRECTION OUTPUT ;
  USE SIGNAL ;
  PORT
   LAYER M5 ;
   RECT 26.916000 112.236000 26.964000 112.320000 ;
  END
 END n_lo_d[114]
 PIN n_lo_d[115]
  DIRECTION OUTPUT ;
  USE SIGNAL ;
  PORT
   LAYER M5 ;
   RECT 27.060000 112.236000 27.108000 112.320000 ;
  END
 END n_lo_d[115]
 PIN n_lo_d[116]
  DIRECTION OUTPUT ;
  USE SIGNAL ;
  PORT
   LAYER M5 ;
   RECT 27.252000 112.236000 27.300000 112.320000 ;
  END
 END n_lo_d[116]
 PIN n_lo_d[117]
  DIRECTION OUTPUT ;
  USE SIGNAL ;
  PORT
   LAYER M5 ;
   RECT 27.444000 112.236000 27.492000 112.320000 ;
  END
 END n_lo_d[117]
 PIN n_lo_d[118]
  DIRECTION OUTPUT ;
  USE SIGNAL ;
  PORT
   LAYER M5 ;
   RECT 27.636000 112.236000 27.684000 112.320000 ;
  END
 END n_lo_d[118]
 PIN n_lo_d[119]
  DIRECTION OUTPUT ;
  USE SIGNAL ;
  PORT
   LAYER M5 ;
   RECT 27.780000 112.236000 27.828000 112.320000 ;
  END
 END n_lo_d[119]
 PIN n_lo_d[120]
  DIRECTION OUTPUT ;
  USE SIGNAL ;
  PORT
   LAYER M5 ;
   RECT 28.356000 112.236000 28.404000 112.320000 ;
  END
 END n_lo_d[120]
 PIN n_lo_d[121]
  DIRECTION OUTPUT ;
  USE SIGNAL ;
  PORT
   LAYER M5 ;
   RECT 28.404000 112.236000 28.452000 112.320000 ;
  END
 END n_lo_d[121]
 PIN n_lo_d[122]
  DIRECTION OUTPUT ;
  USE SIGNAL ;
  PORT
   LAYER M5 ;
   RECT 28.452000 112.236000 28.500000 112.320000 ;
  END
 END n_lo_d[122]
 PIN n_lo_d[123]
  DIRECTION OUTPUT ;
  USE SIGNAL ;
  PORT
   LAYER M5 ;
   RECT 28.500000 112.236000 28.548000 112.320000 ;
  END
 END n_lo_d[123]
 PIN n_lo_d[124]
  DIRECTION OUTPUT ;
  USE SIGNAL ;
  PORT
   LAYER M5 ;
   RECT 28.692000 112.236000 28.740000 112.320000 ;
  END
 END n_lo_d[124]
 PIN n_lo_d[125]
  DIRECTION OUTPUT ;
  USE SIGNAL ;
  PORT
   LAYER M5 ;
   RECT 28.884000 112.236000 28.932000 112.320000 ;
  END
 END n_lo_d[125]
 PIN n_lo_d[126]
  DIRECTION OUTPUT ;
  USE SIGNAL ;
  PORT
   LAYER M5 ;
   RECT 29.076000 112.236000 29.124000 112.320000 ;
  END
 END n_lo_d[126]
 PIN n_lo_d[127]
  DIRECTION OUTPUT ;
  USE SIGNAL ;
  PORT
   LAYER M5 ;
   RECT 29.220000 112.236000 29.268000 112.320000 ;
  END
 END n_lo_d[127]
 PIN n_lo_d[128]
  DIRECTION OUTPUT ;
  USE SIGNAL ;
  PORT
   LAYER M5 ;
   RECT 29.412000 112.236000 29.460000 112.320000 ;
  END
 END n_lo_d[128]
 PIN n_lo_d[129]
  DIRECTION OUTPUT ;
  USE SIGNAL ;
  PORT
   LAYER M5 ;
   RECT 29.604000 112.236000 29.652000 112.320000 ;
  END
 END n_lo_d[129]
 PIN n_lo_d[130]
  DIRECTION OUTPUT ;
  USE SIGNAL ;
  PORT
   LAYER M5 ;
   RECT 29.796000 112.236000 29.844000 112.320000 ;
  END
 END n_lo_d[130]
 PIN n_lo_d[131]
  DIRECTION OUTPUT ;
  USE SIGNAL ;
  PORT
   LAYER M5 ;
   RECT 29.940000 112.236000 29.988000 112.320000 ;
  END
 END n_lo_d[131]
 PIN n_lo_d[132]
  DIRECTION OUTPUT ;
  USE SIGNAL ;
  PORT
   LAYER M5 ;
   RECT 30.132000 112.236000 30.180000 112.320000 ;
  END
 END n_lo_d[132]
 PIN n_lo_d[133]
  DIRECTION OUTPUT ;
  USE SIGNAL ;
  PORT
   LAYER M5 ;
   RECT 30.324000 112.236000 30.372000 112.320000 ;
  END
 END n_lo_d[133]
 PIN n_lo_d[134]
  DIRECTION OUTPUT ;
  USE SIGNAL ;
  PORT
   LAYER M5 ;
   RECT 30.516000 112.236000 30.564000 112.320000 ;
  END
 END n_lo_d[134]
 PIN n_lo_d[135]
  DIRECTION OUTPUT ;
  USE SIGNAL ;
  PORT
   LAYER M5 ;
   RECT 30.660000 112.236000 30.708000 112.320000 ;
  END
 END n_lo_d[135]
 PIN n_lo_d[136]
  DIRECTION OUTPUT ;
  USE SIGNAL ;
  PORT
   LAYER M5 ;
   RECT 30.852000 112.236000 30.900000 112.320000 ;
  END
 END n_lo_d[136]
 PIN n_lo_d[137]
  DIRECTION OUTPUT ;
  USE SIGNAL ;
  PORT
   LAYER M5 ;
   RECT 31.044000 112.236000 31.092000 112.320000 ;
  END
 END n_lo_d[137]
 PIN n_lo_d[138]
  DIRECTION OUTPUT ;
  USE SIGNAL ;
  PORT
   LAYER M5 ;
   RECT 31.236000 112.236000 31.284000 112.320000 ;
  END
 END n_lo_d[138]
 PIN n_lo_d[139]
  DIRECTION OUTPUT ;
  USE SIGNAL ;
  PORT
   LAYER M5 ;
   RECT 31.380000 112.236000 31.428000 112.320000 ;
  END
 END n_lo_d[139]
 PIN n_lo_d[140]
  DIRECTION OUTPUT ;
  USE SIGNAL ;
  PORT
   LAYER M5 ;
   RECT 31.572000 112.236000 31.620000 112.320000 ;
  END
 END n_lo_d[140]
 PIN n_lo_d[141]
  DIRECTION OUTPUT ;
  USE SIGNAL ;
  PORT
   LAYER M5 ;
   RECT 31.764000 112.236000 31.812000 112.320000 ;
  END
 END n_lo_d[141]
 PIN n_lo_d[142]
  DIRECTION OUTPUT ;
  USE SIGNAL ;
  PORT
   LAYER M5 ;
   RECT 31.956000 112.236000 32.004000 112.320000 ;
  END
 END n_lo_d[142]
 PIN n_lo_d[143]
  DIRECTION OUTPUT ;
  USE SIGNAL ;
  PORT
   LAYER M5 ;
   RECT 32.100000 112.236000 32.148000 112.320000 ;
  END
 END n_lo_d[143]
 PIN n_lo_d[144]
  DIRECTION OUTPUT ;
  USE SIGNAL ;
  PORT
   LAYER M5 ;
   RECT 32.676000 112.236000 32.724000 112.320000 ;
  END
 END n_lo_d[144]
 PIN n_lo_d[145]
  DIRECTION OUTPUT ;
  USE SIGNAL ;
  PORT
   LAYER M5 ;
   RECT 32.724000 112.236000 32.772000 112.320000 ;
  END
 END n_lo_d[145]
 PIN n_lo_d[146]
  DIRECTION OUTPUT ;
  USE SIGNAL ;
  PORT
   LAYER M5 ;
   RECT 32.772000 112.236000 32.820000 112.320000 ;
  END
 END n_lo_d[146]
 PIN n_lo_d[147]
  DIRECTION OUTPUT ;
  USE SIGNAL ;
  PORT
   LAYER M5 ;
   RECT 32.820000 112.236000 32.868000 112.320000 ;
  END
 END n_lo_d[147]
 PIN n_lo_d[148]
  DIRECTION OUTPUT ;
  USE SIGNAL ;
  PORT
   LAYER M5 ;
   RECT 33.012000 112.236000 33.060000 112.320000 ;
  END
 END n_lo_d[148]
 PIN n_lo_d[149]
  DIRECTION OUTPUT ;
  USE SIGNAL ;
  PORT
   LAYER M5 ;
   RECT 33.204000 112.236000 33.252000 112.320000 ;
  END
 END n_lo_d[149]
 PIN n_lo_d[150]
  DIRECTION OUTPUT ;
  USE SIGNAL ;
  PORT
   LAYER M5 ;
   RECT 33.396000 112.236000 33.444000 112.320000 ;
  END
 END n_lo_d[150]
 PIN n_lo_d[151]
  DIRECTION OUTPUT ;
  USE SIGNAL ;
  PORT
   LAYER M5 ;
   RECT 33.540000 112.236000 33.588000 112.320000 ;
  END
 END n_lo_d[151]
 PIN n_lo_d[152]
  DIRECTION OUTPUT ;
  USE SIGNAL ;
  PORT
   LAYER M5 ;
   RECT 33.732000 112.236000 33.780000 112.320000 ;
  END
 END n_lo_d[152]
 PIN n_lo_d[153]
  DIRECTION OUTPUT ;
  USE SIGNAL ;
  PORT
   LAYER M5 ;
   RECT 33.924000 112.236000 33.972000 112.320000 ;
  END
 END n_lo_d[153]
 PIN n_lo_d[154]
  DIRECTION OUTPUT ;
  USE SIGNAL ;
  PORT
   LAYER M5 ;
   RECT 34.116000 112.236000 34.164000 112.320000 ;
  END
 END n_lo_d[154]
 PIN n_lo_d[155]
  DIRECTION OUTPUT ;
  USE SIGNAL ;
  PORT
   LAYER M5 ;
   RECT 34.260000 112.236000 34.308000 112.320000 ;
  END
 END n_lo_d[155]
 PIN n_lo_d[156]
  DIRECTION OUTPUT ;
  USE SIGNAL ;
  PORT
   LAYER M5 ;
   RECT 34.452000 112.236000 34.500000 112.320000 ;
  END
 END n_lo_d[156]
 PIN n_lo_d[157]
  DIRECTION OUTPUT ;
  USE SIGNAL ;
  PORT
   LAYER M5 ;
   RECT 34.644000 112.236000 34.692000 112.320000 ;
  END
 END n_lo_d[157]
 PIN n_lo_d[158]
  DIRECTION OUTPUT ;
  USE SIGNAL ;
  PORT
   LAYER M5 ;
   RECT 34.836000 112.236000 34.884000 112.320000 ;
  END
 END n_lo_d[158]
 PIN n_lo_d[159]
  DIRECTION OUTPUT ;
  USE SIGNAL ;
  PORT
   LAYER M5 ;
   RECT 34.980000 112.236000 35.028000 112.320000 ;
  END
 END n_lo_d[159]
 PIN n_lo_d[160]
  DIRECTION OUTPUT ;
  USE SIGNAL ;
  PORT
   LAYER M5 ;
   RECT 35.172000 112.236000 35.220000 112.320000 ;
  END
 END n_lo_d[160]
 PIN n_lo_d[161]
  DIRECTION OUTPUT ;
  USE SIGNAL ;
  PORT
   LAYER M5 ;
   RECT 35.364000 112.236000 35.412000 112.320000 ;
  END
 END n_lo_d[161]
 PIN n_lo_d[162]
  DIRECTION OUTPUT ;
  USE SIGNAL ;
  PORT
   LAYER M5 ;
   RECT 35.556000 112.236000 35.604000 112.320000 ;
  END
 END n_lo_d[162]
 PIN n_lo_d[163]
  DIRECTION OUTPUT ;
  USE SIGNAL ;
  PORT
   LAYER M5 ;
   RECT 35.700000 112.236000 35.748000 112.320000 ;
  END
 END n_lo_d[163]
 PIN n_lo_d[164]
  DIRECTION OUTPUT ;
  USE SIGNAL ;
  PORT
   LAYER M5 ;
   RECT 35.892000 112.236000 35.940000 112.320000 ;
  END
 END n_lo_d[164]
 PIN n_lo_d[165]
  DIRECTION OUTPUT ;
  USE SIGNAL ;
  PORT
   LAYER M5 ;
   RECT 36.084000 112.236000 36.132000 112.320000 ;
  END
 END n_lo_d[165]
 PIN n_lo_d[166]
  DIRECTION OUTPUT ;
  USE SIGNAL ;
  PORT
   LAYER M5 ;
   RECT 36.276000 112.236000 36.324000 112.320000 ;
  END
 END n_lo_d[166]
 PIN n_lo_d[167]
  DIRECTION OUTPUT ;
  USE SIGNAL ;
  PORT
   LAYER M5 ;
   RECT 36.420000 112.236000 36.468000 112.320000 ;
  END
 END n_lo_d[167]
 PIN n_lo_d[168]
  DIRECTION OUTPUT ;
  USE SIGNAL ;
  PORT
   LAYER M5 ;
   RECT 36.996000 112.236000 37.044000 112.320000 ;
  END
 END n_lo_d[168]
 PIN n_lo_d[169]
  DIRECTION OUTPUT ;
  USE SIGNAL ;
  PORT
   LAYER M5 ;
   RECT 37.044000 112.236000 37.092000 112.320000 ;
  END
 END n_lo_d[169]
 PIN n_lo_d[170]
  DIRECTION OUTPUT ;
  USE SIGNAL ;
  PORT
   LAYER M5 ;
   RECT 37.092000 112.236000 37.140000 112.320000 ;
  END
 END n_lo_d[170]
 PIN n_lo_d[171]
  DIRECTION OUTPUT ;
  USE SIGNAL ;
  PORT
   LAYER M5 ;
   RECT 37.140000 112.236000 37.188000 112.320000 ;
  END
 END n_lo_d[171]
 PIN n_lo_d[172]
  DIRECTION OUTPUT ;
  USE SIGNAL ;
  PORT
   LAYER M5 ;
   RECT 37.332000 112.236000 37.380000 112.320000 ;
  END
 END n_lo_d[172]
 PIN n_lo_d[173]
  DIRECTION OUTPUT ;
  USE SIGNAL ;
  PORT
   LAYER M5 ;
   RECT 37.524000 112.236000 37.572000 112.320000 ;
  END
 END n_lo_d[173]
 PIN n_lo_d[174]
  DIRECTION OUTPUT ;
  USE SIGNAL ;
  PORT
   LAYER M5 ;
   RECT 37.716000 112.236000 37.764000 112.320000 ;
  END
 END n_lo_d[174]
 PIN n_lo_d[175]
  DIRECTION OUTPUT ;
  USE SIGNAL ;
  PORT
   LAYER M5 ;
   RECT 37.860000 112.236000 37.908000 112.320000 ;
  END
 END n_lo_d[175]
 PIN n_lo_d[176]
  DIRECTION OUTPUT ;
  USE SIGNAL ;
  PORT
   LAYER M5 ;
   RECT 38.052000 112.236000 38.100000 112.320000 ;
  END
 END n_lo_d[176]
 PIN n_lo_d[177]
  DIRECTION OUTPUT ;
  USE SIGNAL ;
  PORT
   LAYER M5 ;
   RECT 38.244000 112.236000 38.292000 112.320000 ;
  END
 END n_lo_d[177]
 PIN n_lo_d[178]
  DIRECTION OUTPUT ;
  USE SIGNAL ;
  PORT
   LAYER M5 ;
   RECT 38.436000 112.236000 38.484000 112.320000 ;
  END
 END n_lo_d[178]
 PIN n_lo_d[179]
  DIRECTION OUTPUT ;
  USE SIGNAL ;
  PORT
   LAYER M5 ;
   RECT 38.580000 112.236000 38.628000 112.320000 ;
  END
 END n_lo_d[179]
 PIN n_lo_d[180]
  DIRECTION OUTPUT ;
  USE SIGNAL ;
  PORT
   LAYER M5 ;
   RECT 38.772000 112.236000 38.820000 112.320000 ;
  END
 END n_lo_d[180]
 PIN n_lo_d[181]
  DIRECTION OUTPUT ;
  USE SIGNAL ;
  PORT
   LAYER M5 ;
   RECT 38.964000 112.236000 39.012000 112.320000 ;
  END
 END n_lo_d[181]
 PIN n_lo_d[182]
  DIRECTION OUTPUT ;
  USE SIGNAL ;
  PORT
   LAYER M5 ;
   RECT 39.156000 112.236000 39.204000 112.320000 ;
  END
 END n_lo_d[182]
 PIN n_lo_d[183]
  DIRECTION OUTPUT ;
  USE SIGNAL ;
  PORT
   LAYER M5 ;
   RECT 39.300000 112.236000 39.348000 112.320000 ;
  END
 END n_lo_d[183]
 PIN n_lo_d[184]
  DIRECTION OUTPUT ;
  USE SIGNAL ;
  PORT
   LAYER M5 ;
   RECT 39.492000 112.236000 39.540000 112.320000 ;
  END
 END n_lo_d[184]
 PIN n_lo_d[185]
  DIRECTION OUTPUT ;
  USE SIGNAL ;
  PORT
   LAYER M5 ;
   RECT 39.684000 112.236000 39.732000 112.320000 ;
  END
 END n_lo_d[185]
 PIN n_lo_d[186]
  DIRECTION OUTPUT ;
  USE SIGNAL ;
  PORT
   LAYER M5 ;
   RECT 39.876000 112.236000 39.924000 112.320000 ;
  END
 END n_lo_d[186]
 PIN n_lo_d[187]
  DIRECTION OUTPUT ;
  USE SIGNAL ;
  PORT
   LAYER M5 ;
   RECT 40.020000 112.236000 40.068000 112.320000 ;
  END
 END n_lo_d[187]
 PIN n_lo_d[188]
  DIRECTION OUTPUT ;
  USE SIGNAL ;
  PORT
   LAYER M5 ;
   RECT 40.212000 112.236000 40.260000 112.320000 ;
  END
 END n_lo_d[188]
 PIN n_lo_d[189]
  DIRECTION OUTPUT ;
  USE SIGNAL ;
  PORT
   LAYER M5 ;
   RECT 40.404000 112.236000 40.452000 112.320000 ;
  END
 END n_lo_d[189]
 PIN n_lo_d[190]
  DIRECTION OUTPUT ;
  USE SIGNAL ;
  PORT
   LAYER M5 ;
   RECT 40.596000 112.236000 40.644000 112.320000 ;
  END
 END n_lo_d[190]
 PIN n_lo_d[191]
  DIRECTION OUTPUT ;
  USE SIGNAL ;
  PORT
   LAYER M5 ;
   RECT 40.740000 112.236000 40.788000 112.320000 ;
  END
 END n_lo_d[191]
 PIN n_lo_d[192]
  DIRECTION OUTPUT ;
  USE SIGNAL ;
  PORT
   LAYER M5 ;
   RECT 41.316000 112.236000 41.364000 112.320000 ;
  END
 END n_lo_d[192]
 PIN n_lo_d[193]
  DIRECTION OUTPUT ;
  USE SIGNAL ;
  PORT
   LAYER M5 ;
   RECT 41.364000 112.236000 41.412000 112.320000 ;
  END
 END n_lo_d[193]
 PIN n_lo_d[194]
  DIRECTION OUTPUT ;
  USE SIGNAL ;
  PORT
   LAYER M5 ;
   RECT 41.412000 112.236000 41.460000 112.320000 ;
  END
 END n_lo_d[194]
 PIN n_lo_d[195]
  DIRECTION OUTPUT ;
  USE SIGNAL ;
  PORT
   LAYER M5 ;
   RECT 41.460000 112.236000 41.508000 112.320000 ;
  END
 END n_lo_d[195]
 PIN n_lo_d[196]
  DIRECTION OUTPUT ;
  USE SIGNAL ;
  PORT
   LAYER M5 ;
   RECT 41.652000 112.236000 41.700000 112.320000 ;
  END
 END n_lo_d[196]
 PIN n_lo_d[197]
  DIRECTION OUTPUT ;
  USE SIGNAL ;
  PORT
   LAYER M5 ;
   RECT 41.844000 112.236000 41.892000 112.320000 ;
  END
 END n_lo_d[197]
 PIN n_lo_d[198]
  DIRECTION OUTPUT ;
  USE SIGNAL ;
  PORT
   LAYER M5 ;
   RECT 42.036000 112.236000 42.084000 112.320000 ;
  END
 END n_lo_d[198]
 PIN n_lo_d[199]
  DIRECTION OUTPUT ;
  USE SIGNAL ;
  PORT
   LAYER M5 ;
   RECT 42.180000 112.236000 42.228000 112.320000 ;
  END
 END n_lo_d[199]
 PIN n_lo_d[200]
  DIRECTION OUTPUT ;
  USE SIGNAL ;
  PORT
   LAYER M5 ;
   RECT 42.372000 112.236000 42.420000 112.320000 ;
  END
 END n_lo_d[200]
 PIN n_lo_d[201]
  DIRECTION OUTPUT ;
  USE SIGNAL ;
  PORT
   LAYER M5 ;
   RECT 42.564000 112.236000 42.612000 112.320000 ;
  END
 END n_lo_d[201]
 PIN n_lo_d[202]
  DIRECTION OUTPUT ;
  USE SIGNAL ;
  PORT
   LAYER M5 ;
   RECT 42.756000 112.236000 42.804000 112.320000 ;
  END
 END n_lo_d[202]
 PIN n_lo_d[203]
  DIRECTION OUTPUT ;
  USE SIGNAL ;
  PORT
   LAYER M5 ;
   RECT 42.900000 112.236000 42.948000 112.320000 ;
  END
 END n_lo_d[203]
 PIN n_lo_d[204]
  DIRECTION OUTPUT ;
  USE SIGNAL ;
  PORT
   LAYER M5 ;
   RECT 43.092000 112.236000 43.140000 112.320000 ;
  END
 END n_lo_d[204]
 PIN n_lo_d[205]
  DIRECTION OUTPUT ;
  USE SIGNAL ;
  PORT
   LAYER M5 ;
   RECT 43.284000 112.236000 43.332000 112.320000 ;
  END
 END n_lo_d[205]
 PIN n_lo_d[206]
  DIRECTION OUTPUT ;
  USE SIGNAL ;
  PORT
   LAYER M5 ;
   RECT 43.476000 112.236000 43.524000 112.320000 ;
  END
 END n_lo_d[206]
 PIN n_lo_d[207]
  DIRECTION OUTPUT ;
  USE SIGNAL ;
  PORT
   LAYER M5 ;
   RECT 43.620000 112.236000 43.668000 112.320000 ;
  END
 END n_lo_d[207]
 PIN n_lo_d[208]
  DIRECTION OUTPUT ;
  USE SIGNAL ;
  PORT
   LAYER M5 ;
   RECT 43.812000 112.236000 43.860000 112.320000 ;
  END
 END n_lo_d[208]
 PIN n_lo_d[209]
  DIRECTION OUTPUT ;
  USE SIGNAL ;
  PORT
   LAYER M5 ;
   RECT 44.004000 112.236000 44.052000 112.320000 ;
  END
 END n_lo_d[209]
 PIN n_lo_d[210]
  DIRECTION OUTPUT ;
  USE SIGNAL ;
  PORT
   LAYER M5 ;
   RECT 44.148000 112.236000 44.196000 112.320000 ;
  END
 END n_lo_d[210]
 PIN n_lo_d[211]
  DIRECTION OUTPUT ;
  USE SIGNAL ;
  PORT
   LAYER M5 ;
   RECT 44.340000 112.236000 44.388000 112.320000 ;
  END
 END n_lo_d[211]
 PIN n_lo_d[212]
  DIRECTION OUTPUT ;
  USE SIGNAL ;
  PORT
   LAYER M5 ;
   RECT 44.532000 112.236000 44.580000 112.320000 ;
  END
 END n_lo_d[212]
 PIN n_lo_d[213]
  DIRECTION OUTPUT ;
  USE SIGNAL ;
  PORT
   LAYER M5 ;
   RECT 44.724000 112.236000 44.772000 112.320000 ;
  END
 END n_lo_d[213]
 PIN n_lo_d[214]
  DIRECTION OUTPUT ;
  USE SIGNAL ;
  PORT
   LAYER M5 ;
   RECT 44.868000 112.236000 44.916000 112.320000 ;
  END
 END n_lo_d[214]
 PIN n_lo_d[215]
  DIRECTION OUTPUT ;
  USE SIGNAL ;
  PORT
   LAYER M5 ;
   RECT 45.060000 112.236000 45.108000 112.320000 ;
  END
 END n_lo_d[215]
 PIN n_lo_d[216]
  DIRECTION OUTPUT ;
  USE SIGNAL ;
  PORT
   LAYER M5 ;
   RECT 45.636000 112.236000 45.684000 112.320000 ;
  END
 END n_lo_d[216]
 PIN n_lo_d[217]
  DIRECTION OUTPUT ;
  USE SIGNAL ;
  PORT
   LAYER M5 ;
   RECT 45.684000 112.236000 45.732000 112.320000 ;
  END
 END n_lo_d[217]
 PIN n_lo_d[218]
  DIRECTION OUTPUT ;
  USE SIGNAL ;
  PORT
   LAYER M5 ;
   RECT 45.732000 112.236000 45.780000 112.320000 ;
  END
 END n_lo_d[218]
 PIN n_lo_d[219]
  DIRECTION OUTPUT ;
  USE SIGNAL ;
  PORT
   LAYER M5 ;
   RECT 45.780000 112.236000 45.828000 112.320000 ;
  END
 END n_lo_d[219]
 PIN n_lo_d[220]
  DIRECTION OUTPUT ;
  USE SIGNAL ;
  PORT
   LAYER M5 ;
   RECT 45.972000 112.236000 46.020000 112.320000 ;
  END
 END n_lo_d[220]
 PIN n_lo_d[221]
  DIRECTION OUTPUT ;
  USE SIGNAL ;
  PORT
   LAYER M5 ;
   RECT 46.164000 112.236000 46.212000 112.320000 ;
  END
 END n_lo_d[221]
 PIN n_lo_d[222]
  DIRECTION OUTPUT ;
  USE SIGNAL ;
  PORT
   LAYER M5 ;
   RECT 46.308000 112.236000 46.356000 112.320000 ;
  END
 END n_lo_d[222]
 PIN n_lo_d[223]
  DIRECTION OUTPUT ;
  USE SIGNAL ;
  PORT
   LAYER M5 ;
   RECT 46.500000 112.236000 46.548000 112.320000 ;
  END
 END n_lo_d[223]
 PIN n_lo_d[224]
  DIRECTION OUTPUT ;
  USE SIGNAL ;
  PORT
   LAYER M5 ;
   RECT 46.692000 112.236000 46.740000 112.320000 ;
  END
 END n_lo_d[224]
 PIN n_lo_d[225]
  DIRECTION OUTPUT ;
  USE SIGNAL ;
  PORT
   LAYER M5 ;
   RECT 46.884000 112.236000 46.932000 112.320000 ;
  END
 END n_lo_d[225]
 PIN n_lo_d[226]
  DIRECTION OUTPUT ;
  USE SIGNAL ;
  PORT
   LAYER M5 ;
   RECT 47.028000 112.236000 47.076000 112.320000 ;
  END
 END n_lo_d[226]
 PIN n_lo_d[227]
  DIRECTION OUTPUT ;
  USE SIGNAL ;
  PORT
   LAYER M5 ;
   RECT 47.220000 112.236000 47.268000 112.320000 ;
  END
 END n_lo_d[227]
 PIN n_lo_d[228]
  DIRECTION OUTPUT ;
  USE SIGNAL ;
  PORT
   LAYER M5 ;
   RECT 47.412000 112.236000 47.460000 112.320000 ;
  END
 END n_lo_d[228]
 PIN n_lo_d[229]
  DIRECTION OUTPUT ;
  USE SIGNAL ;
  PORT
   LAYER M5 ;
   RECT 47.604000 112.236000 47.652000 112.320000 ;
  END
 END n_lo_d[229]
 PIN n_lo_d[230]
  DIRECTION OUTPUT ;
  USE SIGNAL ;
  PORT
   LAYER M5 ;
   RECT 47.748000 112.236000 47.796000 112.320000 ;
  END
 END n_lo_d[230]
 PIN n_lo_d[231]
  DIRECTION OUTPUT ;
  USE SIGNAL ;
  PORT
   LAYER M5 ;
   RECT 47.940000 112.236000 47.988000 112.320000 ;
  END
 END n_lo_d[231]
 PIN n_lo_d[232]
  DIRECTION OUTPUT ;
  USE SIGNAL ;
  PORT
   LAYER M5 ;
   RECT 48.132000 112.236000 48.180000 112.320000 ;
  END
 END n_lo_d[232]
 PIN n_lo_d[233]
  DIRECTION OUTPUT ;
  USE SIGNAL ;
  PORT
   LAYER M5 ;
   RECT 48.324000 112.236000 48.372000 112.320000 ;
  END
 END n_lo_d[233]
 PIN n_lo_d[234]
  DIRECTION OUTPUT ;
  USE SIGNAL ;
  PORT
   LAYER M5 ;
   RECT 48.468000 112.236000 48.516000 112.320000 ;
  END
 END n_lo_d[234]
 PIN n_lo_d[235]
  DIRECTION OUTPUT ;
  USE SIGNAL ;
  PORT
   LAYER M5 ;
   RECT 48.660000 112.236000 48.708000 112.320000 ;
  END
 END n_lo_d[235]
 PIN n_lo_d[236]
  DIRECTION OUTPUT ;
  USE SIGNAL ;
  PORT
   LAYER M5 ;
   RECT 48.852000 112.236000 48.900000 112.320000 ;
  END
 END n_lo_d[236]
 PIN n_lo_d[237]
  DIRECTION OUTPUT ;
  USE SIGNAL ;
  PORT
   LAYER M5 ;
   RECT 49.044000 112.236000 49.092000 112.320000 ;
  END
 END n_lo_d[237]
 PIN n_lo_d[238]
  DIRECTION OUTPUT ;
  USE SIGNAL ;
  PORT
   LAYER M5 ;
   RECT 49.188000 112.236000 49.236000 112.320000 ;
  END
 END n_lo_d[238]
 PIN n_lo_d[239]
  DIRECTION OUTPUT ;
  USE SIGNAL ;
  PORT
   LAYER M5 ;
   RECT 49.380000 112.236000 49.428000 112.320000 ;
  END
 END n_lo_d[239]
 PIN n_lo_d[240]
  DIRECTION OUTPUT ;
  USE SIGNAL ;
  PORT
   LAYER M5 ;
   RECT 49.956000 112.236000 50.004000 112.320000 ;
  END
 END n_lo_d[240]
 PIN n_lo_d[241]
  DIRECTION OUTPUT ;
  USE SIGNAL ;
  PORT
   LAYER M5 ;
   RECT 50.004000 112.236000 50.052000 112.320000 ;
  END
 END n_lo_d[241]
 PIN n_lo_d[242]
  DIRECTION OUTPUT ;
  USE SIGNAL ;
  PORT
   LAYER M5 ;
   RECT 50.052000 112.236000 50.100000 112.320000 ;
  END
 END n_lo_d[242]
 PIN n_lo_d[243]
  DIRECTION OUTPUT ;
  USE SIGNAL ;
  PORT
   LAYER M5 ;
   RECT 50.100000 112.236000 50.148000 112.320000 ;
  END
 END n_lo_d[243]
 PIN n_lo_d[244]
  DIRECTION OUTPUT ;
  USE SIGNAL ;
  PORT
   LAYER M5 ;
   RECT 50.292000 112.236000 50.340000 112.320000 ;
  END
 END n_lo_d[244]
 PIN n_lo_d[245]
  DIRECTION OUTPUT ;
  USE SIGNAL ;
  PORT
   LAYER M5 ;
   RECT 50.484000 112.236000 50.532000 112.320000 ;
  END
 END n_lo_d[245]
 PIN n_lo_d[246]
  DIRECTION OUTPUT ;
  USE SIGNAL ;
  PORT
   LAYER M5 ;
   RECT 50.628000 112.236000 50.676000 112.320000 ;
  END
 END n_lo_d[246]
 PIN n_lo_d[247]
  DIRECTION OUTPUT ;
  USE SIGNAL ;
  PORT
   LAYER M5 ;
   RECT 50.820000 112.236000 50.868000 112.320000 ;
  END
 END n_lo_d[247]
 PIN n_lo_d[248]
  DIRECTION OUTPUT ;
  USE SIGNAL ;
  PORT
   LAYER M5 ;
   RECT 51.012000 112.236000 51.060000 112.320000 ;
  END
 END n_lo_d[248]
 PIN n_lo_d[249]
  DIRECTION OUTPUT ;
  USE SIGNAL ;
  PORT
   LAYER M5 ;
   RECT 51.204000 112.236000 51.252000 112.320000 ;
  END
 END n_lo_d[249]
 PIN n_lo_d[250]
  DIRECTION OUTPUT ;
  USE SIGNAL ;
  PORT
   LAYER M5 ;
   RECT 51.348000 112.236000 51.396000 112.320000 ;
  END
 END n_lo_d[250]
 PIN n_lo_d[251]
  DIRECTION OUTPUT ;
  USE SIGNAL ;
  PORT
   LAYER M5 ;
   RECT 51.540000 112.236000 51.588000 112.320000 ;
  END
 END n_lo_d[251]
 PIN n_lo_d[252]
  DIRECTION OUTPUT ;
  USE SIGNAL ;
  PORT
   LAYER M5 ;
   RECT 51.732000 112.236000 51.780000 112.320000 ;
  END
 END n_lo_d[252]
 PIN n_lo_d[253]
  DIRECTION OUTPUT ;
  USE SIGNAL ;
  PORT
   LAYER M5 ;
   RECT 51.924000 112.236000 51.972000 112.320000 ;
  END
 END n_lo_d[253]
 PIN n_lo_d[254]
  DIRECTION OUTPUT ;
  USE SIGNAL ;
  PORT
   LAYER M5 ;
   RECT 52.068000 112.236000 52.116000 112.320000 ;
  END
 END n_lo_d[254]
 PIN n_lo_d[255]
  DIRECTION OUTPUT ;
  USE SIGNAL ;
  PORT
   LAYER M5 ;
   RECT 52.260000 112.236000 52.308000 112.320000 ;
  END
 END n_lo_d[255]
 PIN n_lo_d[256]
  DIRECTION OUTPUT ;
  USE SIGNAL ;
  PORT
   LAYER M5 ;
   RECT 52.452000 112.236000 52.500000 112.320000 ;
  END
 END n_lo_d[256]
 PIN n_lo_d[257]
  DIRECTION OUTPUT ;
  USE SIGNAL ;
  PORT
   LAYER M5 ;
   RECT 52.644000 112.236000 52.692000 112.320000 ;
  END
 END n_lo_d[257]
 PIN n_lo_d[258]
  DIRECTION OUTPUT ;
  USE SIGNAL ;
  PORT
   LAYER M5 ;
   RECT 52.788000 112.236000 52.836000 112.320000 ;
  END
 END n_lo_d[258]
 PIN n_lo_d[259]
  DIRECTION OUTPUT ;
  USE SIGNAL ;
  PORT
   LAYER M5 ;
   RECT 52.980000 112.236000 53.028000 112.320000 ;
  END
 END n_lo_d[259]
 PIN n_lo_d[260]
  DIRECTION OUTPUT ;
  USE SIGNAL ;
  PORT
   LAYER M5 ;
   RECT 53.172000 112.236000 53.220000 112.320000 ;
  END
 END n_lo_d[260]
 PIN n_lo_d[261]
  DIRECTION OUTPUT ;
  USE SIGNAL ;
  PORT
   LAYER M5 ;
   RECT 53.364000 112.236000 53.412000 112.320000 ;
  END
 END n_lo_d[261]
 PIN n_lo_d[262]
  DIRECTION OUTPUT ;
  USE SIGNAL ;
  PORT
   LAYER M5 ;
   RECT 53.508000 112.236000 53.556000 112.320000 ;
  END
 END n_lo_d[262]
 PIN n_lo_d[263]
  DIRECTION OUTPUT ;
  USE SIGNAL ;
  PORT
   LAYER M5 ;
   RECT 53.700000 112.236000 53.748000 112.320000 ;
  END
 END n_lo_d[263]
 PIN n_lo_d[264]
  DIRECTION OUTPUT ;
  USE SIGNAL ;
  PORT
   LAYER M5 ;
   RECT 54.276000 112.236000 54.324000 112.320000 ;
  END
 END n_lo_d[264]
 PIN n_lo_d[265]
  DIRECTION OUTPUT ;
  USE SIGNAL ;
  PORT
   LAYER M5 ;
   RECT 54.324000 112.236000 54.372000 112.320000 ;
  END
 END n_lo_d[265]
 PIN n_lo_d[266]
  DIRECTION OUTPUT ;
  USE SIGNAL ;
  PORT
   LAYER M5 ;
   RECT 54.372000 112.236000 54.420000 112.320000 ;
  END
 END n_lo_d[266]
 PIN n_lo_d[267]
  DIRECTION OUTPUT ;
  USE SIGNAL ;
  PORT
   LAYER M5 ;
   RECT 54.420000 112.236000 54.468000 112.320000 ;
  END
 END n_lo_d[267]
 PIN n_lo_d[268]
  DIRECTION OUTPUT ;
  USE SIGNAL ;
  PORT
   LAYER M5 ;
   RECT 54.612000 112.236000 54.660000 112.320000 ;
  END
 END n_lo_d[268]
 PIN n_lo_d[269]
  DIRECTION OUTPUT ;
  USE SIGNAL ;
  PORT
   LAYER M5 ;
   RECT 54.804000 112.236000 54.852000 112.320000 ;
  END
 END n_lo_d[269]
 PIN n_lo_d[270]
  DIRECTION OUTPUT ;
  USE SIGNAL ;
  PORT
   LAYER M5 ;
   RECT 54.948000 112.236000 54.996000 112.320000 ;
  END
 END n_lo_d[270]
 PIN n_lo_d[271]
  DIRECTION OUTPUT ;
  USE SIGNAL ;
  PORT
   LAYER M5 ;
   RECT 55.140000 112.236000 55.188000 112.320000 ;
  END
 END n_lo_d[271]
 PIN n_lo_d[272]
  DIRECTION OUTPUT ;
  USE SIGNAL ;
  PORT
   LAYER M5 ;
   RECT 55.332000 112.236000 55.380000 112.320000 ;
  END
 END n_lo_d[272]
 PIN n_lo_d[273]
  DIRECTION OUTPUT ;
  USE SIGNAL ;
  PORT
   LAYER M5 ;
   RECT 55.524000 112.236000 55.572000 112.320000 ;
  END
 END n_lo_d[273]
 PIN n_lo_d[274]
  DIRECTION OUTPUT ;
  USE SIGNAL ;
  PORT
   LAYER M5 ;
   RECT 55.668000 112.236000 55.716000 112.320000 ;
  END
 END n_lo_d[274]
 PIN n_lo_d[275]
  DIRECTION OUTPUT ;
  USE SIGNAL ;
  PORT
   LAYER M5 ;
   RECT 55.860000 112.236000 55.908000 112.320000 ;
  END
 END n_lo_d[275]
 PIN n_lo_d[276]
  DIRECTION OUTPUT ;
  USE SIGNAL ;
  PORT
   LAYER M5 ;
   RECT 56.052000 112.236000 56.100000 112.320000 ;
  END
 END n_lo_d[276]
 PIN n_lo_d[277]
  DIRECTION OUTPUT ;
  USE SIGNAL ;
  PORT
   LAYER M5 ;
   RECT 56.244000 112.236000 56.292000 112.320000 ;
  END
 END n_lo_d[277]
 PIN n_lo_d[278]
  DIRECTION OUTPUT ;
  USE SIGNAL ;
  PORT
   LAYER M5 ;
   RECT 56.388000 112.236000 56.436000 112.320000 ;
  END
 END n_lo_d[278]
 PIN n_lo_d[279]
  DIRECTION OUTPUT ;
  USE SIGNAL ;
  PORT
   LAYER M5 ;
   RECT 56.580000 112.236000 56.628000 112.320000 ;
  END
 END n_lo_d[279]
 PIN n_lo_d[280]
  DIRECTION OUTPUT ;
  USE SIGNAL ;
  PORT
   LAYER M5 ;
   RECT 56.772000 112.236000 56.820000 112.320000 ;
  END
 END n_lo_d[280]
 PIN n_lo_d[281]
  DIRECTION OUTPUT ;
  USE SIGNAL ;
  PORT
   LAYER M5 ;
   RECT 56.964000 112.236000 57.012000 112.320000 ;
  END
 END n_lo_d[281]
 PIN n_lo_d[282]
  DIRECTION OUTPUT ;
  USE SIGNAL ;
  PORT
   LAYER M5 ;
   RECT 57.108000 112.236000 57.156000 112.320000 ;
  END
 END n_lo_d[282]
 PIN n_lo_d[283]
  DIRECTION OUTPUT ;
  USE SIGNAL ;
  PORT
   LAYER M5 ;
   RECT 57.300000 112.236000 57.348000 112.320000 ;
  END
 END n_lo_d[283]
 PIN n_lo_d[284]
  DIRECTION OUTPUT ;
  USE SIGNAL ;
  PORT
   LAYER M5 ;
   RECT 57.492000 112.236000 57.540000 112.320000 ;
  END
 END n_lo_d[284]
 PIN n_lo_d[285]
  DIRECTION OUTPUT ;
  USE SIGNAL ;
  PORT
   LAYER M5 ;
   RECT 57.684000 112.236000 57.732000 112.320000 ;
  END
 END n_lo_d[285]
 PIN n_lo_d[286]
  DIRECTION OUTPUT ;
  USE SIGNAL ;
  PORT
   LAYER M5 ;
   RECT 57.828000 112.236000 57.876000 112.320000 ;
  END
 END n_lo_d[286]
 PIN n_lo_d[287]
  DIRECTION OUTPUT ;
  USE SIGNAL ;
  PORT
   LAYER M5 ;
   RECT 57.924000 112.236000 57.972000 112.320000 ;
  END
 END n_lo_d[287]
 PIN n_lo_d[288]
  DIRECTION OUTPUT ;
  USE SIGNAL ;
  PORT
   LAYER M5 ;
   RECT 57.972000 112.236000 58.020000 112.320000 ;
  END
 END n_lo_d[288]
 PIN n_lo_d[289]
  DIRECTION OUTPUT ;
  USE SIGNAL ;
  PORT
   LAYER M5 ;
   RECT 58.020000 112.236000 58.068000 112.320000 ;
  END
 END n_lo_d[289]
 PIN n_lo_d[290]
  DIRECTION OUTPUT ;
  USE SIGNAL ;
  PORT
   LAYER M5 ;
   RECT 58.596000 112.236000 58.644000 112.320000 ;
  END
 END n_lo_d[290]
 PIN n_lo_d[291]
  DIRECTION OUTPUT ;
  USE SIGNAL ;
  PORT
   LAYER M5 ;
   RECT 58.740000 112.236000 58.788000 112.320000 ;
  END
 END n_lo_d[291]
 PIN n_lo_d[292]
  DIRECTION OUTPUT ;
  USE SIGNAL ;
  PORT
   LAYER M5 ;
   RECT 58.932000 112.236000 58.980000 112.320000 ;
  END
 END n_lo_d[292]
 PIN n_lo_d[293]
  DIRECTION OUTPUT ;
  USE SIGNAL ;
  PORT
   LAYER M5 ;
   RECT 59.124000 112.236000 59.172000 112.320000 ;
  END
 END n_lo_d[293]
 PIN n_lo_d[294]
  DIRECTION OUTPUT ;
  USE SIGNAL ;
  PORT
   LAYER M5 ;
   RECT 59.268000 112.236000 59.316000 112.320000 ;
  END
 END n_lo_d[294]
 PIN n_lo_d[295]
  DIRECTION OUTPUT ;
  USE SIGNAL ;
  PORT
   LAYER M5 ;
   RECT 59.460000 112.236000 59.508000 112.320000 ;
  END
 END n_lo_d[295]
 PIN n_lo_d[296]
  DIRECTION OUTPUT ;
  USE SIGNAL ;
  PORT
   LAYER M5 ;
   RECT 59.652000 112.236000 59.700000 112.320000 ;
  END
 END n_lo_d[296]
 PIN n_lo_d[297]
  DIRECTION OUTPUT ;
  USE SIGNAL ;
  PORT
   LAYER M5 ;
   RECT 59.844000 112.236000 59.892000 112.320000 ;
  END
 END n_lo_d[297]
 PIN n_lo_d[298]
  DIRECTION OUTPUT ;
  USE SIGNAL ;
  PORT
   LAYER M5 ;
   RECT 59.988000 112.236000 60.036000 112.320000 ;
  END
 END n_lo_d[298]
 PIN n_lo_d[299]
  DIRECTION OUTPUT ;
  USE SIGNAL ;
  PORT
   LAYER M5 ;
   RECT 60.180000 112.236000 60.228000 112.320000 ;
  END
 END n_lo_d[299]
 PIN n_lo_d[300]
  DIRECTION OUTPUT ;
  USE SIGNAL ;
  PORT
   LAYER M5 ;
   RECT 60.372000 112.236000 60.420000 112.320000 ;
  END
 END n_lo_d[300]
 PIN n_lo_d[301]
  DIRECTION OUTPUT ;
  USE SIGNAL ;
  PORT
   LAYER M5 ;
   RECT 60.564000 112.236000 60.612000 112.320000 ;
  END
 END n_lo_d[301]
 PIN n_lo_d[302]
  DIRECTION OUTPUT ;
  USE SIGNAL ;
  PORT
   LAYER M5 ;
   RECT 60.708000 112.236000 60.756000 112.320000 ;
  END
 END n_lo_d[302]
 PIN n_lo_d[303]
  DIRECTION OUTPUT ;
  USE SIGNAL ;
  PORT
   LAYER M5 ;
   RECT 60.900000 112.236000 60.948000 112.320000 ;
  END
 END n_lo_d[303]
 PIN n_lo_d[304]
  DIRECTION OUTPUT ;
  USE SIGNAL ;
  PORT
   LAYER M5 ;
   RECT 61.092000 112.236000 61.140000 112.320000 ;
  END
 END n_lo_d[304]
 PIN n_lo_d[305]
  DIRECTION OUTPUT ;
  USE SIGNAL ;
  PORT
   LAYER M5 ;
   RECT 61.284000 112.236000 61.332000 112.320000 ;
  END
 END n_lo_d[305]
 PIN n_lo_d[306]
  DIRECTION OUTPUT ;
  USE SIGNAL ;
  PORT
   LAYER M5 ;
   RECT 61.428000 112.236000 61.476000 112.320000 ;
  END
 END n_lo_d[306]
 PIN n_lo_d[307]
  DIRECTION OUTPUT ;
  USE SIGNAL ;
  PORT
   LAYER M5 ;
   RECT 61.620000 112.236000 61.668000 112.320000 ;
  END
 END n_lo_d[307]
 PIN n_lo_d[308]
  DIRECTION OUTPUT ;
  USE SIGNAL ;
  PORT
   LAYER M5 ;
   RECT 61.812000 112.236000 61.860000 112.320000 ;
  END
 END n_lo_d[308]
 PIN n_lo_d[309]
  DIRECTION OUTPUT ;
  USE SIGNAL ;
  PORT
   LAYER M5 ;
   RECT 62.004000 112.236000 62.052000 112.320000 ;
  END
 END n_lo_d[309]
 PIN n_lo_d[310]
  DIRECTION OUTPUT ;
  USE SIGNAL ;
  PORT
   LAYER M5 ;
   RECT 62.148000 112.236000 62.196000 112.320000 ;
  END
 END n_lo_d[310]
 PIN n_lo_d[311]
  DIRECTION OUTPUT ;
  USE SIGNAL ;
  PORT
   LAYER M5 ;
   RECT 62.244000 112.236000 62.292000 112.320000 ;
  END
 END n_lo_d[311]
 PIN n_lo_d[312]
  DIRECTION OUTPUT ;
  USE SIGNAL ;
  PORT
   LAYER M5 ;
   RECT 62.292000 112.236000 62.340000 112.320000 ;
  END
 END n_lo_d[312]
 PIN n_lo_d[313]
  DIRECTION OUTPUT ;
  USE SIGNAL ;
  PORT
   LAYER M5 ;
   RECT 62.340000 112.236000 62.388000 112.320000 ;
  END
 END n_lo_d[313]
 PIN n_lo_d[314]
  DIRECTION OUTPUT ;
  USE SIGNAL ;
  PORT
   LAYER M5 ;
   RECT 62.916000 112.236000 62.964000 112.320000 ;
  END
 END n_lo_d[314]
 PIN n_lo_d[315]
  DIRECTION OUTPUT ;
  USE SIGNAL ;
  PORT
   LAYER M5 ;
   RECT 63.060000 112.236000 63.108000 112.320000 ;
  END
 END n_lo_d[315]
 PIN n_lo_d[316]
  DIRECTION OUTPUT ;
  USE SIGNAL ;
  PORT
   LAYER M5 ;
   RECT 63.252000 112.236000 63.300000 112.320000 ;
  END
 END n_lo_d[316]
 PIN n_lo_d[317]
  DIRECTION OUTPUT ;
  USE SIGNAL ;
  PORT
   LAYER M5 ;
   RECT 63.444000 112.236000 63.492000 112.320000 ;
  END
 END n_lo_d[317]
 PIN n_lo_d[318]
  DIRECTION OUTPUT ;
  USE SIGNAL ;
  PORT
   LAYER M5 ;
   RECT 63.588000 112.236000 63.636000 112.320000 ;
  END
 END n_lo_d[318]
 PIN n_lo_d[319]
  DIRECTION OUTPUT ;
  USE SIGNAL ;
  PORT
   LAYER M5 ;
   RECT 63.780000 112.236000 63.828000 112.320000 ;
  END
 END n_lo_d[319]
 PIN n_lo_d[320]
  DIRECTION OUTPUT ;
  USE SIGNAL ;
  PORT
   LAYER M5 ;
   RECT 63.972000 112.236000 64.020000 112.320000 ;
  END
 END n_lo_d[320]
 PIN n_lo_d[321]
  DIRECTION OUTPUT ;
  USE SIGNAL ;
  PORT
   LAYER M5 ;
   RECT 64.164000 112.236000 64.212000 112.320000 ;
  END
 END n_lo_d[321]
 PIN n_lo_d[322]
  DIRECTION OUTPUT ;
  USE SIGNAL ;
  PORT
   LAYER M5 ;
   RECT 64.308000 112.236000 64.356000 112.320000 ;
  END
 END n_lo_d[322]
 PIN n_lo_d[323]
  DIRECTION OUTPUT ;
  USE SIGNAL ;
  PORT
   LAYER M5 ;
   RECT 64.500000 112.236000 64.548000 112.320000 ;
  END
 END n_lo_d[323]
 PIN n_lo_d[324]
  DIRECTION OUTPUT ;
  USE SIGNAL ;
  PORT
   LAYER M5 ;
   RECT 64.692000 112.236000 64.740000 112.320000 ;
  END
 END n_lo_d[324]
 PIN n_lo_d[325]
  DIRECTION OUTPUT ;
  USE SIGNAL ;
  PORT
   LAYER M5 ;
   RECT 64.884000 112.236000 64.932000 112.320000 ;
  END
 END n_lo_d[325]
 PIN n_lo_d[326]
  DIRECTION OUTPUT ;
  USE SIGNAL ;
  PORT
   LAYER M5 ;
   RECT 65.028000 112.236000 65.076000 112.320000 ;
  END
 END n_lo_d[326]
 PIN n_lo_d[327]
  DIRECTION OUTPUT ;
  USE SIGNAL ;
  PORT
   LAYER M5 ;
   RECT 65.220000 112.236000 65.268000 112.320000 ;
  END
 END n_lo_d[327]
 PIN n_lo_d[328]
  DIRECTION OUTPUT ;
  USE SIGNAL ;
  PORT
   LAYER M5 ;
   RECT 65.412000 112.236000 65.460000 112.320000 ;
  END
 END n_lo_d[328]
 PIN n_lo_d[329]
  DIRECTION OUTPUT ;
  USE SIGNAL ;
  PORT
   LAYER M5 ;
   RECT 65.604000 112.236000 65.652000 112.320000 ;
  END
 END n_lo_d[329]
 PIN n_lo_d[330]
  DIRECTION OUTPUT ;
  USE SIGNAL ;
  PORT
   LAYER M5 ;
   RECT 65.748000 112.236000 65.796000 112.320000 ;
  END
 END n_lo_d[330]
 PIN n_lo_d[331]
  DIRECTION OUTPUT ;
  USE SIGNAL ;
  PORT
   LAYER M5 ;
   RECT 65.940000 112.236000 65.988000 112.320000 ;
  END
 END n_lo_d[331]
 PIN n_lo_d[332]
  DIRECTION OUTPUT ;
  USE SIGNAL ;
  PORT
   LAYER M5 ;
   RECT 66.132000 112.236000 66.180000 112.320000 ;
  END
 END n_lo_d[332]
 PIN n_lo_d[333]
  DIRECTION OUTPUT ;
  USE SIGNAL ;
  PORT
   LAYER M5 ;
   RECT 66.324000 112.236000 66.372000 112.320000 ;
  END
 END n_lo_d[333]
 PIN n_lo_d[334]
  DIRECTION OUTPUT ;
  USE SIGNAL ;
  PORT
   LAYER M5 ;
   RECT 66.468000 112.236000 66.516000 112.320000 ;
  END
 END n_lo_d[334]
 PIN n_lo_d[335]
  DIRECTION OUTPUT ;
  USE SIGNAL ;
  PORT
   LAYER M5 ;
   RECT 66.564000 112.236000 66.612000 112.320000 ;
  END
 END n_lo_d[335]
 PIN n_lo_d[336]
  DIRECTION OUTPUT ;
  USE SIGNAL ;
  PORT
   LAYER M5 ;
   RECT 66.612000 112.236000 66.660000 112.320000 ;
  END
 END n_lo_d[336]
 PIN n_lo_d[337]
  DIRECTION OUTPUT ;
  USE SIGNAL ;
  PORT
   LAYER M5 ;
   RECT 66.660000 112.236000 66.708000 112.320000 ;
  END
 END n_lo_d[337]
 PIN n_lo_d[338]
  DIRECTION OUTPUT ;
  USE SIGNAL ;
  PORT
   LAYER M5 ;
   RECT 67.236000 112.236000 67.284000 112.320000 ;
  END
 END n_lo_d[338]
 PIN n_lo_d[339]
  DIRECTION OUTPUT ;
  USE SIGNAL ;
  PORT
   LAYER M5 ;
   RECT 67.380000 112.236000 67.428000 112.320000 ;
  END
 END n_lo_d[339]
 PIN n_lo_d[340]
  DIRECTION OUTPUT ;
  USE SIGNAL ;
  PORT
   LAYER M5 ;
   RECT 67.572000 112.236000 67.620000 112.320000 ;
  END
 END n_lo_d[340]
 PIN n_lo_d[341]
  DIRECTION OUTPUT ;
  USE SIGNAL ;
  PORT
   LAYER M5 ;
   RECT 67.764000 112.236000 67.812000 112.320000 ;
  END
 END n_lo_d[341]
 PIN n_lo_d[342]
  DIRECTION OUTPUT ;
  USE SIGNAL ;
  PORT
   LAYER M5 ;
   RECT 67.908000 112.236000 67.956000 112.320000 ;
  END
 END n_lo_d[342]
 PIN n_lo_d[343]
  DIRECTION OUTPUT ;
  USE SIGNAL ;
  PORT
   LAYER M5 ;
   RECT 68.100000 112.236000 68.148000 112.320000 ;
  END
 END n_lo_d[343]
 PIN n_lo_d[344]
  DIRECTION OUTPUT ;
  USE SIGNAL ;
  PORT
   LAYER M5 ;
   RECT 68.292000 112.236000 68.340000 112.320000 ;
  END
 END n_lo_d[344]
 PIN n_lo_d[345]
  DIRECTION OUTPUT ;
  USE SIGNAL ;
  PORT
   LAYER M5 ;
   RECT 68.484000 112.236000 68.532000 112.320000 ;
  END
 END n_lo_d[345]
 PIN n_lo_d[346]
  DIRECTION OUTPUT ;
  USE SIGNAL ;
  PORT
   LAYER M5 ;
   RECT 68.628000 112.236000 68.676000 112.320000 ;
  END
 END n_lo_d[346]
 PIN n_lo_d[347]
  DIRECTION OUTPUT ;
  USE SIGNAL ;
  PORT
   LAYER M5 ;
   RECT 68.820000 112.236000 68.868000 112.320000 ;
  END
 END n_lo_d[347]
 PIN n_lo_d[348]
  DIRECTION OUTPUT ;
  USE SIGNAL ;
  PORT
   LAYER M5 ;
   RECT 69.012000 112.236000 69.060000 112.320000 ;
  END
 END n_lo_d[348]
 PIN n_lo_d[349]
  DIRECTION OUTPUT ;
  USE SIGNAL ;
  PORT
   LAYER M5 ;
   RECT 69.156000 112.236000 69.204000 112.320000 ;
  END
 END n_lo_d[349]
 PIN n_lo_d[350]
  DIRECTION OUTPUT ;
  USE SIGNAL ;
  PORT
   LAYER M5 ;
   RECT 69.348000 112.236000 69.396000 112.320000 ;
  END
 END n_lo_d[350]
 PIN n_lo_d[351]
  DIRECTION OUTPUT ;
  USE SIGNAL ;
  PORT
   LAYER M5 ;
   RECT 69.540000 112.236000 69.588000 112.320000 ;
  END
 END n_lo_d[351]
 PIN n_lo_d[352]
  DIRECTION OUTPUT ;
  USE SIGNAL ;
  PORT
   LAYER M5 ;
   RECT 69.732000 112.236000 69.780000 112.320000 ;
  END
 END n_lo_d[352]
 PIN n_lo_d[353]
  DIRECTION OUTPUT ;
  USE SIGNAL ;
  PORT
   LAYER M5 ;
   RECT 69.876000 112.236000 69.924000 112.320000 ;
  END
 END n_lo_d[353]
 PIN n_lo_d[354]
  DIRECTION OUTPUT ;
  USE SIGNAL ;
  PORT
   LAYER M5 ;
   RECT 70.068000 112.236000 70.116000 112.320000 ;
  END
 END n_lo_d[354]
 PIN n_lo_d[355]
  DIRECTION OUTPUT ;
  USE SIGNAL ;
  PORT
   LAYER M5 ;
   RECT 70.260000 112.236000 70.308000 112.320000 ;
  END
 END n_lo_d[355]
 PIN n_lo_d[356]
  DIRECTION OUTPUT ;
  USE SIGNAL ;
  PORT
   LAYER M5 ;
   RECT 70.452000 112.236000 70.500000 112.320000 ;
  END
 END n_lo_d[356]
 PIN n_lo_d[357]
  DIRECTION OUTPUT ;
  USE SIGNAL ;
  PORT
   LAYER M5 ;
   RECT 70.596000 112.236000 70.644000 112.320000 ;
  END
 END n_lo_d[357]
 PIN n_lo_d[358]
  DIRECTION OUTPUT ;
  USE SIGNAL ;
  PORT
   LAYER M5 ;
   RECT 70.788000 112.236000 70.836000 112.320000 ;
  END
 END n_lo_d[358]
 PIN n_lo_d[359]
  DIRECTION OUTPUT ;
  USE SIGNAL ;
  PORT
   LAYER M5 ;
   RECT 70.884000 112.236000 70.932000 112.320000 ;
  END
 END n_lo_d[359]
 PIN n_lo_d[360]
  DIRECTION OUTPUT ;
  USE SIGNAL ;
  PORT
   LAYER M5 ;
   RECT 70.932000 112.236000 70.980000 112.320000 ;
  END
 END n_lo_d[360]
 PIN n_lo_d[361]
  DIRECTION OUTPUT ;
  USE SIGNAL ;
  PORT
   LAYER M5 ;
   RECT 70.980000 112.236000 71.028000 112.320000 ;
  END
 END n_lo_d[361]
 PIN n_lo_d[362]
  DIRECTION OUTPUT ;
  USE SIGNAL ;
  PORT
   LAYER M5 ;
   RECT 71.556000 112.236000 71.604000 112.320000 ;
  END
 END n_lo_d[362]
 PIN n_lo_d[363]
  DIRECTION OUTPUT ;
  USE SIGNAL ;
  PORT
   LAYER M5 ;
   RECT 71.700000 112.236000 71.748000 112.320000 ;
  END
 END n_lo_d[363]
 PIN n_lo_d[364]
  DIRECTION OUTPUT ;
  USE SIGNAL ;
  PORT
   LAYER M5 ;
   RECT 71.892000 112.236000 71.940000 112.320000 ;
  END
 END n_lo_d[364]
 PIN n_lo_d[365]
  DIRECTION OUTPUT ;
  USE SIGNAL ;
  PORT
   LAYER M5 ;
   RECT 72.036000 112.236000 72.084000 112.320000 ;
  END
 END n_lo_d[365]
 PIN n_lo_d[366]
  DIRECTION OUTPUT ;
  USE SIGNAL ;
  PORT
   LAYER M5 ;
   RECT 72.228000 112.236000 72.276000 112.320000 ;
  END
 END n_lo_d[366]
 PIN n_lo_d[367]
  DIRECTION OUTPUT ;
  USE SIGNAL ;
  PORT
   LAYER M5 ;
   RECT 72.420000 112.236000 72.468000 112.320000 ;
  END
 END n_lo_d[367]
 PIN n_lo_d[368]
  DIRECTION OUTPUT ;
  USE SIGNAL ;
  PORT
   LAYER M5 ;
   RECT 72.612000 112.236000 72.660000 112.320000 ;
  END
 END n_lo_d[368]
 PIN n_lo_d[369]
  DIRECTION OUTPUT ;
  USE SIGNAL ;
  PORT
   LAYER M5 ;
   RECT 72.756000 112.236000 72.804000 112.320000 ;
  END
 END n_lo_d[369]
 PIN n_lo_d[370]
  DIRECTION OUTPUT ;
  USE SIGNAL ;
  PORT
   LAYER M5 ;
   RECT 72.948000 112.236000 72.996000 112.320000 ;
  END
 END n_lo_d[370]
 PIN n_lo_d[371]
  DIRECTION OUTPUT ;
  USE SIGNAL ;
  PORT
   LAYER M5 ;
   RECT 73.140000 112.236000 73.188000 112.320000 ;
  END
 END n_lo_d[371]
 PIN n_lo_d[372]
  DIRECTION OUTPUT ;
  USE SIGNAL ;
  PORT
   LAYER M5 ;
   RECT 73.332000 112.236000 73.380000 112.320000 ;
  END
 END n_lo_d[372]
 PIN n_lo_d[373]
  DIRECTION OUTPUT ;
  USE SIGNAL ;
  PORT
   LAYER M5 ;
   RECT 73.476000 112.236000 73.524000 112.320000 ;
  END
 END n_lo_d[373]
 PIN n_lo_d[374]
  DIRECTION OUTPUT ;
  USE SIGNAL ;
  PORT
   LAYER M5 ;
   RECT 73.668000 112.236000 73.716000 112.320000 ;
  END
 END n_lo_d[374]
 PIN n_lo_d[375]
  DIRECTION OUTPUT ;
  USE SIGNAL ;
  PORT
   LAYER M5 ;
   RECT 73.860000 112.236000 73.908000 112.320000 ;
  END
 END n_lo_d[375]
 PIN n_lo_d[376]
  DIRECTION OUTPUT ;
  USE SIGNAL ;
  PORT
   LAYER M5 ;
   RECT 74.052000 112.236000 74.100000 112.320000 ;
  END
 END n_lo_d[376]
 PIN n_lo_d[377]
  DIRECTION OUTPUT ;
  USE SIGNAL ;
  PORT
   LAYER M5 ;
   RECT 74.196000 112.236000 74.244000 112.320000 ;
  END
 END n_lo_d[377]
 PIN n_lo_d[378]
  DIRECTION OUTPUT ;
  USE SIGNAL ;
  PORT
   LAYER M5 ;
   RECT 74.388000 112.236000 74.436000 112.320000 ;
  END
 END n_lo_d[378]
 PIN n_lo_d[379]
  DIRECTION OUTPUT ;
  USE SIGNAL ;
  PORT
   LAYER M5 ;
   RECT 74.580000 112.236000 74.628000 112.320000 ;
  END
 END n_lo_d[379]
 PIN n_lo_d[380]
  DIRECTION OUTPUT ;
  USE SIGNAL ;
  PORT
   LAYER M5 ;
   RECT 74.772000 112.236000 74.820000 112.320000 ;
  END
 END n_lo_d[380]
 PIN n_lo_d[381]
  DIRECTION OUTPUT ;
  USE SIGNAL ;
  PORT
   LAYER M5 ;
   RECT 74.916000 112.236000 74.964000 112.320000 ;
  END
 END n_lo_d[381]
 PIN n_lo_d[382]
  DIRECTION OUTPUT ;
  USE SIGNAL ;
  PORT
   LAYER M5 ;
   RECT 75.108000 112.236000 75.156000 112.320000 ;
  END
 END n_lo_d[382]
 PIN n_lo_d[383]
  DIRECTION OUTPUT ;
  USE SIGNAL ;
  PORT
   LAYER M5 ;
   RECT 75.204000 112.236000 75.252000 112.320000 ;
  END
 END n_lo_d[383]
 PIN n_lo_d[384]
  DIRECTION OUTPUT ;
  USE SIGNAL ;
  PORT
   LAYER M5 ;
   RECT 75.252000 112.236000 75.300000 112.320000 ;
  END
 END n_lo_d[384]
 PIN n_lo_d[385]
  DIRECTION OUTPUT ;
  USE SIGNAL ;
  PORT
   LAYER M5 ;
   RECT 75.300000 112.236000 75.348000 112.320000 ;
  END
 END n_lo_d[385]
 PIN n_lo_d[386]
  DIRECTION OUTPUT ;
  USE SIGNAL ;
  PORT
   LAYER M5 ;
   RECT 75.876000 112.236000 75.924000 112.320000 ;
  END
 END n_lo_d[386]
 PIN n_lo_d[387]
  DIRECTION OUTPUT ;
  USE SIGNAL ;
  PORT
   LAYER M5 ;
   RECT 76.020000 112.236000 76.068000 112.320000 ;
  END
 END n_lo_d[387]
 PIN n_lo_d[388]
  DIRECTION OUTPUT ;
  USE SIGNAL ;
  PORT
   LAYER M5 ;
   RECT 76.212000 112.236000 76.260000 112.320000 ;
  END
 END n_lo_d[388]
 PIN n_lo_d[389]
  DIRECTION OUTPUT ;
  USE SIGNAL ;
  PORT
   LAYER M5 ;
   RECT 76.356000 112.236000 76.404000 112.320000 ;
  END
 END n_lo_d[389]
 PIN n_lo_d[390]
  DIRECTION OUTPUT ;
  USE SIGNAL ;
  PORT
   LAYER M5 ;
   RECT 76.548000 112.236000 76.596000 112.320000 ;
  END
 END n_lo_d[390]
 PIN n_lo_d[391]
  DIRECTION OUTPUT ;
  USE SIGNAL ;
  PORT
   LAYER M5 ;
   RECT 76.740000 112.236000 76.788000 112.320000 ;
  END
 END n_lo_d[391]
 PIN n_lo_d[392]
  DIRECTION OUTPUT ;
  USE SIGNAL ;
  PORT
   LAYER M5 ;
   RECT 76.932000 112.236000 76.980000 112.320000 ;
  END
 END n_lo_d[392]
 PIN n_lo_d[393]
  DIRECTION OUTPUT ;
  USE SIGNAL ;
  PORT
   LAYER M5 ;
   RECT 77.076000 112.236000 77.124000 112.320000 ;
  END
 END n_lo_d[393]
 PIN n_lo_d[394]
  DIRECTION OUTPUT ;
  USE SIGNAL ;
  PORT
   LAYER M5 ;
   RECT 77.268000 112.236000 77.316000 112.320000 ;
  END
 END n_lo_d[394]
 PIN n_lo_d[395]
  DIRECTION OUTPUT ;
  USE SIGNAL ;
  PORT
   LAYER M5 ;
   RECT 77.460000 112.236000 77.508000 112.320000 ;
  END
 END n_lo_d[395]
 PIN n_lo_d[396]
  DIRECTION OUTPUT ;
  USE SIGNAL ;
  PORT
   LAYER M5 ;
   RECT 77.652000 112.236000 77.700000 112.320000 ;
  END
 END n_lo_d[396]
 PIN n_lo_d[397]
  DIRECTION OUTPUT ;
  USE SIGNAL ;
  PORT
   LAYER M5 ;
   RECT 77.796000 112.236000 77.844000 112.320000 ;
  END
 END n_lo_d[397]
 PIN n_lo_d[398]
  DIRECTION OUTPUT ;
  USE SIGNAL ;
  PORT
   LAYER M5 ;
   RECT 77.988000 112.236000 78.036000 112.320000 ;
  END
 END n_lo_d[398]
 PIN n_lo_d[399]
  DIRECTION OUTPUT ;
  USE SIGNAL ;
  PORT
   LAYER M5 ;
   RECT 78.180000 112.236000 78.228000 112.320000 ;
  END
 END n_lo_d[399]
 PIN n_lo_d[400]
  DIRECTION OUTPUT ;
  USE SIGNAL ;
  PORT
   LAYER M5 ;
   RECT 78.372000 112.236000 78.420000 112.320000 ;
  END
 END n_lo_d[400]
 PIN n_lo_d[401]
  DIRECTION OUTPUT ;
  USE SIGNAL ;
  PORT
   LAYER M5 ;
   RECT 78.516000 112.236000 78.564000 112.320000 ;
  END
 END n_lo_d[401]
 PIN n_lo_d[402]
  DIRECTION OUTPUT ;
  USE SIGNAL ;
  PORT
   LAYER M5 ;
   RECT 78.708000 112.236000 78.756000 112.320000 ;
  END
 END n_lo_d[402]
 PIN n_lo_d[403]
  DIRECTION OUTPUT ;
  USE SIGNAL ;
  PORT
   LAYER M5 ;
   RECT 78.900000 112.236000 78.948000 112.320000 ;
  END
 END n_lo_d[403]
 PIN n_lo_d[404]
  DIRECTION OUTPUT ;
  USE SIGNAL ;
  PORT
   LAYER M5 ;
   RECT 79.092000 112.236000 79.140000 112.320000 ;
  END
 END n_lo_d[404]
 PIN n_lo_d[405]
  DIRECTION OUTPUT ;
  USE SIGNAL ;
  PORT
   LAYER M5 ;
   RECT 79.236000 112.236000 79.284000 112.320000 ;
  END
 END n_lo_d[405]
 PIN n_lo_d[406]
  DIRECTION OUTPUT ;
  USE SIGNAL ;
  PORT
   LAYER M5 ;
   RECT 79.428000 112.236000 79.476000 112.320000 ;
  END
 END n_lo_d[406]
 PIN n_lo_d[407]
  DIRECTION OUTPUT ;
  USE SIGNAL ;
  PORT
   LAYER M5 ;
   RECT 79.524000 112.236000 79.572000 112.320000 ;
  END
 END n_lo_d[407]
 PIN n_lo_d[408]
  DIRECTION OUTPUT ;
  USE SIGNAL ;
  PORT
   LAYER M5 ;
   RECT 79.572000 112.236000 79.620000 112.320000 ;
  END
 END n_lo_d[408]
 PIN n_lo_d[409]
  DIRECTION OUTPUT ;
  USE SIGNAL ;
  PORT
   LAYER M5 ;
   RECT 79.620000 112.236000 79.668000 112.320000 ;
  END
 END n_lo_d[409]
 PIN n_lo_d[410]
  DIRECTION OUTPUT ;
  USE SIGNAL ;
  PORT
   LAYER M5 ;
   RECT 80.196000 112.236000 80.244000 112.320000 ;
  END
 END n_lo_d[410]
 PIN n_lo_d[411]
  DIRECTION OUTPUT ;
  USE SIGNAL ;
  PORT
   LAYER M5 ;
   RECT 80.340000 112.236000 80.388000 112.320000 ;
  END
 END n_lo_d[411]
 PIN n_lo_d[412]
  DIRECTION OUTPUT ;
  USE SIGNAL ;
  PORT
   LAYER M5 ;
   RECT 80.532000 112.236000 80.580000 112.320000 ;
  END
 END n_lo_d[412]
 PIN n_lo_d[413]
  DIRECTION OUTPUT ;
  USE SIGNAL ;
  PORT
   LAYER M5 ;
   RECT 80.676000 112.236000 80.724000 112.320000 ;
  END
 END n_lo_d[413]
 PIN n_lo_d[414]
  DIRECTION OUTPUT ;
  USE SIGNAL ;
  PORT
   LAYER M5 ;
   RECT 80.868000 112.236000 80.916000 112.320000 ;
  END
 END n_lo_d[414]
 PIN n_lo_d[415]
  DIRECTION OUTPUT ;
  USE SIGNAL ;
  PORT
   LAYER M5 ;
   RECT 81.060000 112.236000 81.108000 112.320000 ;
  END
 END n_lo_d[415]
 PIN n_lo_d[416]
  DIRECTION OUTPUT ;
  USE SIGNAL ;
  PORT
   LAYER M5 ;
   RECT 81.252000 112.236000 81.300000 112.320000 ;
  END
 END n_lo_d[416]
 PIN n_lo_d[417]
  DIRECTION OUTPUT ;
  USE SIGNAL ;
  PORT
   LAYER M5 ;
   RECT 81.396000 112.236000 81.444000 112.320000 ;
  END
 END n_lo_d[417]
 PIN n_lo_d[418]
  DIRECTION OUTPUT ;
  USE SIGNAL ;
  PORT
   LAYER M5 ;
   RECT 81.588000 112.236000 81.636000 112.320000 ;
  END
 END n_lo_d[418]
 PIN n_lo_d[419]
  DIRECTION OUTPUT ;
  USE SIGNAL ;
  PORT
   LAYER M5 ;
   RECT 81.780000 112.236000 81.828000 112.320000 ;
  END
 END n_lo_d[419]
 PIN n_lo_d[420]
  DIRECTION OUTPUT ;
  USE SIGNAL ;
  PORT
   LAYER M5 ;
   RECT 81.972000 112.236000 82.020000 112.320000 ;
  END
 END n_lo_d[420]
 PIN n_lo_d[421]
  DIRECTION OUTPUT ;
  USE SIGNAL ;
  PORT
   LAYER M5 ;
   RECT 82.116000 112.236000 82.164000 112.320000 ;
  END
 END n_lo_d[421]
 PIN n_lo_d[422]
  DIRECTION OUTPUT ;
  USE SIGNAL ;
  PORT
   LAYER M5 ;
   RECT 82.308000 112.236000 82.356000 112.320000 ;
  END
 END n_lo_d[422]
 PIN n_lo_d[423]
  DIRECTION OUTPUT ;
  USE SIGNAL ;
  PORT
   LAYER M5 ;
   RECT 82.500000 112.236000 82.548000 112.320000 ;
  END
 END n_lo_d[423]
 PIN n_lo_d[424]
  DIRECTION OUTPUT ;
  USE SIGNAL ;
  PORT
   LAYER M5 ;
   RECT 82.692000 112.236000 82.740000 112.320000 ;
  END
 END n_lo_d[424]
 PIN n_lo_d[425]
  DIRECTION OUTPUT ;
  USE SIGNAL ;
  PORT
   LAYER M5 ;
   RECT 82.836000 112.236000 82.884000 112.320000 ;
  END
 END n_lo_d[425]
 PIN n_lo_d[426]
  DIRECTION OUTPUT ;
  USE SIGNAL ;
  PORT
   LAYER M5 ;
   RECT 83.028000 112.236000 83.076000 112.320000 ;
  END
 END n_lo_d[426]
 PIN n_lo_d[427]
  DIRECTION OUTPUT ;
  USE SIGNAL ;
  PORT
   LAYER M5 ;
   RECT 83.220000 112.236000 83.268000 112.320000 ;
  END
 END n_lo_d[427]
 PIN n_lo_d[428]
  DIRECTION OUTPUT ;
  USE SIGNAL ;
  PORT
   LAYER M5 ;
   RECT 83.412000 112.236000 83.460000 112.320000 ;
  END
 END n_lo_d[428]
 PIN n_lo_d[429]
  DIRECTION OUTPUT ;
  USE SIGNAL ;
  PORT
   LAYER M5 ;
   RECT 83.556000 112.236000 83.604000 112.320000 ;
  END
 END n_lo_d[429]
 PIN n_lo_d[430]
  DIRECTION OUTPUT ;
  USE SIGNAL ;
  PORT
   LAYER M5 ;
   RECT 83.748000 112.236000 83.796000 112.320000 ;
  END
 END n_lo_d[430]
 PIN n_lo_d[431]
  DIRECTION OUTPUT ;
  USE SIGNAL ;
  PORT
   LAYER M5 ;
   RECT 83.844000 112.236000 83.892000 112.320000 ;
  END
 END n_lo_d[431]
 PIN n_lo_d[432]
  DIRECTION OUTPUT ;
  USE SIGNAL ;
  PORT
   LAYER M5 ;
   RECT 83.892000 112.236000 83.940000 112.320000 ;
  END
 END n_lo_d[432]
 PIN n_lo_d[433]
  DIRECTION OUTPUT ;
  USE SIGNAL ;
  PORT
   LAYER M5 ;
   RECT 83.940000 112.236000 83.988000 112.320000 ;
  END
 END n_lo_d[433]
 PIN n_lo_d[434]
  DIRECTION OUTPUT ;
  USE SIGNAL ;
  PORT
   LAYER M5 ;
   RECT 84.516000 112.236000 84.564000 112.320000 ;
  END
 END n_lo_d[434]
 PIN n_lo_d[435]
  DIRECTION OUTPUT ;
  USE SIGNAL ;
  PORT
   LAYER M5 ;
   RECT 84.660000 112.236000 84.708000 112.320000 ;
  END
 END n_lo_d[435]
 PIN n_lo_d[436]
  DIRECTION OUTPUT ;
  USE SIGNAL ;
  PORT
   LAYER M5 ;
   RECT 84.852000 112.236000 84.900000 112.320000 ;
  END
 END n_lo_d[436]
 PIN n_lo_d[437]
  DIRECTION OUTPUT ;
  USE SIGNAL ;
  PORT
   LAYER M5 ;
   RECT 84.996000 112.236000 85.044000 112.320000 ;
  END
 END n_lo_d[437]
 PIN n_lo_d[438]
  DIRECTION OUTPUT ;
  USE SIGNAL ;
  PORT
   LAYER M5 ;
   RECT 85.188000 112.236000 85.236000 112.320000 ;
  END
 END n_lo_d[438]
 PIN n_lo_d[439]
  DIRECTION OUTPUT ;
  USE SIGNAL ;
  PORT
   LAYER M5 ;
   RECT 85.380000 112.236000 85.428000 112.320000 ;
  END
 END n_lo_d[439]
 PIN n_lo_d[440]
  DIRECTION OUTPUT ;
  USE SIGNAL ;
  PORT
   LAYER M5 ;
   RECT 85.572000 112.236000 85.620000 112.320000 ;
  END
 END n_lo_d[440]
 PIN n_lo_d[441]
  DIRECTION OUTPUT ;
  USE SIGNAL ;
  PORT
   LAYER M5 ;
   RECT 85.716000 112.236000 85.764000 112.320000 ;
  END
 END n_lo_d[441]
 PIN n_lo_d[442]
  DIRECTION OUTPUT ;
  USE SIGNAL ;
  PORT
   LAYER M5 ;
   RECT 85.908000 112.236000 85.956000 112.320000 ;
  END
 END n_lo_d[442]
 PIN n_lo_d[443]
  DIRECTION OUTPUT ;
  USE SIGNAL ;
  PORT
   LAYER M5 ;
   RECT 86.100000 112.236000 86.148000 112.320000 ;
  END
 END n_lo_d[443]
 PIN n_lo_d[444]
  DIRECTION OUTPUT ;
  USE SIGNAL ;
  PORT
   LAYER M5 ;
   RECT 86.292000 112.236000 86.340000 112.320000 ;
  END
 END n_lo_d[444]
 PIN n_lo_d[445]
  DIRECTION OUTPUT ;
  USE SIGNAL ;
  PORT
   LAYER M5 ;
   RECT 86.436000 112.236000 86.484000 112.320000 ;
  END
 END n_lo_d[445]
 PIN n_lo_d[446]
  DIRECTION OUTPUT ;
  USE SIGNAL ;
  PORT
   LAYER M5 ;
   RECT 86.628000 112.236000 86.676000 112.320000 ;
  END
 END n_lo_d[446]
 PIN n_lo_d[447]
  DIRECTION OUTPUT ;
  USE SIGNAL ;
  PORT
   LAYER M5 ;
   RECT 86.820000 112.236000 86.868000 112.320000 ;
  END
 END n_lo_d[447]
 PIN n_lo_d[448]
  DIRECTION OUTPUT ;
  USE SIGNAL ;
  PORT
   LAYER M5 ;
   RECT 87.012000 112.236000 87.060000 112.320000 ;
  END
 END n_lo_d[448]
 PIN n_lo_d[449]
  DIRECTION OUTPUT ;
  USE SIGNAL ;
  PORT
   LAYER M5 ;
   RECT 87.156000 112.236000 87.204000 112.320000 ;
  END
 END n_lo_d[449]
 PIN n_lo_d[450]
  DIRECTION OUTPUT ;
  USE SIGNAL ;
  PORT
   LAYER M5 ;
   RECT 87.348000 112.236000 87.396000 112.320000 ;
  END
 END n_lo_d[450]
 PIN n_lo_d[451]
  DIRECTION OUTPUT ;
  USE SIGNAL ;
  PORT
   LAYER M5 ;
   RECT 87.540000 112.236000 87.588000 112.320000 ;
  END
 END n_lo_d[451]
 PIN n_lo_d[452]
  DIRECTION OUTPUT ;
  USE SIGNAL ;
  PORT
   LAYER M5 ;
   RECT 87.732000 112.236000 87.780000 112.320000 ;
  END
 END n_lo_d[452]
 PIN n_lo_d[453]
  DIRECTION OUTPUT ;
  USE SIGNAL ;
  PORT
   LAYER M5 ;
   RECT 87.876000 112.236000 87.924000 112.320000 ;
  END
 END n_lo_d[453]
 PIN n_lo_d[454]
  DIRECTION OUTPUT ;
  USE SIGNAL ;
  PORT
   LAYER M5 ;
   RECT 88.068000 112.236000 88.116000 112.320000 ;
  END
 END n_lo_d[454]
 PIN n_lo_d[455]
  DIRECTION OUTPUT ;
  USE SIGNAL ;
  PORT
   LAYER M5 ;
   RECT 88.164000 112.236000 88.212000 112.320000 ;
  END
 END n_lo_d[455]
 PIN n_lo_d[456]
  DIRECTION OUTPUT ;
  USE SIGNAL ;
  PORT
   LAYER M5 ;
   RECT 88.212000 112.236000 88.260000 112.320000 ;
  END
 END n_lo_d[456]
 PIN n_lo_d[457]
  DIRECTION OUTPUT ;
  USE SIGNAL ;
  PORT
   LAYER M5 ;
   RECT 88.260000 112.236000 88.308000 112.320000 ;
  END
 END n_lo_d[457]
 PIN n_lo_d[458]
  DIRECTION OUTPUT ;
  USE SIGNAL ;
  PORT
   LAYER M5 ;
   RECT 88.836000 112.236000 88.884000 112.320000 ;
  END
 END n_lo_d[458]
 PIN n_lo_d[459]
  DIRECTION OUTPUT ;
  USE SIGNAL ;
  PORT
   LAYER M5 ;
   RECT 88.980000 112.236000 89.028000 112.320000 ;
  END
 END n_lo_d[459]
 PIN n_lo_d[460]
  DIRECTION OUTPUT ;
  USE SIGNAL ;
  PORT
   LAYER M5 ;
   RECT 89.172000 112.236000 89.220000 112.320000 ;
  END
 END n_lo_d[460]
 PIN n_lo_d[461]
  DIRECTION OUTPUT ;
  USE SIGNAL ;
  PORT
   LAYER M5 ;
   RECT 89.316000 112.236000 89.364000 112.320000 ;
  END
 END n_lo_d[461]
 PIN n_lo_d[462]
  DIRECTION OUTPUT ;
  USE SIGNAL ;
  PORT
   LAYER M5 ;
   RECT 89.508000 112.236000 89.556000 112.320000 ;
  END
 END n_lo_d[462]
 PIN n_lo_d[463]
  DIRECTION OUTPUT ;
  USE SIGNAL ;
  PORT
   LAYER M5 ;
   RECT 89.700000 112.236000 89.748000 112.320000 ;
  END
 END n_lo_d[463]
 PIN n_lo_d[464]
  DIRECTION OUTPUT ;
  USE SIGNAL ;
  PORT
   LAYER M5 ;
   RECT 89.892000 112.236000 89.940000 112.320000 ;
  END
 END n_lo_d[464]
 PIN n_lo_d[465]
  DIRECTION OUTPUT ;
  USE SIGNAL ;
  PORT
   LAYER M5 ;
   RECT 90.036000 112.236000 90.084000 112.320000 ;
  END
 END n_lo_d[465]
 PIN n_lo_d[466]
  DIRECTION OUTPUT ;
  USE SIGNAL ;
  PORT
   LAYER M5 ;
   RECT 90.228000 112.236000 90.276000 112.320000 ;
  END
 END n_lo_d[466]
 PIN n_lo_d[467]
  DIRECTION OUTPUT ;
  USE SIGNAL ;
  PORT
   LAYER M5 ;
   RECT 90.420000 112.236000 90.468000 112.320000 ;
  END
 END n_lo_d[467]
 PIN n_lo_d[468]
  DIRECTION OUTPUT ;
  USE SIGNAL ;
  PORT
   LAYER M5 ;
   RECT 90.612000 112.236000 90.660000 112.320000 ;
  END
 END n_lo_d[468]
 PIN n_lo_d[469]
  DIRECTION OUTPUT ;
  USE SIGNAL ;
  PORT
   LAYER M5 ;
   RECT 90.756000 112.236000 90.804000 112.320000 ;
  END
 END n_lo_d[469]
 PIN n_lo_d[470]
  DIRECTION OUTPUT ;
  USE SIGNAL ;
  PORT
   LAYER M5 ;
   RECT 90.948000 112.236000 90.996000 112.320000 ;
  END
 END n_lo_d[470]
 PIN n_lo_d[471]
  DIRECTION OUTPUT ;
  USE SIGNAL ;
  PORT
   LAYER M5 ;
   RECT 91.140000 112.236000 91.188000 112.320000 ;
  END
 END n_lo_d[471]
 PIN n_lo_d[472]
  DIRECTION OUTPUT ;
  USE SIGNAL ;
  PORT
   LAYER M5 ;
   RECT 91.332000 112.236000 91.380000 112.320000 ;
  END
 END n_lo_d[472]
 PIN n_lo_d[473]
  DIRECTION OUTPUT ;
  USE SIGNAL ;
  PORT
   LAYER M5 ;
   RECT 91.476000 112.236000 91.524000 112.320000 ;
  END
 END n_lo_d[473]
 PIN n_lo_d[474]
  DIRECTION OUTPUT ;
  USE SIGNAL ;
  PORT
   LAYER M5 ;
   RECT 91.668000 112.236000 91.716000 112.320000 ;
  END
 END n_lo_d[474]
 PIN n_lo_d[475]
  DIRECTION OUTPUT ;
  USE SIGNAL ;
  PORT
   LAYER M5 ;
   RECT 91.860000 112.236000 91.908000 112.320000 ;
  END
 END n_lo_d[475]
 PIN n_lo_d[476]
  DIRECTION OUTPUT ;
  USE SIGNAL ;
  PORT
   LAYER M5 ;
   RECT 92.052000 112.236000 92.100000 112.320000 ;
  END
 END n_lo_d[476]
 PIN n_lo_d[477]
  DIRECTION OUTPUT ;
  USE SIGNAL ;
  PORT
   LAYER M5 ;
   RECT 92.196000 112.236000 92.244000 112.320000 ;
  END
 END n_lo_d[477]
 PIN n_lo_d[478]
  DIRECTION OUTPUT ;
  USE SIGNAL ;
  PORT
   LAYER M5 ;
   RECT 92.388000 112.236000 92.436000 112.320000 ;
  END
 END n_lo_d[478]
 PIN n_lo_d[479]
  DIRECTION OUTPUT ;
  USE SIGNAL ;
  PORT
   LAYER M5 ;
   RECT 92.484000 112.236000 92.532000 112.320000 ;
  END
 END n_lo_d[479]
 PIN n_lo_d[480]
  DIRECTION OUTPUT ;
  USE SIGNAL ;
  PORT
   LAYER M5 ;
   RECT 92.532000 112.236000 92.580000 112.320000 ;
  END
 END n_lo_d[480]
 PIN n_lo_d[481]
  DIRECTION OUTPUT ;
  USE SIGNAL ;
  PORT
   LAYER M5 ;
   RECT 92.580000 112.236000 92.628000 112.320000 ;
  END
 END n_lo_d[481]
 PIN n_lo_d[482]
  DIRECTION OUTPUT ;
  USE SIGNAL ;
  PORT
   LAYER M5 ;
   RECT 93.156000 112.236000 93.204000 112.320000 ;
  END
 END n_lo_d[482]
 PIN n_lo_d[483]
  DIRECTION OUTPUT ;
  USE SIGNAL ;
  PORT
   LAYER M5 ;
   RECT 93.300000 112.236000 93.348000 112.320000 ;
  END
 END n_lo_d[483]
 PIN n_lo_d[484]
  DIRECTION OUTPUT ;
  USE SIGNAL ;
  PORT
   LAYER M5 ;
   RECT 93.492000 112.236000 93.540000 112.320000 ;
  END
 END n_lo_d[484]
 PIN n_lo_d[485]
  DIRECTION OUTPUT ;
  USE SIGNAL ;
  PORT
   LAYER M5 ;
   RECT 93.636000 112.236000 93.684000 112.320000 ;
  END
 END n_lo_d[485]
 PIN n_lo_d[486]
  DIRECTION OUTPUT ;
  USE SIGNAL ;
  PORT
   LAYER M5 ;
   RECT 93.828000 112.236000 93.876000 112.320000 ;
  END
 END n_lo_d[486]
 PIN n_lo_d[487]
  DIRECTION OUTPUT ;
  USE SIGNAL ;
  PORT
   LAYER M5 ;
   RECT 94.020000 112.236000 94.068000 112.320000 ;
  END
 END n_lo_d[487]
 PIN n_lo_d[488]
  DIRECTION OUTPUT ;
  USE SIGNAL ;
  PORT
   LAYER M5 ;
   RECT 94.164000 112.236000 94.212000 112.320000 ;
  END
 END n_lo_d[488]
 PIN n_lo_d[489]
  DIRECTION OUTPUT ;
  USE SIGNAL ;
  PORT
   LAYER M5 ;
   RECT 94.356000 112.236000 94.404000 112.320000 ;
  END
 END n_lo_d[489]
 PIN n_lo_d[490]
  DIRECTION OUTPUT ;
  USE SIGNAL ;
  PORT
   LAYER M5 ;
   RECT 94.548000 112.236000 94.596000 112.320000 ;
  END
 END n_lo_d[490]
 PIN n_lo_d[491]
  DIRECTION OUTPUT ;
  USE SIGNAL ;
  PORT
   LAYER M5 ;
   RECT 94.740000 112.236000 94.788000 112.320000 ;
  END
 END n_lo_d[491]
 PIN n_lo_d[492]
  DIRECTION OUTPUT ;
  USE SIGNAL ;
  PORT
   LAYER M5 ;
   RECT 94.884000 112.236000 94.932000 112.320000 ;
  END
 END n_lo_d[492]
 PIN n_lo_d[493]
  DIRECTION OUTPUT ;
  USE SIGNAL ;
  PORT
   LAYER M5 ;
   RECT 95.076000 112.236000 95.124000 112.320000 ;
  END
 END n_lo_d[493]
 PIN n_lo_d[494]
  DIRECTION OUTPUT ;
  USE SIGNAL ;
  PORT
   LAYER M5 ;
   RECT 95.268000 112.236000 95.316000 112.320000 ;
  END
 END n_lo_d[494]
 PIN n_lo_d[495]
  DIRECTION OUTPUT ;
  USE SIGNAL ;
  PORT
   LAYER M5 ;
   RECT 95.460000 112.236000 95.508000 112.320000 ;
  END
 END n_lo_d[495]
 PIN n_lo_d[496]
  DIRECTION OUTPUT ;
  USE SIGNAL ;
  PORT
   LAYER M5 ;
   RECT 95.604000 112.236000 95.652000 112.320000 ;
  END
 END n_lo_d[496]
 PIN n_lo_d[497]
  DIRECTION OUTPUT ;
  USE SIGNAL ;
  PORT
   LAYER M5 ;
   RECT 95.796000 112.236000 95.844000 112.320000 ;
  END
 END n_lo_d[497]
 PIN n_lo_d[498]
  DIRECTION OUTPUT ;
  USE SIGNAL ;
  PORT
   LAYER M5 ;
   RECT 95.988000 112.236000 96.036000 112.320000 ;
  END
 END n_lo_d[498]
 PIN n_lo_d[499]
  DIRECTION OUTPUT ;
  USE SIGNAL ;
  PORT
   LAYER M5 ;
   RECT 96.180000 112.236000 96.228000 112.320000 ;
  END
 END n_lo_d[499]
 PIN n_lo_d[500]
  DIRECTION OUTPUT ;
  USE SIGNAL ;
  PORT
   LAYER M5 ;
   RECT 96.324000 112.236000 96.372000 112.320000 ;
  END
 END n_lo_d[500]
 PIN n_lo_d[501]
  DIRECTION OUTPUT ;
  USE SIGNAL ;
  PORT
   LAYER M5 ;
   RECT 96.516000 112.236000 96.564000 112.320000 ;
  END
 END n_lo_d[501]
 PIN n_lo_d[502]
  DIRECTION OUTPUT ;
  USE SIGNAL ;
  PORT
   LAYER M5 ;
   RECT 96.708000 112.236000 96.756000 112.320000 ;
  END
 END n_lo_d[502]
 PIN n_lo_d[503]
  DIRECTION OUTPUT ;
  USE SIGNAL ;
  PORT
   LAYER M5 ;
   RECT 96.804000 112.236000 96.852000 112.320000 ;
  END
 END n_lo_d[503]
 PIN n_lo_d[504]
  DIRECTION OUTPUT ;
  USE SIGNAL ;
  PORT
   LAYER M5 ;
   RECT 96.852000 112.236000 96.900000 112.320000 ;
  END
 END n_lo_d[504]
 PIN n_lo_d[505]
  DIRECTION OUTPUT ;
  USE SIGNAL ;
  PORT
   LAYER M5 ;
   RECT 96.900000 112.236000 96.948000 112.320000 ;
  END
 END n_lo_d[505]
 PIN n_lo_d[506]
  DIRECTION OUTPUT ;
  USE SIGNAL ;
  PORT
   LAYER M5 ;
   RECT 97.476000 112.236000 97.524000 112.320000 ;
  END
 END n_lo_d[506]
 PIN n_lo_d[507]
  DIRECTION OUTPUT ;
  USE SIGNAL ;
  PORT
   LAYER M5 ;
   RECT 97.620000 112.236000 97.668000 112.320000 ;
  END
 END n_lo_d[507]
 PIN n_lo_d[508]
  DIRECTION OUTPUT ;
  USE SIGNAL ;
  PORT
   LAYER M5 ;
   RECT 97.764000 112.236000 97.812000 112.320000 ;
  END
 END n_lo_d[508]
 PIN n_lo_d[509]
  DIRECTION OUTPUT ;
  USE SIGNAL ;
  PORT
   LAYER M5 ;
   RECT 97.956000 112.236000 98.004000 112.320000 ;
  END
 END n_lo_d[509]
 PIN n_lo_d[510]
  DIRECTION OUTPUT ;
  USE SIGNAL ;
  PORT
   LAYER M5 ;
   RECT 98.148000 112.236000 98.196000 112.320000 ;
  END
 END n_lo_d[510]
 PIN n_lo_d[511]
  DIRECTION OUTPUT ;
  USE SIGNAL ;
  PORT
   LAYER M5 ;
   RECT 98.340000 112.236000 98.388000 112.320000 ;
  END
 END n_lo_d[511]
 PIN n_lo_d[512]
  DIRECTION OUTPUT ;
  USE SIGNAL ;
  PORT
   LAYER M5 ;
   RECT 98.484000 112.236000 98.532000 112.320000 ;
  END
 END n_lo_d[512]
 PIN n_lo_d[513]
  DIRECTION OUTPUT ;
  USE SIGNAL ;
  PORT
   LAYER M5 ;
   RECT 98.676000 112.236000 98.724000 112.320000 ;
  END
 END n_lo_d[513]
 PIN n_lo_d[514]
  DIRECTION OUTPUT ;
  USE SIGNAL ;
  PORT
   LAYER M5 ;
   RECT 98.868000 112.236000 98.916000 112.320000 ;
  END
 END n_lo_d[514]
 PIN n_lo_d[515]
  DIRECTION OUTPUT ;
  USE SIGNAL ;
  PORT
   LAYER M5 ;
   RECT 99.060000 112.236000 99.108000 112.320000 ;
  END
 END n_lo_d[515]
 PIN n_lo_d[516]
  DIRECTION OUTPUT ;
  USE SIGNAL ;
  PORT
   LAYER M5 ;
   RECT 99.204000 112.236000 99.252000 112.320000 ;
  END
 END n_lo_d[516]
 PIN n_lo_d[517]
  DIRECTION OUTPUT ;
  USE SIGNAL ;
  PORT
   LAYER M5 ;
   RECT 99.396000 112.236000 99.444000 112.320000 ;
  END
 END n_lo_d[517]
 PIN n_lo_d[518]
  DIRECTION OUTPUT ;
  USE SIGNAL ;
  PORT
   LAYER M5 ;
   RECT 99.588000 112.236000 99.636000 112.320000 ;
  END
 END n_lo_d[518]
 PIN n_lo_d[519]
  DIRECTION OUTPUT ;
  USE SIGNAL ;
  PORT
   LAYER M5 ;
   RECT 99.780000 112.236000 99.828000 112.320000 ;
  END
 END n_lo_d[519]
 PIN n_lo_d[520]
  DIRECTION OUTPUT ;
  USE SIGNAL ;
  PORT
   LAYER M5 ;
   RECT 99.924000 112.236000 99.972000 112.320000 ;
  END
 END n_lo_d[520]
 PIN n_lo_d[521]
  DIRECTION OUTPUT ;
  USE SIGNAL ;
  PORT
   LAYER M5 ;
   RECT 100.116000 112.236000 100.164000 112.320000 ;
  END
 END n_lo_d[521]
 PIN n_lo_d[522]
  DIRECTION OUTPUT ;
  USE SIGNAL ;
  PORT
   LAYER M5 ;
   RECT 100.308000 112.236000 100.356000 112.320000 ;
  END
 END n_lo_d[522]
 PIN n_lo_d[523]
  DIRECTION OUTPUT ;
  USE SIGNAL ;
  PORT
   LAYER M5 ;
   RECT 100.500000 112.236000 100.548000 112.320000 ;
  END
 END n_lo_d[523]
 PIN n_lo_d[524]
  DIRECTION OUTPUT ;
  USE SIGNAL ;
  PORT
   LAYER M5 ;
   RECT 100.644000 112.236000 100.692000 112.320000 ;
  END
 END n_lo_d[524]
 PIN n_lo_d[525]
  DIRECTION OUTPUT ;
  USE SIGNAL ;
  PORT
   LAYER M5 ;
   RECT 100.836000 112.236000 100.884000 112.320000 ;
  END
 END n_lo_d[525]
 PIN n_lo_d[526]
  DIRECTION OUTPUT ;
  USE SIGNAL ;
  PORT
   LAYER M5 ;
   RECT 101.028000 112.236000 101.076000 112.320000 ;
  END
 END n_lo_d[526]
 PIN n_lo_d[527]
  DIRECTION OUTPUT ;
  USE SIGNAL ;
  PORT
   LAYER M5 ;
   RECT 101.124000 112.236000 101.172000 112.320000 ;
  END
 END n_lo_d[527]
 PIN n_lo_d[528]
  DIRECTION OUTPUT ;
  USE SIGNAL ;
  PORT
   LAYER M5 ;
   RECT 101.172000 112.236000 101.220000 112.320000 ;
  END
 END n_lo_d[528]
 PIN n_lo_d[529]
  DIRECTION OUTPUT ;
  USE SIGNAL ;
  PORT
   LAYER M5 ;
   RECT 101.220000 112.236000 101.268000 112.320000 ;
  END
 END n_lo_d[529]
 PIN n_lo_d[530]
  DIRECTION OUTPUT ;
  USE SIGNAL ;
  PORT
   LAYER M5 ;
   RECT 101.796000 112.236000 101.844000 112.320000 ;
  END
 END n_lo_d[530]
 PIN n_lo_d[531]
  DIRECTION OUTPUT ;
  USE SIGNAL ;
  PORT
   LAYER M5 ;
   RECT 101.940000 112.236000 101.988000 112.320000 ;
  END
 END n_lo_d[531]
 PIN n_lo_d[532]
  DIRECTION OUTPUT ;
  USE SIGNAL ;
  PORT
   LAYER M5 ;
   RECT 102.084000 112.236000 102.132000 112.320000 ;
  END
 END n_lo_d[532]
 PIN n_lo_d[533]
  DIRECTION OUTPUT ;
  USE SIGNAL ;
  PORT
   LAYER M5 ;
   RECT 102.276000 112.236000 102.324000 112.320000 ;
  END
 END n_lo_d[533]
 PIN n_lo_d[534]
  DIRECTION OUTPUT ;
  USE SIGNAL ;
  PORT
   LAYER M5 ;
   RECT 102.468000 112.236000 102.516000 112.320000 ;
  END
 END n_lo_d[534]
 PIN n_lo_d[535]
  DIRECTION OUTPUT ;
  USE SIGNAL ;
  PORT
   LAYER M5 ;
   RECT 102.660000 112.236000 102.708000 112.320000 ;
  END
 END n_lo_d[535]
 PIN n_lo_d[536]
  DIRECTION OUTPUT ;
  USE SIGNAL ;
  PORT
   LAYER M5 ;
   RECT 102.804000 112.236000 102.852000 112.320000 ;
  END
 END n_lo_d[536]
 PIN n_lo_d[537]
  DIRECTION OUTPUT ;
  USE SIGNAL ;
  PORT
   LAYER M5 ;
   RECT 102.996000 112.236000 103.044000 112.320000 ;
  END
 END n_lo_d[537]
 PIN n_lo_d[538]
  DIRECTION OUTPUT ;
  USE SIGNAL ;
  PORT
   LAYER M5 ;
   RECT 103.188000 112.236000 103.236000 112.320000 ;
  END
 END n_lo_d[538]
 PIN n_lo_d[539]
  DIRECTION OUTPUT ;
  USE SIGNAL ;
  PORT
   LAYER M5 ;
   RECT 103.380000 112.236000 103.428000 112.320000 ;
  END
 END n_lo_d[539]
 PIN n_lo_d[540]
  DIRECTION OUTPUT ;
  USE SIGNAL ;
  PORT
   LAYER M5 ;
   RECT 103.524000 112.236000 103.572000 112.320000 ;
  END
 END n_lo_d[540]
 PIN n_lo_d[541]
  DIRECTION OUTPUT ;
  USE SIGNAL ;
  PORT
   LAYER M5 ;
   RECT 103.716000 112.236000 103.764000 112.320000 ;
  END
 END n_lo_d[541]
 PIN n_lo_d[542]
  DIRECTION OUTPUT ;
  USE SIGNAL ;
  PORT
   LAYER M5 ;
   RECT 103.908000 112.236000 103.956000 112.320000 ;
  END
 END n_lo_d[542]
 PIN n_lo_d[543]
  DIRECTION OUTPUT ;
  USE SIGNAL ;
  PORT
   LAYER M5 ;
   RECT 104.100000 112.236000 104.148000 112.320000 ;
  END
 END n_lo_d[543]
 PIN n_lo_d[544]
  DIRECTION OUTPUT ;
  USE SIGNAL ;
  PORT
   LAYER M5 ;
   RECT 104.244000 112.236000 104.292000 112.320000 ;
  END
 END n_lo_d[544]
 PIN n_lo_d[545]
  DIRECTION OUTPUT ;
  USE SIGNAL ;
  PORT
   LAYER M5 ;
   RECT 104.436000 112.236000 104.484000 112.320000 ;
  END
 END n_lo_d[545]
 PIN n_lo_d[546]
  DIRECTION OUTPUT ;
  USE SIGNAL ;
  PORT
   LAYER M5 ;
   RECT 104.628000 112.236000 104.676000 112.320000 ;
  END
 END n_lo_d[546]
 PIN n_lo_d[547]
  DIRECTION OUTPUT ;
  USE SIGNAL ;
  PORT
   LAYER M5 ;
   RECT 104.820000 112.236000 104.868000 112.320000 ;
  END
 END n_lo_d[547]
 PIN n_lo_d[548]
  DIRECTION OUTPUT ;
  USE SIGNAL ;
  PORT
   LAYER M5 ;
   RECT 104.964000 112.236000 105.012000 112.320000 ;
  END
 END n_lo_d[548]
 PIN n_lo_d[549]
  DIRECTION OUTPUT ;
  USE SIGNAL ;
  PORT
   LAYER M5 ;
   RECT 105.156000 112.236000 105.204000 112.320000 ;
  END
 END n_lo_d[549]
 PIN n_lo_d[550]
  DIRECTION OUTPUT ;
  USE SIGNAL ;
  PORT
   LAYER M5 ;
   RECT 105.348000 112.236000 105.396000 112.320000 ;
  END
 END n_lo_d[550]
 PIN n_lo_d[551]
  DIRECTION OUTPUT ;
  USE SIGNAL ;
  PORT
   LAYER M5 ;
   RECT 105.444000 112.236000 105.492000 112.320000 ;
  END
 END n_lo_d[551]
 PIN n_lo_d[552]
  DIRECTION OUTPUT ;
  USE SIGNAL ;
  PORT
   LAYER M5 ;
   RECT 105.492000 112.236000 105.540000 112.320000 ;
  END
 END n_lo_d[552]
 PIN n_li_r
  DIRECTION OUTPUT ;
  USE SIGNAL ;
  PORT
   LAYER M5 ;
   RECT 105.540000 112.236000 105.588000 112.320000 ;
  END
 END n_li_r
 PIN n_rxv
  DIRECTION OUTPUT ;
  USE SIGNAL ;
  PORT
   LAYER M5 ;
   RECT 106.116000 112.236000 106.164000 112.320000 ;
  END
 END n_rxv
 PIN rs_k
  DIRECTION INPUT ;
  USE SIGNAL ;
  PORT
   LAYER M5 ;
   RECT 4.308000 0.000000 4.356000 0.084000 ;
  END
 END rs_k
 PIN rs_n
  DIRECTION INPUT ;
  USE SIGNAL ;
  PORT
   LAYER M5 ;
   RECT 107.940000 0.000000 107.988000 0.084000 ;
  END
 END rs_n
 PIN ck_k
  DIRECTION INPUT ;
  USE CLOCK ;
  PORT
   LAYER M5 ;
   RECT 56.148000 55.920000 56.196000 56.400000 ;
  END
 END ck_k
END ot_s81_mu72_lnland_nst_1ck
END LIBRARY
